VERSION 5.8 ;
BUSBITCHARS "[]" ;
DIVIDERCHAR "/" ;
UNITS
    DATABASE MICRONS 1000 ;
END UNITS

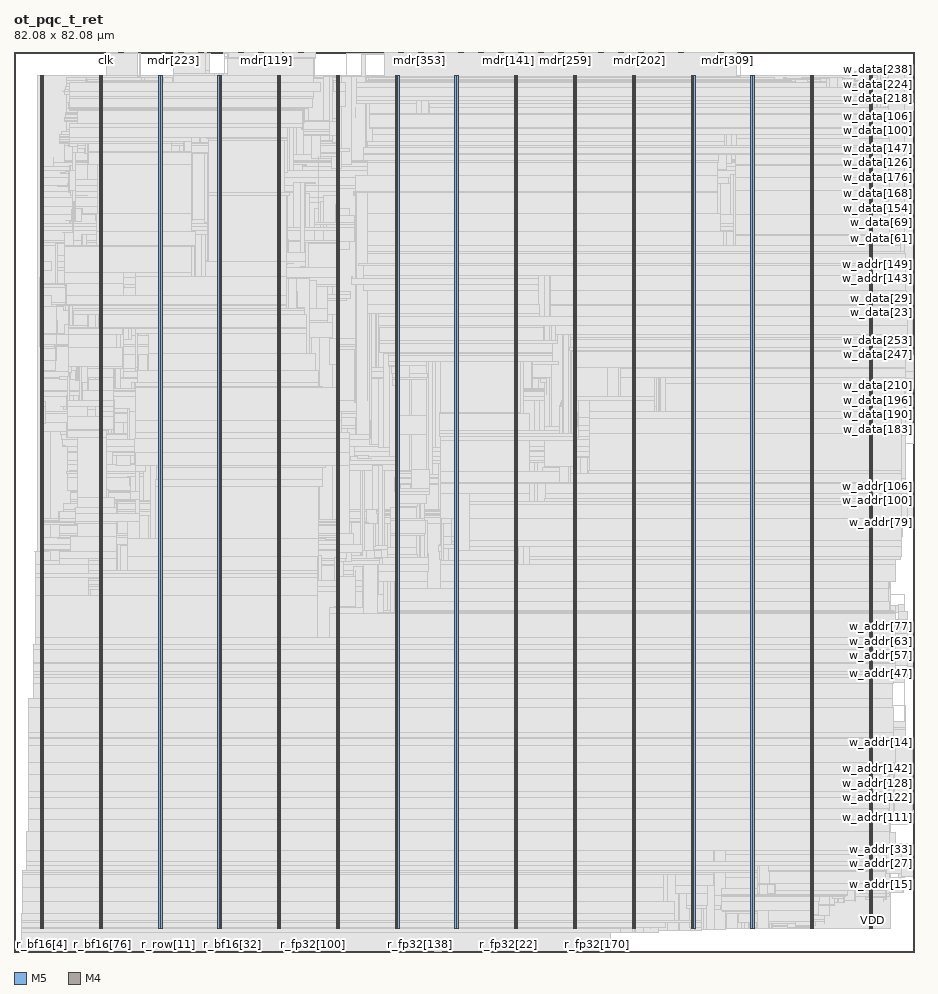
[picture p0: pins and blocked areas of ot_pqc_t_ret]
MACRO ot_pqc_t_ret
  FOREIGN ot_pqc_t_ret 0 0 ;
  CLASS BLOCK ;
  SIZE 82.08 BY 82.08 ;
  PIN clk
    DIRECTION INPUT ;
    USE SIGNAL ;
    PORT
      LAYER M5 ;
        RECT  8.4 81.996 8.424 82.08 ;
    END
  END clk
  PIN ga[0]
    DIRECTION OUTPUT ;
    USE SIGNAL ;
    PORT
      LAYER M4 ;
        RECT  81.996 16.08 82.08 16.104 ;
    END
  END ga[0]
  PIN ga[10]
    DIRECTION OUTPUT ;
    USE SIGNAL ;
    PORT
      LAYER M4 ;
        RECT  81.996 17.04 82.08 17.064 ;
    END
  END ga[10]
  PIN ga[11]
    DIRECTION OUTPUT ;
    USE SIGNAL ;
    PORT
      LAYER M4 ;
        RECT  81.996 17.136 82.08 17.16 ;
    END
  END ga[11]
  PIN ga[12]
    DIRECTION OUTPUT ;
    USE SIGNAL ;
    PORT
      LAYER M4 ;
        RECT  81.996 17.232 82.08 17.256 ;
    END
  END ga[12]
  PIN ga[13]
    DIRECTION OUTPUT ;
    USE SIGNAL ;
    PORT
      LAYER M4 ;
        RECT  81.996 17.328 82.08 17.352 ;
    END
  END ga[13]
  PIN ga[14]
    DIRECTION OUTPUT ;
    USE SIGNAL ;
    PORT
      LAYER M4 ;
        RECT  81.996 17.424 82.08 17.448 ;
    END
  END ga[14]
  PIN ga[15]
    DIRECTION OUTPUT ;
    USE SIGNAL ;
    PORT
      LAYER M4 ;
        RECT  81.996 17.52 82.08 17.544 ;
    END
  END ga[15]
  PIN ga[1]
    DIRECTION OUTPUT ;
    USE SIGNAL ;
    PORT
      LAYER M4 ;
        RECT  81.996 16.176 82.08 16.2 ;
    END
  END ga[1]
  PIN ga[2]
    DIRECTION OUTPUT ;
    USE SIGNAL ;
    PORT
      LAYER M4 ;
        RECT  81.996 16.272 82.08 16.296 ;
    END
  END ga[2]
  PIN ga[3]
    DIRECTION OUTPUT ;
    USE SIGNAL ;
    PORT
      LAYER M4 ;
        RECT  81.996 16.368 82.08 16.392 ;
    END
  END ga[3]
  PIN ga[4]
    DIRECTION OUTPUT ;
    USE SIGNAL ;
    PORT
      LAYER M4 ;
        RECT  81.996 16.464 82.08 16.488 ;
    END
  END ga[4]
  PIN ga[5]
    DIRECTION OUTPUT ;
    USE SIGNAL ;
    PORT
      LAYER M4 ;
        RECT  81.996 16.56 82.08 16.584 ;
    END
  END ga[5]
  PIN ga[6]
    DIRECTION OUTPUT ;
    USE SIGNAL ;
    PORT
      LAYER M4 ;
        RECT  81.996 16.656 82.08 16.68 ;
    END
  END ga[6]
  PIN ga[7]
    DIRECTION OUTPUT ;
    USE SIGNAL ;
    PORT
      LAYER M4 ;
        RECT  81.996 16.752 82.08 16.776 ;
    END
  END ga[7]
  PIN ga[8]
    DIRECTION OUTPUT ;
    USE SIGNAL ;
    PORT
      LAYER M4 ;
        RECT  81.996 16.848 82.08 16.872 ;
    END
  END ga[8]
  PIN ga[9]
    DIRECTION OUTPUT ;
    USE SIGNAL ;
    PORT
      LAYER M4 ;
        RECT  81.996 16.944 82.08 16.968 ;
    END
  END ga[9]
  PIN mdr[0]
    DIRECTION INPUT ;
    USE SIGNAL ;
    PORT
      LAYER M5 ;
        RECT  8.496 81.996 8.52 82.08 ;
    END
  END mdr[0]
  PIN mdr[100]
    DIRECTION INPUT ;
    USE SIGNAL ;
    PORT
      LAYER M5 ;
        RECT  21.168 81.996 21.192 82.08 ;
    END
  END mdr[100]
  PIN mdr[101]
    DIRECTION INPUT ;
    USE SIGNAL ;
    PORT
      LAYER M5 ;
        RECT  21.264 81.996 21.288 82.08 ;
    END
  END mdr[101]
  PIN mdr[102]
    DIRECTION INPUT ;
    USE SIGNAL ;
    PORT
      LAYER M5 ;
        RECT  21.36 81.996 21.384 82.08 ;
    END
  END mdr[102]
  PIN mdr[103]
    DIRECTION INPUT ;
    USE SIGNAL ;
    PORT
      LAYER M5 ;
        RECT  21.456 81.996 21.48 82.08 ;
    END
  END mdr[103]
  PIN mdr[104]
    DIRECTION INPUT ;
    USE SIGNAL ;
    PORT
      LAYER M5 ;
        RECT  21.552 81.996 21.576 82.08 ;
    END
  END mdr[104]
  PIN mdr[105]
    DIRECTION INPUT ;
    USE SIGNAL ;
    PORT
      LAYER M5 ;
        RECT  21.648 81.996 21.672 82.08 ;
    END
  END mdr[105]
  PIN mdr[106]
    DIRECTION INPUT ;
    USE SIGNAL ;
    PORT
      LAYER M5 ;
        RECT  21.744 81.996 21.768 82.08 ;
    END
  END mdr[106]
  PIN mdr[107]
    DIRECTION INPUT ;
    USE SIGNAL ;
    PORT
      LAYER M5 ;
        RECT  21.84 81.996 21.864 82.08 ;
    END
  END mdr[107]
  PIN mdr[108]
    DIRECTION INPUT ;
    USE SIGNAL ;
    PORT
      LAYER M5 ;
        RECT  21.936 81.996 21.96 82.08 ;
    END
  END mdr[108]
  PIN mdr[109]
    DIRECTION INPUT ;
    USE SIGNAL ;
    PORT
      LAYER M5 ;
        RECT  22.032 81.996 22.056 82.08 ;
    END
  END mdr[109]
  PIN mdr[10]
    DIRECTION INPUT ;
    USE SIGNAL ;
    PORT
      LAYER M5 ;
        RECT  9.456 81.996 9.48 82.08 ;
    END
  END mdr[10]
  PIN mdr[110]
    DIRECTION INPUT ;
    USE SIGNAL ;
    PORT
      LAYER M5 ;
        RECT  22.128 81.996 22.152 82.08 ;
    END
  END mdr[110]
  PIN mdr[111]
    DIRECTION INPUT ;
    USE SIGNAL ;
    PORT
      LAYER M5 ;
        RECT  22.224 81.996 22.248 82.08 ;
    END
  END mdr[111]
  PIN mdr[112]
    DIRECTION INPUT ;
    USE SIGNAL ;
    PORT
      LAYER M5 ;
        RECT  22.32 81.996 22.344 82.08 ;
    END
  END mdr[112]
  PIN mdr[113]
    DIRECTION INPUT ;
    USE SIGNAL ;
    PORT
      LAYER M5 ;
        RECT  22.416 81.996 22.44 82.08 ;
    END
  END mdr[113]
  PIN mdr[114]
    DIRECTION INPUT ;
    USE SIGNAL ;
    PORT
      LAYER M5 ;
        RECT  22.512 81.996 22.536 82.08 ;
    END
  END mdr[114]
  PIN mdr[115]
    DIRECTION INPUT ;
    USE SIGNAL ;
    PORT
      LAYER M5 ;
        RECT  22.608 81.996 22.632 82.08 ;
    END
  END mdr[115]
  PIN mdr[116]
    DIRECTION INPUT ;
    USE SIGNAL ;
    PORT
      LAYER M5 ;
        RECT  22.704 81.996 22.728 82.08 ;
    END
  END mdr[116]
  PIN mdr[117]
    DIRECTION INPUT ;
    USE SIGNAL ;
    PORT
      LAYER M5 ;
        RECT  22.8 81.996 22.824 82.08 ;
    END
  END mdr[117]
  PIN mdr[118]
    DIRECTION INPUT ;
    USE SIGNAL ;
    PORT
      LAYER M5 ;
        RECT  22.896 81.996 22.92 82.08 ;
    END
  END mdr[118]
  PIN mdr[119]
    DIRECTION INPUT ;
    USE SIGNAL ;
    PORT
      LAYER M5 ;
        RECT  22.992 81.996 23.016 82.08 ;
    END
  END mdr[119]
  PIN mdr[11]
    DIRECTION INPUT ;
    USE SIGNAL ;
    PORT
      LAYER M5 ;
        RECT  9.552 81.996 9.576 82.08 ;
    END
  END mdr[11]
  PIN mdr[120]
    DIRECTION INPUT ;
    USE SIGNAL ;
    PORT
      LAYER M5 ;
        RECT  23.088 81.996 23.112 82.08 ;
    END
  END mdr[120]
  PIN mdr[121]
    DIRECTION INPUT ;
    USE SIGNAL ;
    PORT
      LAYER M5 ;
        RECT  23.184 81.996 23.208 82.08 ;
    END
  END mdr[121]
  PIN mdr[122]
    DIRECTION INPUT ;
    USE SIGNAL ;
    PORT
      LAYER M5 ;
        RECT  23.28 81.996 23.304 82.08 ;
    END
  END mdr[122]
  PIN mdr[123]
    DIRECTION INPUT ;
    USE SIGNAL ;
    PORT
      LAYER M5 ;
        RECT  23.376 81.996 23.4 82.08 ;
    END
  END mdr[123]
  PIN mdr[124]
    DIRECTION INPUT ;
    USE SIGNAL ;
    PORT
      LAYER M5 ;
        RECT  23.472 81.996 23.496 82.08 ;
    END
  END mdr[124]
  PIN mdr[125]
    DIRECTION INPUT ;
    USE SIGNAL ;
    PORT
      LAYER M5 ;
        RECT  23.568 81.996 23.592 82.08 ;
    END
  END mdr[125]
  PIN mdr[126]
    DIRECTION INPUT ;
    USE SIGNAL ;
    PORT
      LAYER M5 ;
        RECT  23.664 81.996 23.688 82.08 ;
    END
  END mdr[126]
  PIN mdr[127]
    DIRECTION INPUT ;
    USE SIGNAL ;
    PORT
      LAYER M5 ;
        RECT  43.728 81.996 43.752 82.08 ;
    END
  END mdr[127]
  PIN mdr[128]
    DIRECTION INPUT ;
    USE SIGNAL ;
    PORT
      LAYER M5 ;
        RECT  43.824 81.996 43.848 82.08 ;
    END
  END mdr[128]
  PIN mdr[129]
    DIRECTION INPUT ;
    USE SIGNAL ;
    PORT
      LAYER M5 ;
        RECT  43.92 81.996 43.944 82.08 ;
    END
  END mdr[129]
  PIN mdr[12]
    DIRECTION INPUT ;
    USE SIGNAL ;
    PORT
      LAYER M5 ;
        RECT  9.648 81.996 9.672 82.08 ;
    END
  END mdr[12]
  PIN mdr[130]
    DIRECTION INPUT ;
    USE SIGNAL ;
    PORT
      LAYER M5 ;
        RECT  44.016 81.996 44.04 82.08 ;
    END
  END mdr[130]
  PIN mdr[131]
    DIRECTION INPUT ;
    USE SIGNAL ;
    PORT
      LAYER M5 ;
        RECT  44.112 81.996 44.136 82.08 ;
    END
  END mdr[131]
  PIN mdr[132]
    DIRECTION INPUT ;
    USE SIGNAL ;
    PORT
      LAYER M5 ;
        RECT  44.208 81.996 44.232 82.08 ;
    END
  END mdr[132]
  PIN mdr[133]
    DIRECTION INPUT ;
    USE SIGNAL ;
    PORT
      LAYER M5 ;
        RECT  44.304 81.996 44.328 82.08 ;
    END
  END mdr[133]
  PIN mdr[134]
    DIRECTION INPUT ;
    USE SIGNAL ;
    PORT
      LAYER M5 ;
        RECT  44.4 81.996 44.424 82.08 ;
    END
  END mdr[134]
  PIN mdr[135]
    DIRECTION INPUT ;
    USE SIGNAL ;
    PORT
      LAYER M5 ;
        RECT  44.496 81.996 44.52 82.08 ;
    END
  END mdr[135]
  PIN mdr[136]
    DIRECTION INPUT ;
    USE SIGNAL ;
    PORT
      LAYER M5 ;
        RECT  44.592 81.996 44.616 82.08 ;
    END
  END mdr[136]
  PIN mdr[137]
    DIRECTION INPUT ;
    USE SIGNAL ;
    PORT
      LAYER M5 ;
        RECT  44.688 81.996 44.712 82.08 ;
    END
  END mdr[137]
  PIN mdr[138]
    DIRECTION INPUT ;
    USE SIGNAL ;
    PORT
      LAYER M5 ;
        RECT  44.784 81.996 44.808 82.08 ;
    END
  END mdr[138]
  PIN mdr[139]
    DIRECTION INPUT ;
    USE SIGNAL ;
    PORT
      LAYER M5 ;
        RECT  44.88 81.996 44.904 82.08 ;
    END
  END mdr[139]
  PIN mdr[13]
    DIRECTION INPUT ;
    USE SIGNAL ;
    PORT
      LAYER M5 ;
        RECT  9.744 81.996 9.768 82.08 ;
    END
  END mdr[13]
  PIN mdr[140]
    DIRECTION INPUT ;
    USE SIGNAL ;
    PORT
      LAYER M5 ;
        RECT  44.976 81.996 45 82.08 ;
    END
  END mdr[140]
  PIN mdr[141]
    DIRECTION INPUT ;
    USE SIGNAL ;
    PORT
      LAYER M5 ;
        RECT  45.072 81.996 45.096 82.08 ;
    END
  END mdr[141]
  PIN mdr[142]
    DIRECTION INPUT ;
    USE SIGNAL ;
    PORT
      LAYER M5 ;
        RECT  45.168 81.996 45.192 82.08 ;
    END
  END mdr[142]
  PIN mdr[143]
    DIRECTION INPUT ;
    USE SIGNAL ;
    PORT
      LAYER M5 ;
        RECT  45.264 81.996 45.288 82.08 ;
    END
  END mdr[143]
  PIN mdr[144]
    DIRECTION INPUT ;
    USE SIGNAL ;
    PORT
      LAYER M5 ;
        RECT  45.36 81.996 45.384 82.08 ;
    END
  END mdr[144]
  PIN mdr[145]
    DIRECTION INPUT ;
    USE SIGNAL ;
    PORT
      LAYER M5 ;
        RECT  45.456 81.996 45.48 82.08 ;
    END
  END mdr[145]
  PIN mdr[146]
    DIRECTION INPUT ;
    USE SIGNAL ;
    PORT
      LAYER M5 ;
        RECT  45.552 81.996 45.576 82.08 ;
    END
  END mdr[146]
  PIN mdr[147]
    DIRECTION INPUT ;
    USE SIGNAL ;
    PORT
      LAYER M5 ;
        RECT  45.648 81.996 45.672 82.08 ;
    END
  END mdr[147]
  PIN mdr[148]
    DIRECTION INPUT ;
    USE SIGNAL ;
    PORT
      LAYER M5 ;
        RECT  45.744 81.996 45.768 82.08 ;
    END
  END mdr[148]
  PIN mdr[149]
    DIRECTION INPUT ;
    USE SIGNAL ;
    PORT
      LAYER M5 ;
        RECT  45.84 81.996 45.864 82.08 ;
    END
  END mdr[149]
  PIN mdr[14]
    DIRECTION INPUT ;
    USE SIGNAL ;
    PORT
      LAYER M5 ;
        RECT  9.84 81.996 9.864 82.08 ;
    END
  END mdr[14]
  PIN mdr[150]
    DIRECTION INPUT ;
    USE SIGNAL ;
    PORT
      LAYER M5 ;
        RECT  45.936 81.996 45.96 82.08 ;
    END
  END mdr[150]
  PIN mdr[151]
    DIRECTION INPUT ;
    USE SIGNAL ;
    PORT
      LAYER M5 ;
        RECT  46.032 81.996 46.056 82.08 ;
    END
  END mdr[151]
  PIN mdr[152]
    DIRECTION INPUT ;
    USE SIGNAL ;
    PORT
      LAYER M5 ;
        RECT  46.128 81.996 46.152 82.08 ;
    END
  END mdr[152]
  PIN mdr[153]
    DIRECTION INPUT ;
    USE SIGNAL ;
    PORT
      LAYER M5 ;
        RECT  46.224 81.996 46.248 82.08 ;
    END
  END mdr[153]
  PIN mdr[154]
    DIRECTION INPUT ;
    USE SIGNAL ;
    PORT
      LAYER M5 ;
        RECT  46.32 81.996 46.344 82.08 ;
    END
  END mdr[154]
  PIN mdr[155]
    DIRECTION INPUT ;
    USE SIGNAL ;
    PORT
      LAYER M5 ;
        RECT  46.416 81.996 46.44 82.08 ;
    END
  END mdr[155]
  PIN mdr[156]
    DIRECTION INPUT ;
    USE SIGNAL ;
    PORT
      LAYER M5 ;
        RECT  46.512 81.996 46.536 82.08 ;
    END
  END mdr[156]
  PIN mdr[157]
    DIRECTION INPUT ;
    USE SIGNAL ;
    PORT
      LAYER M5 ;
        RECT  46.608 81.996 46.632 82.08 ;
    END
  END mdr[157]
  PIN mdr[158]
    DIRECTION INPUT ;
    USE SIGNAL ;
    PORT
      LAYER M5 ;
        RECT  46.704 81.996 46.728 82.08 ;
    END
  END mdr[158]
  PIN mdr[159]
    DIRECTION INPUT ;
    USE SIGNAL ;
    PORT
      LAYER M5 ;
        RECT  46.8 81.996 46.824 82.08 ;
    END
  END mdr[159]
  PIN mdr[15]
    DIRECTION INPUT ;
    USE SIGNAL ;
    PORT
      LAYER M5 ;
        RECT  9.936 81.996 9.96 82.08 ;
    END
  END mdr[15]
  PIN mdr[160]
    DIRECTION INPUT ;
    USE SIGNAL ;
    PORT
      LAYER M5 ;
        RECT  46.896 81.996 46.92 82.08 ;
    END
  END mdr[160]
  PIN mdr[161]
    DIRECTION INPUT ;
    USE SIGNAL ;
    PORT
      LAYER M5 ;
        RECT  46.992 81.996 47.016 82.08 ;
    END
  END mdr[161]
  PIN mdr[162]
    DIRECTION INPUT ;
    USE SIGNAL ;
    PORT
      LAYER M5 ;
        RECT  47.088 81.996 47.112 82.08 ;
    END
  END mdr[162]
  PIN mdr[163]
    DIRECTION INPUT ;
    USE SIGNAL ;
    PORT
      LAYER M5 ;
        RECT  47.184 81.996 47.208 82.08 ;
    END
  END mdr[163]
  PIN mdr[164]
    DIRECTION INPUT ;
    USE SIGNAL ;
    PORT
      LAYER M5 ;
        RECT  47.28 81.996 47.304 82.08 ;
    END
  END mdr[164]
  PIN mdr[165]
    DIRECTION INPUT ;
    USE SIGNAL ;
    PORT
      LAYER M5 ;
        RECT  47.376 81.996 47.4 82.08 ;
    END
  END mdr[165]
  PIN mdr[166]
    DIRECTION INPUT ;
    USE SIGNAL ;
    PORT
      LAYER M5 ;
        RECT  47.472 81.996 47.496 82.08 ;
    END
  END mdr[166]
  PIN mdr[167]
    DIRECTION INPUT ;
    USE SIGNAL ;
    PORT
      LAYER M5 ;
        RECT  47.568 81.996 47.592 82.08 ;
    END
  END mdr[167]
  PIN mdr[168]
    DIRECTION INPUT ;
    USE SIGNAL ;
    PORT
      LAYER M5 ;
        RECT  47.664 81.996 47.688 82.08 ;
    END
  END mdr[168]
  PIN mdr[169]
    DIRECTION INPUT ;
    USE SIGNAL ;
    PORT
      LAYER M5 ;
        RECT  47.76 81.996 47.784 82.08 ;
    END
  END mdr[169]
  PIN mdr[16]
    DIRECTION INPUT ;
    USE SIGNAL ;
    PORT
      LAYER M5 ;
        RECT  10.032 81.996 10.056 82.08 ;
    END
  END mdr[16]
  PIN mdr[170]
    DIRECTION INPUT ;
    USE SIGNAL ;
    PORT
      LAYER M5 ;
        RECT  47.856 81.996 47.88 82.08 ;
    END
  END mdr[170]
  PIN mdr[171]
    DIRECTION INPUT ;
    USE SIGNAL ;
    PORT
      LAYER M5 ;
        RECT  47.952 81.996 47.976 82.08 ;
    END
  END mdr[171]
  PIN mdr[172]
    DIRECTION INPUT ;
    USE SIGNAL ;
    PORT
      LAYER M5 ;
        RECT  48.048 81.996 48.072 82.08 ;
    END
  END mdr[172]
  PIN mdr[173]
    DIRECTION INPUT ;
    USE SIGNAL ;
    PORT
      LAYER M5 ;
        RECT  48.144 81.996 48.168 82.08 ;
    END
  END mdr[173]
  PIN mdr[174]
    DIRECTION INPUT ;
    USE SIGNAL ;
    PORT
      LAYER M5 ;
        RECT  48.24 81.996 48.264 82.08 ;
    END
  END mdr[174]
  PIN mdr[175]
    DIRECTION INPUT ;
    USE SIGNAL ;
    PORT
      LAYER M5 ;
        RECT  48.336 81.996 48.36 82.08 ;
    END
  END mdr[175]
  PIN mdr[176]
    DIRECTION INPUT ;
    USE SIGNAL ;
    PORT
      LAYER M5 ;
        RECT  48.432 81.996 48.456 82.08 ;
    END
  END mdr[176]
  PIN mdr[177]
    DIRECTION INPUT ;
    USE SIGNAL ;
    PORT
      LAYER M5 ;
        RECT  48.528 81.996 48.552 82.08 ;
    END
  END mdr[177]
  PIN mdr[178]
    DIRECTION INPUT ;
    USE SIGNAL ;
    PORT
      LAYER M5 ;
        RECT  48.624 81.996 48.648 82.08 ;
    END
  END mdr[178]
  PIN mdr[179]
    DIRECTION INPUT ;
    USE SIGNAL ;
    PORT
      LAYER M5 ;
        RECT  48.72 81.996 48.744 82.08 ;
    END
  END mdr[179]
  PIN mdr[17]
    DIRECTION INPUT ;
    USE SIGNAL ;
    PORT
      LAYER M5 ;
        RECT  10.128 81.996 10.152 82.08 ;
    END
  END mdr[17]
  PIN mdr[180]
    DIRECTION INPUT ;
    USE SIGNAL ;
    PORT
      LAYER M5 ;
        RECT  48.816 81.996 48.84 82.08 ;
    END
  END mdr[180]
  PIN mdr[181]
    DIRECTION INPUT ;
    USE SIGNAL ;
    PORT
      LAYER M5 ;
        RECT  48.912 81.996 48.936 82.08 ;
    END
  END mdr[181]
  PIN mdr[182]
    DIRECTION INPUT ;
    USE SIGNAL ;
    PORT
      LAYER M5 ;
        RECT  49.008 81.996 49.032 82.08 ;
    END
  END mdr[182]
  PIN mdr[183]
    DIRECTION INPUT ;
    USE SIGNAL ;
    PORT
      LAYER M5 ;
        RECT  49.104 81.996 49.128 82.08 ;
    END
  END mdr[183]
  PIN mdr[184]
    DIRECTION INPUT ;
    USE SIGNAL ;
    PORT
      LAYER M5 ;
        RECT  49.2 81.996 49.224 82.08 ;
    END
  END mdr[184]
  PIN mdr[185]
    DIRECTION INPUT ;
    USE SIGNAL ;
    PORT
      LAYER M5 ;
        RECT  49.296 81.996 49.32 82.08 ;
    END
  END mdr[185]
  PIN mdr[186]
    DIRECTION INPUT ;
    USE SIGNAL ;
    PORT
      LAYER M5 ;
        RECT  49.392 81.996 49.416 82.08 ;
    END
  END mdr[186]
  PIN mdr[187]
    DIRECTION INPUT ;
    USE SIGNAL ;
    PORT
      LAYER M5 ;
        RECT  49.488 81.996 49.512 82.08 ;
    END
  END mdr[187]
  PIN mdr[188]
    DIRECTION INPUT ;
    USE SIGNAL ;
    PORT
      LAYER M5 ;
        RECT  49.584 81.996 49.608 82.08 ;
    END
  END mdr[188]
  PIN mdr[189]
    DIRECTION INPUT ;
    USE SIGNAL ;
    PORT
      LAYER M5 ;
        RECT  49.68 81.996 49.704 82.08 ;
    END
  END mdr[189]
  PIN mdr[18]
    DIRECTION INPUT ;
    USE SIGNAL ;
    PORT
      LAYER M5 ;
        RECT  10.224 81.996 10.248 82.08 ;
    END
  END mdr[18]
  PIN mdr[190]
    DIRECTION INPUT ;
    USE SIGNAL ;
    PORT
      LAYER M5 ;
        RECT  49.776 81.996 49.8 82.08 ;
    END
  END mdr[190]
  PIN mdr[191]
    DIRECTION INPUT ;
    USE SIGNAL ;
    PORT
      LAYER M5 ;
        RECT  56.016 81.996 56.04 82.08 ;
    END
  END mdr[191]
  PIN mdr[192]
    DIRECTION INPUT ;
    USE SIGNAL ;
    PORT
      LAYER M5 ;
        RECT  56.112 81.996 56.136 82.08 ;
    END
  END mdr[192]
  PIN mdr[193]
    DIRECTION INPUT ;
    USE SIGNAL ;
    PORT
      LAYER M5 ;
        RECT  56.208 81.996 56.232 82.08 ;
    END
  END mdr[193]
  PIN mdr[194]
    DIRECTION INPUT ;
    USE SIGNAL ;
    PORT
      LAYER M5 ;
        RECT  56.304 81.996 56.328 82.08 ;
    END
  END mdr[194]
  PIN mdr[195]
    DIRECTION INPUT ;
    USE SIGNAL ;
    PORT
      LAYER M5 ;
        RECT  56.4 81.996 56.424 82.08 ;
    END
  END mdr[195]
  PIN mdr[196]
    DIRECTION INPUT ;
    USE SIGNAL ;
    PORT
      LAYER M5 ;
        RECT  56.496 81.996 56.52 82.08 ;
    END
  END mdr[196]
  PIN mdr[197]
    DIRECTION INPUT ;
    USE SIGNAL ;
    PORT
      LAYER M5 ;
        RECT  56.592 81.996 56.616 82.08 ;
    END
  END mdr[197]
  PIN mdr[198]
    DIRECTION INPUT ;
    USE SIGNAL ;
    PORT
      LAYER M5 ;
        RECT  56.688 81.996 56.712 82.08 ;
    END
  END mdr[198]
  PIN mdr[199]
    DIRECTION INPUT ;
    USE SIGNAL ;
    PORT
      LAYER M5 ;
        RECT  56.784 81.996 56.808 82.08 ;
    END
  END mdr[199]
  PIN mdr[19]
    DIRECTION INPUT ;
    USE SIGNAL ;
    PORT
      LAYER M5 ;
        RECT  10.32 81.996 10.344 82.08 ;
    END
  END mdr[19]
  PIN mdr[1]
    DIRECTION INPUT ;
    USE SIGNAL ;
    PORT
      LAYER M5 ;
        RECT  8.592 81.996 8.616 82.08 ;
    END
  END mdr[1]
  PIN mdr[200]
    DIRECTION INPUT ;
    USE SIGNAL ;
    PORT
      LAYER M5 ;
        RECT  56.88 81.996 56.904 82.08 ;
    END
  END mdr[200]
  PIN mdr[201]
    DIRECTION INPUT ;
    USE SIGNAL ;
    PORT
      LAYER M5 ;
        RECT  56.976 81.996 57 82.08 ;
    END
  END mdr[201]
  PIN mdr[202]
    DIRECTION INPUT ;
    USE SIGNAL ;
    PORT
      LAYER M5 ;
        RECT  57.072 81.996 57.096 82.08 ;
    END
  END mdr[202]
  PIN mdr[203]
    DIRECTION INPUT ;
    USE SIGNAL ;
    PORT
      LAYER M5 ;
        RECT  57.168 81.996 57.192 82.08 ;
    END
  END mdr[203]
  PIN mdr[204]
    DIRECTION INPUT ;
    USE SIGNAL ;
    PORT
      LAYER M5 ;
        RECT  57.264 81.996 57.288 82.08 ;
    END
  END mdr[204]
  PIN mdr[205]
    DIRECTION INPUT ;
    USE SIGNAL ;
    PORT
      LAYER M5 ;
        RECT  57.36 81.996 57.384 82.08 ;
    END
  END mdr[205]
  PIN mdr[206]
    DIRECTION INPUT ;
    USE SIGNAL ;
    PORT
      LAYER M5 ;
        RECT  57.456 81.996 57.48 82.08 ;
    END
  END mdr[206]
  PIN mdr[207]
    DIRECTION INPUT ;
    USE SIGNAL ;
    PORT
      LAYER M5 ;
        RECT  57.552 81.996 57.576 82.08 ;
    END
  END mdr[207]
  PIN mdr[208]
    DIRECTION INPUT ;
    USE SIGNAL ;
    PORT
      LAYER M5 ;
        RECT  57.648 81.996 57.672 82.08 ;
    END
  END mdr[208]
  PIN mdr[209]
    DIRECTION INPUT ;
    USE SIGNAL ;
    PORT
      LAYER M5 ;
        RECT  57.744 81.996 57.768 82.08 ;
    END
  END mdr[209]
  PIN mdr[20]
    DIRECTION INPUT ;
    USE SIGNAL ;
    PORT
      LAYER M5 ;
        RECT  10.416 81.996 10.44 82.08 ;
    END
  END mdr[20]
  PIN mdr[210]
    DIRECTION INPUT ;
    USE SIGNAL ;
    PORT
      LAYER M5 ;
        RECT  57.84 81.996 57.864 82.08 ;
    END
  END mdr[210]
  PIN mdr[211]
    DIRECTION INPUT ;
    USE SIGNAL ;
    PORT
      LAYER M5 ;
        RECT  57.936 81.996 57.96 82.08 ;
    END
  END mdr[211]
  PIN mdr[212]
    DIRECTION INPUT ;
    USE SIGNAL ;
    PORT
      LAYER M5 ;
        RECT  58.032 81.996 58.056 82.08 ;
    END
  END mdr[212]
  PIN mdr[213]
    DIRECTION INPUT ;
    USE SIGNAL ;
    PORT
      LAYER M5 ;
        RECT  58.128 81.996 58.152 82.08 ;
    END
  END mdr[213]
  PIN mdr[214]
    DIRECTION INPUT ;
    USE SIGNAL ;
    PORT
      LAYER M5 ;
        RECT  58.224 81.996 58.248 82.08 ;
    END
  END mdr[214]
  PIN mdr[215]
    DIRECTION INPUT ;
    USE SIGNAL ;
    PORT
      LAYER M5 ;
        RECT  58.32 81.996 58.344 82.08 ;
    END
  END mdr[215]
  PIN mdr[216]
    DIRECTION INPUT ;
    USE SIGNAL ;
    PORT
      LAYER M5 ;
        RECT  58.416 81.996 58.44 82.08 ;
    END
  END mdr[216]
  PIN mdr[217]
    DIRECTION INPUT ;
    USE SIGNAL ;
    PORT
      LAYER M5 ;
        RECT  58.512 81.996 58.536 82.08 ;
    END
  END mdr[217]
  PIN mdr[218]
    DIRECTION INPUT ;
    USE SIGNAL ;
    PORT
      LAYER M5 ;
        RECT  58.608 81.996 58.632 82.08 ;
    END
  END mdr[218]
  PIN mdr[219]
    DIRECTION INPUT ;
    USE SIGNAL ;
    PORT
      LAYER M5 ;
        RECT  58.704 81.996 58.728 82.08 ;
    END
  END mdr[219]
  PIN mdr[21]
    DIRECTION INPUT ;
    USE SIGNAL ;
    PORT
      LAYER M5 ;
        RECT  10.512 81.996 10.536 82.08 ;
    END
  END mdr[21]
  PIN mdr[220]
    DIRECTION INPUT ;
    USE SIGNAL ;
    PORT
      LAYER M5 ;
        RECT  58.8 81.996 58.824 82.08 ;
    END
  END mdr[220]
  PIN mdr[221]
    DIRECTION INPUT ;
    USE SIGNAL ;
    PORT
      LAYER M5 ;
        RECT  58.896 81.996 58.92 82.08 ;
    END
  END mdr[221]
  PIN mdr[222]
    DIRECTION INPUT ;
    USE SIGNAL ;
    PORT
      LAYER M5 ;
        RECT  58.992 81.996 59.016 82.08 ;
    END
  END mdr[222]
  PIN mdr[223]
    DIRECTION INPUT ;
    USE SIGNAL ;
    PORT
      LAYER M5 ;
        RECT  14.544 81.996 14.568 82.08 ;
    END
  END mdr[223]
  PIN mdr[224]
    DIRECTION INPUT ;
    USE SIGNAL ;
    PORT
      LAYER M5 ;
        RECT  14.64 81.996 14.664 82.08 ;
    END
  END mdr[224]
  PIN mdr[225]
    DIRECTION INPUT ;
    USE SIGNAL ;
    PORT
      LAYER M5 ;
        RECT  14.736 81.996 14.76 82.08 ;
    END
  END mdr[225]
  PIN mdr[226]
    DIRECTION INPUT ;
    USE SIGNAL ;
    PORT
      LAYER M5 ;
        RECT  14.832 81.996 14.856 82.08 ;
    END
  END mdr[226]
  PIN mdr[227]
    DIRECTION INPUT ;
    USE SIGNAL ;
    PORT
      LAYER M5 ;
        RECT  14.928 81.996 14.952 82.08 ;
    END
  END mdr[227]
  PIN mdr[228]
    DIRECTION INPUT ;
    USE SIGNAL ;
    PORT
      LAYER M5 ;
        RECT  15.024 81.996 15.048 82.08 ;
    END
  END mdr[228]
  PIN mdr[229]
    DIRECTION INPUT ;
    USE SIGNAL ;
    PORT
      LAYER M5 ;
        RECT  15.12 81.996 15.144 82.08 ;
    END
  END mdr[229]
  PIN mdr[22]
    DIRECTION INPUT ;
    USE SIGNAL ;
    PORT
      LAYER M5 ;
        RECT  10.608 81.996 10.632 82.08 ;
    END
  END mdr[22]
  PIN mdr[230]
    DIRECTION INPUT ;
    USE SIGNAL ;
    PORT
      LAYER M5 ;
        RECT  15.216 81.996 15.24 82.08 ;
    END
  END mdr[230]
  PIN mdr[231]
    DIRECTION INPUT ;
    USE SIGNAL ;
    PORT
      LAYER M5 ;
        RECT  15.312 81.996 15.336 82.08 ;
    END
  END mdr[231]
  PIN mdr[232]
    DIRECTION INPUT ;
    USE SIGNAL ;
    PORT
      LAYER M5 ;
        RECT  15.408 81.996 15.432 82.08 ;
    END
  END mdr[232]
  PIN mdr[233]
    DIRECTION INPUT ;
    USE SIGNAL ;
    PORT
      LAYER M5 ;
        RECT  15.504 81.996 15.528 82.08 ;
    END
  END mdr[233]
  PIN mdr[234]
    DIRECTION INPUT ;
    USE SIGNAL ;
    PORT
      LAYER M5 ;
        RECT  15.6 81.996 15.624 82.08 ;
    END
  END mdr[234]
  PIN mdr[235]
    DIRECTION INPUT ;
    USE SIGNAL ;
    PORT
      LAYER M5 ;
        RECT  15.696 81.996 15.72 82.08 ;
    END
  END mdr[235]
  PIN mdr[236]
    DIRECTION INPUT ;
    USE SIGNAL ;
    PORT
      LAYER M5 ;
        RECT  15.792 81.996 15.816 82.08 ;
    END
  END mdr[236]
  PIN mdr[237]
    DIRECTION INPUT ;
    USE SIGNAL ;
    PORT
      LAYER M5 ;
        RECT  15.888 81.996 15.912 82.08 ;
    END
  END mdr[237]
  PIN mdr[238]
    DIRECTION INPUT ;
    USE SIGNAL ;
    PORT
      LAYER M5 ;
        RECT  15.984 81.996 16.008 82.08 ;
    END
  END mdr[238]
  PIN mdr[239]
    DIRECTION INPUT ;
    USE SIGNAL ;
    PORT
      LAYER M5 ;
        RECT  16.08 81.996 16.104 82.08 ;
    END
  END mdr[239]
  PIN mdr[23]
    DIRECTION INPUT ;
    USE SIGNAL ;
    PORT
      LAYER M5 ;
        RECT  10.704 81.996 10.728 82.08 ;
    END
  END mdr[23]
  PIN mdr[240]
    DIRECTION INPUT ;
    USE SIGNAL ;
    PORT
      LAYER M5 ;
        RECT  16.176 81.996 16.2 82.08 ;
    END
  END mdr[240]
  PIN mdr[241]
    DIRECTION INPUT ;
    USE SIGNAL ;
    PORT
      LAYER M5 ;
        RECT  16.272 81.996 16.296 82.08 ;
    END
  END mdr[241]
  PIN mdr[242]
    DIRECTION INPUT ;
    USE SIGNAL ;
    PORT
      LAYER M5 ;
        RECT  16.368 81.996 16.392 82.08 ;
    END
  END mdr[242]
  PIN mdr[243]
    DIRECTION INPUT ;
    USE SIGNAL ;
    PORT
      LAYER M5 ;
        RECT  16.464 81.996 16.488 82.08 ;
    END
  END mdr[243]
  PIN mdr[244]
    DIRECTION INPUT ;
    USE SIGNAL ;
    PORT
      LAYER M5 ;
        RECT  16.56 81.996 16.584 82.08 ;
    END
  END mdr[244]
  PIN mdr[245]
    DIRECTION INPUT ;
    USE SIGNAL ;
    PORT
      LAYER M5 ;
        RECT  16.656 81.996 16.68 82.08 ;
    END
  END mdr[245]
  PIN mdr[246]
    DIRECTION INPUT ;
    USE SIGNAL ;
    PORT
      LAYER M5 ;
        RECT  16.752 81.996 16.776 82.08 ;
    END
  END mdr[246]
  PIN mdr[247]
    DIRECTION INPUT ;
    USE SIGNAL ;
    PORT
      LAYER M5 ;
        RECT  16.848 81.996 16.872 82.08 ;
    END
  END mdr[247]
  PIN mdr[248]
    DIRECTION INPUT ;
    USE SIGNAL ;
    PORT
      LAYER M5 ;
        RECT  16.944 81.996 16.968 82.08 ;
    END
  END mdr[248]
  PIN mdr[249]
    DIRECTION INPUT ;
    USE SIGNAL ;
    PORT
      LAYER M5 ;
        RECT  17.04 81.996 17.064 82.08 ;
    END
  END mdr[249]
  PIN mdr[24]
    DIRECTION INPUT ;
    USE SIGNAL ;
    PORT
      LAYER M5 ;
        RECT  10.8 81.996 10.824 82.08 ;
    END
  END mdr[24]
  PIN mdr[250]
    DIRECTION INPUT ;
    USE SIGNAL ;
    PORT
      LAYER M5 ;
        RECT  17.136 81.996 17.16 82.08 ;
    END
  END mdr[250]
  PIN mdr[251]
    DIRECTION INPUT ;
    USE SIGNAL ;
    PORT
      LAYER M5 ;
        RECT  17.232 81.996 17.256 82.08 ;
    END
  END mdr[251]
  PIN mdr[252]
    DIRECTION INPUT ;
    USE SIGNAL ;
    PORT
      LAYER M5 ;
        RECT  17.328 81.996 17.352 82.08 ;
    END
  END mdr[252]
  PIN mdr[253]
    DIRECTION INPUT ;
    USE SIGNAL ;
    PORT
      LAYER M5 ;
        RECT  17.424 81.996 17.448 82.08 ;
    END
  END mdr[253]
  PIN mdr[254]
    DIRECTION INPUT ;
    USE SIGNAL ;
    PORT
      LAYER M5 ;
        RECT  17.52 81.996 17.544 82.08 ;
    END
  END mdr[254]
  PIN mdr[255]
    DIRECTION INPUT ;
    USE SIGNAL ;
    PORT
      LAYER M5 ;
        RECT  49.872 81.996 49.896 82.08 ;
    END
  END mdr[255]
  PIN mdr[256]
    DIRECTION INPUT ;
    USE SIGNAL ;
    PORT
      LAYER M5 ;
        RECT  49.968 81.996 49.992 82.08 ;
    END
  END mdr[256]
  PIN mdr[257]
    DIRECTION INPUT ;
    USE SIGNAL ;
    PORT
      LAYER M5 ;
        RECT  50.064 81.996 50.088 82.08 ;
    END
  END mdr[257]
  PIN mdr[258]
    DIRECTION INPUT ;
    USE SIGNAL ;
    PORT
      LAYER M5 ;
        RECT  50.16 81.996 50.184 82.08 ;
    END
  END mdr[258]
  PIN mdr[259]
    DIRECTION INPUT ;
    USE SIGNAL ;
    PORT
      LAYER M5 ;
        RECT  50.256 81.996 50.28 82.08 ;
    END
  END mdr[259]
  PIN mdr[25]
    DIRECTION INPUT ;
    USE SIGNAL ;
    PORT
      LAYER M5 ;
        RECT  10.896 81.996 10.92 82.08 ;
    END
  END mdr[25]
  PIN mdr[260]
    DIRECTION INPUT ;
    USE SIGNAL ;
    PORT
      LAYER M5 ;
        RECT  50.352 81.996 50.376 82.08 ;
    END
  END mdr[260]
  PIN mdr[261]
    DIRECTION INPUT ;
    USE SIGNAL ;
    PORT
      LAYER M5 ;
        RECT  50.448 81.996 50.472 82.08 ;
    END
  END mdr[261]
  PIN mdr[262]
    DIRECTION INPUT ;
    USE SIGNAL ;
    PORT
      LAYER M5 ;
        RECT  50.544 81.996 50.568 82.08 ;
    END
  END mdr[262]
  PIN mdr[263]
    DIRECTION INPUT ;
    USE SIGNAL ;
    PORT
      LAYER M5 ;
        RECT  50.64 81.996 50.664 82.08 ;
    END
  END mdr[263]
  PIN mdr[264]
    DIRECTION INPUT ;
    USE SIGNAL ;
    PORT
      LAYER M5 ;
        RECT  50.736 81.996 50.76 82.08 ;
    END
  END mdr[264]
  PIN mdr[265]
    DIRECTION INPUT ;
    USE SIGNAL ;
    PORT
      LAYER M5 ;
        RECT  50.832 81.996 50.856 82.08 ;
    END
  END mdr[265]
  PIN mdr[266]
    DIRECTION INPUT ;
    USE SIGNAL ;
    PORT
      LAYER M5 ;
        RECT  50.928 81.996 50.952 82.08 ;
    END
  END mdr[266]
  PIN mdr[267]
    DIRECTION INPUT ;
    USE SIGNAL ;
    PORT
      LAYER M5 ;
        RECT  51.024 81.996 51.048 82.08 ;
    END
  END mdr[267]
  PIN mdr[268]
    DIRECTION INPUT ;
    USE SIGNAL ;
    PORT
      LAYER M5 ;
        RECT  51.12 81.996 51.144 82.08 ;
    END
  END mdr[268]
  PIN mdr[269]
    DIRECTION INPUT ;
    USE SIGNAL ;
    PORT
      LAYER M5 ;
        RECT  51.216 81.996 51.24 82.08 ;
    END
  END mdr[269]
  PIN mdr[26]
    DIRECTION INPUT ;
    USE SIGNAL ;
    PORT
      LAYER M5 ;
        RECT  10.992 81.996 11.016 82.08 ;
    END
  END mdr[26]
  PIN mdr[270]
    DIRECTION INPUT ;
    USE SIGNAL ;
    PORT
      LAYER M5 ;
        RECT  51.312 81.996 51.336 82.08 ;
    END
  END mdr[270]
  PIN mdr[271]
    DIRECTION INPUT ;
    USE SIGNAL ;
    PORT
      LAYER M5 ;
        RECT  51.408 81.996 51.432 82.08 ;
    END
  END mdr[271]
  PIN mdr[272]
    DIRECTION INPUT ;
    USE SIGNAL ;
    PORT
      LAYER M5 ;
        RECT  51.504 81.996 51.528 82.08 ;
    END
  END mdr[272]
  PIN mdr[273]
    DIRECTION INPUT ;
    USE SIGNAL ;
    PORT
      LAYER M5 ;
        RECT  51.6 81.996 51.624 82.08 ;
    END
  END mdr[273]
  PIN mdr[274]
    DIRECTION INPUT ;
    USE SIGNAL ;
    PORT
      LAYER M5 ;
        RECT  51.696 81.996 51.72 82.08 ;
    END
  END mdr[274]
  PIN mdr[275]
    DIRECTION INPUT ;
    USE SIGNAL ;
    PORT
      LAYER M5 ;
        RECT  51.792 81.996 51.816 82.08 ;
    END
  END mdr[275]
  PIN mdr[276]
    DIRECTION INPUT ;
    USE SIGNAL ;
    PORT
      LAYER M5 ;
        RECT  51.888 81.996 51.912 82.08 ;
    END
  END mdr[276]
  PIN mdr[277]
    DIRECTION INPUT ;
    USE SIGNAL ;
    PORT
      LAYER M5 ;
        RECT  51.984 81.996 52.008 82.08 ;
    END
  END mdr[277]
  PIN mdr[278]
    DIRECTION INPUT ;
    USE SIGNAL ;
    PORT
      LAYER M5 ;
        RECT  52.08 81.996 52.104 82.08 ;
    END
  END mdr[278]
  PIN mdr[279]
    DIRECTION INPUT ;
    USE SIGNAL ;
    PORT
      LAYER M5 ;
        RECT  52.176 81.996 52.2 82.08 ;
    END
  END mdr[279]
  PIN mdr[27]
    DIRECTION INPUT ;
    USE SIGNAL ;
    PORT
      LAYER M5 ;
        RECT  11.088 81.996 11.112 82.08 ;
    END
  END mdr[27]
  PIN mdr[280]
    DIRECTION INPUT ;
    USE SIGNAL ;
    PORT
      LAYER M5 ;
        RECT  52.272 81.996 52.296 82.08 ;
    END
  END mdr[280]
  PIN mdr[281]
    DIRECTION INPUT ;
    USE SIGNAL ;
    PORT
      LAYER M5 ;
        RECT  52.368 81.996 52.392 82.08 ;
    END
  END mdr[281]
  PIN mdr[282]
    DIRECTION INPUT ;
    USE SIGNAL ;
    PORT
      LAYER M5 ;
        RECT  52.464 81.996 52.488 82.08 ;
    END
  END mdr[282]
  PIN mdr[283]
    DIRECTION INPUT ;
    USE SIGNAL ;
    PORT
      LAYER M5 ;
        RECT  52.56 81.996 52.584 82.08 ;
    END
  END mdr[283]
  PIN mdr[284]
    DIRECTION INPUT ;
    USE SIGNAL ;
    PORT
      LAYER M5 ;
        RECT  52.656 81.996 52.68 82.08 ;
    END
  END mdr[284]
  PIN mdr[285]
    DIRECTION INPUT ;
    USE SIGNAL ;
    PORT
      LAYER M5 ;
        RECT  52.752 81.996 52.776 82.08 ;
    END
  END mdr[285]
  PIN mdr[286]
    DIRECTION INPUT ;
    USE SIGNAL ;
    PORT
      LAYER M5 ;
        RECT  52.848 81.996 52.872 82.08 ;
    END
  END mdr[286]
  PIN mdr[287]
    DIRECTION INPUT ;
    USE SIGNAL ;
    PORT
      LAYER M5 ;
        RECT  62.928 81.996 62.952 82.08 ;
    END
  END mdr[287]
  PIN mdr[288]
    DIRECTION INPUT ;
    USE SIGNAL ;
    PORT
      LAYER M5 ;
        RECT  63.024 81.996 63.048 82.08 ;
    END
  END mdr[288]
  PIN mdr[289]
    DIRECTION INPUT ;
    USE SIGNAL ;
    PORT
      LAYER M5 ;
        RECT  63.12 81.996 63.144 82.08 ;
    END
  END mdr[289]
  PIN mdr[28]
    DIRECTION INPUT ;
    USE SIGNAL ;
    PORT
      LAYER M5 ;
        RECT  11.184 81.996 11.208 82.08 ;
    END
  END mdr[28]
  PIN mdr[290]
    DIRECTION INPUT ;
    USE SIGNAL ;
    PORT
      LAYER M5 ;
        RECT  63.216 81.996 63.24 82.08 ;
    END
  END mdr[290]
  PIN mdr[291]
    DIRECTION INPUT ;
    USE SIGNAL ;
    PORT
      LAYER M5 ;
        RECT  63.312 81.996 63.336 82.08 ;
    END
  END mdr[291]
  PIN mdr[292]
    DIRECTION INPUT ;
    USE SIGNAL ;
    PORT
      LAYER M5 ;
        RECT  63.408 81.996 63.432 82.08 ;
    END
  END mdr[292]
  PIN mdr[293]
    DIRECTION INPUT ;
    USE SIGNAL ;
    PORT
      LAYER M5 ;
        RECT  63.504 81.996 63.528 82.08 ;
    END
  END mdr[293]
  PIN mdr[294]
    DIRECTION INPUT ;
    USE SIGNAL ;
    PORT
      LAYER M5 ;
        RECT  63.6 81.996 63.624 82.08 ;
    END
  END mdr[294]
  PIN mdr[295]
    DIRECTION INPUT ;
    USE SIGNAL ;
    PORT
      LAYER M5 ;
        RECT  63.696 81.996 63.72 82.08 ;
    END
  END mdr[295]
  PIN mdr[296]
    DIRECTION INPUT ;
    USE SIGNAL ;
    PORT
      LAYER M5 ;
        RECT  63.792 81.996 63.816 82.08 ;
    END
  END mdr[296]
  PIN mdr[297]
    DIRECTION INPUT ;
    USE SIGNAL ;
    PORT
      LAYER M5 ;
        RECT  63.888 81.996 63.912 82.08 ;
    END
  END mdr[297]
  PIN mdr[298]
    DIRECTION INPUT ;
    USE SIGNAL ;
    PORT
      LAYER M5 ;
        RECT  63.984 81.996 64.008 82.08 ;
    END
  END mdr[298]
  PIN mdr[299]
    DIRECTION INPUT ;
    USE SIGNAL ;
    PORT
      LAYER M5 ;
        RECT  64.08 81.996 64.104 82.08 ;
    END
  END mdr[299]
  PIN mdr[29]
    DIRECTION INPUT ;
    USE SIGNAL ;
    PORT
      LAYER M5 ;
        RECT  11.28 81.996 11.304 82.08 ;
    END
  END mdr[29]
  PIN mdr[2]
    DIRECTION INPUT ;
    USE SIGNAL ;
    PORT
      LAYER M5 ;
        RECT  8.688 81.996 8.712 82.08 ;
    END
  END mdr[2]
  PIN mdr[300]
    DIRECTION INPUT ;
    USE SIGNAL ;
    PORT
      LAYER M5 ;
        RECT  64.176 81.996 64.2 82.08 ;
    END
  END mdr[300]
  PIN mdr[301]
    DIRECTION INPUT ;
    USE SIGNAL ;
    PORT
      LAYER M5 ;
        RECT  64.272 81.996 64.296 82.08 ;
    END
  END mdr[301]
  PIN mdr[302]
    DIRECTION INPUT ;
    USE SIGNAL ;
    PORT
      LAYER M5 ;
        RECT  64.368 81.996 64.392 82.08 ;
    END
  END mdr[302]
  PIN mdr[303]
    DIRECTION INPUT ;
    USE SIGNAL ;
    PORT
      LAYER M5 ;
        RECT  64.464 81.996 64.488 82.08 ;
    END
  END mdr[303]
  PIN mdr[304]
    DIRECTION INPUT ;
    USE SIGNAL ;
    PORT
      LAYER M5 ;
        RECT  64.56 81.996 64.584 82.08 ;
    END
  END mdr[304]
  PIN mdr[305]
    DIRECTION INPUT ;
    USE SIGNAL ;
    PORT
      LAYER M5 ;
        RECT  64.656 81.996 64.68 82.08 ;
    END
  END mdr[305]
  PIN mdr[306]
    DIRECTION INPUT ;
    USE SIGNAL ;
    PORT
      LAYER M5 ;
        RECT  64.752 81.996 64.776 82.08 ;
    END
  END mdr[306]
  PIN mdr[307]
    DIRECTION INPUT ;
    USE SIGNAL ;
    PORT
      LAYER M5 ;
        RECT  64.848 81.996 64.872 82.08 ;
    END
  END mdr[307]
  PIN mdr[308]
    DIRECTION INPUT ;
    USE SIGNAL ;
    PORT
      LAYER M5 ;
        RECT  64.944 81.996 64.968 82.08 ;
    END
  END mdr[308]
  PIN mdr[309]
    DIRECTION INPUT ;
    USE SIGNAL ;
    PORT
      LAYER M5 ;
        RECT  65.04 81.996 65.064 82.08 ;
    END
  END mdr[309]
  PIN mdr[30]
    DIRECTION INPUT ;
    USE SIGNAL ;
    PORT
      LAYER M5 ;
        RECT  11.376 81.996 11.4 82.08 ;
    END
  END mdr[30]
  PIN mdr[310]
    DIRECTION INPUT ;
    USE SIGNAL ;
    PORT
      LAYER M5 ;
        RECT  65.136 81.996 65.16 82.08 ;
    END
  END mdr[310]
  PIN mdr[311]
    DIRECTION INPUT ;
    USE SIGNAL ;
    PORT
      LAYER M5 ;
        RECT  65.232 81.996 65.256 82.08 ;
    END
  END mdr[311]
  PIN mdr[312]
    DIRECTION INPUT ;
    USE SIGNAL ;
    PORT
      LAYER M5 ;
        RECT  65.328 81.996 65.352 82.08 ;
    END
  END mdr[312]
  PIN mdr[313]
    DIRECTION INPUT ;
    USE SIGNAL ;
    PORT
      LAYER M5 ;
        RECT  65.424 81.996 65.448 82.08 ;
    END
  END mdr[313]
  PIN mdr[314]
    DIRECTION INPUT ;
    USE SIGNAL ;
    PORT
      LAYER M5 ;
        RECT  65.52 81.996 65.544 82.08 ;
    END
  END mdr[314]
  PIN mdr[315]
    DIRECTION INPUT ;
    USE SIGNAL ;
    PORT
      LAYER M5 ;
        RECT  65.616 81.996 65.64 82.08 ;
    END
  END mdr[315]
  PIN mdr[316]
    DIRECTION INPUT ;
    USE SIGNAL ;
    PORT
      LAYER M5 ;
        RECT  65.712 81.996 65.736 82.08 ;
    END
  END mdr[316]
  PIN mdr[317]
    DIRECTION INPUT ;
    USE SIGNAL ;
    PORT
      LAYER M5 ;
        RECT  65.808 81.996 65.832 82.08 ;
    END
  END mdr[317]
  PIN mdr[318]
    DIRECTION INPUT ;
    USE SIGNAL ;
    PORT
      LAYER M5 ;
        RECT  65.904 81.996 65.928 82.08 ;
    END
  END mdr[318]
  PIN mdr[319]
    DIRECTION INPUT ;
    USE SIGNAL ;
    PORT
      LAYER M5 ;
        RECT  24.528 81.996 24.552 82.08 ;
    END
  END mdr[319]
  PIN mdr[31]
    DIRECTION INPUT ;
    USE SIGNAL ;
    PORT
      LAYER M5 ;
        RECT  52.944 81.996 52.968 82.08 ;
    END
  END mdr[31]
  PIN mdr[320]
    DIRECTION INPUT ;
    USE SIGNAL ;
    PORT
      LAYER M5 ;
        RECT  24.624 81.996 24.648 82.08 ;
    END
  END mdr[320]
  PIN mdr[321]
    DIRECTION INPUT ;
    USE SIGNAL ;
    PORT
      LAYER M5 ;
        RECT  24.72 81.996 24.744 82.08 ;
    END
  END mdr[321]
  PIN mdr[322]
    DIRECTION INPUT ;
    USE SIGNAL ;
    PORT
      LAYER M5 ;
        RECT  24.816 81.996 24.84 82.08 ;
    END
  END mdr[322]
  PIN mdr[323]
    DIRECTION INPUT ;
    USE SIGNAL ;
    PORT
      LAYER M5 ;
        RECT  24.912 81.996 24.936 82.08 ;
    END
  END mdr[323]
  PIN mdr[324]
    DIRECTION INPUT ;
    USE SIGNAL ;
    PORT
      LAYER M5 ;
        RECT  25.008 81.996 25.032 82.08 ;
    END
  END mdr[324]
  PIN mdr[325]
    DIRECTION INPUT ;
    USE SIGNAL ;
    PORT
      LAYER M5 ;
        RECT  25.104 81.996 25.128 82.08 ;
    END
  END mdr[325]
  PIN mdr[326]
    DIRECTION INPUT ;
    USE SIGNAL ;
    PORT
      LAYER M5 ;
        RECT  25.2 81.996 25.224 82.08 ;
    END
  END mdr[326]
  PIN mdr[327]
    DIRECTION INPUT ;
    USE SIGNAL ;
    PORT
      LAYER M5 ;
        RECT  25.296 81.996 25.32 82.08 ;
    END
  END mdr[327]
  PIN mdr[328]
    DIRECTION INPUT ;
    USE SIGNAL ;
    PORT
      LAYER M5 ;
        RECT  25.392 81.996 25.416 82.08 ;
    END
  END mdr[328]
  PIN mdr[329]
    DIRECTION INPUT ;
    USE SIGNAL ;
    PORT
      LAYER M5 ;
        RECT  25.488 81.996 25.512 82.08 ;
    END
  END mdr[329]
  PIN mdr[32]
    DIRECTION INPUT ;
    USE SIGNAL ;
    PORT
      LAYER M5 ;
        RECT  53.04 81.996 53.064 82.08 ;
    END
  END mdr[32]
  PIN mdr[330]
    DIRECTION INPUT ;
    USE SIGNAL ;
    PORT
      LAYER M5 ;
        RECT  25.584 81.996 25.608 82.08 ;
    END
  END mdr[330]
  PIN mdr[331]
    DIRECTION INPUT ;
    USE SIGNAL ;
    PORT
      LAYER M5 ;
        RECT  25.68 81.996 25.704 82.08 ;
    END
  END mdr[331]
  PIN mdr[332]
    DIRECTION INPUT ;
    USE SIGNAL ;
    PORT
      LAYER M5 ;
        RECT  25.776 81.996 25.8 82.08 ;
    END
  END mdr[332]
  PIN mdr[333]
    DIRECTION INPUT ;
    USE SIGNAL ;
    PORT
      LAYER M5 ;
        RECT  25.872 81.996 25.896 82.08 ;
    END
  END mdr[333]
  PIN mdr[334]
    DIRECTION INPUT ;
    USE SIGNAL ;
    PORT
      LAYER M5 ;
        RECT  25.968 81.996 25.992 82.08 ;
    END
  END mdr[334]
  PIN mdr[335]
    DIRECTION INPUT ;
    USE SIGNAL ;
    PORT
      LAYER M5 ;
        RECT  26.064 81.996 26.088 82.08 ;
    END
  END mdr[335]
  PIN mdr[336]
    DIRECTION INPUT ;
    USE SIGNAL ;
    PORT
      LAYER M5 ;
        RECT  26.16 81.996 26.184 82.08 ;
    END
  END mdr[336]
  PIN mdr[337]
    DIRECTION INPUT ;
    USE SIGNAL ;
    PORT
      LAYER M5 ;
        RECT  26.256 81.996 26.28 82.08 ;
    END
  END mdr[337]
  PIN mdr[338]
    DIRECTION INPUT ;
    USE SIGNAL ;
    PORT
      LAYER M5 ;
        RECT  26.352 81.996 26.376 82.08 ;
    END
  END mdr[338]
  PIN mdr[339]
    DIRECTION INPUT ;
    USE SIGNAL ;
    PORT
      LAYER M5 ;
        RECT  26.448 81.996 26.472 82.08 ;
    END
  END mdr[339]
  PIN mdr[33]
    DIRECTION INPUT ;
    USE SIGNAL ;
    PORT
      LAYER M5 ;
        RECT  53.136 81.996 53.16 82.08 ;
    END
  END mdr[33]
  PIN mdr[340]
    DIRECTION INPUT ;
    USE SIGNAL ;
    PORT
      LAYER M5 ;
        RECT  26.544 81.996 26.568 82.08 ;
    END
  END mdr[340]
  PIN mdr[341]
    DIRECTION INPUT ;
    USE SIGNAL ;
    PORT
      LAYER M5 ;
        RECT  26.64 81.996 26.664 82.08 ;
    END
  END mdr[341]
  PIN mdr[342]
    DIRECTION INPUT ;
    USE SIGNAL ;
    PORT
      LAYER M5 ;
        RECT  26.736 81.996 26.76 82.08 ;
    END
  END mdr[342]
  PIN mdr[343]
    DIRECTION INPUT ;
    USE SIGNAL ;
    PORT
      LAYER M5 ;
        RECT  26.832 81.996 26.856 82.08 ;
    END
  END mdr[343]
  PIN mdr[344]
    DIRECTION INPUT ;
    USE SIGNAL ;
    PORT
      LAYER M5 ;
        RECT  26.928 81.996 26.952 82.08 ;
    END
  END mdr[344]
  PIN mdr[345]
    DIRECTION INPUT ;
    USE SIGNAL ;
    PORT
      LAYER M5 ;
        RECT  27.024 81.996 27.048 82.08 ;
    END
  END mdr[345]
  PIN mdr[346]
    DIRECTION INPUT ;
    USE SIGNAL ;
    PORT
      LAYER M5 ;
        RECT  27.12 81.996 27.144 82.08 ;
    END
  END mdr[346]
  PIN mdr[347]
    DIRECTION INPUT ;
    USE SIGNAL ;
    PORT
      LAYER M5 ;
        RECT  27.216 81.996 27.24 82.08 ;
    END
  END mdr[347]
  PIN mdr[348]
    DIRECTION INPUT ;
    USE SIGNAL ;
    PORT
      LAYER M5 ;
        RECT  27.312 81.996 27.336 82.08 ;
    END
  END mdr[348]
  PIN mdr[349]
    DIRECTION INPUT ;
    USE SIGNAL ;
    PORT
      LAYER M5 ;
        RECT  27.408 81.996 27.432 82.08 ;
    END
  END mdr[349]
  PIN mdr[34]
    DIRECTION INPUT ;
    USE SIGNAL ;
    PORT
      LAYER M5 ;
        RECT  53.232 81.996 53.256 82.08 ;
    END
  END mdr[34]
  PIN mdr[350]
    DIRECTION INPUT ;
    USE SIGNAL ;
    PORT
      LAYER M5 ;
        RECT  27.504 81.996 27.528 82.08 ;
    END
  END mdr[350]
  PIN mdr[351]
    DIRECTION INPUT ;
    USE SIGNAL ;
    PORT
      LAYER M5 ;
        RECT  36.816 81.996 36.84 82.08 ;
    END
  END mdr[351]
  PIN mdr[352]
    DIRECTION INPUT ;
    USE SIGNAL ;
    PORT
      LAYER M5 ;
        RECT  36.912 81.996 36.936 82.08 ;
    END
  END mdr[352]
  PIN mdr[353]
    DIRECTION INPUT ;
    USE SIGNAL ;
    PORT
      LAYER M5 ;
        RECT  37.008 81.996 37.032 82.08 ;
    END
  END mdr[353]
  PIN mdr[354]
    DIRECTION INPUT ;
    USE SIGNAL ;
    PORT
      LAYER M5 ;
        RECT  37.104 81.996 37.128 82.08 ;
    END
  END mdr[354]
  PIN mdr[355]
    DIRECTION INPUT ;
    USE SIGNAL ;
    PORT
      LAYER M5 ;
        RECT  37.2 81.996 37.224 82.08 ;
    END
  END mdr[355]
  PIN mdr[356]
    DIRECTION INPUT ;
    USE SIGNAL ;
    PORT
      LAYER M5 ;
        RECT  37.296 81.996 37.32 82.08 ;
    END
  END mdr[356]
  PIN mdr[357]
    DIRECTION INPUT ;
    USE SIGNAL ;
    PORT
      LAYER M5 ;
        RECT  37.392 81.996 37.416 82.08 ;
    END
  END mdr[357]
  PIN mdr[358]
    DIRECTION INPUT ;
    USE SIGNAL ;
    PORT
      LAYER M5 ;
        RECT  37.488 81.996 37.512 82.08 ;
    END
  END mdr[358]
  PIN mdr[359]
    DIRECTION INPUT ;
    USE SIGNAL ;
    PORT
      LAYER M5 ;
        RECT  37.584 81.996 37.608 82.08 ;
    END
  END mdr[359]
  PIN mdr[35]
    DIRECTION INPUT ;
    USE SIGNAL ;
    PORT
      LAYER M5 ;
        RECT  53.328 81.996 53.352 82.08 ;
    END
  END mdr[35]
  PIN mdr[360]
    DIRECTION INPUT ;
    USE SIGNAL ;
    PORT
      LAYER M5 ;
        RECT  37.68 81.996 37.704 82.08 ;
    END
  END mdr[360]
  PIN mdr[361]
    DIRECTION INPUT ;
    USE SIGNAL ;
    PORT
      LAYER M5 ;
        RECT  37.776 81.996 37.8 82.08 ;
    END
  END mdr[361]
  PIN mdr[362]
    DIRECTION INPUT ;
    USE SIGNAL ;
    PORT
      LAYER M5 ;
        RECT  37.872 81.996 37.896 82.08 ;
    END
  END mdr[362]
  PIN mdr[363]
    DIRECTION INPUT ;
    USE SIGNAL ;
    PORT
      LAYER M5 ;
        RECT  37.968 81.996 37.992 82.08 ;
    END
  END mdr[363]
  PIN mdr[364]
    DIRECTION INPUT ;
    USE SIGNAL ;
    PORT
      LAYER M5 ;
        RECT  38.064 81.996 38.088 82.08 ;
    END
  END mdr[364]
  PIN mdr[365]
    DIRECTION INPUT ;
    USE SIGNAL ;
    PORT
      LAYER M5 ;
        RECT  38.16 81.996 38.184 82.08 ;
    END
  END mdr[365]
  PIN mdr[366]
    DIRECTION INPUT ;
    USE SIGNAL ;
    PORT
      LAYER M5 ;
        RECT  38.256 81.996 38.28 82.08 ;
    END
  END mdr[366]
  PIN mdr[367]
    DIRECTION INPUT ;
    USE SIGNAL ;
    PORT
      LAYER M5 ;
        RECT  38.352 81.996 38.376 82.08 ;
    END
  END mdr[367]
  PIN mdr[368]
    DIRECTION INPUT ;
    USE SIGNAL ;
    PORT
      LAYER M5 ;
        RECT  38.448 81.996 38.472 82.08 ;
    END
  END mdr[368]
  PIN mdr[369]
    DIRECTION INPUT ;
    USE SIGNAL ;
    PORT
      LAYER M5 ;
        RECT  38.544 81.996 38.568 82.08 ;
    END
  END mdr[369]
  PIN mdr[36]
    DIRECTION INPUT ;
    USE SIGNAL ;
    PORT
      LAYER M5 ;
        RECT  53.424 81.996 53.448 82.08 ;
    END
  END mdr[36]
  PIN mdr[370]
    DIRECTION INPUT ;
    USE SIGNAL ;
    PORT
      LAYER M5 ;
        RECT  38.64 81.996 38.664 82.08 ;
    END
  END mdr[370]
  PIN mdr[371]
    DIRECTION INPUT ;
    USE SIGNAL ;
    PORT
      LAYER M5 ;
        RECT  38.736 81.996 38.76 82.08 ;
    END
  END mdr[371]
  PIN mdr[372]
    DIRECTION INPUT ;
    USE SIGNAL ;
    PORT
      LAYER M5 ;
        RECT  38.832 81.996 38.856 82.08 ;
    END
  END mdr[372]
  PIN mdr[373]
    DIRECTION INPUT ;
    USE SIGNAL ;
    PORT
      LAYER M5 ;
        RECT  38.928 81.996 38.952 82.08 ;
    END
  END mdr[373]
  PIN mdr[374]
    DIRECTION INPUT ;
    USE SIGNAL ;
    PORT
      LAYER M5 ;
        RECT  39.024 81.996 39.048 82.08 ;
    END
  END mdr[374]
  PIN mdr[375]
    DIRECTION INPUT ;
    USE SIGNAL ;
    PORT
      LAYER M5 ;
        RECT  39.12 81.996 39.144 82.08 ;
    END
  END mdr[375]
  PIN mdr[376]
    DIRECTION INPUT ;
    USE SIGNAL ;
    PORT
      LAYER M5 ;
        RECT  39.216 81.996 39.24 82.08 ;
    END
  END mdr[376]
  PIN mdr[377]
    DIRECTION INPUT ;
    USE SIGNAL ;
    PORT
      LAYER M5 ;
        RECT  39.312 81.996 39.336 82.08 ;
    END
  END mdr[377]
  PIN mdr[378]
    DIRECTION INPUT ;
    USE SIGNAL ;
    PORT
      LAYER M5 ;
        RECT  39.408 81.996 39.432 82.08 ;
    END
  END mdr[378]
  PIN mdr[379]
    DIRECTION INPUT ;
    USE SIGNAL ;
    PORT
      LAYER M5 ;
        RECT  39.504 81.996 39.528 82.08 ;
    END
  END mdr[379]
  PIN mdr[37]
    DIRECTION INPUT ;
    USE SIGNAL ;
    PORT
      LAYER M5 ;
        RECT  53.52 81.996 53.544 82.08 ;
    END
  END mdr[37]
  PIN mdr[380]
    DIRECTION INPUT ;
    USE SIGNAL ;
    PORT
      LAYER M5 ;
        RECT  39.6 81.996 39.624 82.08 ;
    END
  END mdr[380]
  PIN mdr[381]
    DIRECTION INPUT ;
    USE SIGNAL ;
    PORT
      LAYER M5 ;
        RECT  39.696 81.996 39.72 82.08 ;
    END
  END mdr[381]
  PIN mdr[382]
    DIRECTION INPUT ;
    USE SIGNAL ;
    PORT
      LAYER M5 ;
        RECT  39.792 81.996 39.816 82.08 ;
    END
  END mdr[382]
  PIN mdr[383]
    DIRECTION INPUT ;
    USE SIGNAL ;
    PORT
      LAYER M5 ;
        RECT  39.888 81.996 39.912 82.08 ;
    END
  END mdr[383]
  PIN mdr[384]
    DIRECTION INPUT ;
    USE SIGNAL ;
    PORT
      LAYER M5 ;
        RECT  39.984 81.996 40.008 82.08 ;
    END
  END mdr[384]
  PIN mdr[385]
    DIRECTION INPUT ;
    USE SIGNAL ;
    PORT
      LAYER M5 ;
        RECT  40.08 81.996 40.104 82.08 ;
    END
  END mdr[385]
  PIN mdr[386]
    DIRECTION INPUT ;
    USE SIGNAL ;
    PORT
      LAYER M5 ;
        RECT  40.176 81.996 40.2 82.08 ;
    END
  END mdr[386]
  PIN mdr[387]
    DIRECTION INPUT ;
    USE SIGNAL ;
    PORT
      LAYER M5 ;
        RECT  40.272 81.996 40.296 82.08 ;
    END
  END mdr[387]
  PIN mdr[388]
    DIRECTION INPUT ;
    USE SIGNAL ;
    PORT
      LAYER M5 ;
        RECT  40.368 81.996 40.392 82.08 ;
    END
  END mdr[388]
  PIN mdr[389]
    DIRECTION INPUT ;
    USE SIGNAL ;
    PORT
      LAYER M5 ;
        RECT  40.464 81.996 40.488 82.08 ;
    END
  END mdr[389]
  PIN mdr[38]
    DIRECTION INPUT ;
    USE SIGNAL ;
    PORT
      LAYER M5 ;
        RECT  53.616 81.996 53.64 82.08 ;
    END
  END mdr[38]
  PIN mdr[390]
    DIRECTION INPUT ;
    USE SIGNAL ;
    PORT
      LAYER M5 ;
        RECT  40.56 81.996 40.584 82.08 ;
    END
  END mdr[390]
  PIN mdr[391]
    DIRECTION INPUT ;
    USE SIGNAL ;
    PORT
      LAYER M5 ;
        RECT  40.656 81.996 40.68 82.08 ;
    END
  END mdr[391]
  PIN mdr[392]
    DIRECTION INPUT ;
    USE SIGNAL ;
    PORT
      LAYER M5 ;
        RECT  40.752 81.996 40.776 82.08 ;
    END
  END mdr[392]
  PIN mdr[393]
    DIRECTION INPUT ;
    USE SIGNAL ;
    PORT
      LAYER M5 ;
        RECT  40.848 81.996 40.872 82.08 ;
    END
  END mdr[393]
  PIN mdr[394]
    DIRECTION INPUT ;
    USE SIGNAL ;
    PORT
      LAYER M5 ;
        RECT  40.944 81.996 40.968 82.08 ;
    END
  END mdr[394]
  PIN mdr[395]
    DIRECTION INPUT ;
    USE SIGNAL ;
    PORT
      LAYER M5 ;
        RECT  41.04 81.996 41.064 82.08 ;
    END
  END mdr[395]
  PIN mdr[396]
    DIRECTION INPUT ;
    USE SIGNAL ;
    PORT
      LAYER M5 ;
        RECT  41.136 81.996 41.16 82.08 ;
    END
  END mdr[396]
  PIN mdr[397]
    DIRECTION INPUT ;
    USE SIGNAL ;
    PORT
      LAYER M5 ;
        RECT  41.232 81.996 41.256 82.08 ;
    END
  END mdr[397]
  PIN mdr[398]
    DIRECTION INPUT ;
    USE SIGNAL ;
    PORT
      LAYER M5 ;
        RECT  41.328 81.996 41.352 82.08 ;
    END
  END mdr[398]
  PIN mdr[399]
    DIRECTION INPUT ;
    USE SIGNAL ;
    PORT
      LAYER M5 ;
        RECT  41.424 81.996 41.448 82.08 ;
    END
  END mdr[399]
  PIN mdr[39]
    DIRECTION INPUT ;
    USE SIGNAL ;
    PORT
      LAYER M5 ;
        RECT  53.712 81.996 53.736 82.08 ;
    END
  END mdr[39]
  PIN mdr[3]
    DIRECTION INPUT ;
    USE SIGNAL ;
    PORT
      LAYER M5 ;
        RECT  8.784 81.996 8.808 82.08 ;
    END
  END mdr[3]
  PIN mdr[400]
    DIRECTION INPUT ;
    USE SIGNAL ;
    PORT
      LAYER M5 ;
        RECT  41.52 81.996 41.544 82.08 ;
    END
  END mdr[400]
  PIN mdr[401]
    DIRECTION INPUT ;
    USE SIGNAL ;
    PORT
      LAYER M5 ;
        RECT  41.616 81.996 41.64 82.08 ;
    END
  END mdr[401]
  PIN mdr[402]
    DIRECTION INPUT ;
    USE SIGNAL ;
    PORT
      LAYER M5 ;
        RECT  41.712 81.996 41.736 82.08 ;
    END
  END mdr[402]
  PIN mdr[403]
    DIRECTION INPUT ;
    USE SIGNAL ;
    PORT
      LAYER M5 ;
        RECT  41.808 81.996 41.832 82.08 ;
    END
  END mdr[403]
  PIN mdr[404]
    DIRECTION INPUT ;
    USE SIGNAL ;
    PORT
      LAYER M5 ;
        RECT  41.904 81.996 41.928 82.08 ;
    END
  END mdr[404]
  PIN mdr[405]
    DIRECTION INPUT ;
    USE SIGNAL ;
    PORT
      LAYER M5 ;
        RECT  42 81.996 42.024 82.08 ;
    END
  END mdr[405]
  PIN mdr[406]
    DIRECTION INPUT ;
    USE SIGNAL ;
    PORT
      LAYER M5 ;
        RECT  42.096 81.996 42.12 82.08 ;
    END
  END mdr[406]
  PIN mdr[407]
    DIRECTION INPUT ;
    USE SIGNAL ;
    PORT
      LAYER M5 ;
        RECT  42.192 81.996 42.216 82.08 ;
    END
  END mdr[407]
  PIN mdr[408]
    DIRECTION INPUT ;
    USE SIGNAL ;
    PORT
      LAYER M5 ;
        RECT  42.288 81.996 42.312 82.08 ;
    END
  END mdr[408]
  PIN mdr[409]
    DIRECTION INPUT ;
    USE SIGNAL ;
    PORT
      LAYER M5 ;
        RECT  42.384 81.996 42.408 82.08 ;
    END
  END mdr[409]
  PIN mdr[40]
    DIRECTION INPUT ;
    USE SIGNAL ;
    PORT
      LAYER M5 ;
        RECT  53.808 81.996 53.832 82.08 ;
    END
  END mdr[40]
  PIN mdr[410]
    DIRECTION INPUT ;
    USE SIGNAL ;
    PORT
      LAYER M5 ;
        RECT  42.48 81.996 42.504 82.08 ;
    END
  END mdr[410]
  PIN mdr[411]
    DIRECTION INPUT ;
    USE SIGNAL ;
    PORT
      LAYER M5 ;
        RECT  42.576 81.996 42.6 82.08 ;
    END
  END mdr[411]
  PIN mdr[412]
    DIRECTION INPUT ;
    USE SIGNAL ;
    PORT
      LAYER M5 ;
        RECT  42.672 81.996 42.696 82.08 ;
    END
  END mdr[412]
  PIN mdr[413]
    DIRECTION INPUT ;
    USE SIGNAL ;
    PORT
      LAYER M5 ;
        RECT  42.768 81.996 42.792 82.08 ;
    END
  END mdr[413]
  PIN mdr[414]
    DIRECTION INPUT ;
    USE SIGNAL ;
    PORT
      LAYER M5 ;
        RECT  42.864 81.996 42.888 82.08 ;
    END
  END mdr[414]
  PIN mdr[415]
    DIRECTION INPUT ;
    USE SIGNAL ;
    PORT
      LAYER M5 ;
        RECT  33.744 81.996 33.768 82.08 ;
    END
  END mdr[415]
  PIN mdr[416]
    DIRECTION INPUT ;
    USE SIGNAL ;
    PORT
      LAYER M5 ;
        RECT  33.84 81.996 33.864 82.08 ;
    END
  END mdr[416]
  PIN mdr[417]
    DIRECTION INPUT ;
    USE SIGNAL ;
    PORT
      LAYER M5 ;
        RECT  33.936 81.996 33.96 82.08 ;
    END
  END mdr[417]
  PIN mdr[418]
    DIRECTION INPUT ;
    USE SIGNAL ;
    PORT
      LAYER M5 ;
        RECT  34.032 81.996 34.056 82.08 ;
    END
  END mdr[418]
  PIN mdr[419]
    DIRECTION INPUT ;
    USE SIGNAL ;
    PORT
      LAYER M5 ;
        RECT  34.128 81.996 34.152 82.08 ;
    END
  END mdr[419]
  PIN mdr[41]
    DIRECTION INPUT ;
    USE SIGNAL ;
    PORT
      LAYER M5 ;
        RECT  53.904 81.996 53.928 82.08 ;
    END
  END mdr[41]
  PIN mdr[420]
    DIRECTION INPUT ;
    USE SIGNAL ;
    PORT
      LAYER M5 ;
        RECT  34.224 81.996 34.248 82.08 ;
    END
  END mdr[420]
  PIN mdr[421]
    DIRECTION INPUT ;
    USE SIGNAL ;
    PORT
      LAYER M5 ;
        RECT  34.32 81.996 34.344 82.08 ;
    END
  END mdr[421]
  PIN mdr[422]
    DIRECTION INPUT ;
    USE SIGNAL ;
    PORT
      LAYER M5 ;
        RECT  34.416 81.996 34.44 82.08 ;
    END
  END mdr[422]
  PIN mdr[423]
    DIRECTION INPUT ;
    USE SIGNAL ;
    PORT
      LAYER M5 ;
        RECT  34.512 81.996 34.536 82.08 ;
    END
  END mdr[423]
  PIN mdr[424]
    DIRECTION INPUT ;
    USE SIGNAL ;
    PORT
      LAYER M5 ;
        RECT  34.608 81.996 34.632 82.08 ;
    END
  END mdr[424]
  PIN mdr[425]
    DIRECTION INPUT ;
    USE SIGNAL ;
    PORT
      LAYER M5 ;
        RECT  34.704 81.996 34.728 82.08 ;
    END
  END mdr[425]
  PIN mdr[426]
    DIRECTION INPUT ;
    USE SIGNAL ;
    PORT
      LAYER M5 ;
        RECT  34.8 81.996 34.824 82.08 ;
    END
  END mdr[426]
  PIN mdr[427]
    DIRECTION INPUT ;
    USE SIGNAL ;
    PORT
      LAYER M5 ;
        RECT  34.896 81.996 34.92 82.08 ;
    END
  END mdr[427]
  PIN mdr[428]
    DIRECTION INPUT ;
    USE SIGNAL ;
    PORT
      LAYER M5 ;
        RECT  34.992 81.996 35.016 82.08 ;
    END
  END mdr[428]
  PIN mdr[429]
    DIRECTION INPUT ;
    USE SIGNAL ;
    PORT
      LAYER M5 ;
        RECT  35.088 81.996 35.112 82.08 ;
    END
  END mdr[429]
  PIN mdr[42]
    DIRECTION INPUT ;
    USE SIGNAL ;
    PORT
      LAYER M5 ;
        RECT  54 81.996 54.024 82.08 ;
    END
  END mdr[42]
  PIN mdr[430]
    DIRECTION INPUT ;
    USE SIGNAL ;
    PORT
      LAYER M5 ;
        RECT  35.184 81.996 35.208 82.08 ;
    END
  END mdr[430]
  PIN mdr[431]
    DIRECTION INPUT ;
    USE SIGNAL ;
    PORT
      LAYER M5 ;
        RECT  35.28 81.996 35.304 82.08 ;
    END
  END mdr[431]
  PIN mdr[432]
    DIRECTION INPUT ;
    USE SIGNAL ;
    PORT
      LAYER M5 ;
        RECT  35.376 81.996 35.4 82.08 ;
    END
  END mdr[432]
  PIN mdr[433]
    DIRECTION INPUT ;
    USE SIGNAL ;
    PORT
      LAYER M5 ;
        RECT  35.472 81.996 35.496 82.08 ;
    END
  END mdr[433]
  PIN mdr[434]
    DIRECTION INPUT ;
    USE SIGNAL ;
    PORT
      LAYER M5 ;
        RECT  35.568 81.996 35.592 82.08 ;
    END
  END mdr[434]
  PIN mdr[435]
    DIRECTION INPUT ;
    USE SIGNAL ;
    PORT
      LAYER M5 ;
        RECT  35.664 81.996 35.688 82.08 ;
    END
  END mdr[435]
  PIN mdr[436]
    DIRECTION INPUT ;
    USE SIGNAL ;
    PORT
      LAYER M5 ;
        RECT  35.76 81.996 35.784 82.08 ;
    END
  END mdr[436]
  PIN mdr[437]
    DIRECTION INPUT ;
    USE SIGNAL ;
    PORT
      LAYER M5 ;
        RECT  35.856 81.996 35.88 82.08 ;
    END
  END mdr[437]
  PIN mdr[438]
    DIRECTION INPUT ;
    USE SIGNAL ;
    PORT
      LAYER M5 ;
        RECT  35.952 81.996 35.976 82.08 ;
    END
  END mdr[438]
  PIN mdr[439]
    DIRECTION INPUT ;
    USE SIGNAL ;
    PORT
      LAYER M5 ;
        RECT  36.048 81.996 36.072 82.08 ;
    END
  END mdr[439]
  PIN mdr[43]
    DIRECTION INPUT ;
    USE SIGNAL ;
    PORT
      LAYER M5 ;
        RECT  54.096 81.996 54.12 82.08 ;
    END
  END mdr[43]
  PIN mdr[440]
    DIRECTION INPUT ;
    USE SIGNAL ;
    PORT
      LAYER M5 ;
        RECT  36.144 81.996 36.168 82.08 ;
    END
  END mdr[440]
  PIN mdr[441]
    DIRECTION INPUT ;
    USE SIGNAL ;
    PORT
      LAYER M5 ;
        RECT  36.24 81.996 36.264 82.08 ;
    END
  END mdr[441]
  PIN mdr[442]
    DIRECTION INPUT ;
    USE SIGNAL ;
    PORT
      LAYER M5 ;
        RECT  36.336 81.996 36.36 82.08 ;
    END
  END mdr[442]
  PIN mdr[443]
    DIRECTION INPUT ;
    USE SIGNAL ;
    PORT
      LAYER M5 ;
        RECT  36.432 81.996 36.456 82.08 ;
    END
  END mdr[443]
  PIN mdr[444]
    DIRECTION INPUT ;
    USE SIGNAL ;
    PORT
      LAYER M5 ;
        RECT  36.528 81.996 36.552 82.08 ;
    END
  END mdr[444]
  PIN mdr[445]
    DIRECTION INPUT ;
    USE SIGNAL ;
    PORT
      LAYER M5 ;
        RECT  36.624 81.996 36.648 82.08 ;
    END
  END mdr[445]
  PIN mdr[446]
    DIRECTION INPUT ;
    USE SIGNAL ;
    PORT
      LAYER M5 ;
        RECT  36.72 81.996 36.744 82.08 ;
    END
  END mdr[446]
  PIN mdr[447]
    DIRECTION INPUT ;
    USE SIGNAL ;
    PORT
      LAYER M5 ;
        RECT  19.536 81.996 19.56 82.08 ;
    END
  END mdr[447]
  PIN mdr[448]
    DIRECTION INPUT ;
    USE SIGNAL ;
    PORT
      LAYER M5 ;
        RECT  19.632 81.996 19.656 82.08 ;
    END
  END mdr[448]
  PIN mdr[449]
    DIRECTION INPUT ;
    USE SIGNAL ;
    PORT
      LAYER M5 ;
        RECT  19.728 81.996 19.752 82.08 ;
    END
  END mdr[449]
  PIN mdr[44]
    DIRECTION INPUT ;
    USE SIGNAL ;
    PORT
      LAYER M5 ;
        RECT  54.192 81.996 54.216 82.08 ;
    END
  END mdr[44]
  PIN mdr[450]
    DIRECTION INPUT ;
    USE SIGNAL ;
    PORT
      LAYER M5 ;
        RECT  19.824 81.996 19.848 82.08 ;
    END
  END mdr[450]
  PIN mdr[451]
    DIRECTION INPUT ;
    USE SIGNAL ;
    PORT
      LAYER M5 ;
        RECT  19.92 81.996 19.944 82.08 ;
    END
  END mdr[451]
  PIN mdr[452]
    DIRECTION INPUT ;
    USE SIGNAL ;
    PORT
      LAYER M5 ;
        RECT  20.016 81.996 20.04 82.08 ;
    END
  END mdr[452]
  PIN mdr[453]
    DIRECTION INPUT ;
    USE SIGNAL ;
    PORT
      LAYER M5 ;
        RECT  20.112 81.996 20.136 82.08 ;
    END
  END mdr[453]
  PIN mdr[454]
    DIRECTION INPUT ;
    USE SIGNAL ;
    PORT
      LAYER M5 ;
        RECT  20.208 81.996 20.232 82.08 ;
    END
  END mdr[454]
  PIN mdr[455]
    DIRECTION INPUT ;
    USE SIGNAL ;
    PORT
      LAYER M5 ;
        RECT  20.304 81.996 20.328 82.08 ;
    END
  END mdr[455]
  PIN mdr[456]
    DIRECTION INPUT ;
    USE SIGNAL ;
    PORT
      LAYER M5 ;
        RECT  20.4 81.996 20.424 82.08 ;
    END
  END mdr[456]
  PIN mdr[457]
    DIRECTION INPUT ;
    USE SIGNAL ;
    PORT
      LAYER M5 ;
        RECT  20.496 81.996 20.52 82.08 ;
    END
  END mdr[457]
  PIN mdr[45]
    DIRECTION INPUT ;
    USE SIGNAL ;
    PORT
      LAYER M5 ;
        RECT  54.288 81.996 54.312 82.08 ;
    END
  END mdr[45]
  PIN mdr[46]
    DIRECTION INPUT ;
    USE SIGNAL ;
    PORT
      LAYER M5 ;
        RECT  54.384 81.996 54.408 82.08 ;
    END
  END mdr[46]
  PIN mdr[47]
    DIRECTION INPUT ;
    USE SIGNAL ;
    PORT
      LAYER M5 ;
        RECT  54.48 81.996 54.504 82.08 ;
    END
  END mdr[47]
  PIN mdr[48]
    DIRECTION INPUT ;
    USE SIGNAL ;
    PORT
      LAYER M5 ;
        RECT  54.576 81.996 54.6 82.08 ;
    END
  END mdr[48]
  PIN mdr[49]
    DIRECTION INPUT ;
    USE SIGNAL ;
    PORT
      LAYER M5 ;
        RECT  54.672 81.996 54.696 82.08 ;
    END
  END mdr[49]
  PIN mdr[4]
    DIRECTION INPUT ;
    USE SIGNAL ;
    PORT
      LAYER M5 ;
        RECT  8.88 81.996 8.904 82.08 ;
    END
  END mdr[4]
  PIN mdr[50]
    DIRECTION INPUT ;
    USE SIGNAL ;
    PORT
      LAYER M5 ;
        RECT  54.768 81.996 54.792 82.08 ;
    END
  END mdr[50]
  PIN mdr[51]
    DIRECTION INPUT ;
    USE SIGNAL ;
    PORT
      LAYER M5 ;
        RECT  54.864 81.996 54.888 82.08 ;
    END
  END mdr[51]
  PIN mdr[52]
    DIRECTION INPUT ;
    USE SIGNAL ;
    PORT
      LAYER M5 ;
        RECT  54.96 81.996 54.984 82.08 ;
    END
  END mdr[52]
  PIN mdr[53]
    DIRECTION INPUT ;
    USE SIGNAL ;
    PORT
      LAYER M5 ;
        RECT  55.056 81.996 55.08 82.08 ;
    END
  END mdr[53]
  PIN mdr[54]
    DIRECTION INPUT ;
    USE SIGNAL ;
    PORT
      LAYER M5 ;
        RECT  55.152 81.996 55.176 82.08 ;
    END
  END mdr[54]
  PIN mdr[55]
    DIRECTION INPUT ;
    USE SIGNAL ;
    PORT
      LAYER M5 ;
        RECT  55.248 81.996 55.272 82.08 ;
    END
  END mdr[55]
  PIN mdr[56]
    DIRECTION INPUT ;
    USE SIGNAL ;
    PORT
      LAYER M5 ;
        RECT  55.344 81.996 55.368 82.08 ;
    END
  END mdr[56]
  PIN mdr[57]
    DIRECTION INPUT ;
    USE SIGNAL ;
    PORT
      LAYER M5 ;
        RECT  55.44 81.996 55.464 82.08 ;
    END
  END mdr[57]
  PIN mdr[58]
    DIRECTION INPUT ;
    USE SIGNAL ;
    PORT
      LAYER M5 ;
        RECT  55.536 81.996 55.56 82.08 ;
    END
  END mdr[58]
  PIN mdr[59]
    DIRECTION INPUT ;
    USE SIGNAL ;
    PORT
      LAYER M5 ;
        RECT  55.632 81.996 55.656 82.08 ;
    END
  END mdr[59]
  PIN mdr[5]
    DIRECTION INPUT ;
    USE SIGNAL ;
    PORT
      LAYER M5 ;
        RECT  8.976 81.996 9 82.08 ;
    END
  END mdr[5]
  PIN mdr[60]
    DIRECTION INPUT ;
    USE SIGNAL ;
    PORT
      LAYER M5 ;
        RECT  55.728 81.996 55.752 82.08 ;
    END
  END mdr[60]
  PIN mdr[61]
    DIRECTION INPUT ;
    USE SIGNAL ;
    PORT
      LAYER M5 ;
        RECT  55.824 81.996 55.848 82.08 ;
    END
  END mdr[61]
  PIN mdr[62]
    DIRECTION INPUT ;
    USE SIGNAL ;
    PORT
      LAYER M5 ;
        RECT  55.92 81.996 55.944 82.08 ;
    END
  END mdr[62]
  PIN mdr[63]
    DIRECTION INPUT ;
    USE SIGNAL ;
    PORT
      LAYER M5 ;
        RECT  59.088 81.996 59.112 82.08 ;
    END
  END mdr[63]
  PIN mdr[64]
    DIRECTION INPUT ;
    USE SIGNAL ;
    PORT
      LAYER M5 ;
        RECT  59.184 81.996 59.208 82.08 ;
    END
  END mdr[64]
  PIN mdr[65]
    DIRECTION INPUT ;
    USE SIGNAL ;
    PORT
      LAYER M5 ;
        RECT  59.28 81.996 59.304 82.08 ;
    END
  END mdr[65]
  PIN mdr[66]
    DIRECTION INPUT ;
    USE SIGNAL ;
    PORT
      LAYER M5 ;
        RECT  59.376 81.996 59.4 82.08 ;
    END
  END mdr[66]
  PIN mdr[67]
    DIRECTION INPUT ;
    USE SIGNAL ;
    PORT
      LAYER M5 ;
        RECT  59.472 81.996 59.496 82.08 ;
    END
  END mdr[67]
  PIN mdr[68]
    DIRECTION INPUT ;
    USE SIGNAL ;
    PORT
      LAYER M5 ;
        RECT  59.568 81.996 59.592 82.08 ;
    END
  END mdr[68]
  PIN mdr[69]
    DIRECTION INPUT ;
    USE SIGNAL ;
    PORT
      LAYER M5 ;
        RECT  59.664 81.996 59.688 82.08 ;
    END
  END mdr[69]
  PIN mdr[6]
    DIRECTION INPUT ;
    USE SIGNAL ;
    PORT
      LAYER M5 ;
        RECT  9.072 81.996 9.096 82.08 ;
    END
  END mdr[6]
  PIN mdr[70]
    DIRECTION INPUT ;
    USE SIGNAL ;
    PORT
      LAYER M5 ;
        RECT  59.76 81.996 59.784 82.08 ;
    END
  END mdr[70]
  PIN mdr[71]
    DIRECTION INPUT ;
    USE SIGNAL ;
    PORT
      LAYER M5 ;
        RECT  59.856 81.996 59.88 82.08 ;
    END
  END mdr[71]
  PIN mdr[72]
    DIRECTION INPUT ;
    USE SIGNAL ;
    PORT
      LAYER M5 ;
        RECT  59.952 81.996 59.976 82.08 ;
    END
  END mdr[72]
  PIN mdr[73]
    DIRECTION INPUT ;
    USE SIGNAL ;
    PORT
      LAYER M5 ;
        RECT  60.048 81.996 60.072 82.08 ;
    END
  END mdr[73]
  PIN mdr[74]
    DIRECTION INPUT ;
    USE SIGNAL ;
    PORT
      LAYER M5 ;
        RECT  60.144 81.996 60.168 82.08 ;
    END
  END mdr[74]
  PIN mdr[75]
    DIRECTION INPUT ;
    USE SIGNAL ;
    PORT
      LAYER M5 ;
        RECT  60.24 81.996 60.264 82.08 ;
    END
  END mdr[75]
  PIN mdr[76]
    DIRECTION INPUT ;
    USE SIGNAL ;
    PORT
      LAYER M5 ;
        RECT  60.336 81.996 60.36 82.08 ;
    END
  END mdr[76]
  PIN mdr[77]
    DIRECTION INPUT ;
    USE SIGNAL ;
    PORT
      LAYER M5 ;
        RECT  60.432 81.996 60.456 82.08 ;
    END
  END mdr[77]
  PIN mdr[78]
    DIRECTION INPUT ;
    USE SIGNAL ;
    PORT
      LAYER M5 ;
        RECT  60.528 81.996 60.552 82.08 ;
    END
  END mdr[78]
  PIN mdr[79]
    DIRECTION INPUT ;
    USE SIGNAL ;
    PORT
      LAYER M5 ;
        RECT  60.624 81.996 60.648 82.08 ;
    END
  END mdr[79]
  PIN mdr[7]
    DIRECTION INPUT ;
    USE SIGNAL ;
    PORT
      LAYER M5 ;
        RECT  9.168 81.996 9.192 82.08 ;
    END
  END mdr[7]
  PIN mdr[80]
    DIRECTION INPUT ;
    USE SIGNAL ;
    PORT
      LAYER M5 ;
        RECT  60.72 81.996 60.744 82.08 ;
    END
  END mdr[80]
  PIN mdr[81]
    DIRECTION INPUT ;
    USE SIGNAL ;
    PORT
      LAYER M5 ;
        RECT  60.816 81.996 60.84 82.08 ;
    END
  END mdr[81]
  PIN mdr[82]
    DIRECTION INPUT ;
    USE SIGNAL ;
    PORT
      LAYER M5 ;
        RECT  60.912 81.996 60.936 82.08 ;
    END
  END mdr[82]
  PIN mdr[83]
    DIRECTION INPUT ;
    USE SIGNAL ;
    PORT
      LAYER M5 ;
        RECT  61.008 81.996 61.032 82.08 ;
    END
  END mdr[83]
  PIN mdr[84]
    DIRECTION INPUT ;
    USE SIGNAL ;
    PORT
      LAYER M5 ;
        RECT  61.104 81.996 61.128 82.08 ;
    END
  END mdr[84]
  PIN mdr[85]
    DIRECTION INPUT ;
    USE SIGNAL ;
    PORT
      LAYER M5 ;
        RECT  61.2 81.996 61.224 82.08 ;
    END
  END mdr[85]
  PIN mdr[86]
    DIRECTION INPUT ;
    USE SIGNAL ;
    PORT
      LAYER M5 ;
        RECT  61.296 81.996 61.32 82.08 ;
    END
  END mdr[86]
  PIN mdr[87]
    DIRECTION INPUT ;
    USE SIGNAL ;
    PORT
      LAYER M5 ;
        RECT  61.392 81.996 61.416 82.08 ;
    END
  END mdr[87]
  PIN mdr[88]
    DIRECTION INPUT ;
    USE SIGNAL ;
    PORT
      LAYER M5 ;
        RECT  61.488 81.996 61.512 82.08 ;
    END
  END mdr[88]
  PIN mdr[89]
    DIRECTION INPUT ;
    USE SIGNAL ;
    PORT
      LAYER M5 ;
        RECT  61.584 81.996 61.608 82.08 ;
    END
  END mdr[89]
  PIN mdr[8]
    DIRECTION INPUT ;
    USE SIGNAL ;
    PORT
      LAYER M5 ;
        RECT  9.264 81.996 9.288 82.08 ;
    END
  END mdr[8]
  PIN mdr[90]
    DIRECTION INPUT ;
    USE SIGNAL ;
    PORT
      LAYER M5 ;
        RECT  61.68 81.996 61.704 82.08 ;
    END
  END mdr[90]
  PIN mdr[91]
    DIRECTION INPUT ;
    USE SIGNAL ;
    PORT
      LAYER M5 ;
        RECT  61.776 81.996 61.8 82.08 ;
    END
  END mdr[91]
  PIN mdr[92]
    DIRECTION INPUT ;
    USE SIGNAL ;
    PORT
      LAYER M5 ;
        RECT  61.872 81.996 61.896 82.08 ;
    END
  END mdr[92]
  PIN mdr[93]
    DIRECTION INPUT ;
    USE SIGNAL ;
    PORT
      LAYER M5 ;
        RECT  61.968 81.996 61.992 82.08 ;
    END
  END mdr[93]
  PIN mdr[94]
    DIRECTION INPUT ;
    USE SIGNAL ;
    PORT
      LAYER M5 ;
        RECT  62.064 81.996 62.088 82.08 ;
    END
  END mdr[94]
  PIN mdr[95]
    DIRECTION INPUT ;
    USE SIGNAL ;
    PORT
      LAYER M5 ;
        RECT  20.688 81.996 20.712 82.08 ;
    END
  END mdr[95]
  PIN mdr[96]
    DIRECTION INPUT ;
    USE SIGNAL ;
    PORT
      LAYER M5 ;
        RECT  20.784 81.996 20.808 82.08 ;
    END
  END mdr[96]
  PIN mdr[97]
    DIRECTION INPUT ;
    USE SIGNAL ;
    PORT
      LAYER M5 ;
        RECT  20.88 81.996 20.904 82.08 ;
    END
  END mdr[97]
  PIN mdr[98]
    DIRECTION INPUT ;
    USE SIGNAL ;
    PORT
      LAYER M5 ;
        RECT  20.976 81.996 21 82.08 ;
    END
  END mdr[98]
  PIN mdr[99]
    DIRECTION INPUT ;
    USE SIGNAL ;
    PORT
      LAYER M5 ;
        RECT  21.072 81.996 21.096 82.08 ;
    END
  END mdr[99]
  PIN mdr[9]
    DIRECTION INPUT ;
    USE SIGNAL ;
    PORT
      LAYER M5 ;
        RECT  9.36 81.996 9.384 82.08 ;
    END
  END mdr[9]
  PIN q2f
    DIRECTION OUTPUT ;
    USE SIGNAL ;
    PORT
      LAYER M4 ;
        RECT  81.996 17.616 82.08 17.64 ;
    END
  END q2f
  PIN r_bf16[0]
    DIRECTION INPUT ;
    USE SIGNAL ;
    PORT
      LAYER M5 ;
        RECT  0.72 0 0.744 0.084 ;
    END
  END r_bf16[0]
  PIN r_bf16[100]
    DIRECTION INPUT ;
    USE SIGNAL ;
    PORT
      LAYER M5 ;
        RECT  29.52 0 29.544 0.084 ;
    END
  END r_bf16[100]
  PIN r_bf16[101]
    DIRECTION INPUT ;
    USE SIGNAL ;
    PORT
      LAYER M5 ;
        RECT  29.616 0 29.64 0.084 ;
    END
  END r_bf16[101]
  PIN r_bf16[102]
    DIRECTION INPUT ;
    USE SIGNAL ;
    PORT
      LAYER M5 ;
        RECT  29.712 0 29.736 0.084 ;
    END
  END r_bf16[102]
  PIN r_bf16[103]
    DIRECTION INPUT ;
    USE SIGNAL ;
    PORT
      LAYER M5 ;
        RECT  29.808 0 29.832 0.084 ;
    END
  END r_bf16[103]
  PIN r_bf16[104]
    DIRECTION INPUT ;
    USE SIGNAL ;
    PORT
      LAYER M5 ;
        RECT  29.904 0 29.928 0.084 ;
    END
  END r_bf16[104]
  PIN r_bf16[105]
    DIRECTION INPUT ;
    USE SIGNAL ;
    PORT
      LAYER M5 ;
        RECT  30 0 30.024 0.084 ;
    END
  END r_bf16[105]
  PIN r_bf16[106]
    DIRECTION INPUT ;
    USE SIGNAL ;
    PORT
      LAYER M5 ;
        RECT  30.096 0 30.12 0.084 ;
    END
  END r_bf16[106]
  PIN r_bf16[107]
    DIRECTION INPUT ;
    USE SIGNAL ;
    PORT
      LAYER M5 ;
        RECT  30.192 0 30.216 0.084 ;
    END
  END r_bf16[107]
  PIN r_bf16[108]
    DIRECTION INPUT ;
    USE SIGNAL ;
    PORT
      LAYER M5 ;
        RECT  30.288 0 30.312 0.084 ;
    END
  END r_bf16[108]
  PIN r_bf16[109]
    DIRECTION INPUT ;
    USE SIGNAL ;
    PORT
      LAYER M5 ;
        RECT  30.384 0 30.408 0.084 ;
    END
  END r_bf16[109]
  PIN r_bf16[10]
    DIRECTION INPUT ;
    USE SIGNAL ;
    PORT
      LAYER M5 ;
        RECT  1.68 0 1.704 0.084 ;
    END
  END r_bf16[10]
  PIN r_bf16[110]
    DIRECTION INPUT ;
    USE SIGNAL ;
    PORT
      LAYER M5 ;
        RECT  30.48 0 30.504 0.084 ;
    END
  END r_bf16[110]
  PIN r_bf16[111]
    DIRECTION INPUT ;
    USE SIGNAL ;
    PORT
      LAYER M5 ;
        RECT  30.576 0 30.6 0.084 ;
    END
  END r_bf16[111]
  PIN r_bf16[112]
    DIRECTION INPUT ;
    USE SIGNAL ;
    PORT
      LAYER M5 ;
        RECT  30.672 0 30.696 0.084 ;
    END
  END r_bf16[112]
  PIN r_bf16[113]
    DIRECTION INPUT ;
    USE SIGNAL ;
    PORT
      LAYER M5 ;
        RECT  30.768 0 30.792 0.084 ;
    END
  END r_bf16[113]
  PIN r_bf16[114]
    DIRECTION INPUT ;
    USE SIGNAL ;
    PORT
      LAYER M5 ;
        RECT  30.864 0 30.888 0.084 ;
    END
  END r_bf16[114]
  PIN r_bf16[115]
    DIRECTION INPUT ;
    USE SIGNAL ;
    PORT
      LAYER M5 ;
        RECT  30.96 0 30.984 0.084 ;
    END
  END r_bf16[115]
  PIN r_bf16[116]
    DIRECTION INPUT ;
    USE SIGNAL ;
    PORT
      LAYER M5 ;
        RECT  31.056 0 31.08 0.084 ;
    END
  END r_bf16[116]
  PIN r_bf16[117]
    DIRECTION INPUT ;
    USE SIGNAL ;
    PORT
      LAYER M5 ;
        RECT  31.152 0 31.176 0.084 ;
    END
  END r_bf16[117]
  PIN r_bf16[118]
    DIRECTION INPUT ;
    USE SIGNAL ;
    PORT
      LAYER M5 ;
        RECT  31.248 0 31.272 0.084 ;
    END
  END r_bf16[118]
  PIN r_bf16[119]
    DIRECTION INPUT ;
    USE SIGNAL ;
    PORT
      LAYER M5 ;
        RECT  31.344 0 31.368 0.084 ;
    END
  END r_bf16[119]
  PIN r_bf16[11]
    DIRECTION INPUT ;
    USE SIGNAL ;
    PORT
      LAYER M5 ;
        RECT  1.776 0 1.8 0.084 ;
    END
  END r_bf16[11]
  PIN r_bf16[120]
    DIRECTION INPUT ;
    USE SIGNAL ;
    PORT
      LAYER M5 ;
        RECT  31.44 0 31.464 0.084 ;
    END
  END r_bf16[120]
  PIN r_bf16[121]
    DIRECTION INPUT ;
    USE SIGNAL ;
    PORT
      LAYER M5 ;
        RECT  31.536 0 31.56 0.084 ;
    END
  END r_bf16[121]
  PIN r_bf16[122]
    DIRECTION INPUT ;
    USE SIGNAL ;
    PORT
      LAYER M5 ;
        RECT  31.632 0 31.656 0.084 ;
    END
  END r_bf16[122]
  PIN r_bf16[123]
    DIRECTION INPUT ;
    USE SIGNAL ;
    PORT
      LAYER M5 ;
        RECT  31.728 0 31.752 0.084 ;
    END
  END r_bf16[123]
  PIN r_bf16[124]
    DIRECTION INPUT ;
    USE SIGNAL ;
    PORT
      LAYER M5 ;
        RECT  31.824 0 31.848 0.084 ;
    END
  END r_bf16[124]
  PIN r_bf16[125]
    DIRECTION INPUT ;
    USE SIGNAL ;
    PORT
      LAYER M5 ;
        RECT  31.92 0 31.944 0.084 ;
    END
  END r_bf16[125]
  PIN r_bf16[126]
    DIRECTION INPUT ;
    USE SIGNAL ;
    PORT
      LAYER M5 ;
        RECT  32.016 0 32.04 0.084 ;
    END
  END r_bf16[126]
  PIN r_bf16[127]
    DIRECTION INPUT ;
    USE SIGNAL ;
    PORT
      LAYER M5 ;
        RECT  32.112 0 32.136 0.084 ;
    END
  END r_bf16[127]
  PIN r_bf16[12]
    DIRECTION INPUT ;
    USE SIGNAL ;
    PORT
      LAYER M5 ;
        RECT  1.872 0 1.896 0.084 ;
    END
  END r_bf16[12]
  PIN r_bf16[13]
    DIRECTION INPUT ;
    USE SIGNAL ;
    PORT
      LAYER M5 ;
        RECT  1.968 0 1.992 0.084 ;
    END
  END r_bf16[13]
  PIN r_bf16[14]
    DIRECTION INPUT ;
    USE SIGNAL ;
    PORT
      LAYER M5 ;
        RECT  2.064 0 2.088 0.084 ;
    END
  END r_bf16[14]
  PIN r_bf16[15]
    DIRECTION INPUT ;
    USE SIGNAL ;
    PORT
      LAYER M5 ;
        RECT  2.16 0 2.184 0.084 ;
    END
  END r_bf16[15]
  PIN r_bf16[16]
    DIRECTION INPUT ;
    USE SIGNAL ;
    PORT
      LAYER M5 ;
        RECT  2.256 0 2.28 0.084 ;
    END
  END r_bf16[16]
  PIN r_bf16[17]
    DIRECTION INPUT ;
    USE SIGNAL ;
    PORT
      LAYER M5 ;
        RECT  2.352 0 2.376 0.084 ;
    END
  END r_bf16[17]
  PIN r_bf16[18]
    DIRECTION INPUT ;
    USE SIGNAL ;
    PORT
      LAYER M5 ;
        RECT  2.448 0 2.472 0.084 ;
    END
  END r_bf16[18]
  PIN r_bf16[19]
    DIRECTION INPUT ;
    USE SIGNAL ;
    PORT
      LAYER M5 ;
        RECT  2.544 0 2.568 0.084 ;
    END
  END r_bf16[19]
  PIN r_bf16[1]
    DIRECTION INPUT ;
    USE SIGNAL ;
    PORT
      LAYER M5 ;
        RECT  0.816 0 0.84 0.084 ;
    END
  END r_bf16[1]
  PIN r_bf16[20]
    DIRECTION INPUT ;
    USE SIGNAL ;
    PORT
      LAYER M5 ;
        RECT  2.64 0 2.664 0.084 ;
    END
  END r_bf16[20]
  PIN r_bf16[21]
    DIRECTION INPUT ;
    USE SIGNAL ;
    PORT
      LAYER M5 ;
        RECT  2.736 0 2.76 0.084 ;
    END
  END r_bf16[21]
  PIN r_bf16[22]
    DIRECTION INPUT ;
    USE SIGNAL ;
    PORT
      LAYER M5 ;
        RECT  2.832 0 2.856 0.084 ;
    END
  END r_bf16[22]
  PIN r_bf16[23]
    DIRECTION INPUT ;
    USE SIGNAL ;
    PORT
      LAYER M5 ;
        RECT  2.928 0 2.952 0.084 ;
    END
  END r_bf16[23]
  PIN r_bf16[24]
    DIRECTION INPUT ;
    USE SIGNAL ;
    PORT
      LAYER M5 ;
        RECT  3.024 0 3.048 0.084 ;
    END
  END r_bf16[24]
  PIN r_bf16[25]
    DIRECTION INPUT ;
    USE SIGNAL ;
    PORT
      LAYER M5 ;
        RECT  3.12 0 3.144 0.084 ;
    END
  END r_bf16[25]
  PIN r_bf16[26]
    DIRECTION INPUT ;
    USE SIGNAL ;
    PORT
      LAYER M5 ;
        RECT  3.216 0 3.24 0.084 ;
    END
  END r_bf16[26]
  PIN r_bf16[27]
    DIRECTION INPUT ;
    USE SIGNAL ;
    PORT
      LAYER M5 ;
        RECT  3.312 0 3.336 0.084 ;
    END
  END r_bf16[27]
  PIN r_bf16[28]
    DIRECTION INPUT ;
    USE SIGNAL ;
    PORT
      LAYER M5 ;
        RECT  3.408 0 3.432 0.084 ;
    END
  END r_bf16[28]
  PIN r_bf16[29]
    DIRECTION INPUT ;
    USE SIGNAL ;
    PORT
      LAYER M5 ;
        RECT  3.504 0 3.528 0.084 ;
    END
  END r_bf16[29]
  PIN r_bf16[2]
    DIRECTION INPUT ;
    USE SIGNAL ;
    PORT
      LAYER M5 ;
        RECT  0.912 0 0.936 0.084 ;
    END
  END r_bf16[2]
  PIN r_bf16[30]
    DIRECTION INPUT ;
    USE SIGNAL ;
    PORT
      LAYER M5 ;
        RECT  3.6 0 3.624 0.084 ;
    END
  END r_bf16[30]
  PIN r_bf16[31]
    DIRECTION INPUT ;
    USE SIGNAL ;
    PORT
      LAYER M5 ;
        RECT  3.696 0 3.72 0.084 ;
    END
  END r_bf16[31]
  PIN r_bf16[32]
    DIRECTION INPUT ;
    USE SIGNAL ;
    PORT
      LAYER M5 ;
        RECT  19.92 0 19.944 0.084 ;
    END
  END r_bf16[32]
  PIN r_bf16[33]
    DIRECTION INPUT ;
    USE SIGNAL ;
    PORT
      LAYER M5 ;
        RECT  20.016 0 20.04 0.084 ;
    END
  END r_bf16[33]
  PIN r_bf16[34]
    DIRECTION INPUT ;
    USE SIGNAL ;
    PORT
      LAYER M5 ;
        RECT  20.112 0 20.136 0.084 ;
    END
  END r_bf16[34]
  PIN r_bf16[35]
    DIRECTION INPUT ;
    USE SIGNAL ;
    PORT
      LAYER M5 ;
        RECT  20.208 0 20.232 0.084 ;
    END
  END r_bf16[35]
  PIN r_bf16[36]
    DIRECTION INPUT ;
    USE SIGNAL ;
    PORT
      LAYER M5 ;
        RECT  20.304 0 20.328 0.084 ;
    END
  END r_bf16[36]
  PIN r_bf16[37]
    DIRECTION INPUT ;
    USE SIGNAL ;
    PORT
      LAYER M5 ;
        RECT  20.4 0 20.424 0.084 ;
    END
  END r_bf16[37]
  PIN r_bf16[38]
    DIRECTION INPUT ;
    USE SIGNAL ;
    PORT
      LAYER M5 ;
        RECT  20.496 0 20.52 0.084 ;
    END
  END r_bf16[38]
  PIN r_bf16[39]
    DIRECTION INPUT ;
    USE SIGNAL ;
    PORT
      LAYER M5 ;
        RECT  20.592 0 20.616 0.084 ;
    END
  END r_bf16[39]
  PIN r_bf16[3]
    DIRECTION INPUT ;
    USE SIGNAL ;
    PORT
      LAYER M5 ;
        RECT  1.008 0 1.032 0.084 ;
    END
  END r_bf16[3]
  PIN r_bf16[40]
    DIRECTION INPUT ;
    USE SIGNAL ;
    PORT
      LAYER M5 ;
        RECT  20.688 0 20.712 0.084 ;
    END
  END r_bf16[40]
  PIN r_bf16[41]
    DIRECTION INPUT ;
    USE SIGNAL ;
    PORT
      LAYER M5 ;
        RECT  20.784 0 20.808 0.084 ;
    END
  END r_bf16[41]
  PIN r_bf16[42]
    DIRECTION INPUT ;
    USE SIGNAL ;
    PORT
      LAYER M5 ;
        RECT  20.88 0 20.904 0.084 ;
    END
  END r_bf16[42]
  PIN r_bf16[43]
    DIRECTION INPUT ;
    USE SIGNAL ;
    PORT
      LAYER M5 ;
        RECT  20.976 0 21 0.084 ;
    END
  END r_bf16[43]
  PIN r_bf16[44]
    DIRECTION INPUT ;
    USE SIGNAL ;
    PORT
      LAYER M5 ;
        RECT  21.072 0 21.096 0.084 ;
    END
  END r_bf16[44]
  PIN r_bf16[45]
    DIRECTION INPUT ;
    USE SIGNAL ;
    PORT
      LAYER M5 ;
        RECT  21.168 0 21.192 0.084 ;
    END
  END r_bf16[45]
  PIN r_bf16[46]
    DIRECTION INPUT ;
    USE SIGNAL ;
    PORT
      LAYER M5 ;
        RECT  21.264 0 21.288 0.084 ;
    END
  END r_bf16[46]
  PIN r_bf16[47]
    DIRECTION INPUT ;
    USE SIGNAL ;
    PORT
      LAYER M5 ;
        RECT  21.36 0 21.384 0.084 ;
    END
  END r_bf16[47]
  PIN r_bf16[48]
    DIRECTION INPUT ;
    USE SIGNAL ;
    PORT
      LAYER M5 ;
        RECT  21.456 0 21.48 0.084 ;
    END
  END r_bf16[48]
  PIN r_bf16[49]
    DIRECTION INPUT ;
    USE SIGNAL ;
    PORT
      LAYER M5 ;
        RECT  21.552 0 21.576 0.084 ;
    END
  END r_bf16[49]
  PIN r_bf16[4]
    DIRECTION INPUT ;
    USE SIGNAL ;
    PORT
      LAYER M5 ;
        RECT  1.104 0 1.128 0.084 ;
    END
  END r_bf16[4]
  PIN r_bf16[50]
    DIRECTION INPUT ;
    USE SIGNAL ;
    PORT
      LAYER M5 ;
        RECT  21.648 0 21.672 0.084 ;
    END
  END r_bf16[50]
  PIN r_bf16[51]
    DIRECTION INPUT ;
    USE SIGNAL ;
    PORT
      LAYER M5 ;
        RECT  21.744 0 21.768 0.084 ;
    END
  END r_bf16[51]
  PIN r_bf16[52]
    DIRECTION INPUT ;
    USE SIGNAL ;
    PORT
      LAYER M5 ;
        RECT  21.84 0 21.864 0.084 ;
    END
  END r_bf16[52]
  PIN r_bf16[53]
    DIRECTION INPUT ;
    USE SIGNAL ;
    PORT
      LAYER M5 ;
        RECT  21.936 0 21.96 0.084 ;
    END
  END r_bf16[53]
  PIN r_bf16[54]
    DIRECTION INPUT ;
    USE SIGNAL ;
    PORT
      LAYER M5 ;
        RECT  22.032 0 22.056 0.084 ;
    END
  END r_bf16[54]
  PIN r_bf16[55]
    DIRECTION INPUT ;
    USE SIGNAL ;
    PORT
      LAYER M5 ;
        RECT  22.128 0 22.152 0.084 ;
    END
  END r_bf16[55]
  PIN r_bf16[56]
    DIRECTION INPUT ;
    USE SIGNAL ;
    PORT
      LAYER M5 ;
        RECT  22.224 0 22.248 0.084 ;
    END
  END r_bf16[56]
  PIN r_bf16[57]
    DIRECTION INPUT ;
    USE SIGNAL ;
    PORT
      LAYER M5 ;
        RECT  22.32 0 22.344 0.084 ;
    END
  END r_bf16[57]
  PIN r_bf16[58]
    DIRECTION INPUT ;
    USE SIGNAL ;
    PORT
      LAYER M5 ;
        RECT  22.416 0 22.44 0.084 ;
    END
  END r_bf16[58]
  PIN r_bf16[59]
    DIRECTION INPUT ;
    USE SIGNAL ;
    PORT
      LAYER M5 ;
        RECT  22.512 0 22.536 0.084 ;
    END
  END r_bf16[59]
  PIN r_bf16[5]
    DIRECTION INPUT ;
    USE SIGNAL ;
    PORT
      LAYER M5 ;
        RECT  1.2 0 1.224 0.084 ;
    END
  END r_bf16[5]
  PIN r_bf16[60]
    DIRECTION INPUT ;
    USE SIGNAL ;
    PORT
      LAYER M5 ;
        RECT  22.608 0 22.632 0.084 ;
    END
  END r_bf16[60]
  PIN r_bf16[61]
    DIRECTION INPUT ;
    USE SIGNAL ;
    PORT
      LAYER M5 ;
        RECT  22.704 0 22.728 0.084 ;
    END
  END r_bf16[61]
  PIN r_bf16[62]
    DIRECTION INPUT ;
    USE SIGNAL ;
    PORT
      LAYER M5 ;
        RECT  22.8 0 22.824 0.084 ;
    END
  END r_bf16[62]
  PIN r_bf16[63]
    DIRECTION INPUT ;
    USE SIGNAL ;
    PORT
      LAYER M5 ;
        RECT  22.896 0 22.92 0.084 ;
    END
  END r_bf16[63]
  PIN r_bf16[64]
    DIRECTION INPUT ;
    USE SIGNAL ;
    PORT
      LAYER M5 ;
        RECT  6.864 0 6.888 0.084 ;
    END
  END r_bf16[64]
  PIN r_bf16[65]
    DIRECTION INPUT ;
    USE SIGNAL ;
    PORT
      LAYER M5 ;
        RECT  6.96 0 6.984 0.084 ;
    END
  END r_bf16[65]
  PIN r_bf16[66]
    DIRECTION INPUT ;
    USE SIGNAL ;
    PORT
      LAYER M5 ;
        RECT  7.056 0 7.08 0.084 ;
    END
  END r_bf16[66]
  PIN r_bf16[67]
    DIRECTION INPUT ;
    USE SIGNAL ;
    PORT
      LAYER M5 ;
        RECT  7.152 0 7.176 0.084 ;
    END
  END r_bf16[67]
  PIN r_bf16[68]
    DIRECTION INPUT ;
    USE SIGNAL ;
    PORT
      LAYER M5 ;
        RECT  7.248 0 7.272 0.084 ;
    END
  END r_bf16[68]
  PIN r_bf16[69]
    DIRECTION INPUT ;
    USE SIGNAL ;
    PORT
      LAYER M5 ;
        RECT  7.344 0 7.368 0.084 ;
    END
  END r_bf16[69]
  PIN r_bf16[6]
    DIRECTION INPUT ;
    USE SIGNAL ;
    PORT
      LAYER M5 ;
        RECT  1.296 0 1.32 0.084 ;
    END
  END r_bf16[6]
  PIN r_bf16[70]
    DIRECTION INPUT ;
    USE SIGNAL ;
    PORT
      LAYER M5 ;
        RECT  7.44 0 7.464 0.084 ;
    END
  END r_bf16[70]
  PIN r_bf16[71]
    DIRECTION INPUT ;
    USE SIGNAL ;
    PORT
      LAYER M5 ;
        RECT  7.536 0 7.56 0.084 ;
    END
  END r_bf16[71]
  PIN r_bf16[72]
    DIRECTION INPUT ;
    USE SIGNAL ;
    PORT
      LAYER M5 ;
        RECT  7.632 0 7.656 0.084 ;
    END
  END r_bf16[72]
  PIN r_bf16[73]
    DIRECTION INPUT ;
    USE SIGNAL ;
    PORT
      LAYER M5 ;
        RECT  7.728 0 7.752 0.084 ;
    END
  END r_bf16[73]
  PIN r_bf16[74]
    DIRECTION INPUT ;
    USE SIGNAL ;
    PORT
      LAYER M5 ;
        RECT  7.824 0 7.848 0.084 ;
    END
  END r_bf16[74]
  PIN r_bf16[75]
    DIRECTION INPUT ;
    USE SIGNAL ;
    PORT
      LAYER M5 ;
        RECT  7.92 0 7.944 0.084 ;
    END
  END r_bf16[75]
  PIN r_bf16[76]
    DIRECTION INPUT ;
    USE SIGNAL ;
    PORT
      LAYER M5 ;
        RECT  8.016 0 8.04 0.084 ;
    END
  END r_bf16[76]
  PIN r_bf16[77]
    DIRECTION INPUT ;
    USE SIGNAL ;
    PORT
      LAYER M5 ;
        RECT  8.112 0 8.136 0.084 ;
    END
  END r_bf16[77]
  PIN r_bf16[78]
    DIRECTION INPUT ;
    USE SIGNAL ;
    PORT
      LAYER M5 ;
        RECT  8.208 0 8.232 0.084 ;
    END
  END r_bf16[78]
  PIN r_bf16[79]
    DIRECTION INPUT ;
    USE SIGNAL ;
    PORT
      LAYER M5 ;
        RECT  8.304 0 8.328 0.084 ;
    END
  END r_bf16[79]
  PIN r_bf16[7]
    DIRECTION INPUT ;
    USE SIGNAL ;
    PORT
      LAYER M5 ;
        RECT  1.392 0 1.416 0.084 ;
    END
  END r_bf16[7]
  PIN r_bf16[80]
    DIRECTION INPUT ;
    USE SIGNAL ;
    PORT
      LAYER M5 ;
        RECT  8.4 0 8.424 0.084 ;
    END
  END r_bf16[80]
  PIN r_bf16[81]
    DIRECTION INPUT ;
    USE SIGNAL ;
    PORT
      LAYER M5 ;
        RECT  8.496 0 8.52 0.084 ;
    END
  END r_bf16[81]
  PIN r_bf16[82]
    DIRECTION INPUT ;
    USE SIGNAL ;
    PORT
      LAYER M5 ;
        RECT  8.592 0 8.616 0.084 ;
    END
  END r_bf16[82]
  PIN r_bf16[83]
    DIRECTION INPUT ;
    USE SIGNAL ;
    PORT
      LAYER M5 ;
        RECT  8.688 0 8.712 0.084 ;
    END
  END r_bf16[83]
  PIN r_bf16[84]
    DIRECTION INPUT ;
    USE SIGNAL ;
    PORT
      LAYER M5 ;
        RECT  8.784 0 8.808 0.084 ;
    END
  END r_bf16[84]
  PIN r_bf16[85]
    DIRECTION INPUT ;
    USE SIGNAL ;
    PORT
      LAYER M5 ;
        RECT  8.88 0 8.904 0.084 ;
    END
  END r_bf16[85]
  PIN r_bf16[86]
    DIRECTION INPUT ;
    USE SIGNAL ;
    PORT
      LAYER M5 ;
        RECT  8.976 0 9 0.084 ;
    END
  END r_bf16[86]
  PIN r_bf16[87]
    DIRECTION INPUT ;
    USE SIGNAL ;
    PORT
      LAYER M5 ;
        RECT  9.072 0 9.096 0.084 ;
    END
  END r_bf16[87]
  PIN r_bf16[88]
    DIRECTION INPUT ;
    USE SIGNAL ;
    PORT
      LAYER M5 ;
        RECT  9.168 0 9.192 0.084 ;
    END
  END r_bf16[88]
  PIN r_bf16[89]
    DIRECTION INPUT ;
    USE SIGNAL ;
    PORT
      LAYER M5 ;
        RECT  9.264 0 9.288 0.084 ;
    END
  END r_bf16[89]
  PIN r_bf16[8]
    DIRECTION INPUT ;
    USE SIGNAL ;
    PORT
      LAYER M5 ;
        RECT  1.488 0 1.512 0.084 ;
    END
  END r_bf16[8]
  PIN r_bf16[90]
    DIRECTION INPUT ;
    USE SIGNAL ;
    PORT
      LAYER M5 ;
        RECT  9.36 0 9.384 0.084 ;
    END
  END r_bf16[90]
  PIN r_bf16[91]
    DIRECTION INPUT ;
    USE SIGNAL ;
    PORT
      LAYER M5 ;
        RECT  9.456 0 9.48 0.084 ;
    END
  END r_bf16[91]
  PIN r_bf16[92]
    DIRECTION INPUT ;
    USE SIGNAL ;
    PORT
      LAYER M5 ;
        RECT  9.552 0 9.576 0.084 ;
    END
  END r_bf16[92]
  PIN r_bf16[93]
    DIRECTION INPUT ;
    USE SIGNAL ;
    PORT
      LAYER M5 ;
        RECT  9.648 0 9.672 0.084 ;
    END
  END r_bf16[93]
  PIN r_bf16[94]
    DIRECTION INPUT ;
    USE SIGNAL ;
    PORT
      LAYER M5 ;
        RECT  9.744 0 9.768 0.084 ;
    END
  END r_bf16[94]
  PIN r_bf16[95]
    DIRECTION INPUT ;
    USE SIGNAL ;
    PORT
      LAYER M5 ;
        RECT  9.84 0 9.864 0.084 ;
    END
  END r_bf16[95]
  PIN r_bf16[96]
    DIRECTION INPUT ;
    USE SIGNAL ;
    PORT
      LAYER M5 ;
        RECT  29.136 0 29.16 0.084 ;
    END
  END r_bf16[96]
  PIN r_bf16[97]
    DIRECTION INPUT ;
    USE SIGNAL ;
    PORT
      LAYER M5 ;
        RECT  29.232 0 29.256 0.084 ;
    END
  END r_bf16[97]
  PIN r_bf16[98]
    DIRECTION INPUT ;
    USE SIGNAL ;
    PORT
      LAYER M5 ;
        RECT  29.328 0 29.352 0.084 ;
    END
  END r_bf16[98]
  PIN r_bf16[99]
    DIRECTION INPUT ;
    USE SIGNAL ;
    PORT
      LAYER M5 ;
        RECT  29.424 0 29.448 0.084 ;
    END
  END r_bf16[99]
  PIN r_bf16[9]
    DIRECTION INPUT ;
    USE SIGNAL ;
    PORT
      LAYER M5 ;
        RECT  1.584 0 1.608 0.084 ;
    END
  END r_bf16[9]
  PIN r_e[0]
    DIRECTION INPUT ;
    USE SIGNAL ;
    PORT
      LAYER M5 ;
        RECT  42.192 0 42.216 0.084 ;
    END
  END r_e[0]
  PIN r_e[1]
    DIRECTION INPUT ;
    USE SIGNAL ;
    PORT
      LAYER M5 ;
        RECT  42.288 0 42.312 0.084 ;
    END
  END r_e[1]
  PIN r_e[2]
    DIRECTION INPUT ;
    USE SIGNAL ;
    PORT
      LAYER M5 ;
        RECT  42.384 0 42.408 0.084 ;
    END
  END r_e[2]
  PIN r_e[3]
    DIRECTION INPUT ;
    USE SIGNAL ;
    PORT
      LAYER M5 ;
        RECT  42.48 0 42.504 0.084 ;
    END
  END r_e[3]
  PIN r_e[4]
    DIRECTION INPUT ;
    USE SIGNAL ;
    PORT
      LAYER M5 ;
        RECT  42.576 0 42.6 0.084 ;
    END
  END r_e[4]
  PIN r_e[5]
    DIRECTION INPUT ;
    USE SIGNAL ;
    PORT
      LAYER M5 ;
        RECT  42.672 0 42.696 0.084 ;
    END
  END r_e[5]
  PIN r_e[6]
    DIRECTION INPUT ;
    USE SIGNAL ;
    PORT
      LAYER M5 ;
        RECT  42.768 0 42.792 0.084 ;
    END
  END r_e[6]
  PIN r_e[7]
    DIRECTION INPUT ;
    USE SIGNAL ;
    PORT
      LAYER M5 ;
        RECT  42.864 0 42.888 0.084 ;
    END
  END r_e[7]
  PIN r_fp32[0]
    DIRECTION INPUT ;
    USE SIGNAL ;
    PORT
      LAYER M5 ;
        RECT  42.96 0 42.984 0.084 ;
    END
  END r_fp32[0]
  PIN r_fp32[100]
    DIRECTION INPUT ;
    USE SIGNAL ;
    PORT
      LAYER M5 ;
        RECT  27.216 0 27.24 0.084 ;
    END
  END r_fp32[100]
  PIN r_fp32[101]
    DIRECTION INPUT ;
    USE SIGNAL ;
    PORT
      LAYER M5 ;
        RECT  27.312 0 27.336 0.084 ;
    END
  END r_fp32[101]
  PIN r_fp32[102]
    DIRECTION INPUT ;
    USE SIGNAL ;
    PORT
      LAYER M5 ;
        RECT  27.408 0 27.432 0.084 ;
    END
  END r_fp32[102]
  PIN r_fp32[103]
    DIRECTION INPUT ;
    USE SIGNAL ;
    PORT
      LAYER M5 ;
        RECT  27.504 0 27.528 0.084 ;
    END
  END r_fp32[103]
  PIN r_fp32[104]
    DIRECTION INPUT ;
    USE SIGNAL ;
    PORT
      LAYER M5 ;
        RECT  27.6 0 27.624 0.084 ;
    END
  END r_fp32[104]
  PIN r_fp32[105]
    DIRECTION INPUT ;
    USE SIGNAL ;
    PORT
      LAYER M5 ;
        RECT  27.696 0 27.72 0.084 ;
    END
  END r_fp32[105]
  PIN r_fp32[106]
    DIRECTION INPUT ;
    USE SIGNAL ;
    PORT
      LAYER M5 ;
        RECT  27.792 0 27.816 0.084 ;
    END
  END r_fp32[106]
  PIN r_fp32[107]
    DIRECTION INPUT ;
    USE SIGNAL ;
    PORT
      LAYER M5 ;
        RECT  27.888 0 27.912 0.084 ;
    END
  END r_fp32[107]
  PIN r_fp32[108]
    DIRECTION INPUT ;
    USE SIGNAL ;
    PORT
      LAYER M5 ;
        RECT  27.984 0 28.008 0.084 ;
    END
  END r_fp32[108]
  PIN r_fp32[109]
    DIRECTION INPUT ;
    USE SIGNAL ;
    PORT
      LAYER M5 ;
        RECT  28.08 0 28.104 0.084 ;
    END
  END r_fp32[109]
  PIN r_fp32[10]
    DIRECTION INPUT ;
    USE SIGNAL ;
    PORT
      LAYER M5 ;
        RECT  43.92 0 43.944 0.084 ;
    END
  END r_fp32[10]
  PIN r_fp32[110]
    DIRECTION INPUT ;
    USE SIGNAL ;
    PORT
      LAYER M5 ;
        RECT  28.176 0 28.2 0.084 ;
    END
  END r_fp32[110]
  PIN r_fp32[111]
    DIRECTION INPUT ;
    USE SIGNAL ;
    PORT
      LAYER M5 ;
        RECT  28.272 0 28.296 0.084 ;
    END
  END r_fp32[111]
  PIN r_fp32[112]
    DIRECTION INPUT ;
    USE SIGNAL ;
    PORT
      LAYER M5 ;
        RECT  28.368 0 28.392 0.084 ;
    END
  END r_fp32[112]
  PIN r_fp32[113]
    DIRECTION INPUT ;
    USE SIGNAL ;
    PORT
      LAYER M5 ;
        RECT  28.464 0 28.488 0.084 ;
    END
  END r_fp32[113]
  PIN r_fp32[114]
    DIRECTION INPUT ;
    USE SIGNAL ;
    PORT
      LAYER M5 ;
        RECT  28.56 0 28.584 0.084 ;
    END
  END r_fp32[114]
  PIN r_fp32[115]
    DIRECTION INPUT ;
    USE SIGNAL ;
    PORT
      LAYER M5 ;
        RECT  28.656 0 28.68 0.084 ;
    END
  END r_fp32[115]
  PIN r_fp32[116]
    DIRECTION INPUT ;
    USE SIGNAL ;
    PORT
      LAYER M5 ;
        RECT  28.752 0 28.776 0.084 ;
    END
  END r_fp32[116]
  PIN r_fp32[117]
    DIRECTION INPUT ;
    USE SIGNAL ;
    PORT
      LAYER M5 ;
        RECT  28.848 0 28.872 0.084 ;
    END
  END r_fp32[117]
  PIN r_fp32[118]
    DIRECTION INPUT ;
    USE SIGNAL ;
    PORT
      LAYER M5 ;
        RECT  28.944 0 28.968 0.084 ;
    END
  END r_fp32[118]
  PIN r_fp32[119]
    DIRECTION INPUT ;
    USE SIGNAL ;
    PORT
      LAYER M5 ;
        RECT  29.04 0 29.064 0.084 ;
    END
  END r_fp32[119]
  PIN r_fp32[11]
    DIRECTION INPUT ;
    USE SIGNAL ;
    PORT
      LAYER M5 ;
        RECT  44.016 0 44.04 0.084 ;
    END
  END r_fp32[11]
  PIN r_fp32[120]
    DIRECTION INPUT ;
    USE SIGNAL ;
    PORT
      LAYER M5 ;
        RECT  35.28 0 35.304 0.084 ;
    END
  END r_fp32[120]
  PIN r_fp32[121]
    DIRECTION INPUT ;
    USE SIGNAL ;
    PORT
      LAYER M5 ;
        RECT  35.376 0 35.4 0.084 ;
    END
  END r_fp32[121]
  PIN r_fp32[122]
    DIRECTION INPUT ;
    USE SIGNAL ;
    PORT
      LAYER M5 ;
        RECT  35.472 0 35.496 0.084 ;
    END
  END r_fp32[122]
  PIN r_fp32[123]
    DIRECTION INPUT ;
    USE SIGNAL ;
    PORT
      LAYER M5 ;
        RECT  35.568 0 35.592 0.084 ;
    END
  END r_fp32[123]
  PIN r_fp32[124]
    DIRECTION INPUT ;
    USE SIGNAL ;
    PORT
      LAYER M5 ;
        RECT  35.664 0 35.688 0.084 ;
    END
  END r_fp32[124]
  PIN r_fp32[125]
    DIRECTION INPUT ;
    USE SIGNAL ;
    PORT
      LAYER M5 ;
        RECT  35.76 0 35.784 0.084 ;
    END
  END r_fp32[125]
  PIN r_fp32[126]
    DIRECTION INPUT ;
    USE SIGNAL ;
    PORT
      LAYER M5 ;
        RECT  35.856 0 35.88 0.084 ;
    END
  END r_fp32[126]
  PIN r_fp32[127]
    DIRECTION INPUT ;
    USE SIGNAL ;
    PORT
      LAYER M5 ;
        RECT  35.952 0 35.976 0.084 ;
    END
  END r_fp32[127]
  PIN r_fp32[128]
    DIRECTION INPUT ;
    USE SIGNAL ;
    PORT
      LAYER M5 ;
        RECT  36.048 0 36.072 0.084 ;
    END
  END r_fp32[128]
  PIN r_fp32[129]
    DIRECTION INPUT ;
    USE SIGNAL ;
    PORT
      LAYER M5 ;
        RECT  36.144 0 36.168 0.084 ;
    END
  END r_fp32[129]
  PIN r_fp32[12]
    DIRECTION INPUT ;
    USE SIGNAL ;
    PORT
      LAYER M5 ;
        RECT  44.112 0 44.136 0.084 ;
    END
  END r_fp32[12]
  PIN r_fp32[130]
    DIRECTION INPUT ;
    USE SIGNAL ;
    PORT
      LAYER M5 ;
        RECT  36.24 0 36.264 0.084 ;
    END
  END r_fp32[130]
  PIN r_fp32[131]
    DIRECTION INPUT ;
    USE SIGNAL ;
    PORT
      LAYER M5 ;
        RECT  36.336 0 36.36 0.084 ;
    END
  END r_fp32[131]
  PIN r_fp32[132]
    DIRECTION INPUT ;
    USE SIGNAL ;
    PORT
      LAYER M5 ;
        RECT  36.432 0 36.456 0.084 ;
    END
  END r_fp32[132]
  PIN r_fp32[133]
    DIRECTION INPUT ;
    USE SIGNAL ;
    PORT
      LAYER M5 ;
        RECT  36.528 0 36.552 0.084 ;
    END
  END r_fp32[133]
  PIN r_fp32[134]
    DIRECTION INPUT ;
    USE SIGNAL ;
    PORT
      LAYER M5 ;
        RECT  36.624 0 36.648 0.084 ;
    END
  END r_fp32[134]
  PIN r_fp32[135]
    DIRECTION INPUT ;
    USE SIGNAL ;
    PORT
      LAYER M5 ;
        RECT  36.72 0 36.744 0.084 ;
    END
  END r_fp32[135]
  PIN r_fp32[136]
    DIRECTION INPUT ;
    USE SIGNAL ;
    PORT
      LAYER M5 ;
        RECT  36.816 0 36.84 0.084 ;
    END
  END r_fp32[136]
  PIN r_fp32[137]
    DIRECTION INPUT ;
    USE SIGNAL ;
    PORT
      LAYER M5 ;
        RECT  36.912 0 36.936 0.084 ;
    END
  END r_fp32[137]
  PIN r_fp32[138]
    DIRECTION INPUT ;
    USE SIGNAL ;
    PORT
      LAYER M5 ;
        RECT  37.008 0 37.032 0.084 ;
    END
  END r_fp32[138]
  PIN r_fp32[139]
    DIRECTION INPUT ;
    USE SIGNAL ;
    PORT
      LAYER M5 ;
        RECT  37.104 0 37.128 0.084 ;
    END
  END r_fp32[139]
  PIN r_fp32[13]
    DIRECTION INPUT ;
    USE SIGNAL ;
    PORT
      LAYER M5 ;
        RECT  44.208 0 44.232 0.084 ;
    END
  END r_fp32[13]
  PIN r_fp32[140]
    DIRECTION INPUT ;
    USE SIGNAL ;
    PORT
      LAYER M5 ;
        RECT  37.2 0 37.224 0.084 ;
    END
  END r_fp32[140]
  PIN r_fp32[141]
    DIRECTION INPUT ;
    USE SIGNAL ;
    PORT
      LAYER M5 ;
        RECT  37.296 0 37.32 0.084 ;
    END
  END r_fp32[141]
  PIN r_fp32[142]
    DIRECTION INPUT ;
    USE SIGNAL ;
    PORT
      LAYER M5 ;
        RECT  37.392 0 37.416 0.084 ;
    END
  END r_fp32[142]
  PIN r_fp32[143]
    DIRECTION INPUT ;
    USE SIGNAL ;
    PORT
      LAYER M5 ;
        RECT  37.488 0 37.512 0.084 ;
    END
  END r_fp32[143]
  PIN r_fp32[144]
    DIRECTION INPUT ;
    USE SIGNAL ;
    PORT
      LAYER M5 ;
        RECT  37.584 0 37.608 0.084 ;
    END
  END r_fp32[144]
  PIN r_fp32[145]
    DIRECTION INPUT ;
    USE SIGNAL ;
    PORT
      LAYER M5 ;
        RECT  37.68 0 37.704 0.084 ;
    END
  END r_fp32[145]
  PIN r_fp32[146]
    DIRECTION INPUT ;
    USE SIGNAL ;
    PORT
      LAYER M5 ;
        RECT  37.776 0 37.8 0.084 ;
    END
  END r_fp32[146]
  PIN r_fp32[147]
    DIRECTION INPUT ;
    USE SIGNAL ;
    PORT
      LAYER M5 ;
        RECT  37.872 0 37.896 0.084 ;
    END
  END r_fp32[147]
  PIN r_fp32[148]
    DIRECTION INPUT ;
    USE SIGNAL ;
    PORT
      LAYER M5 ;
        RECT  37.968 0 37.992 0.084 ;
    END
  END r_fp32[148]
  PIN r_fp32[149]
    DIRECTION INPUT ;
    USE SIGNAL ;
    PORT
      LAYER M5 ;
        RECT  38.064 0 38.088 0.084 ;
    END
  END r_fp32[149]
  PIN r_fp32[14]
    DIRECTION INPUT ;
    USE SIGNAL ;
    PORT
      LAYER M5 ;
        RECT  44.304 0 44.328 0.084 ;
    END
  END r_fp32[14]
  PIN r_fp32[150]
    DIRECTION INPUT ;
    USE SIGNAL ;
    PORT
      LAYER M5 ;
        RECT  38.16 0 38.184 0.084 ;
    END
  END r_fp32[150]
  PIN r_fp32[151]
    DIRECTION INPUT ;
    USE SIGNAL ;
    PORT
      LAYER M5 ;
        RECT  38.256 0 38.28 0.084 ;
    END
  END r_fp32[151]
  PIN r_fp32[152]
    DIRECTION INPUT ;
    USE SIGNAL ;
    PORT
      LAYER M5 ;
        RECT  51.408 0 51.432 0.084 ;
    END
  END r_fp32[152]
  PIN r_fp32[153]
    DIRECTION INPUT ;
    USE SIGNAL ;
    PORT
      LAYER M5 ;
        RECT  51.504 0 51.528 0.084 ;
    END
  END r_fp32[153]
  PIN r_fp32[154]
    DIRECTION INPUT ;
    USE SIGNAL ;
    PORT
      LAYER M5 ;
        RECT  51.6 0 51.624 0.084 ;
    END
  END r_fp32[154]
  PIN r_fp32[155]
    DIRECTION INPUT ;
    USE SIGNAL ;
    PORT
      LAYER M5 ;
        RECT  51.696 0 51.72 0.084 ;
    END
  END r_fp32[155]
  PIN r_fp32[156]
    DIRECTION INPUT ;
    USE SIGNAL ;
    PORT
      LAYER M5 ;
        RECT  51.792 0 51.816 0.084 ;
    END
  END r_fp32[156]
  PIN r_fp32[157]
    DIRECTION INPUT ;
    USE SIGNAL ;
    PORT
      LAYER M5 ;
        RECT  51.888 0 51.912 0.084 ;
    END
  END r_fp32[157]
  PIN r_fp32[158]
    DIRECTION INPUT ;
    USE SIGNAL ;
    PORT
      LAYER M5 ;
        RECT  51.984 0 52.008 0.084 ;
    END
  END r_fp32[158]
  PIN r_fp32[159]
    DIRECTION INPUT ;
    USE SIGNAL ;
    PORT
      LAYER M5 ;
        RECT  52.08 0 52.104 0.084 ;
    END
  END r_fp32[159]
  PIN r_fp32[15]
    DIRECTION INPUT ;
    USE SIGNAL ;
    PORT
      LAYER M5 ;
        RECT  44.4 0 44.424 0.084 ;
    END
  END r_fp32[15]
  PIN r_fp32[160]
    DIRECTION INPUT ;
    USE SIGNAL ;
    PORT
      LAYER M5 ;
        RECT  52.176 0 52.2 0.084 ;
    END
  END r_fp32[160]
  PIN r_fp32[161]
    DIRECTION INPUT ;
    USE SIGNAL ;
    PORT
      LAYER M5 ;
        RECT  52.272 0 52.296 0.084 ;
    END
  END r_fp32[161]
  PIN r_fp32[162]
    DIRECTION INPUT ;
    USE SIGNAL ;
    PORT
      LAYER M5 ;
        RECT  52.368 0 52.392 0.084 ;
    END
  END r_fp32[162]
  PIN r_fp32[163]
    DIRECTION INPUT ;
    USE SIGNAL ;
    PORT
      LAYER M5 ;
        RECT  52.464 0 52.488 0.084 ;
    END
  END r_fp32[163]
  PIN r_fp32[164]
    DIRECTION INPUT ;
    USE SIGNAL ;
    PORT
      LAYER M5 ;
        RECT  52.56 0 52.584 0.084 ;
    END
  END r_fp32[164]
  PIN r_fp32[165]
    DIRECTION INPUT ;
    USE SIGNAL ;
    PORT
      LAYER M5 ;
        RECT  52.656 0 52.68 0.084 ;
    END
  END r_fp32[165]
  PIN r_fp32[166]
    DIRECTION INPUT ;
    USE SIGNAL ;
    PORT
      LAYER M5 ;
        RECT  52.752 0 52.776 0.084 ;
    END
  END r_fp32[166]
  PIN r_fp32[167]
    DIRECTION INPUT ;
    USE SIGNAL ;
    PORT
      LAYER M5 ;
        RECT  52.848 0 52.872 0.084 ;
    END
  END r_fp32[167]
  PIN r_fp32[168]
    DIRECTION INPUT ;
    USE SIGNAL ;
    PORT
      LAYER M5 ;
        RECT  52.944 0 52.968 0.084 ;
    END
  END r_fp32[168]
  PIN r_fp32[169]
    DIRECTION INPUT ;
    USE SIGNAL ;
    PORT
      LAYER M5 ;
        RECT  53.04 0 53.064 0.084 ;
    END
  END r_fp32[169]
  PIN r_fp32[16]
    DIRECTION INPUT ;
    USE SIGNAL ;
    PORT
      LAYER M5 ;
        RECT  44.496 0 44.52 0.084 ;
    END
  END r_fp32[16]
  PIN r_fp32[170]
    DIRECTION INPUT ;
    USE SIGNAL ;
    PORT
      LAYER M5 ;
        RECT  53.136 0 53.16 0.084 ;
    END
  END r_fp32[170]
  PIN r_fp32[171]
    DIRECTION INPUT ;
    USE SIGNAL ;
    PORT
      LAYER M5 ;
        RECT  53.232 0 53.256 0.084 ;
    END
  END r_fp32[171]
  PIN r_fp32[172]
    DIRECTION INPUT ;
    USE SIGNAL ;
    PORT
      LAYER M5 ;
        RECT  53.328 0 53.352 0.084 ;
    END
  END r_fp32[172]
  PIN r_fp32[173]
    DIRECTION INPUT ;
    USE SIGNAL ;
    PORT
      LAYER M5 ;
        RECT  53.424 0 53.448 0.084 ;
    END
  END r_fp32[173]
  PIN r_fp32[174]
    DIRECTION INPUT ;
    USE SIGNAL ;
    PORT
      LAYER M5 ;
        RECT  53.52 0 53.544 0.084 ;
    END
  END r_fp32[174]
  PIN r_fp32[175]
    DIRECTION INPUT ;
    USE SIGNAL ;
    PORT
      LAYER M5 ;
        RECT  53.616 0 53.64 0.084 ;
    END
  END r_fp32[175]
  PIN r_fp32[176]
    DIRECTION INPUT ;
    USE SIGNAL ;
    PORT
      LAYER M5 ;
        RECT  53.712 0 53.736 0.084 ;
    END
  END r_fp32[176]
  PIN r_fp32[177]
    DIRECTION INPUT ;
    USE SIGNAL ;
    PORT
      LAYER M5 ;
        RECT  53.808 0 53.832 0.084 ;
    END
  END r_fp32[177]
  PIN r_fp32[178]
    DIRECTION INPUT ;
    USE SIGNAL ;
    PORT
      LAYER M5 ;
        RECT  53.904 0 53.928 0.084 ;
    END
  END r_fp32[178]
  PIN r_fp32[179]
    DIRECTION INPUT ;
    USE SIGNAL ;
    PORT
      LAYER M5 ;
        RECT  54 0 54.024 0.084 ;
    END
  END r_fp32[179]
  PIN r_fp32[17]
    DIRECTION INPUT ;
    USE SIGNAL ;
    PORT
      LAYER M5 ;
        RECT  44.592 0 44.616 0.084 ;
    END
  END r_fp32[17]
  PIN r_fp32[180]
    DIRECTION INPUT ;
    USE SIGNAL ;
    PORT
      LAYER M5 ;
        RECT  54.096 0 54.12 0.084 ;
    END
  END r_fp32[180]
  PIN r_fp32[181]
    DIRECTION INPUT ;
    USE SIGNAL ;
    PORT
      LAYER M5 ;
        RECT  54.192 0 54.216 0.084 ;
    END
  END r_fp32[181]
  PIN r_fp32[182]
    DIRECTION INPUT ;
    USE SIGNAL ;
    PORT
      LAYER M5 ;
        RECT  54.288 0 54.312 0.084 ;
    END
  END r_fp32[182]
  PIN r_fp32[183]
    DIRECTION INPUT ;
    USE SIGNAL ;
    PORT
      LAYER M5 ;
        RECT  54.384 0 54.408 0.084 ;
    END
  END r_fp32[183]
  PIN r_fp32[184]
    DIRECTION INPUT ;
    USE SIGNAL ;
    PORT
      LAYER M5 ;
        RECT  48.336 0 48.36 0.084 ;
    END
  END r_fp32[184]
  PIN r_fp32[185]
    DIRECTION INPUT ;
    USE SIGNAL ;
    PORT
      LAYER M5 ;
        RECT  48.432 0 48.456 0.084 ;
    END
  END r_fp32[185]
  PIN r_fp32[186]
    DIRECTION INPUT ;
    USE SIGNAL ;
    PORT
      LAYER M5 ;
        RECT  48.528 0 48.552 0.084 ;
    END
  END r_fp32[186]
  PIN r_fp32[187]
    DIRECTION INPUT ;
    USE SIGNAL ;
    PORT
      LAYER M5 ;
        RECT  48.624 0 48.648 0.084 ;
    END
  END r_fp32[187]
  PIN r_fp32[188]
    DIRECTION INPUT ;
    USE SIGNAL ;
    PORT
      LAYER M5 ;
        RECT  48.72 0 48.744 0.084 ;
    END
  END r_fp32[188]
  PIN r_fp32[189]
    DIRECTION INPUT ;
    USE SIGNAL ;
    PORT
      LAYER M5 ;
        RECT  48.816 0 48.84 0.084 ;
    END
  END r_fp32[189]
  PIN r_fp32[18]
    DIRECTION INPUT ;
    USE SIGNAL ;
    PORT
      LAYER M5 ;
        RECT  44.688 0 44.712 0.084 ;
    END
  END r_fp32[18]
  PIN r_fp32[190]
    DIRECTION INPUT ;
    USE SIGNAL ;
    PORT
      LAYER M5 ;
        RECT  48.912 0 48.936 0.084 ;
    END
  END r_fp32[190]
  PIN r_fp32[191]
    DIRECTION INPUT ;
    USE SIGNAL ;
    PORT
      LAYER M5 ;
        RECT  49.008 0 49.032 0.084 ;
    END
  END r_fp32[191]
  PIN r_fp32[192]
    DIRECTION INPUT ;
    USE SIGNAL ;
    PORT
      LAYER M5 ;
        RECT  49.104 0 49.128 0.084 ;
    END
  END r_fp32[192]
  PIN r_fp32[193]
    DIRECTION INPUT ;
    USE SIGNAL ;
    PORT
      LAYER M5 ;
        RECT  49.2 0 49.224 0.084 ;
    END
  END r_fp32[193]
  PIN r_fp32[194]
    DIRECTION INPUT ;
    USE SIGNAL ;
    PORT
      LAYER M5 ;
        RECT  49.296 0 49.32 0.084 ;
    END
  END r_fp32[194]
  PIN r_fp32[195]
    DIRECTION INPUT ;
    USE SIGNAL ;
    PORT
      LAYER M5 ;
        RECT  49.392 0 49.416 0.084 ;
    END
  END r_fp32[195]
  PIN r_fp32[196]
    DIRECTION INPUT ;
    USE SIGNAL ;
    PORT
      LAYER M5 ;
        RECT  49.488 0 49.512 0.084 ;
    END
  END r_fp32[196]
  PIN r_fp32[197]
    DIRECTION INPUT ;
    USE SIGNAL ;
    PORT
      LAYER M5 ;
        RECT  49.584 0 49.608 0.084 ;
    END
  END r_fp32[197]
  PIN r_fp32[198]
    DIRECTION INPUT ;
    USE SIGNAL ;
    PORT
      LAYER M5 ;
        RECT  49.68 0 49.704 0.084 ;
    END
  END r_fp32[198]
  PIN r_fp32[199]
    DIRECTION INPUT ;
    USE SIGNAL ;
    PORT
      LAYER M5 ;
        RECT  49.776 0 49.8 0.084 ;
    END
  END r_fp32[199]
  PIN r_fp32[19]
    DIRECTION INPUT ;
    USE SIGNAL ;
    PORT
      LAYER M5 ;
        RECT  44.784 0 44.808 0.084 ;
    END
  END r_fp32[19]
  PIN r_fp32[1]
    DIRECTION INPUT ;
    USE SIGNAL ;
    PORT
      LAYER M5 ;
        RECT  43.056 0 43.08 0.084 ;
    END
  END r_fp32[1]
  PIN r_fp32[200]
    DIRECTION INPUT ;
    USE SIGNAL ;
    PORT
      LAYER M5 ;
        RECT  49.872 0 49.896 0.084 ;
    END
  END r_fp32[200]
  PIN r_fp32[201]
    DIRECTION INPUT ;
    USE SIGNAL ;
    PORT
      LAYER M5 ;
        RECT  49.968 0 49.992 0.084 ;
    END
  END r_fp32[201]
  PIN r_fp32[202]
    DIRECTION INPUT ;
    USE SIGNAL ;
    PORT
      LAYER M5 ;
        RECT  50.064 0 50.088 0.084 ;
    END
  END r_fp32[202]
  PIN r_fp32[203]
    DIRECTION INPUT ;
    USE SIGNAL ;
    PORT
      LAYER M5 ;
        RECT  50.16 0 50.184 0.084 ;
    END
  END r_fp32[203]
  PIN r_fp32[204]
    DIRECTION INPUT ;
    USE SIGNAL ;
    PORT
      LAYER M5 ;
        RECT  50.256 0 50.28 0.084 ;
    END
  END r_fp32[204]
  PIN r_fp32[205]
    DIRECTION INPUT ;
    USE SIGNAL ;
    PORT
      LAYER M5 ;
        RECT  50.352 0 50.376 0.084 ;
    END
  END r_fp32[205]
  PIN r_fp32[206]
    DIRECTION INPUT ;
    USE SIGNAL ;
    PORT
      LAYER M5 ;
        RECT  50.448 0 50.472 0.084 ;
    END
  END r_fp32[206]
  PIN r_fp32[207]
    DIRECTION INPUT ;
    USE SIGNAL ;
    PORT
      LAYER M5 ;
        RECT  50.544 0 50.568 0.084 ;
    END
  END r_fp32[207]
  PIN r_fp32[208]
    DIRECTION INPUT ;
    USE SIGNAL ;
    PORT
      LAYER M5 ;
        RECT  50.64 0 50.664 0.084 ;
    END
  END r_fp32[208]
  PIN r_fp32[209]
    DIRECTION INPUT ;
    USE SIGNAL ;
    PORT
      LAYER M5 ;
        RECT  50.736 0 50.76 0.084 ;
    END
  END r_fp32[209]
  PIN r_fp32[20]
    DIRECTION INPUT ;
    USE SIGNAL ;
    PORT
      LAYER M5 ;
        RECT  44.88 0 44.904 0.084 ;
    END
  END r_fp32[20]
  PIN r_fp32[210]
    DIRECTION INPUT ;
    USE SIGNAL ;
    PORT
      LAYER M5 ;
        RECT  50.832 0 50.856 0.084 ;
    END
  END r_fp32[210]
  PIN r_fp32[211]
    DIRECTION INPUT ;
    USE SIGNAL ;
    PORT
      LAYER M5 ;
        RECT  50.928 0 50.952 0.084 ;
    END
  END r_fp32[211]
  PIN r_fp32[212]
    DIRECTION INPUT ;
    USE SIGNAL ;
    PORT
      LAYER M5 ;
        RECT  51.024 0 51.048 0.084 ;
    END
  END r_fp32[212]
  PIN r_fp32[213]
    DIRECTION INPUT ;
    USE SIGNAL ;
    PORT
      LAYER M5 ;
        RECT  51.12 0 51.144 0.084 ;
    END
  END r_fp32[213]
  PIN r_fp32[214]
    DIRECTION INPUT ;
    USE SIGNAL ;
    PORT
      LAYER M5 ;
        RECT  51.216 0 51.24 0.084 ;
    END
  END r_fp32[214]
  PIN r_fp32[215]
    DIRECTION INPUT ;
    USE SIGNAL ;
    PORT
      LAYER M5 ;
        RECT  51.312 0 51.336 0.084 ;
    END
  END r_fp32[215]
  PIN r_fp32[216]
    DIRECTION INPUT ;
    USE SIGNAL ;
    PORT
      LAYER M5 ;
        RECT  32.208 0 32.232 0.084 ;
    END
  END r_fp32[216]
  PIN r_fp32[217]
    DIRECTION INPUT ;
    USE SIGNAL ;
    PORT
      LAYER M5 ;
        RECT  32.304 0 32.328 0.084 ;
    END
  END r_fp32[217]
  PIN r_fp32[218]
    DIRECTION INPUT ;
    USE SIGNAL ;
    PORT
      LAYER M5 ;
        RECT  32.4 0 32.424 0.084 ;
    END
  END r_fp32[218]
  PIN r_fp32[219]
    DIRECTION INPUT ;
    USE SIGNAL ;
    PORT
      LAYER M5 ;
        RECT  32.496 0 32.52 0.084 ;
    END
  END r_fp32[219]
  PIN r_fp32[21]
    DIRECTION INPUT ;
    USE SIGNAL ;
    PORT
      LAYER M5 ;
        RECT  44.976 0 45 0.084 ;
    END
  END r_fp32[21]
  PIN r_fp32[220]
    DIRECTION INPUT ;
    USE SIGNAL ;
    PORT
      LAYER M5 ;
        RECT  32.592 0 32.616 0.084 ;
    END
  END r_fp32[220]
  PIN r_fp32[221]
    DIRECTION INPUT ;
    USE SIGNAL ;
    PORT
      LAYER M5 ;
        RECT  32.688 0 32.712 0.084 ;
    END
  END r_fp32[221]
  PIN r_fp32[222]
    DIRECTION INPUT ;
    USE SIGNAL ;
    PORT
      LAYER M5 ;
        RECT  32.784 0 32.808 0.084 ;
    END
  END r_fp32[222]
  PIN r_fp32[223]
    DIRECTION INPUT ;
    USE SIGNAL ;
    PORT
      LAYER M5 ;
        RECT  32.88 0 32.904 0.084 ;
    END
  END r_fp32[223]
  PIN r_fp32[224]
    DIRECTION INPUT ;
    USE SIGNAL ;
    PORT
      LAYER M5 ;
        RECT  32.976 0 33 0.084 ;
    END
  END r_fp32[224]
  PIN r_fp32[225]
    DIRECTION INPUT ;
    USE SIGNAL ;
    PORT
      LAYER M5 ;
        RECT  33.072 0 33.096 0.084 ;
    END
  END r_fp32[225]
  PIN r_fp32[226]
    DIRECTION INPUT ;
    USE SIGNAL ;
    PORT
      LAYER M5 ;
        RECT  33.168 0 33.192 0.084 ;
    END
  END r_fp32[226]
  PIN r_fp32[227]
    DIRECTION INPUT ;
    USE SIGNAL ;
    PORT
      LAYER M5 ;
        RECT  33.264 0 33.288 0.084 ;
    END
  END r_fp32[227]
  PIN r_fp32[228]
    DIRECTION INPUT ;
    USE SIGNAL ;
    PORT
      LAYER M5 ;
        RECT  33.36 0 33.384 0.084 ;
    END
  END r_fp32[228]
  PIN r_fp32[229]
    DIRECTION INPUT ;
    USE SIGNAL ;
    PORT
      LAYER M5 ;
        RECT  33.456 0 33.48 0.084 ;
    END
  END r_fp32[229]
  PIN r_fp32[22]
    DIRECTION INPUT ;
    USE SIGNAL ;
    PORT
      LAYER M5 ;
        RECT  45.072 0 45.096 0.084 ;
    END
  END r_fp32[22]
  PIN r_fp32[230]
    DIRECTION INPUT ;
    USE SIGNAL ;
    PORT
      LAYER M5 ;
        RECT  33.552 0 33.576 0.084 ;
    END
  END r_fp32[230]
  PIN r_fp32[231]
    DIRECTION INPUT ;
    USE SIGNAL ;
    PORT
      LAYER M5 ;
        RECT  33.648 0 33.672 0.084 ;
    END
  END r_fp32[231]
  PIN r_fp32[232]
    DIRECTION INPUT ;
    USE SIGNAL ;
    PORT
      LAYER M5 ;
        RECT  33.744 0 33.768 0.084 ;
    END
  END r_fp32[232]
  PIN r_fp32[233]
    DIRECTION INPUT ;
    USE SIGNAL ;
    PORT
      LAYER M5 ;
        RECT  33.84 0 33.864 0.084 ;
    END
  END r_fp32[233]
  PIN r_fp32[234]
    DIRECTION INPUT ;
    USE SIGNAL ;
    PORT
      LAYER M5 ;
        RECT  33.936 0 33.96 0.084 ;
    END
  END r_fp32[234]
  PIN r_fp32[235]
    DIRECTION INPUT ;
    USE SIGNAL ;
    PORT
      LAYER M5 ;
        RECT  34.032 0 34.056 0.084 ;
    END
  END r_fp32[235]
  PIN r_fp32[236]
    DIRECTION INPUT ;
    USE SIGNAL ;
    PORT
      LAYER M5 ;
        RECT  34.128 0 34.152 0.084 ;
    END
  END r_fp32[236]
  PIN r_fp32[237]
    DIRECTION INPUT ;
    USE SIGNAL ;
    PORT
      LAYER M5 ;
        RECT  34.224 0 34.248 0.084 ;
    END
  END r_fp32[237]
  PIN r_fp32[238]
    DIRECTION INPUT ;
    USE SIGNAL ;
    PORT
      LAYER M5 ;
        RECT  34.32 0 34.344 0.084 ;
    END
  END r_fp32[238]
  PIN r_fp32[239]
    DIRECTION INPUT ;
    USE SIGNAL ;
    PORT
      LAYER M5 ;
        RECT  34.416 0 34.44 0.084 ;
    END
  END r_fp32[239]
  PIN r_fp32[23]
    DIRECTION INPUT ;
    USE SIGNAL ;
    PORT
      LAYER M5 ;
        RECT  45.168 0 45.192 0.084 ;
    END
  END r_fp32[23]
  PIN r_fp32[240]
    DIRECTION INPUT ;
    USE SIGNAL ;
    PORT
      LAYER M5 ;
        RECT  34.512 0 34.536 0.084 ;
    END
  END r_fp32[240]
  PIN r_fp32[241]
    DIRECTION INPUT ;
    USE SIGNAL ;
    PORT
      LAYER M5 ;
        RECT  34.608 0 34.632 0.084 ;
    END
  END r_fp32[241]
  PIN r_fp32[242]
    DIRECTION INPUT ;
    USE SIGNAL ;
    PORT
      LAYER M5 ;
        RECT  34.704 0 34.728 0.084 ;
    END
  END r_fp32[242]
  PIN r_fp32[243]
    DIRECTION INPUT ;
    USE SIGNAL ;
    PORT
      LAYER M5 ;
        RECT  34.8 0 34.824 0.084 ;
    END
  END r_fp32[243]
  PIN r_fp32[244]
    DIRECTION INPUT ;
    USE SIGNAL ;
    PORT
      LAYER M5 ;
        RECT  34.896 0 34.92 0.084 ;
    END
  END r_fp32[244]
  PIN r_fp32[245]
    DIRECTION INPUT ;
    USE SIGNAL ;
    PORT
      LAYER M5 ;
        RECT  34.992 0 35.016 0.084 ;
    END
  END r_fp32[245]
  PIN r_fp32[246]
    DIRECTION INPUT ;
    USE SIGNAL ;
    PORT
      LAYER M5 ;
        RECT  35.088 0 35.112 0.084 ;
    END
  END r_fp32[246]
  PIN r_fp32[247]
    DIRECTION INPUT ;
    USE SIGNAL ;
    PORT
      LAYER M5 ;
        RECT  35.184 0 35.208 0.084 ;
    END
  END r_fp32[247]
  PIN r_fp32[248]
    DIRECTION INPUT ;
    USE SIGNAL ;
    PORT
      LAYER M5 ;
        RECT  39.12 0 39.144 0.084 ;
    END
  END r_fp32[248]
  PIN r_fp32[249]
    DIRECTION INPUT ;
    USE SIGNAL ;
    PORT
      LAYER M5 ;
        RECT  39.216 0 39.24 0.084 ;
    END
  END r_fp32[249]
  PIN r_fp32[24]
    DIRECTION INPUT ;
    USE SIGNAL ;
    PORT
      LAYER M5 ;
        RECT  45.264 0 45.288 0.084 ;
    END
  END r_fp32[24]
  PIN r_fp32[250]
    DIRECTION INPUT ;
    USE SIGNAL ;
    PORT
      LAYER M5 ;
        RECT  39.312 0 39.336 0.084 ;
    END
  END r_fp32[250]
  PIN r_fp32[251]
    DIRECTION INPUT ;
    USE SIGNAL ;
    PORT
      LAYER M5 ;
        RECT  39.408 0 39.432 0.084 ;
    END
  END r_fp32[251]
  PIN r_fp32[252]
    DIRECTION INPUT ;
    USE SIGNAL ;
    PORT
      LAYER M5 ;
        RECT  39.504 0 39.528 0.084 ;
    END
  END r_fp32[252]
  PIN r_fp32[253]
    DIRECTION INPUT ;
    USE SIGNAL ;
    PORT
      LAYER M5 ;
        RECT  39.6 0 39.624 0.084 ;
    END
  END r_fp32[253]
  PIN r_fp32[254]
    DIRECTION INPUT ;
    USE SIGNAL ;
    PORT
      LAYER M5 ;
        RECT  39.696 0 39.72 0.084 ;
    END
  END r_fp32[254]
  PIN r_fp32[255]
    DIRECTION INPUT ;
    USE SIGNAL ;
    PORT
      LAYER M5 ;
        RECT  39.792 0 39.816 0.084 ;
    END
  END r_fp32[255]
  PIN r_fp32[25]
    DIRECTION INPUT ;
    USE SIGNAL ;
    PORT
      LAYER M5 ;
        RECT  45.36 0 45.384 0.084 ;
    END
  END r_fp32[25]
  PIN r_fp32[26]
    DIRECTION INPUT ;
    USE SIGNAL ;
    PORT
      LAYER M5 ;
        RECT  45.456 0 45.48 0.084 ;
    END
  END r_fp32[26]
  PIN r_fp32[27]
    DIRECTION INPUT ;
    USE SIGNAL ;
    PORT
      LAYER M5 ;
        RECT  45.552 0 45.576 0.084 ;
    END
  END r_fp32[27]
  PIN r_fp32[28]
    DIRECTION INPUT ;
    USE SIGNAL ;
    PORT
      LAYER M5 ;
        RECT  45.648 0 45.672 0.084 ;
    END
  END r_fp32[28]
  PIN r_fp32[29]
    DIRECTION INPUT ;
    USE SIGNAL ;
    PORT
      LAYER M5 ;
        RECT  45.744 0 45.768 0.084 ;
    END
  END r_fp32[29]
  PIN r_fp32[2]
    DIRECTION INPUT ;
    USE SIGNAL ;
    PORT
      LAYER M5 ;
        RECT  43.152 0 43.176 0.084 ;
    END
  END r_fp32[2]
  PIN r_fp32[30]
    DIRECTION INPUT ;
    USE SIGNAL ;
    PORT
      LAYER M5 ;
        RECT  45.84 0 45.864 0.084 ;
    END
  END r_fp32[30]
  PIN r_fp32[31]
    DIRECTION INPUT ;
    USE SIGNAL ;
    PORT
      LAYER M5 ;
        RECT  45.936 0 45.96 0.084 ;
    END
  END r_fp32[31]
  PIN r_fp32[32]
    DIRECTION INPUT ;
    USE SIGNAL ;
    PORT
      LAYER M5 ;
        RECT  46.032 0 46.056 0.084 ;
    END
  END r_fp32[32]
  PIN r_fp32[33]
    DIRECTION INPUT ;
    USE SIGNAL ;
    PORT
      LAYER M5 ;
        RECT  46.128 0 46.152 0.084 ;
    END
  END r_fp32[33]
  PIN r_fp32[34]
    DIRECTION INPUT ;
    USE SIGNAL ;
    PORT
      LAYER M5 ;
        RECT  46.224 0 46.248 0.084 ;
    END
  END r_fp32[34]
  PIN r_fp32[35]
    DIRECTION INPUT ;
    USE SIGNAL ;
    PORT
      LAYER M5 ;
        RECT  46.32 0 46.344 0.084 ;
    END
  END r_fp32[35]
  PIN r_fp32[36]
    DIRECTION INPUT ;
    USE SIGNAL ;
    PORT
      LAYER M5 ;
        RECT  46.416 0 46.44 0.084 ;
    END
  END r_fp32[36]
  PIN r_fp32[37]
    DIRECTION INPUT ;
    USE SIGNAL ;
    PORT
      LAYER M5 ;
        RECT  46.512 0 46.536 0.084 ;
    END
  END r_fp32[37]
  PIN r_fp32[38]
    DIRECTION INPUT ;
    USE SIGNAL ;
    PORT
      LAYER M5 ;
        RECT  46.608 0 46.632 0.084 ;
    END
  END r_fp32[38]
  PIN r_fp32[39]
    DIRECTION INPUT ;
    USE SIGNAL ;
    PORT
      LAYER M5 ;
        RECT  46.704 0 46.728 0.084 ;
    END
  END r_fp32[39]
  PIN r_fp32[3]
    DIRECTION INPUT ;
    USE SIGNAL ;
    PORT
      LAYER M5 ;
        RECT  43.248 0 43.272 0.084 ;
    END
  END r_fp32[3]
  PIN r_fp32[40]
    DIRECTION INPUT ;
    USE SIGNAL ;
    PORT
      LAYER M5 ;
        RECT  46.8 0 46.824 0.084 ;
    END
  END r_fp32[40]
  PIN r_fp32[41]
    DIRECTION INPUT ;
    USE SIGNAL ;
    PORT
      LAYER M5 ;
        RECT  46.896 0 46.92 0.084 ;
    END
  END r_fp32[41]
  PIN r_fp32[42]
    DIRECTION INPUT ;
    USE SIGNAL ;
    PORT
      LAYER M5 ;
        RECT  46.992 0 47.016 0.084 ;
    END
  END r_fp32[42]
  PIN r_fp32[43]
    DIRECTION INPUT ;
    USE SIGNAL ;
    PORT
      LAYER M5 ;
        RECT  47.088 0 47.112 0.084 ;
    END
  END r_fp32[43]
  PIN r_fp32[44]
    DIRECTION INPUT ;
    USE SIGNAL ;
    PORT
      LAYER M5 ;
        RECT  47.184 0 47.208 0.084 ;
    END
  END r_fp32[44]
  PIN r_fp32[45]
    DIRECTION INPUT ;
    USE SIGNAL ;
    PORT
      LAYER M5 ;
        RECT  47.28 0 47.304 0.084 ;
    END
  END r_fp32[45]
  PIN r_fp32[46]
    DIRECTION INPUT ;
    USE SIGNAL ;
    PORT
      LAYER M5 ;
        RECT  47.376 0 47.4 0.084 ;
    END
  END r_fp32[46]
  PIN r_fp32[47]
    DIRECTION INPUT ;
    USE SIGNAL ;
    PORT
      LAYER M5 ;
        RECT  47.472 0 47.496 0.084 ;
    END
  END r_fp32[47]
  PIN r_fp32[48]
    DIRECTION INPUT ;
    USE SIGNAL ;
    PORT
      LAYER M5 ;
        RECT  47.568 0 47.592 0.084 ;
    END
  END r_fp32[48]
  PIN r_fp32[49]
    DIRECTION INPUT ;
    USE SIGNAL ;
    PORT
      LAYER M5 ;
        RECT  47.664 0 47.688 0.084 ;
    END
  END r_fp32[49]
  PIN r_fp32[4]
    DIRECTION INPUT ;
    USE SIGNAL ;
    PORT
      LAYER M5 ;
        RECT  43.344 0 43.368 0.084 ;
    END
  END r_fp32[4]
  PIN r_fp32[50]
    DIRECTION INPUT ;
    USE SIGNAL ;
    PORT
      LAYER M5 ;
        RECT  47.76 0 47.784 0.084 ;
    END
  END r_fp32[50]
  PIN r_fp32[51]
    DIRECTION INPUT ;
    USE SIGNAL ;
    PORT
      LAYER M5 ;
        RECT  47.856 0 47.88 0.084 ;
    END
  END r_fp32[51]
  PIN r_fp32[52]
    DIRECTION INPUT ;
    USE SIGNAL ;
    PORT
      LAYER M5 ;
        RECT  47.952 0 47.976 0.084 ;
    END
  END r_fp32[52]
  PIN r_fp32[53]
    DIRECTION INPUT ;
    USE SIGNAL ;
    PORT
      LAYER M5 ;
        RECT  48.048 0 48.072 0.084 ;
    END
  END r_fp32[53]
  PIN r_fp32[54]
    DIRECTION INPUT ;
    USE SIGNAL ;
    PORT
      LAYER M5 ;
        RECT  48.144 0 48.168 0.084 ;
    END
  END r_fp32[54]
  PIN r_fp32[55]
    DIRECTION INPUT ;
    USE SIGNAL ;
    PORT
      LAYER M5 ;
        RECT  48.24 0 48.264 0.084 ;
    END
  END r_fp32[55]
  PIN r_fp32[56]
    DIRECTION INPUT ;
    USE SIGNAL ;
    PORT
      LAYER M5 ;
        RECT  3.792 0 3.816 0.084 ;
    END
  END r_fp32[56]
  PIN r_fp32[57]
    DIRECTION INPUT ;
    USE SIGNAL ;
    PORT
      LAYER M5 ;
        RECT  3.888 0 3.912 0.084 ;
    END
  END r_fp32[57]
  PIN r_fp32[58]
    DIRECTION INPUT ;
    USE SIGNAL ;
    PORT
      LAYER M5 ;
        RECT  3.984 0 4.008 0.084 ;
    END
  END r_fp32[58]
  PIN r_fp32[59]
    DIRECTION INPUT ;
    USE SIGNAL ;
    PORT
      LAYER M5 ;
        RECT  4.08 0 4.104 0.084 ;
    END
  END r_fp32[59]
  PIN r_fp32[5]
    DIRECTION INPUT ;
    USE SIGNAL ;
    PORT
      LAYER M5 ;
        RECT  43.44 0 43.464 0.084 ;
    END
  END r_fp32[5]
  PIN r_fp32[60]
    DIRECTION INPUT ;
    USE SIGNAL ;
    PORT
      LAYER M5 ;
        RECT  4.176 0 4.2 0.084 ;
    END
  END r_fp32[60]
  PIN r_fp32[61]
    DIRECTION INPUT ;
    USE SIGNAL ;
    PORT
      LAYER M5 ;
        RECT  4.272 0 4.296 0.084 ;
    END
  END r_fp32[61]
  PIN r_fp32[62]
    DIRECTION INPUT ;
    USE SIGNAL ;
    PORT
      LAYER M5 ;
        RECT  4.368 0 4.392 0.084 ;
    END
  END r_fp32[62]
  PIN r_fp32[63]
    DIRECTION INPUT ;
    USE SIGNAL ;
    PORT
      LAYER M5 ;
        RECT  4.464 0 4.488 0.084 ;
    END
  END r_fp32[63]
  PIN r_fp32[64]
    DIRECTION INPUT ;
    USE SIGNAL ;
    PORT
      LAYER M5 ;
        RECT  4.56 0 4.584 0.084 ;
    END
  END r_fp32[64]
  PIN r_fp32[65]
    DIRECTION INPUT ;
    USE SIGNAL ;
    PORT
      LAYER M5 ;
        RECT  4.656 0 4.68 0.084 ;
    END
  END r_fp32[65]
  PIN r_fp32[66]
    DIRECTION INPUT ;
    USE SIGNAL ;
    PORT
      LAYER M5 ;
        RECT  4.752 0 4.776 0.084 ;
    END
  END r_fp32[66]
  PIN r_fp32[67]
    DIRECTION INPUT ;
    USE SIGNAL ;
    PORT
      LAYER M5 ;
        RECT  4.848 0 4.872 0.084 ;
    END
  END r_fp32[67]
  PIN r_fp32[68]
    DIRECTION INPUT ;
    USE SIGNAL ;
    PORT
      LAYER M5 ;
        RECT  4.944 0 4.968 0.084 ;
    END
  END r_fp32[68]
  PIN r_fp32[69]
    DIRECTION INPUT ;
    USE SIGNAL ;
    PORT
      LAYER M5 ;
        RECT  5.04 0 5.064 0.084 ;
    END
  END r_fp32[69]
  PIN r_fp32[6]
    DIRECTION INPUT ;
    USE SIGNAL ;
    PORT
      LAYER M5 ;
        RECT  43.536 0 43.56 0.084 ;
    END
  END r_fp32[6]
  PIN r_fp32[70]
    DIRECTION INPUT ;
    USE SIGNAL ;
    PORT
      LAYER M5 ;
        RECT  5.136 0 5.16 0.084 ;
    END
  END r_fp32[70]
  PIN r_fp32[71]
    DIRECTION INPUT ;
    USE SIGNAL ;
    PORT
      LAYER M5 ;
        RECT  5.232 0 5.256 0.084 ;
    END
  END r_fp32[71]
  PIN r_fp32[72]
    DIRECTION INPUT ;
    USE SIGNAL ;
    PORT
      LAYER M5 ;
        RECT  5.328 0 5.352 0.084 ;
    END
  END r_fp32[72]
  PIN r_fp32[73]
    DIRECTION INPUT ;
    USE SIGNAL ;
    PORT
      LAYER M5 ;
        RECT  5.424 0 5.448 0.084 ;
    END
  END r_fp32[73]
  PIN r_fp32[74]
    DIRECTION INPUT ;
    USE SIGNAL ;
    PORT
      LAYER M5 ;
        RECT  5.52 0 5.544 0.084 ;
    END
  END r_fp32[74]
  PIN r_fp32[75]
    DIRECTION INPUT ;
    USE SIGNAL ;
    PORT
      LAYER M5 ;
        RECT  5.616 0 5.64 0.084 ;
    END
  END r_fp32[75]
  PIN r_fp32[76]
    DIRECTION INPUT ;
    USE SIGNAL ;
    PORT
      LAYER M5 ;
        RECT  5.712 0 5.736 0.084 ;
    END
  END r_fp32[76]
  PIN r_fp32[77]
    DIRECTION INPUT ;
    USE SIGNAL ;
    PORT
      LAYER M5 ;
        RECT  5.808 0 5.832 0.084 ;
    END
  END r_fp32[77]
  PIN r_fp32[78]
    DIRECTION INPUT ;
    USE SIGNAL ;
    PORT
      LAYER M5 ;
        RECT  5.904 0 5.928 0.084 ;
    END
  END r_fp32[78]
  PIN r_fp32[79]
    DIRECTION INPUT ;
    USE SIGNAL ;
    PORT
      LAYER M5 ;
        RECT  6 0 6.024 0.084 ;
    END
  END r_fp32[79]
  PIN r_fp32[7]
    DIRECTION INPUT ;
    USE SIGNAL ;
    PORT
      LAYER M5 ;
        RECT  43.632 0 43.656 0.084 ;
    END
  END r_fp32[7]
  PIN r_fp32[80]
    DIRECTION INPUT ;
    USE SIGNAL ;
    PORT
      LAYER M5 ;
        RECT  6.096 0 6.12 0.084 ;
    END
  END r_fp32[80]
  PIN r_fp32[81]
    DIRECTION INPUT ;
    USE SIGNAL ;
    PORT
      LAYER M5 ;
        RECT  6.192 0 6.216 0.084 ;
    END
  END r_fp32[81]
  PIN r_fp32[82]
    DIRECTION INPUT ;
    USE SIGNAL ;
    PORT
      LAYER M5 ;
        RECT  6.288 0 6.312 0.084 ;
    END
  END r_fp32[82]
  PIN r_fp32[83]
    DIRECTION INPUT ;
    USE SIGNAL ;
    PORT
      LAYER M5 ;
        RECT  6.384 0 6.408 0.084 ;
    END
  END r_fp32[83]
  PIN r_fp32[84]
    DIRECTION INPUT ;
    USE SIGNAL ;
    PORT
      LAYER M5 ;
        RECT  6.48 0 6.504 0.084 ;
    END
  END r_fp32[84]
  PIN r_fp32[85]
    DIRECTION INPUT ;
    USE SIGNAL ;
    PORT
      LAYER M5 ;
        RECT  6.576 0 6.6 0.084 ;
    END
  END r_fp32[85]
  PIN r_fp32[86]
    DIRECTION INPUT ;
    USE SIGNAL ;
    PORT
      LAYER M5 ;
        RECT  6.672 0 6.696 0.084 ;
    END
  END r_fp32[86]
  PIN r_fp32[87]
    DIRECTION INPUT ;
    USE SIGNAL ;
    PORT
      LAYER M5 ;
        RECT  6.768 0 6.792 0.084 ;
    END
  END r_fp32[87]
  PIN r_fp32[88]
    DIRECTION INPUT ;
    USE SIGNAL ;
    PORT
      LAYER M5 ;
        RECT  26.064 0 26.088 0.084 ;
    END
  END r_fp32[88]
  PIN r_fp32[89]
    DIRECTION INPUT ;
    USE SIGNAL ;
    PORT
      LAYER M5 ;
        RECT  26.16 0 26.184 0.084 ;
    END
  END r_fp32[89]
  PIN r_fp32[8]
    DIRECTION INPUT ;
    USE SIGNAL ;
    PORT
      LAYER M5 ;
        RECT  43.728 0 43.752 0.084 ;
    END
  END r_fp32[8]
  PIN r_fp32[90]
    DIRECTION INPUT ;
    USE SIGNAL ;
    PORT
      LAYER M5 ;
        RECT  26.256 0 26.28 0.084 ;
    END
  END r_fp32[90]
  PIN r_fp32[91]
    DIRECTION INPUT ;
    USE SIGNAL ;
    PORT
      LAYER M5 ;
        RECT  26.352 0 26.376 0.084 ;
    END
  END r_fp32[91]
  PIN r_fp32[92]
    DIRECTION INPUT ;
    USE SIGNAL ;
    PORT
      LAYER M5 ;
        RECT  26.448 0 26.472 0.084 ;
    END
  END r_fp32[92]
  PIN r_fp32[93]
    DIRECTION INPUT ;
    USE SIGNAL ;
    PORT
      LAYER M5 ;
        RECT  26.544 0 26.568 0.084 ;
    END
  END r_fp32[93]
  PIN r_fp32[94]
    DIRECTION INPUT ;
    USE SIGNAL ;
    PORT
      LAYER M5 ;
        RECT  26.64 0 26.664 0.084 ;
    END
  END r_fp32[94]
  PIN r_fp32[95]
    DIRECTION INPUT ;
    USE SIGNAL ;
    PORT
      LAYER M5 ;
        RECT  26.736 0 26.76 0.084 ;
    END
  END r_fp32[95]
  PIN r_fp32[96]
    DIRECTION INPUT ;
    USE SIGNAL ;
    PORT
      LAYER M5 ;
        RECT  26.832 0 26.856 0.084 ;
    END
  END r_fp32[96]
  PIN r_fp32[97]
    DIRECTION INPUT ;
    USE SIGNAL ;
    PORT
      LAYER M5 ;
        RECT  26.928 0 26.952 0.084 ;
    END
  END r_fp32[97]
  PIN r_fp32[98]
    DIRECTION INPUT ;
    USE SIGNAL ;
    PORT
      LAYER M5 ;
        RECT  27.024 0 27.048 0.084 ;
    END
  END r_fp32[98]
  PIN r_fp32[99]
    DIRECTION INPUT ;
    USE SIGNAL ;
    PORT
      LAYER M5 ;
        RECT  27.12 0 27.144 0.084 ;
    END
  END r_fp32[99]
  PIN r_fp32[9]
    DIRECTION INPUT ;
    USE SIGNAL ;
    PORT
      LAYER M5 ;
        RECT  43.824 0 43.848 0.084 ;
    END
  END r_fp32[9]
  PIN r_pos[0]
    DIRECTION INPUT ;
    USE SIGNAL ;
    PORT
      LAYER M5 ;
        RECT  39.888 0 39.912 0.084 ;
    END
  END r_pos[0]
  PIN r_pos[10]
    DIRECTION INPUT ;
    USE SIGNAL ;
    PORT
      LAYER M5 ;
        RECT  40.848 0 40.872 0.084 ;
    END
  END r_pos[10]
  PIN r_pos[11]
    DIRECTION INPUT ;
    USE SIGNAL ;
    PORT
      LAYER M5 ;
        RECT  40.944 0 40.968 0.084 ;
    END
  END r_pos[11]
  PIN r_pos[12]
    DIRECTION INPUT ;
    USE SIGNAL ;
    PORT
      LAYER M5 ;
        RECT  41.04 0 41.064 0.084 ;
    END
  END r_pos[12]
  PIN r_pos[13]
    DIRECTION INPUT ;
    USE SIGNAL ;
    PORT
      LAYER M5 ;
        RECT  41.136 0 41.16 0.084 ;
    END
  END r_pos[13]
  PIN r_pos[14]
    DIRECTION INPUT ;
    USE SIGNAL ;
    PORT
      LAYER M5 ;
        RECT  41.232 0 41.256 0.084 ;
    END
  END r_pos[14]
  PIN r_pos[15]
    DIRECTION INPUT ;
    USE SIGNAL ;
    PORT
      LAYER M5 ;
        RECT  41.328 0 41.352 0.084 ;
    END
  END r_pos[15]
  PIN r_pos[16]
    DIRECTION INPUT ;
    USE SIGNAL ;
    PORT
      LAYER M5 ;
        RECT  41.424 0 41.448 0.084 ;
    END
  END r_pos[16]
  PIN r_pos[17]
    DIRECTION INPUT ;
    USE SIGNAL ;
    PORT
      LAYER M5 ;
        RECT  41.52 0 41.544 0.084 ;
    END
  END r_pos[17]
  PIN r_pos[18]
    DIRECTION INPUT ;
    USE SIGNAL ;
    PORT
      LAYER M5 ;
        RECT  41.616 0 41.64 0.084 ;
    END
  END r_pos[18]
  PIN r_pos[19]
    DIRECTION INPUT ;
    USE SIGNAL ;
    PORT
      LAYER M5 ;
        RECT  41.712 0 41.736 0.084 ;
    END
  END r_pos[19]
  PIN r_pos[1]
    DIRECTION INPUT ;
    USE SIGNAL ;
    PORT
      LAYER M5 ;
        RECT  39.984 0 40.008 0.084 ;
    END
  END r_pos[1]
  PIN r_pos[20]
    DIRECTION INPUT ;
    USE SIGNAL ;
    PORT
      LAYER M5 ;
        RECT  41.808 0 41.832 0.084 ;
    END
  END r_pos[20]
  PIN r_pos[21]
    DIRECTION INPUT ;
    USE SIGNAL ;
    PORT
      LAYER M5 ;
        RECT  41.904 0 41.928 0.084 ;
    END
  END r_pos[21]
  PIN r_pos[22]
    DIRECTION INPUT ;
    USE SIGNAL ;
    PORT
      LAYER M5 ;
        RECT  42 0 42.024 0.084 ;
    END
  END r_pos[22]
  PIN r_pos[23]
    DIRECTION INPUT ;
    USE SIGNAL ;
    PORT
      LAYER M5 ;
        RECT  42.096 0 42.12 0.084 ;
    END
  END r_pos[23]
  PIN r_pos[2]
    DIRECTION INPUT ;
    USE SIGNAL ;
    PORT
      LAYER M5 ;
        RECT  40.08 0 40.104 0.084 ;
    END
  END r_pos[2]
  PIN r_pos[3]
    DIRECTION INPUT ;
    USE SIGNAL ;
    PORT
      LAYER M5 ;
        RECT  40.176 0 40.2 0.084 ;
    END
  END r_pos[3]
  PIN r_pos[4]
    DIRECTION INPUT ;
    USE SIGNAL ;
    PORT
      LAYER M5 ;
        RECT  40.272 0 40.296 0.084 ;
    END
  END r_pos[4]
  PIN r_pos[5]
    DIRECTION INPUT ;
    USE SIGNAL ;
    PORT
      LAYER M5 ;
        RECT  40.368 0 40.392 0.084 ;
    END
  END r_pos[5]
  PIN r_pos[6]
    DIRECTION INPUT ;
    USE SIGNAL ;
    PORT
      LAYER M5 ;
        RECT  40.464 0 40.488 0.084 ;
    END
  END r_pos[6]
  PIN r_pos[7]
    DIRECTION INPUT ;
    USE SIGNAL ;
    PORT
      LAYER M5 ;
        RECT  40.56 0 40.584 0.084 ;
    END
  END r_pos[7]
  PIN r_pos[8]
    DIRECTION INPUT ;
    USE SIGNAL ;
    PORT
      LAYER M5 ;
        RECT  40.656 0 40.68 0.084 ;
    END
  END r_pos[8]
  PIN r_pos[9]
    DIRECTION INPUT ;
    USE SIGNAL ;
    PORT
      LAYER M5 ;
        RECT  40.752 0 40.776 0.084 ;
    END
  END r_pos[9]
  PIN r_row[0]
    DIRECTION INPUT ;
    USE SIGNAL ;
    PORT
      LAYER M5 ;
        RECT  13.008 0 13.032 0.084 ;
    END
  END r_row[0]
  PIN r_row[100]
    DIRECTION INPUT ;
    USE SIGNAL ;
    PORT
      LAYER M5 ;
        RECT  16.464 0 16.488 0.084 ;
    END
  END r_row[100]
  PIN r_row[101]
    DIRECTION INPUT ;
    USE SIGNAL ;
    PORT
      LAYER M5 ;
        RECT  16.56 0 16.584 0.084 ;
    END
  END r_row[101]
  PIN r_row[102]
    DIRECTION INPUT ;
    USE SIGNAL ;
    PORT
      LAYER M5 ;
        RECT  16.656 0 16.68 0.084 ;
    END
  END r_row[102]
  PIN r_row[103]
    DIRECTION INPUT ;
    USE SIGNAL ;
    PORT
      LAYER M5 ;
        RECT  16.752 0 16.776 0.084 ;
    END
  END r_row[103]
  PIN r_row[104]
    DIRECTION INPUT ;
    USE SIGNAL ;
    PORT
      LAYER M5 ;
        RECT  16.848 0 16.872 0.084 ;
    END
  END r_row[104]
  PIN r_row[105]
    DIRECTION INPUT ;
    USE SIGNAL ;
    PORT
      LAYER M5 ;
        RECT  16.944 0 16.968 0.084 ;
    END
  END r_row[105]
  PIN r_row[106]
    DIRECTION INPUT ;
    USE SIGNAL ;
    PORT
      LAYER M5 ;
        RECT  17.04 0 17.064 0.084 ;
    END
  END r_row[106]
  PIN r_row[107]
    DIRECTION INPUT ;
    USE SIGNAL ;
    PORT
      LAYER M5 ;
        RECT  17.136 0 17.16 0.084 ;
    END
  END r_row[107]
  PIN r_row[108]
    DIRECTION INPUT ;
    USE SIGNAL ;
    PORT
      LAYER M5 ;
        RECT  17.232 0 17.256 0.084 ;
    END
  END r_row[108]
  PIN r_row[109]
    DIRECTION INPUT ;
    USE SIGNAL ;
    PORT
      LAYER M5 ;
        RECT  17.328 0 17.352 0.084 ;
    END
  END r_row[109]
  PIN r_row[10]
    DIRECTION INPUT ;
    USE SIGNAL ;
    PORT
      LAYER M5 ;
        RECT  13.968 0 13.992 0.084 ;
    END
  END r_row[10]
  PIN r_row[110]
    DIRECTION INPUT ;
    USE SIGNAL ;
    PORT
      LAYER M5 ;
        RECT  17.424 0 17.448 0.084 ;
    END
  END r_row[110]
  PIN r_row[111]
    DIRECTION INPUT ;
    USE SIGNAL ;
    PORT
      LAYER M5 ;
        RECT  17.52 0 17.544 0.084 ;
    END
  END r_row[111]
  PIN r_row[112]
    DIRECTION INPUT ;
    USE SIGNAL ;
    PORT
      LAYER M5 ;
        RECT  17.616 0 17.64 0.084 ;
    END
  END r_row[112]
  PIN r_row[113]
    DIRECTION INPUT ;
    USE SIGNAL ;
    PORT
      LAYER M5 ;
        RECT  17.712 0 17.736 0.084 ;
    END
  END r_row[113]
  PIN r_row[114]
    DIRECTION INPUT ;
    USE SIGNAL ;
    PORT
      LAYER M5 ;
        RECT  17.808 0 17.832 0.084 ;
    END
  END r_row[114]
  PIN r_row[115]
    DIRECTION INPUT ;
    USE SIGNAL ;
    PORT
      LAYER M5 ;
        RECT  17.904 0 17.928 0.084 ;
    END
  END r_row[115]
  PIN r_row[116]
    DIRECTION INPUT ;
    USE SIGNAL ;
    PORT
      LAYER M5 ;
        RECT  18 0 18.024 0.084 ;
    END
  END r_row[116]
  PIN r_row[117]
    DIRECTION INPUT ;
    USE SIGNAL ;
    PORT
      LAYER M5 ;
        RECT  18.096 0 18.12 0.084 ;
    END
  END r_row[117]
  PIN r_row[118]
    DIRECTION INPUT ;
    USE SIGNAL ;
    PORT
      LAYER M5 ;
        RECT  18.192 0 18.216 0.084 ;
    END
  END r_row[118]
  PIN r_row[119]
    DIRECTION INPUT ;
    USE SIGNAL ;
    PORT
      LAYER M5 ;
        RECT  18.288 0 18.312 0.084 ;
    END
  END r_row[119]
  PIN r_row[11]
    DIRECTION INPUT ;
    USE SIGNAL ;
    PORT
      LAYER M5 ;
        RECT  14.064 0 14.088 0.084 ;
    END
  END r_row[11]
  PIN r_row[120]
    DIRECTION INPUT ;
    USE SIGNAL ;
    PORT
      LAYER M5 ;
        RECT  18.384 0 18.408 0.084 ;
    END
  END r_row[120]
  PIN r_row[121]
    DIRECTION INPUT ;
    USE SIGNAL ;
    PORT
      LAYER M5 ;
        RECT  18.48 0 18.504 0.084 ;
    END
  END r_row[121]
  PIN r_row[122]
    DIRECTION INPUT ;
    USE SIGNAL ;
    PORT
      LAYER M5 ;
        RECT  18.576 0 18.6 0.084 ;
    END
  END r_row[122]
  PIN r_row[123]
    DIRECTION INPUT ;
    USE SIGNAL ;
    PORT
      LAYER M5 ;
        RECT  18.672 0 18.696 0.084 ;
    END
  END r_row[123]
  PIN r_row[124]
    DIRECTION INPUT ;
    USE SIGNAL ;
    PORT
      LAYER M5 ;
        RECT  18.768 0 18.792 0.084 ;
    END
  END r_row[124]
  PIN r_row[125]
    DIRECTION INPUT ;
    USE SIGNAL ;
    PORT
      LAYER M5 ;
        RECT  18.864 0 18.888 0.084 ;
    END
  END r_row[125]
  PIN r_row[126]
    DIRECTION INPUT ;
    USE SIGNAL ;
    PORT
      LAYER M5 ;
        RECT  18.96 0 18.984 0.084 ;
    END
  END r_row[126]
  PIN r_row[127]
    DIRECTION INPUT ;
    USE SIGNAL ;
    PORT
      LAYER M5 ;
        RECT  19.056 0 19.08 0.084 ;
    END
  END r_row[127]
  PIN r_row[12]
    DIRECTION INPUT ;
    USE SIGNAL ;
    PORT
      LAYER M5 ;
        RECT  14.16 0 14.184 0.084 ;
    END
  END r_row[12]
  PIN r_row[13]
    DIRECTION INPUT ;
    USE SIGNAL ;
    PORT
      LAYER M5 ;
        RECT  14.256 0 14.28 0.084 ;
    END
  END r_row[13]
  PIN r_row[14]
    DIRECTION INPUT ;
    USE SIGNAL ;
    PORT
      LAYER M5 ;
        RECT  14.352 0 14.376 0.084 ;
    END
  END r_row[14]
  PIN r_row[15]
    DIRECTION INPUT ;
    USE SIGNAL ;
    PORT
      LAYER M5 ;
        RECT  14.448 0 14.472 0.084 ;
    END
  END r_row[15]
  PIN r_row[16]
    DIRECTION INPUT ;
    USE SIGNAL ;
    PORT
      LAYER M5 ;
        RECT  14.544 0 14.568 0.084 ;
    END
  END r_row[16]
  PIN r_row[17]
    DIRECTION INPUT ;
    USE SIGNAL ;
    PORT
      LAYER M5 ;
        RECT  14.64 0 14.664 0.084 ;
    END
  END r_row[17]
  PIN r_row[18]
    DIRECTION INPUT ;
    USE SIGNAL ;
    PORT
      LAYER M5 ;
        RECT  14.736 0 14.76 0.084 ;
    END
  END r_row[18]
  PIN r_row[19]
    DIRECTION INPUT ;
    USE SIGNAL ;
    PORT
      LAYER M5 ;
        RECT  14.832 0 14.856 0.084 ;
    END
  END r_row[19]
  PIN r_row[1]
    DIRECTION INPUT ;
    USE SIGNAL ;
    PORT
      LAYER M5 ;
        RECT  13.104 0 13.128 0.084 ;
    END
  END r_row[1]
  PIN r_row[20]
    DIRECTION INPUT ;
    USE SIGNAL ;
    PORT
      LAYER M5 ;
        RECT  14.928 0 14.952 0.084 ;
    END
  END r_row[20]
  PIN r_row[21]
    DIRECTION INPUT ;
    USE SIGNAL ;
    PORT
      LAYER M5 ;
        RECT  15.024 0 15.048 0.084 ;
    END
  END r_row[21]
  PIN r_row[22]
    DIRECTION INPUT ;
    USE SIGNAL ;
    PORT
      LAYER M5 ;
        RECT  15.12 0 15.144 0.084 ;
    END
  END r_row[22]
  PIN r_row[23]
    DIRECTION INPUT ;
    USE SIGNAL ;
    PORT
      LAYER M5 ;
        RECT  15.216 0 15.24 0.084 ;
    END
  END r_row[23]
  PIN r_row[24]
    DIRECTION INPUT ;
    USE SIGNAL ;
    PORT
      LAYER M5 ;
        RECT  15.312 0 15.336 0.084 ;
    END
  END r_row[24]
  PIN r_row[25]
    DIRECTION INPUT ;
    USE SIGNAL ;
    PORT
      LAYER M5 ;
        RECT  15.408 0 15.432 0.084 ;
    END
  END r_row[25]
  PIN r_row[26]
    DIRECTION INPUT ;
    USE SIGNAL ;
    PORT
      LAYER M5 ;
        RECT  15.504 0 15.528 0.084 ;
    END
  END r_row[26]
  PIN r_row[27]
    DIRECTION INPUT ;
    USE SIGNAL ;
    PORT
      LAYER M5 ;
        RECT  15.6 0 15.624 0.084 ;
    END
  END r_row[27]
  PIN r_row[28]
    DIRECTION INPUT ;
    USE SIGNAL ;
    PORT
      LAYER M5 ;
        RECT  15.696 0 15.72 0.084 ;
    END
  END r_row[28]
  PIN r_row[29]
    DIRECTION INPUT ;
    USE SIGNAL ;
    PORT
      LAYER M5 ;
        RECT  15.792 0 15.816 0.084 ;
    END
  END r_row[29]
  PIN r_row[2]
    DIRECTION INPUT ;
    USE SIGNAL ;
    PORT
      LAYER M5 ;
        RECT  13.2 0 13.224 0.084 ;
    END
  END r_row[2]
  PIN r_row[30]
    DIRECTION INPUT ;
    USE SIGNAL ;
    PORT
      LAYER M5 ;
        RECT  15.888 0 15.912 0.084 ;
    END
  END r_row[30]
  PIN r_row[31]
    DIRECTION INPUT ;
    USE SIGNAL ;
    PORT
      LAYER M5 ;
        RECT  15.984 0 16.008 0.084 ;
    END
  END r_row[31]
  PIN r_row[32]
    DIRECTION INPUT ;
    USE SIGNAL ;
    PORT
      LAYER M5 ;
        RECT  22.992 0 23.016 0.084 ;
    END
  END r_row[32]
  PIN r_row[33]
    DIRECTION INPUT ;
    USE SIGNAL ;
    PORT
      LAYER M5 ;
        RECT  23.088 0 23.112 0.084 ;
    END
  END r_row[33]
  PIN r_row[34]
    DIRECTION INPUT ;
    USE SIGNAL ;
    PORT
      LAYER M5 ;
        RECT  23.184 0 23.208 0.084 ;
    END
  END r_row[34]
  PIN r_row[35]
    DIRECTION INPUT ;
    USE SIGNAL ;
    PORT
      LAYER M5 ;
        RECT  23.28 0 23.304 0.084 ;
    END
  END r_row[35]
  PIN r_row[36]
    DIRECTION INPUT ;
    USE SIGNAL ;
    PORT
      LAYER M5 ;
        RECT  23.376 0 23.4 0.084 ;
    END
  END r_row[36]
  PIN r_row[37]
    DIRECTION INPUT ;
    USE SIGNAL ;
    PORT
      LAYER M5 ;
        RECT  23.472 0 23.496 0.084 ;
    END
  END r_row[37]
  PIN r_row[38]
    DIRECTION INPUT ;
    USE SIGNAL ;
    PORT
      LAYER M5 ;
        RECT  23.568 0 23.592 0.084 ;
    END
  END r_row[38]
  PIN r_row[39]
    DIRECTION INPUT ;
    USE SIGNAL ;
    PORT
      LAYER M5 ;
        RECT  23.664 0 23.688 0.084 ;
    END
  END r_row[39]
  PIN r_row[3]
    DIRECTION INPUT ;
    USE SIGNAL ;
    PORT
      LAYER M5 ;
        RECT  13.296 0 13.32 0.084 ;
    END
  END r_row[3]
  PIN r_row[40]
    DIRECTION INPUT ;
    USE SIGNAL ;
    PORT
      LAYER M5 ;
        RECT  23.76 0 23.784 0.084 ;
    END
  END r_row[40]
  PIN r_row[41]
    DIRECTION INPUT ;
    USE SIGNAL ;
    PORT
      LAYER M5 ;
        RECT  23.856 0 23.88 0.084 ;
    END
  END r_row[41]
  PIN r_row[42]
    DIRECTION INPUT ;
    USE SIGNAL ;
    PORT
      LAYER M5 ;
        RECT  23.952 0 23.976 0.084 ;
    END
  END r_row[42]
  PIN r_row[43]
    DIRECTION INPUT ;
    USE SIGNAL ;
    PORT
      LAYER M5 ;
        RECT  24.048 0 24.072 0.084 ;
    END
  END r_row[43]
  PIN r_row[44]
    DIRECTION INPUT ;
    USE SIGNAL ;
    PORT
      LAYER M5 ;
        RECT  24.144 0 24.168 0.084 ;
    END
  END r_row[44]
  PIN r_row[45]
    DIRECTION INPUT ;
    USE SIGNAL ;
    PORT
      LAYER M5 ;
        RECT  24.24 0 24.264 0.084 ;
    END
  END r_row[45]
  PIN r_row[46]
    DIRECTION INPUT ;
    USE SIGNAL ;
    PORT
      LAYER M5 ;
        RECT  24.336 0 24.36 0.084 ;
    END
  END r_row[46]
  PIN r_row[47]
    DIRECTION INPUT ;
    USE SIGNAL ;
    PORT
      LAYER M5 ;
        RECT  24.432 0 24.456 0.084 ;
    END
  END r_row[47]
  PIN r_row[48]
    DIRECTION INPUT ;
    USE SIGNAL ;
    PORT
      LAYER M5 ;
        RECT  24.528 0 24.552 0.084 ;
    END
  END r_row[48]
  PIN r_row[49]
    DIRECTION INPUT ;
    USE SIGNAL ;
    PORT
      LAYER M5 ;
        RECT  24.624 0 24.648 0.084 ;
    END
  END r_row[49]
  PIN r_row[4]
    DIRECTION INPUT ;
    USE SIGNAL ;
    PORT
      LAYER M5 ;
        RECT  13.392 0 13.416 0.084 ;
    END
  END r_row[4]
  PIN r_row[50]
    DIRECTION INPUT ;
    USE SIGNAL ;
    PORT
      LAYER M5 ;
        RECT  24.72 0 24.744 0.084 ;
    END
  END r_row[50]
  PIN r_row[51]
    DIRECTION INPUT ;
    USE SIGNAL ;
    PORT
      LAYER M5 ;
        RECT  24.816 0 24.84 0.084 ;
    END
  END r_row[51]
  PIN r_row[52]
    DIRECTION INPUT ;
    USE SIGNAL ;
    PORT
      LAYER M5 ;
        RECT  24.912 0 24.936 0.084 ;
    END
  END r_row[52]
  PIN r_row[53]
    DIRECTION INPUT ;
    USE SIGNAL ;
    PORT
      LAYER M5 ;
        RECT  25.008 0 25.032 0.084 ;
    END
  END r_row[53]
  PIN r_row[54]
    DIRECTION INPUT ;
    USE SIGNAL ;
    PORT
      LAYER M5 ;
        RECT  25.104 0 25.128 0.084 ;
    END
  END r_row[54]
  PIN r_row[55]
    DIRECTION INPUT ;
    USE SIGNAL ;
    PORT
      LAYER M5 ;
        RECT  25.2 0 25.224 0.084 ;
    END
  END r_row[55]
  PIN r_row[56]
    DIRECTION INPUT ;
    USE SIGNAL ;
    PORT
      LAYER M5 ;
        RECT  25.296 0 25.32 0.084 ;
    END
  END r_row[56]
  PIN r_row[57]
    DIRECTION INPUT ;
    USE SIGNAL ;
    PORT
      LAYER M5 ;
        RECT  25.392 0 25.416 0.084 ;
    END
  END r_row[57]
  PIN r_row[58]
    DIRECTION INPUT ;
    USE SIGNAL ;
    PORT
      LAYER M5 ;
        RECT  25.488 0 25.512 0.084 ;
    END
  END r_row[58]
  PIN r_row[59]
    DIRECTION INPUT ;
    USE SIGNAL ;
    PORT
      LAYER M5 ;
        RECT  25.584 0 25.608 0.084 ;
    END
  END r_row[59]
  PIN r_row[5]
    DIRECTION INPUT ;
    USE SIGNAL ;
    PORT
      LAYER M5 ;
        RECT  13.488 0 13.512 0.084 ;
    END
  END r_row[5]
  PIN r_row[60]
    DIRECTION INPUT ;
    USE SIGNAL ;
    PORT
      LAYER M5 ;
        RECT  25.68 0 25.704 0.084 ;
    END
  END r_row[60]
  PIN r_row[61]
    DIRECTION INPUT ;
    USE SIGNAL ;
    PORT
      LAYER M5 ;
        RECT  25.776 0 25.8 0.084 ;
    END
  END r_row[61]
  PIN r_row[62]
    DIRECTION INPUT ;
    USE SIGNAL ;
    PORT
      LAYER M5 ;
        RECT  25.872 0 25.896 0.084 ;
    END
  END r_row[62]
  PIN r_row[63]
    DIRECTION INPUT ;
    USE SIGNAL ;
    PORT
      LAYER M5 ;
        RECT  25.968 0 25.992 0.084 ;
    END
  END r_row[63]
  PIN r_row[64]
    DIRECTION INPUT ;
    USE SIGNAL ;
    PORT
      LAYER M5 ;
        RECT  9.936 0 9.96 0.084 ;
    END
  END r_row[64]
  PIN r_row[65]
    DIRECTION INPUT ;
    USE SIGNAL ;
    PORT
      LAYER M5 ;
        RECT  10.032 0 10.056 0.084 ;
    END
  END r_row[65]
  PIN r_row[66]
    DIRECTION INPUT ;
    USE SIGNAL ;
    PORT
      LAYER M5 ;
        RECT  10.128 0 10.152 0.084 ;
    END
  END r_row[66]
  PIN r_row[67]
    DIRECTION INPUT ;
    USE SIGNAL ;
    PORT
      LAYER M5 ;
        RECT  10.224 0 10.248 0.084 ;
    END
  END r_row[67]
  PIN r_row[68]
    DIRECTION INPUT ;
    USE SIGNAL ;
    PORT
      LAYER M5 ;
        RECT  10.32 0 10.344 0.084 ;
    END
  END r_row[68]
  PIN r_row[69]
    DIRECTION INPUT ;
    USE SIGNAL ;
    PORT
      LAYER M5 ;
        RECT  10.416 0 10.44 0.084 ;
    END
  END r_row[69]
  PIN r_row[6]
    DIRECTION INPUT ;
    USE SIGNAL ;
    PORT
      LAYER M5 ;
        RECT  13.584 0 13.608 0.084 ;
    END
  END r_row[6]
  PIN r_row[70]
    DIRECTION INPUT ;
    USE SIGNAL ;
    PORT
      LAYER M5 ;
        RECT  10.512 0 10.536 0.084 ;
    END
  END r_row[70]
  PIN r_row[71]
    DIRECTION INPUT ;
    USE SIGNAL ;
    PORT
      LAYER M5 ;
        RECT  10.608 0 10.632 0.084 ;
    END
  END r_row[71]
  PIN r_row[72]
    DIRECTION INPUT ;
    USE SIGNAL ;
    PORT
      LAYER M5 ;
        RECT  10.704 0 10.728 0.084 ;
    END
  END r_row[72]
  PIN r_row[73]
    DIRECTION INPUT ;
    USE SIGNAL ;
    PORT
      LAYER M5 ;
        RECT  10.8 0 10.824 0.084 ;
    END
  END r_row[73]
  PIN r_row[74]
    DIRECTION INPUT ;
    USE SIGNAL ;
    PORT
      LAYER M5 ;
        RECT  10.896 0 10.92 0.084 ;
    END
  END r_row[74]
  PIN r_row[75]
    DIRECTION INPUT ;
    USE SIGNAL ;
    PORT
      LAYER M5 ;
        RECT  10.992 0 11.016 0.084 ;
    END
  END r_row[75]
  PIN r_row[76]
    DIRECTION INPUT ;
    USE SIGNAL ;
    PORT
      LAYER M5 ;
        RECT  11.088 0 11.112 0.084 ;
    END
  END r_row[76]
  PIN r_row[77]
    DIRECTION INPUT ;
    USE SIGNAL ;
    PORT
      LAYER M5 ;
        RECT  11.184 0 11.208 0.084 ;
    END
  END r_row[77]
  PIN r_row[78]
    DIRECTION INPUT ;
    USE SIGNAL ;
    PORT
      LAYER M5 ;
        RECT  11.28 0 11.304 0.084 ;
    END
  END r_row[78]
  PIN r_row[79]
    DIRECTION INPUT ;
    USE SIGNAL ;
    PORT
      LAYER M5 ;
        RECT  11.376 0 11.4 0.084 ;
    END
  END r_row[79]
  PIN r_row[7]
    DIRECTION INPUT ;
    USE SIGNAL ;
    PORT
      LAYER M5 ;
        RECT  13.68 0 13.704 0.084 ;
    END
  END r_row[7]
  PIN r_row[80]
    DIRECTION INPUT ;
    USE SIGNAL ;
    PORT
      LAYER M5 ;
        RECT  11.472 0 11.496 0.084 ;
    END
  END r_row[80]
  PIN r_row[81]
    DIRECTION INPUT ;
    USE SIGNAL ;
    PORT
      LAYER M5 ;
        RECT  11.568 0 11.592 0.084 ;
    END
  END r_row[81]
  PIN r_row[82]
    DIRECTION INPUT ;
    USE SIGNAL ;
    PORT
      LAYER M5 ;
        RECT  11.664 0 11.688 0.084 ;
    END
  END r_row[82]
  PIN r_row[83]
    DIRECTION INPUT ;
    USE SIGNAL ;
    PORT
      LAYER M5 ;
        RECT  11.76 0 11.784 0.084 ;
    END
  END r_row[83]
  PIN r_row[84]
    DIRECTION INPUT ;
    USE SIGNAL ;
    PORT
      LAYER M5 ;
        RECT  11.856 0 11.88 0.084 ;
    END
  END r_row[84]
  PIN r_row[85]
    DIRECTION INPUT ;
    USE SIGNAL ;
    PORT
      LAYER M5 ;
        RECT  11.952 0 11.976 0.084 ;
    END
  END r_row[85]
  PIN r_row[86]
    DIRECTION INPUT ;
    USE SIGNAL ;
    PORT
      LAYER M5 ;
        RECT  12.048 0 12.072 0.084 ;
    END
  END r_row[86]
  PIN r_row[87]
    DIRECTION INPUT ;
    USE SIGNAL ;
    PORT
      LAYER M5 ;
        RECT  12.144 0 12.168 0.084 ;
    END
  END r_row[87]
  PIN r_row[88]
    DIRECTION INPUT ;
    USE SIGNAL ;
    PORT
      LAYER M5 ;
        RECT  12.24 0 12.264 0.084 ;
    END
  END r_row[88]
  PIN r_row[89]
    DIRECTION INPUT ;
    USE SIGNAL ;
    PORT
      LAYER M5 ;
        RECT  12.336 0 12.36 0.084 ;
    END
  END r_row[89]
  PIN r_row[8]
    DIRECTION INPUT ;
    USE SIGNAL ;
    PORT
      LAYER M5 ;
        RECT  13.776 0 13.8 0.084 ;
    END
  END r_row[8]
  PIN r_row[90]
    DIRECTION INPUT ;
    USE SIGNAL ;
    PORT
      LAYER M5 ;
        RECT  12.432 0 12.456 0.084 ;
    END
  END r_row[90]
  PIN r_row[91]
    DIRECTION INPUT ;
    USE SIGNAL ;
    PORT
      LAYER M5 ;
        RECT  12.528 0 12.552 0.084 ;
    END
  END r_row[91]
  PIN r_row[92]
    DIRECTION INPUT ;
    USE SIGNAL ;
    PORT
      LAYER M5 ;
        RECT  12.624 0 12.648 0.084 ;
    END
  END r_row[92]
  PIN r_row[93]
    DIRECTION INPUT ;
    USE SIGNAL ;
    PORT
      LAYER M5 ;
        RECT  12.72 0 12.744 0.084 ;
    END
  END r_row[93]
  PIN r_row[94]
    DIRECTION INPUT ;
    USE SIGNAL ;
    PORT
      LAYER M5 ;
        RECT  12.816 0 12.84 0.084 ;
    END
  END r_row[94]
  PIN r_row[95]
    DIRECTION INPUT ;
    USE SIGNAL ;
    PORT
      LAYER M5 ;
        RECT  12.912 0 12.936 0.084 ;
    END
  END r_row[95]
  PIN r_row[96]
    DIRECTION INPUT ;
    USE SIGNAL ;
    PORT
      LAYER M5 ;
        RECT  16.08 0 16.104 0.084 ;
    END
  END r_row[96]
  PIN r_row[97]
    DIRECTION INPUT ;
    USE SIGNAL ;
    PORT
      LAYER M5 ;
        RECT  16.176 0 16.2 0.084 ;
    END
  END r_row[97]
  PIN r_row[98]
    DIRECTION INPUT ;
    USE SIGNAL ;
    PORT
      LAYER M5 ;
        RECT  16.272 0 16.296 0.084 ;
    END
  END r_row[98]
  PIN r_row[99]
    DIRECTION INPUT ;
    USE SIGNAL ;
    PORT
      LAYER M5 ;
        RECT  16.368 0 16.392 0.084 ;
    END
  END r_row[99]
  PIN r_row[9]
    DIRECTION INPUT ;
    USE SIGNAL ;
    PORT
      LAYER M5 ;
        RECT  13.872 0 13.896 0.084 ;
    END
  END r_row[9]
  PIN r_v[0]
    DIRECTION INPUT ;
    USE SIGNAL ;
    PORT
      LAYER M5 ;
        RECT  19.152 0 19.176 0.084 ;
    END
  END r_v[0]
  PIN r_v[1]
    DIRECTION INPUT ;
    USE SIGNAL ;
    PORT
      LAYER M5 ;
        RECT  19.248 0 19.272 0.084 ;
    END
  END r_v[1]
  PIN r_v[2]
    DIRECTION INPUT ;
    USE SIGNAL ;
    PORT
      LAYER M5 ;
        RECT  19.344 0 19.368 0.084 ;
    END
  END r_v[2]
  PIN r_v[3]
    DIRECTION INPUT ;
    USE SIGNAL ;
    PORT
      LAYER M5 ;
        RECT  19.44 0 19.464 0.084 ;
    END
  END r_v[3]
  PIN r_v[4]
    DIRECTION INPUT ;
    USE SIGNAL ;
    PORT
      LAYER M5 ;
        RECT  19.536 0 19.56 0.084 ;
    END
  END r_v[4]
  PIN r_v[5]
    DIRECTION INPUT ;
    USE SIGNAL ;
    PORT
      LAYER M5 ;
        RECT  19.632 0 19.656 0.084 ;
    END
  END r_v[5]
  PIN r_v[6]
    DIRECTION INPUT ;
    USE SIGNAL ;
    PORT
      LAYER M5 ;
        RECT  19.728 0 19.752 0.084 ;
    END
  END r_v[6]
  PIN r_v[7]
    DIRECTION INPUT ;
    USE SIGNAL ;
    PORT
      LAYER M5 ;
        RECT  19.824 0 19.848 0.084 ;
    END
  END r_v[7]
  PIN rst_n
    DIRECTION INPUT ;
    USE SIGNAL ;
    PORT
      LAYER M5 ;
        RECT  20.592 81.996 20.616 82.08 ;
    END
  END rst_n
  PIN w_addr[0]
    DIRECTION OUTPUT ;
    USE SIGNAL ;
    PORT
      LAYER M4 ;
        RECT  81.996 17.712 82.08 17.736 ;
    END
  END w_addr[0]
  PIN w_addr[100]
    DIRECTION OUTPUT ;
    USE SIGNAL ;
    PORT
      LAYER M4 ;
        RECT  81.996 41.136 82.08 41.16 ;
    END
  END w_addr[100]
  PIN w_addr[101]
    DIRECTION OUTPUT ;
    USE SIGNAL ;
    PORT
      LAYER M4 ;
        RECT  81.996 41.232 82.08 41.256 ;
    END
  END w_addr[101]
  PIN w_addr[102]
    DIRECTION OUTPUT ;
    USE SIGNAL ;
    PORT
      LAYER M4 ;
        RECT  81.996 41.328 82.08 41.352 ;
    END
  END w_addr[102]
  PIN w_addr[103]
    DIRECTION OUTPUT ;
    USE SIGNAL ;
    PORT
      LAYER M4 ;
        RECT  81.996 41.424 82.08 41.448 ;
    END
  END w_addr[103]
  PIN w_addr[104]
    DIRECTION OUTPUT ;
    USE SIGNAL ;
    PORT
      LAYER M4 ;
        RECT  81.996 41.52 82.08 41.544 ;
    END
  END w_addr[104]
  PIN w_addr[105]
    DIRECTION OUTPUT ;
    USE SIGNAL ;
    PORT
      LAYER M4 ;
        RECT  81.996 41.616 82.08 41.64 ;
    END
  END w_addr[105]
  PIN w_addr[106]
    DIRECTION OUTPUT ;
    USE SIGNAL ;
    PORT
      LAYER M4 ;
        RECT  81.996 41.712 82.08 41.736 ;
    END
  END w_addr[106]
  PIN w_addr[107]
    DIRECTION OUTPUT ;
    USE SIGNAL ;
    PORT
      LAYER M4 ;
        RECT  81.996 41.808 82.08 41.832 ;
    END
  END w_addr[107]
  PIN w_addr[108]
    DIRECTION OUTPUT ;
    USE SIGNAL ;
    PORT
      LAYER M4 ;
        RECT  81.996 41.904 82.08 41.928 ;
    END
  END w_addr[108]
  PIN w_addr[109]
    DIRECTION OUTPUT ;
    USE SIGNAL ;
    PORT
      LAYER M4 ;
        RECT  81.996 42 82.08 42.024 ;
    END
  END w_addr[109]
  PIN w_addr[10]
    DIRECTION OUTPUT ;
    USE SIGNAL ;
    PORT
      LAYER M4 ;
        RECT  81.996 18.672 82.08 18.696 ;
    END
  END w_addr[10]
  PIN w_addr[110]
    DIRECTION OUTPUT ;
    USE SIGNAL ;
    PORT
      LAYER M4 ;
        RECT  81.996 42.096 82.08 42.12 ;
    END
  END w_addr[110]
  PIN w_addr[111]
    DIRECTION OUTPUT ;
    USE SIGNAL ;
    PORT
      LAYER M4 ;
        RECT  81.996 13.008 82.08 13.032 ;
    END
  END w_addr[111]
  PIN w_addr[112]
    DIRECTION OUTPUT ;
    USE SIGNAL ;
    PORT
      LAYER M4 ;
        RECT  81.996 13.104 82.08 13.128 ;
    END
  END w_addr[112]
  PIN w_addr[113]
    DIRECTION OUTPUT ;
    USE SIGNAL ;
    PORT
      LAYER M4 ;
        RECT  81.996 13.2 82.08 13.224 ;
    END
  END w_addr[113]
  PIN w_addr[114]
    DIRECTION OUTPUT ;
    USE SIGNAL ;
    PORT
      LAYER M4 ;
        RECT  81.996 13.296 82.08 13.32 ;
    END
  END w_addr[114]
  PIN w_addr[115]
    DIRECTION OUTPUT ;
    USE SIGNAL ;
    PORT
      LAYER M4 ;
        RECT  81.996 13.392 82.08 13.416 ;
    END
  END w_addr[115]
  PIN w_addr[116]
    DIRECTION OUTPUT ;
    USE SIGNAL ;
    PORT
      LAYER M4 ;
        RECT  81.996 13.488 82.08 13.512 ;
    END
  END w_addr[116]
  PIN w_addr[117]
    DIRECTION OUTPUT ;
    USE SIGNAL ;
    PORT
      LAYER M4 ;
        RECT  81.996 13.584 82.08 13.608 ;
    END
  END w_addr[117]
  PIN w_addr[118]
    DIRECTION OUTPUT ;
    USE SIGNAL ;
    PORT
      LAYER M4 ;
        RECT  81.996 13.68 82.08 13.704 ;
    END
  END w_addr[118]
  PIN w_addr[119]
    DIRECTION OUTPUT ;
    USE SIGNAL ;
    PORT
      LAYER M4 ;
        RECT  81.996 13.776 82.08 13.8 ;
    END
  END w_addr[119]
  PIN w_addr[11]
    DIRECTION OUTPUT ;
    USE SIGNAL ;
    PORT
      LAYER M4 ;
        RECT  81.996 18.768 82.08 18.792 ;
    END
  END w_addr[11]
  PIN w_addr[120]
    DIRECTION OUTPUT ;
    USE SIGNAL ;
    PORT
      LAYER M4 ;
        RECT  81.996 13.872 82.08 13.896 ;
    END
  END w_addr[120]
  PIN w_addr[121]
    DIRECTION OUTPUT ;
    USE SIGNAL ;
    PORT
      LAYER M4 ;
        RECT  81.996 13.968 82.08 13.992 ;
    END
  END w_addr[121]
  PIN w_addr[122]
    DIRECTION OUTPUT ;
    USE SIGNAL ;
    PORT
      LAYER M4 ;
        RECT  81.996 14.064 82.08 14.088 ;
    END
  END w_addr[122]
  PIN w_addr[123]
    DIRECTION OUTPUT ;
    USE SIGNAL ;
    PORT
      LAYER M4 ;
        RECT  81.996 14.16 82.08 14.184 ;
    END
  END w_addr[123]
  PIN w_addr[124]
    DIRECTION OUTPUT ;
    USE SIGNAL ;
    PORT
      LAYER M4 ;
        RECT  81.996 14.256 82.08 14.28 ;
    END
  END w_addr[124]
  PIN w_addr[125]
    DIRECTION OUTPUT ;
    USE SIGNAL ;
    PORT
      LAYER M4 ;
        RECT  81.996 14.352 82.08 14.376 ;
    END
  END w_addr[125]
  PIN w_addr[126]
    DIRECTION OUTPUT ;
    USE SIGNAL ;
    PORT
      LAYER M4 ;
        RECT  81.996 14.448 82.08 14.472 ;
    END
  END w_addr[126]
  PIN w_addr[127]
    DIRECTION OUTPUT ;
    USE SIGNAL ;
    PORT
      LAYER M4 ;
        RECT  81.996 14.544 82.08 14.568 ;
    END
  END w_addr[127]
  PIN w_addr[128]
    DIRECTION OUTPUT ;
    USE SIGNAL ;
    PORT
      LAYER M4 ;
        RECT  81.996 14.64 82.08 14.664 ;
    END
  END w_addr[128]
  PIN w_addr[129]
    DIRECTION OUTPUT ;
    USE SIGNAL ;
    PORT
      LAYER M4 ;
        RECT  81.996 14.736 82.08 14.76 ;
    END
  END w_addr[129]
  PIN w_addr[12]
    DIRECTION OUTPUT ;
    USE SIGNAL ;
    PORT
      LAYER M4 ;
        RECT  81.996 18.864 82.08 18.888 ;
    END
  END w_addr[12]
  PIN w_addr[130]
    DIRECTION OUTPUT ;
    USE SIGNAL ;
    PORT
      LAYER M4 ;
        RECT  81.996 14.832 82.08 14.856 ;
    END
  END w_addr[130]
  PIN w_addr[131]
    DIRECTION OUTPUT ;
    USE SIGNAL ;
    PORT
      LAYER M4 ;
        RECT  81.996 14.928 82.08 14.952 ;
    END
  END w_addr[131]
  PIN w_addr[132]
    DIRECTION OUTPUT ;
    USE SIGNAL ;
    PORT
      LAYER M4 ;
        RECT  81.996 15.024 82.08 15.048 ;
    END
  END w_addr[132]
  PIN w_addr[133]
    DIRECTION OUTPUT ;
    USE SIGNAL ;
    PORT
      LAYER M4 ;
        RECT  81.996 15.12 82.08 15.144 ;
    END
  END w_addr[133]
  PIN w_addr[134]
    DIRECTION OUTPUT ;
    USE SIGNAL ;
    PORT
      LAYER M4 ;
        RECT  81.996 15.216 82.08 15.24 ;
    END
  END w_addr[134]
  PIN w_addr[135]
    DIRECTION OUTPUT ;
    USE SIGNAL ;
    PORT
      LAYER M4 ;
        RECT  81.996 15.312 82.08 15.336 ;
    END
  END w_addr[135]
  PIN w_addr[136]
    DIRECTION OUTPUT ;
    USE SIGNAL ;
    PORT
      LAYER M4 ;
        RECT  81.996 15.408 82.08 15.432 ;
    END
  END w_addr[136]
  PIN w_addr[137]
    DIRECTION OUTPUT ;
    USE SIGNAL ;
    PORT
      LAYER M4 ;
        RECT  81.996 15.504 82.08 15.528 ;
    END
  END w_addr[137]
  PIN w_addr[138]
    DIRECTION OUTPUT ;
    USE SIGNAL ;
    PORT
      LAYER M4 ;
        RECT  81.996 15.6 82.08 15.624 ;
    END
  END w_addr[138]
  PIN w_addr[139]
    DIRECTION OUTPUT ;
    USE SIGNAL ;
    PORT
      LAYER M4 ;
        RECT  81.996 15.696 82.08 15.72 ;
    END
  END w_addr[139]
  PIN w_addr[13]
    DIRECTION OUTPUT ;
    USE SIGNAL ;
    PORT
      LAYER M4 ;
        RECT  81.996 18.96 82.08 18.984 ;
    END
  END w_addr[13]
  PIN w_addr[140]
    DIRECTION OUTPUT ;
    USE SIGNAL ;
    PORT
      LAYER M4 ;
        RECT  81.996 15.792 82.08 15.816 ;
    END
  END w_addr[140]
  PIN w_addr[141]
    DIRECTION OUTPUT ;
    USE SIGNAL ;
    PORT
      LAYER M4 ;
        RECT  81.996 15.888 82.08 15.912 ;
    END
  END w_addr[141]
  PIN w_addr[142]
    DIRECTION OUTPUT ;
    USE SIGNAL ;
    PORT
      LAYER M4 ;
        RECT  81.996 15.984 82.08 16.008 ;
    END
  END w_addr[142]
  PIN w_addr[143]
    DIRECTION OUTPUT ;
    USE SIGNAL ;
    PORT
      LAYER M4 ;
        RECT  81.996 61.392 82.08 61.416 ;
    END
  END w_addr[143]
  PIN w_addr[144]
    DIRECTION OUTPUT ;
    USE SIGNAL ;
    PORT
      LAYER M4 ;
        RECT  81.996 61.488 82.08 61.512 ;
    END
  END w_addr[144]
  PIN w_addr[145]
    DIRECTION OUTPUT ;
    USE SIGNAL ;
    PORT
      LAYER M4 ;
        RECT  81.996 61.584 82.08 61.608 ;
    END
  END w_addr[145]
  PIN w_addr[146]
    DIRECTION OUTPUT ;
    USE SIGNAL ;
    PORT
      LAYER M4 ;
        RECT  81.996 61.68 82.08 61.704 ;
    END
  END w_addr[146]
  PIN w_addr[147]
    DIRECTION OUTPUT ;
    USE SIGNAL ;
    PORT
      LAYER M4 ;
        RECT  81.996 61.776 82.08 61.8 ;
    END
  END w_addr[147]
  PIN w_addr[148]
    DIRECTION OUTPUT ;
    USE SIGNAL ;
    PORT
      LAYER M4 ;
        RECT  81.996 61.872 82.08 61.896 ;
    END
  END w_addr[148]
  PIN w_addr[149]
    DIRECTION OUTPUT ;
    USE SIGNAL ;
    PORT
      LAYER M4 ;
        RECT  81.996 61.968 82.08 61.992 ;
    END
  END w_addr[149]
  PIN w_addr[14]
    DIRECTION OUTPUT ;
    USE SIGNAL ;
    PORT
      LAYER M4 ;
        RECT  81.996 19.056 82.08 19.08 ;
    END
  END w_addr[14]
  PIN w_addr[150]
    DIRECTION OUTPUT ;
    USE SIGNAL ;
    PORT
      LAYER M4 ;
        RECT  81.996 62.064 82.08 62.088 ;
    END
  END w_addr[150]
  PIN w_addr[151]
    DIRECTION OUTPUT ;
    USE SIGNAL ;
    PORT
      LAYER M4 ;
        RECT  81.996 62.16 82.08 62.184 ;
    END
  END w_addr[151]
  PIN w_addr[15]
    DIRECTION OUTPUT ;
    USE SIGNAL ;
    PORT
      LAYER M4 ;
        RECT  81.996 6.864 82.08 6.888 ;
    END
  END w_addr[15]
  PIN w_addr[16]
    DIRECTION OUTPUT ;
    USE SIGNAL ;
    PORT
      LAYER M4 ;
        RECT  81.996 6.96 82.08 6.984 ;
    END
  END w_addr[16]
  PIN w_addr[17]
    DIRECTION OUTPUT ;
    USE SIGNAL ;
    PORT
      LAYER M4 ;
        RECT  81.996 7.056 82.08 7.08 ;
    END
  END w_addr[17]
  PIN w_addr[18]
    DIRECTION OUTPUT ;
    USE SIGNAL ;
    PORT
      LAYER M4 ;
        RECT  81.996 7.152 82.08 7.176 ;
    END
  END w_addr[18]
  PIN w_addr[19]
    DIRECTION OUTPUT ;
    USE SIGNAL ;
    PORT
      LAYER M4 ;
        RECT  81.996 7.248 82.08 7.272 ;
    END
  END w_addr[19]
  PIN w_addr[1]
    DIRECTION OUTPUT ;
    USE SIGNAL ;
    PORT
      LAYER M4 ;
        RECT  81.996 17.808 82.08 17.832 ;
    END
  END w_addr[1]
  PIN w_addr[20]
    DIRECTION OUTPUT ;
    USE SIGNAL ;
    PORT
      LAYER M4 ;
        RECT  81.996 7.344 82.08 7.368 ;
    END
  END w_addr[20]
  PIN w_addr[21]
    DIRECTION OUTPUT ;
    USE SIGNAL ;
    PORT
      LAYER M4 ;
        RECT  81.996 7.44 82.08 7.464 ;
    END
  END w_addr[21]
  PIN w_addr[22]
    DIRECTION OUTPUT ;
    USE SIGNAL ;
    PORT
      LAYER M4 ;
        RECT  81.996 7.536 82.08 7.56 ;
    END
  END w_addr[22]
  PIN w_addr[23]
    DIRECTION OUTPUT ;
    USE SIGNAL ;
    PORT
      LAYER M4 ;
        RECT  81.996 7.632 82.08 7.656 ;
    END
  END w_addr[23]
  PIN w_addr[24]
    DIRECTION OUTPUT ;
    USE SIGNAL ;
    PORT
      LAYER M4 ;
        RECT  81.996 7.728 82.08 7.752 ;
    END
  END w_addr[24]
  PIN w_addr[25]
    DIRECTION OUTPUT ;
    USE SIGNAL ;
    PORT
      LAYER M4 ;
        RECT  81.996 7.824 82.08 7.848 ;
    END
  END w_addr[25]
  PIN w_addr[26]
    DIRECTION OUTPUT ;
    USE SIGNAL ;
    PORT
      LAYER M4 ;
        RECT  81.996 7.92 82.08 7.944 ;
    END
  END w_addr[26]
  PIN w_addr[27]
    DIRECTION OUTPUT ;
    USE SIGNAL ;
    PORT
      LAYER M4 ;
        RECT  81.996 8.016 82.08 8.04 ;
    END
  END w_addr[27]
  PIN w_addr[28]
    DIRECTION OUTPUT ;
    USE SIGNAL ;
    PORT
      LAYER M4 ;
        RECT  81.996 8.112 82.08 8.136 ;
    END
  END w_addr[28]
  PIN w_addr[29]
    DIRECTION OUTPUT ;
    USE SIGNAL ;
    PORT
      LAYER M4 ;
        RECT  81.996 8.208 82.08 8.232 ;
    END
  END w_addr[29]
  PIN w_addr[2]
    DIRECTION OUTPUT ;
    USE SIGNAL ;
    PORT
      LAYER M4 ;
        RECT  81.996 17.904 82.08 17.928 ;
    END
  END w_addr[2]
  PIN w_addr[30]
    DIRECTION OUTPUT ;
    USE SIGNAL ;
    PORT
      LAYER M4 ;
        RECT  81.996 8.304 82.08 8.328 ;
    END
  END w_addr[30]
  PIN w_addr[31]
    DIRECTION OUTPUT ;
    USE SIGNAL ;
    PORT
      LAYER M4 ;
        RECT  81.996 8.4 82.08 8.424 ;
    END
  END w_addr[31]
  PIN w_addr[32]
    DIRECTION OUTPUT ;
    USE SIGNAL ;
    PORT
      LAYER M4 ;
        RECT  81.996 8.496 82.08 8.52 ;
    END
  END w_addr[32]
  PIN w_addr[33]
    DIRECTION OUTPUT ;
    USE SIGNAL ;
    PORT
      LAYER M4 ;
        RECT  81.996 8.592 82.08 8.616 ;
    END
  END w_addr[33]
  PIN w_addr[34]
    DIRECTION OUTPUT ;
    USE SIGNAL ;
    PORT
      LAYER M4 ;
        RECT  81.996 8.688 82.08 8.712 ;
    END
  END w_addr[34]
  PIN w_addr[35]
    DIRECTION OUTPUT ;
    USE SIGNAL ;
    PORT
      LAYER M4 ;
        RECT  81.996 8.784 82.08 8.808 ;
    END
  END w_addr[35]
  PIN w_addr[36]
    DIRECTION OUTPUT ;
    USE SIGNAL ;
    PORT
      LAYER M4 ;
        RECT  81.996 8.88 82.08 8.904 ;
    END
  END w_addr[36]
  PIN w_addr[37]
    DIRECTION OUTPUT ;
    USE SIGNAL ;
    PORT
      LAYER M4 ;
        RECT  81.996 8.976 82.08 9 ;
    END
  END w_addr[37]
  PIN w_addr[38]
    DIRECTION OUTPUT ;
    USE SIGNAL ;
    PORT
      LAYER M4 ;
        RECT  81.996 9.072 82.08 9.096 ;
    END
  END w_addr[38]
  PIN w_addr[39]
    DIRECTION OUTPUT ;
    USE SIGNAL ;
    PORT
      LAYER M4 ;
        RECT  81.996 9.168 82.08 9.192 ;
    END
  END w_addr[39]
  PIN w_addr[3]
    DIRECTION OUTPUT ;
    USE SIGNAL ;
    PORT
      LAYER M4 ;
        RECT  81.996 18 82.08 18.024 ;
    END
  END w_addr[3]
  PIN w_addr[40]
    DIRECTION OUTPUT ;
    USE SIGNAL ;
    PORT
      LAYER M4 ;
        RECT  81.996 9.264 82.08 9.288 ;
    END
  END w_addr[40]
  PIN w_addr[41]
    DIRECTION OUTPUT ;
    USE SIGNAL ;
    PORT
      LAYER M4 ;
        RECT  81.996 9.36 82.08 9.384 ;
    END
  END w_addr[41]
  PIN w_addr[42]
    DIRECTION OUTPUT ;
    USE SIGNAL ;
    PORT
      LAYER M4 ;
        RECT  81.996 9.456 82.08 9.48 ;
    END
  END w_addr[42]
  PIN w_addr[43]
    DIRECTION OUTPUT ;
    USE SIGNAL ;
    PORT
      LAYER M4 ;
        RECT  81.996 9.552 82.08 9.576 ;
    END
  END w_addr[43]
  PIN w_addr[44]
    DIRECTION OUTPUT ;
    USE SIGNAL ;
    PORT
      LAYER M4 ;
        RECT  81.996 9.648 82.08 9.672 ;
    END
  END w_addr[44]
  PIN w_addr[45]
    DIRECTION OUTPUT ;
    USE SIGNAL ;
    PORT
      LAYER M4 ;
        RECT  81.996 9.744 82.08 9.768 ;
    END
  END w_addr[45]
  PIN w_addr[46]
    DIRECTION OUTPUT ;
    USE SIGNAL ;
    PORT
      LAYER M4 ;
        RECT  81.996 9.84 82.08 9.864 ;
    END
  END w_addr[46]
  PIN w_addr[47]
    DIRECTION OUTPUT ;
    USE SIGNAL ;
    PORT
      LAYER M4 ;
        RECT  81.996 26.064 82.08 26.088 ;
    END
  END w_addr[47]
  PIN w_addr[48]
    DIRECTION OUTPUT ;
    USE SIGNAL ;
    PORT
      LAYER M4 ;
        RECT  81.996 26.16 82.08 26.184 ;
    END
  END w_addr[48]
  PIN w_addr[49]
    DIRECTION OUTPUT ;
    USE SIGNAL ;
    PORT
      LAYER M4 ;
        RECT  81.996 26.256 82.08 26.28 ;
    END
  END w_addr[49]
  PIN w_addr[4]
    DIRECTION OUTPUT ;
    USE SIGNAL ;
    PORT
      LAYER M4 ;
        RECT  81.996 18.096 82.08 18.12 ;
    END
  END w_addr[4]
  PIN w_addr[50]
    DIRECTION OUTPUT ;
    USE SIGNAL ;
    PORT
      LAYER M4 ;
        RECT  81.996 26.352 82.08 26.376 ;
    END
  END w_addr[50]
  PIN w_addr[51]
    DIRECTION OUTPUT ;
    USE SIGNAL ;
    PORT
      LAYER M4 ;
        RECT  81.996 26.448 82.08 26.472 ;
    END
  END w_addr[51]
  PIN w_addr[52]
    DIRECTION OUTPUT ;
    USE SIGNAL ;
    PORT
      LAYER M4 ;
        RECT  81.996 26.544 82.08 26.568 ;
    END
  END w_addr[52]
  PIN w_addr[53]
    DIRECTION OUTPUT ;
    USE SIGNAL ;
    PORT
      LAYER M4 ;
        RECT  81.996 26.64 82.08 26.664 ;
    END
  END w_addr[53]
  PIN w_addr[54]
    DIRECTION OUTPUT ;
    USE SIGNAL ;
    PORT
      LAYER M4 ;
        RECT  81.996 26.736 82.08 26.76 ;
    END
  END w_addr[54]
  PIN w_addr[55]
    DIRECTION OUTPUT ;
    USE SIGNAL ;
    PORT
      LAYER M4 ;
        RECT  81.996 26.832 82.08 26.856 ;
    END
  END w_addr[55]
  PIN w_addr[56]
    DIRECTION OUTPUT ;
    USE SIGNAL ;
    PORT
      LAYER M4 ;
        RECT  81.996 26.928 82.08 26.952 ;
    END
  END w_addr[56]
  PIN w_addr[57]
    DIRECTION OUTPUT ;
    USE SIGNAL ;
    PORT
      LAYER M4 ;
        RECT  81.996 27.024 82.08 27.048 ;
    END
  END w_addr[57]
  PIN w_addr[58]
    DIRECTION OUTPUT ;
    USE SIGNAL ;
    PORT
      LAYER M4 ;
        RECT  81.996 27.12 82.08 27.144 ;
    END
  END w_addr[58]
  PIN w_addr[59]
    DIRECTION OUTPUT ;
    USE SIGNAL ;
    PORT
      LAYER M4 ;
        RECT  81.996 27.216 82.08 27.24 ;
    END
  END w_addr[59]
  PIN w_addr[5]
    DIRECTION OUTPUT ;
    USE SIGNAL ;
    PORT
      LAYER M4 ;
        RECT  81.996 18.192 82.08 18.216 ;
    END
  END w_addr[5]
  PIN w_addr[60]
    DIRECTION OUTPUT ;
    USE SIGNAL ;
    PORT
      LAYER M4 ;
        RECT  81.996 27.312 82.08 27.336 ;
    END
  END w_addr[60]
  PIN w_addr[61]
    DIRECTION OUTPUT ;
    USE SIGNAL ;
    PORT
      LAYER M4 ;
        RECT  81.996 27.408 82.08 27.432 ;
    END
  END w_addr[61]
  PIN w_addr[62]
    DIRECTION OUTPUT ;
    USE SIGNAL ;
    PORT
      LAYER M4 ;
        RECT  81.996 27.504 82.08 27.528 ;
    END
  END w_addr[62]
  PIN w_addr[63]
    DIRECTION OUTPUT ;
    USE SIGNAL ;
    PORT
      LAYER M4 ;
        RECT  81.996 27.6 82.08 27.624 ;
    END
  END w_addr[63]
  PIN w_addr[64]
    DIRECTION OUTPUT ;
    USE SIGNAL ;
    PORT
      LAYER M4 ;
        RECT  81.996 27.696 82.08 27.72 ;
    END
  END w_addr[64]
  PIN w_addr[65]
    DIRECTION OUTPUT ;
    USE SIGNAL ;
    PORT
      LAYER M4 ;
        RECT  81.996 27.792 82.08 27.816 ;
    END
  END w_addr[65]
  PIN w_addr[66]
    DIRECTION OUTPUT ;
    USE SIGNAL ;
    PORT
      LAYER M4 ;
        RECT  81.996 27.888 82.08 27.912 ;
    END
  END w_addr[66]
  PIN w_addr[67]
    DIRECTION OUTPUT ;
    USE SIGNAL ;
    PORT
      LAYER M4 ;
        RECT  81.996 27.984 82.08 28.008 ;
    END
  END w_addr[67]
  PIN w_addr[68]
    DIRECTION OUTPUT ;
    USE SIGNAL ;
    PORT
      LAYER M4 ;
        RECT  81.996 28.08 82.08 28.104 ;
    END
  END w_addr[68]
  PIN w_addr[69]
    DIRECTION OUTPUT ;
    USE SIGNAL ;
    PORT
      LAYER M4 ;
        RECT  81.996 28.176 82.08 28.2 ;
    END
  END w_addr[69]
  PIN w_addr[6]
    DIRECTION OUTPUT ;
    USE SIGNAL ;
    PORT
      LAYER M4 ;
        RECT  81.996 18.288 82.08 18.312 ;
    END
  END w_addr[6]
  PIN w_addr[70]
    DIRECTION OUTPUT ;
    USE SIGNAL ;
    PORT
      LAYER M4 ;
        RECT  81.996 28.272 82.08 28.296 ;
    END
  END w_addr[70]
  PIN w_addr[71]
    DIRECTION OUTPUT ;
    USE SIGNAL ;
    PORT
      LAYER M4 ;
        RECT  81.996 28.368 82.08 28.392 ;
    END
  END w_addr[71]
  PIN w_addr[72]
    DIRECTION OUTPUT ;
    USE SIGNAL ;
    PORT
      LAYER M4 ;
        RECT  81.996 28.464 82.08 28.488 ;
    END
  END w_addr[72]
  PIN w_addr[73]
    DIRECTION OUTPUT ;
    USE SIGNAL ;
    PORT
      LAYER M4 ;
        RECT  81.996 28.56 82.08 28.584 ;
    END
  END w_addr[73]
  PIN w_addr[74]
    DIRECTION OUTPUT ;
    USE SIGNAL ;
    PORT
      LAYER M4 ;
        RECT  81.996 28.656 82.08 28.68 ;
    END
  END w_addr[74]
  PIN w_addr[75]
    DIRECTION OUTPUT ;
    USE SIGNAL ;
    PORT
      LAYER M4 ;
        RECT  81.996 28.752 82.08 28.776 ;
    END
  END w_addr[75]
  PIN w_addr[76]
    DIRECTION OUTPUT ;
    USE SIGNAL ;
    PORT
      LAYER M4 ;
        RECT  81.996 28.848 82.08 28.872 ;
    END
  END w_addr[76]
  PIN w_addr[77]
    DIRECTION OUTPUT ;
    USE SIGNAL ;
    PORT
      LAYER M4 ;
        RECT  81.996 28.944 82.08 28.968 ;
    END
  END w_addr[77]
  PIN w_addr[78]
    DIRECTION OUTPUT ;
    USE SIGNAL ;
    PORT
      LAYER M4 ;
        RECT  81.996 29.04 82.08 29.064 ;
    END
  END w_addr[78]
  PIN w_addr[79]
    DIRECTION OUTPUT ;
    USE SIGNAL ;
    PORT
      LAYER M4 ;
        RECT  81.996 39.12 82.08 39.144 ;
    END
  END w_addr[79]
  PIN w_addr[7]
    DIRECTION OUTPUT ;
    USE SIGNAL ;
    PORT
      LAYER M4 ;
        RECT  81.996 18.384 82.08 18.408 ;
    END
  END w_addr[7]
  PIN w_addr[80]
    DIRECTION OUTPUT ;
    USE SIGNAL ;
    PORT
      LAYER M4 ;
        RECT  81.996 39.216 82.08 39.24 ;
    END
  END w_addr[80]
  PIN w_addr[81]
    DIRECTION OUTPUT ;
    USE SIGNAL ;
    PORT
      LAYER M4 ;
        RECT  81.996 39.312 82.08 39.336 ;
    END
  END w_addr[81]
  PIN w_addr[82]
    DIRECTION OUTPUT ;
    USE SIGNAL ;
    PORT
      LAYER M4 ;
        RECT  81.996 39.408 82.08 39.432 ;
    END
  END w_addr[82]
  PIN w_addr[83]
    DIRECTION OUTPUT ;
    USE SIGNAL ;
    PORT
      LAYER M4 ;
        RECT  81.996 39.504 82.08 39.528 ;
    END
  END w_addr[83]
  PIN w_addr[84]
    DIRECTION OUTPUT ;
    USE SIGNAL ;
    PORT
      LAYER M4 ;
        RECT  81.996 39.6 82.08 39.624 ;
    END
  END w_addr[84]
  PIN w_addr[85]
    DIRECTION OUTPUT ;
    USE SIGNAL ;
    PORT
      LAYER M4 ;
        RECT  81.996 39.696 82.08 39.72 ;
    END
  END w_addr[85]
  PIN w_addr[86]
    DIRECTION OUTPUT ;
    USE SIGNAL ;
    PORT
      LAYER M4 ;
        RECT  81.996 39.792 82.08 39.816 ;
    END
  END w_addr[86]
  PIN w_addr[87]
    DIRECTION OUTPUT ;
    USE SIGNAL ;
    PORT
      LAYER M4 ;
        RECT  81.996 39.888 82.08 39.912 ;
    END
  END w_addr[87]
  PIN w_addr[88]
    DIRECTION OUTPUT ;
    USE SIGNAL ;
    PORT
      LAYER M4 ;
        RECT  81.996 39.984 82.08 40.008 ;
    END
  END w_addr[88]
  PIN w_addr[89]
    DIRECTION OUTPUT ;
    USE SIGNAL ;
    PORT
      LAYER M4 ;
        RECT  81.996 40.08 82.08 40.104 ;
    END
  END w_addr[89]
  PIN w_addr[8]
    DIRECTION OUTPUT ;
    USE SIGNAL ;
    PORT
      LAYER M4 ;
        RECT  81.996 18.48 82.08 18.504 ;
    END
  END w_addr[8]
  PIN w_addr[90]
    DIRECTION OUTPUT ;
    USE SIGNAL ;
    PORT
      LAYER M4 ;
        RECT  81.996 40.176 82.08 40.2 ;
    END
  END w_addr[90]
  PIN w_addr[91]
    DIRECTION OUTPUT ;
    USE SIGNAL ;
    PORT
      LAYER M4 ;
        RECT  81.996 40.272 82.08 40.296 ;
    END
  END w_addr[91]
  PIN w_addr[92]
    DIRECTION OUTPUT ;
    USE SIGNAL ;
    PORT
      LAYER M4 ;
        RECT  81.996 40.368 82.08 40.392 ;
    END
  END w_addr[92]
  PIN w_addr[93]
    DIRECTION OUTPUT ;
    USE SIGNAL ;
    PORT
      LAYER M4 ;
        RECT  81.996 40.464 82.08 40.488 ;
    END
  END w_addr[93]
  PIN w_addr[94]
    DIRECTION OUTPUT ;
    USE SIGNAL ;
    PORT
      LAYER M4 ;
        RECT  81.996 40.56 82.08 40.584 ;
    END
  END w_addr[94]
  PIN w_addr[95]
    DIRECTION OUTPUT ;
    USE SIGNAL ;
    PORT
      LAYER M4 ;
        RECT  81.996 40.656 82.08 40.68 ;
    END
  END w_addr[95]
  PIN w_addr[96]
    DIRECTION OUTPUT ;
    USE SIGNAL ;
    PORT
      LAYER M4 ;
        RECT  81.996 40.752 82.08 40.776 ;
    END
  END w_addr[96]
  PIN w_addr[97]
    DIRECTION OUTPUT ;
    USE SIGNAL ;
    PORT
      LAYER M4 ;
        RECT  81.996 40.848 82.08 40.872 ;
    END
  END w_addr[97]
  PIN w_addr[98]
    DIRECTION OUTPUT ;
    USE SIGNAL ;
    PORT
      LAYER M4 ;
        RECT  81.996 40.944 82.08 40.968 ;
    END
  END w_addr[98]
  PIN w_addr[99]
    DIRECTION OUTPUT ;
    USE SIGNAL ;
    PORT
      LAYER M4 ;
        RECT  81.996 41.04 82.08 41.064 ;
    END
  END w_addr[99]
  PIN w_addr[9]
    DIRECTION OUTPUT ;
    USE SIGNAL ;
    PORT
      LAYER M4 ;
        RECT  81.996 18.576 82.08 18.6 ;
    END
  END w_addr[9]
  PIN w_data[0]
    DIRECTION OUTPUT ;
    USE SIGNAL ;
    PORT
      LAYER M4 ;
        RECT  81.996 62.256 82.08 62.28 ;
    END
  END w_data[0]
  PIN w_data[100]
    DIRECTION OUTPUT ;
    USE SIGNAL ;
    PORT
      LAYER M4 ;
        RECT  81.996 74.928 82.08 74.952 ;
    END
  END w_data[100]
  PIN w_data[101]
    DIRECTION OUTPUT ;
    USE SIGNAL ;
    PORT
      LAYER M4 ;
        RECT  81.996 75.024 82.08 75.048 ;
    END
  END w_data[101]
  PIN w_data[102]
    DIRECTION OUTPUT ;
    USE SIGNAL ;
    PORT
      LAYER M4 ;
        RECT  81.996 75.12 82.08 75.144 ;
    END
  END w_data[102]
  PIN w_data[103]
    DIRECTION OUTPUT ;
    USE SIGNAL ;
    PORT
      LAYER M4 ;
        RECT  81.996 75.216 82.08 75.24 ;
    END
  END w_data[103]
  PIN w_data[104]
    DIRECTION OUTPUT ;
    USE SIGNAL ;
    PORT
      LAYER M4 ;
        RECT  81.996 75.312 82.08 75.336 ;
    END
  END w_data[104]
  PIN w_data[105]
    DIRECTION OUTPUT ;
    USE SIGNAL ;
    PORT
      LAYER M4 ;
        RECT  81.996 75.408 82.08 75.432 ;
    END
  END w_data[105]
  PIN w_data[106]
    DIRECTION OUTPUT ;
    USE SIGNAL ;
    PORT
      LAYER M4 ;
        RECT  81.996 75.504 82.08 75.528 ;
    END
  END w_data[106]
  PIN w_data[107]
    DIRECTION OUTPUT ;
    USE SIGNAL ;
    PORT
      LAYER M4 ;
        RECT  81.996 75.6 82.08 75.624 ;
    END
  END w_data[107]
  PIN w_data[108]
    DIRECTION OUTPUT ;
    USE SIGNAL ;
    PORT
      LAYER M4 ;
        RECT  81.996 75.696 82.08 75.72 ;
    END
  END w_data[108]
  PIN w_data[109]
    DIRECTION OUTPUT ;
    USE SIGNAL ;
    PORT
      LAYER M4 ;
        RECT  81.996 75.792 82.08 75.816 ;
    END
  END w_data[109]
  PIN w_data[10]
    DIRECTION OUTPUT ;
    USE SIGNAL ;
    PORT
      LAYER M4 ;
        RECT  81.996 63.216 82.08 63.24 ;
    END
  END w_data[10]
  PIN w_data[110]
    DIRECTION OUTPUT ;
    USE SIGNAL ;
    PORT
      LAYER M4 ;
        RECT  81.996 75.888 82.08 75.912 ;
    END
  END w_data[110]
  PIN w_data[111]
    DIRECTION OUTPUT ;
    USE SIGNAL ;
    PORT
      LAYER M4 ;
        RECT  81.996 75.984 82.08 76.008 ;
    END
  END w_data[111]
  PIN w_data[112]
    DIRECTION OUTPUT ;
    USE SIGNAL ;
    PORT
      LAYER M4 ;
        RECT  81.996 76.08 82.08 76.104 ;
    END
  END w_data[112]
  PIN w_data[113]
    DIRECTION OUTPUT ;
    USE SIGNAL ;
    PORT
      LAYER M4 ;
        RECT  81.996 76.176 82.08 76.2 ;
    END
  END w_data[113]
  PIN w_data[114]
    DIRECTION OUTPUT ;
    USE SIGNAL ;
    PORT
      LAYER M4 ;
        RECT  81.996 76.272 82.08 76.296 ;
    END
  END w_data[114]
  PIN w_data[115]
    DIRECTION OUTPUT ;
    USE SIGNAL ;
    PORT
      LAYER M4 ;
        RECT  81.996 76.368 82.08 76.392 ;
    END
  END w_data[115]
  PIN w_data[116]
    DIRECTION OUTPUT ;
    USE SIGNAL ;
    PORT
      LAYER M4 ;
        RECT  81.996 76.464 82.08 76.488 ;
    END
  END w_data[116]
  PIN w_data[117]
    DIRECTION OUTPUT ;
    USE SIGNAL ;
    PORT
      LAYER M4 ;
        RECT  81.996 76.56 82.08 76.584 ;
    END
  END w_data[117]
  PIN w_data[118]
    DIRECTION OUTPUT ;
    USE SIGNAL ;
    PORT
      LAYER M4 ;
        RECT  81.996 76.656 82.08 76.68 ;
    END
  END w_data[118]
  PIN w_data[119]
    DIRECTION OUTPUT ;
    USE SIGNAL ;
    PORT
      LAYER M4 ;
        RECT  81.996 70.608 82.08 70.632 ;
    END
  END w_data[119]
  PIN w_data[11]
    DIRECTION OUTPUT ;
    USE SIGNAL ;
    PORT
      LAYER M4 ;
        RECT  81.996 63.312 82.08 63.336 ;
    END
  END w_data[11]
  PIN w_data[120]
    DIRECTION OUTPUT ;
    USE SIGNAL ;
    PORT
      LAYER M4 ;
        RECT  81.996 70.704 82.08 70.728 ;
    END
  END w_data[120]
  PIN w_data[121]
    DIRECTION OUTPUT ;
    USE SIGNAL ;
    PORT
      LAYER M4 ;
        RECT  81.996 70.8 82.08 70.824 ;
    END
  END w_data[121]
  PIN w_data[122]
    DIRECTION OUTPUT ;
    USE SIGNAL ;
    PORT
      LAYER M4 ;
        RECT  81.996 70.896 82.08 70.92 ;
    END
  END w_data[122]
  PIN w_data[123]
    DIRECTION OUTPUT ;
    USE SIGNAL ;
    PORT
      LAYER M4 ;
        RECT  81.996 70.992 82.08 71.016 ;
    END
  END w_data[123]
  PIN w_data[124]
    DIRECTION OUTPUT ;
    USE SIGNAL ;
    PORT
      LAYER M4 ;
        RECT  81.996 71.088 82.08 71.112 ;
    END
  END w_data[124]
  PIN w_data[125]
    DIRECTION OUTPUT ;
    USE SIGNAL ;
    PORT
      LAYER M4 ;
        RECT  81.996 71.184 82.08 71.208 ;
    END
  END w_data[125]
  PIN w_data[126]
    DIRECTION OUTPUT ;
    USE SIGNAL ;
    PORT
      LAYER M4 ;
        RECT  81.996 71.28 82.08 71.304 ;
    END
  END w_data[126]
  PIN w_data[127]
    DIRECTION OUTPUT ;
    USE SIGNAL ;
    PORT
      LAYER M4 ;
        RECT  81.996 71.376 82.08 71.4 ;
    END
  END w_data[127]
  PIN w_data[128]
    DIRECTION OUTPUT ;
    USE SIGNAL ;
    PORT
      LAYER M4 ;
        RECT  81.996 71.472 82.08 71.496 ;
    END
  END w_data[128]
  PIN w_data[129]
    DIRECTION OUTPUT ;
    USE SIGNAL ;
    PORT
      LAYER M4 ;
        RECT  81.996 71.568 82.08 71.592 ;
    END
  END w_data[129]
  PIN w_data[12]
    DIRECTION OUTPUT ;
    USE SIGNAL ;
    PORT
      LAYER M4 ;
        RECT  81.996 63.408 82.08 63.432 ;
    END
  END w_data[12]
  PIN w_data[130]
    DIRECTION OUTPUT ;
    USE SIGNAL ;
    PORT
      LAYER M4 ;
        RECT  81.996 71.664 82.08 71.688 ;
    END
  END w_data[130]
  PIN w_data[131]
    DIRECTION OUTPUT ;
    USE SIGNAL ;
    PORT
      LAYER M4 ;
        RECT  81.996 71.76 82.08 71.784 ;
    END
  END w_data[131]
  PIN w_data[132]
    DIRECTION OUTPUT ;
    USE SIGNAL ;
    PORT
      LAYER M4 ;
        RECT  81.996 71.856 82.08 71.88 ;
    END
  END w_data[132]
  PIN w_data[133]
    DIRECTION OUTPUT ;
    USE SIGNAL ;
    PORT
      LAYER M4 ;
        RECT  81.996 71.952 82.08 71.976 ;
    END
  END w_data[133]
  PIN w_data[134]
    DIRECTION OUTPUT ;
    USE SIGNAL ;
    PORT
      LAYER M4 ;
        RECT  81.996 72.048 82.08 72.072 ;
    END
  END w_data[134]
  PIN w_data[135]
    DIRECTION OUTPUT ;
    USE SIGNAL ;
    PORT
      LAYER M4 ;
        RECT  81.996 72.144 82.08 72.168 ;
    END
  END w_data[135]
  PIN w_data[136]
    DIRECTION OUTPUT ;
    USE SIGNAL ;
    PORT
      LAYER M4 ;
        RECT  81.996 72.24 82.08 72.264 ;
    END
  END w_data[136]
  PIN w_data[137]
    DIRECTION OUTPUT ;
    USE SIGNAL ;
    PORT
      LAYER M4 ;
        RECT  81.996 72.336 82.08 72.36 ;
    END
  END w_data[137]
  PIN w_data[138]
    DIRECTION OUTPUT ;
    USE SIGNAL ;
    PORT
      LAYER M4 ;
        RECT  81.996 72.432 82.08 72.456 ;
    END
  END w_data[138]
  PIN w_data[139]
    DIRECTION OUTPUT ;
    USE SIGNAL ;
    PORT
      LAYER M4 ;
        RECT  81.996 72.528 82.08 72.552 ;
    END
  END w_data[139]
  PIN w_data[13]
    DIRECTION OUTPUT ;
    USE SIGNAL ;
    PORT
      LAYER M4 ;
        RECT  81.996 63.504 82.08 63.528 ;
    END
  END w_data[13]
  PIN w_data[140]
    DIRECTION OUTPUT ;
    USE SIGNAL ;
    PORT
      LAYER M4 ;
        RECT  81.996 72.624 82.08 72.648 ;
    END
  END w_data[140]
  PIN w_data[141]
    DIRECTION OUTPUT ;
    USE SIGNAL ;
    PORT
      LAYER M4 ;
        RECT  81.996 72.72 82.08 72.744 ;
    END
  END w_data[141]
  PIN w_data[142]
    DIRECTION OUTPUT ;
    USE SIGNAL ;
    PORT
      LAYER M4 ;
        RECT  81.996 72.816 82.08 72.84 ;
    END
  END w_data[142]
  PIN w_data[143]
    DIRECTION OUTPUT ;
    USE SIGNAL ;
    PORT
      LAYER M4 ;
        RECT  81.996 72.912 82.08 72.936 ;
    END
  END w_data[143]
  PIN w_data[144]
    DIRECTION OUTPUT ;
    USE SIGNAL ;
    PORT
      LAYER M4 ;
        RECT  81.996 73.008 82.08 73.032 ;
    END
  END w_data[144]
  PIN w_data[145]
    DIRECTION OUTPUT ;
    USE SIGNAL ;
    PORT
      LAYER M4 ;
        RECT  81.996 73.104 82.08 73.128 ;
    END
  END w_data[145]
  PIN w_data[146]
    DIRECTION OUTPUT ;
    USE SIGNAL ;
    PORT
      LAYER M4 ;
        RECT  81.996 73.2 82.08 73.224 ;
    END
  END w_data[146]
  PIN w_data[147]
    DIRECTION OUTPUT ;
    USE SIGNAL ;
    PORT
      LAYER M4 ;
        RECT  81.996 73.296 82.08 73.32 ;
    END
  END w_data[147]
  PIN w_data[148]
    DIRECTION OUTPUT ;
    USE SIGNAL ;
    PORT
      LAYER M4 ;
        RECT  81.996 73.392 82.08 73.416 ;
    END
  END w_data[148]
  PIN w_data[149]
    DIRECTION OUTPUT ;
    USE SIGNAL ;
    PORT
      LAYER M4 ;
        RECT  81.996 73.488 82.08 73.512 ;
    END
  END w_data[149]
  PIN w_data[14]
    DIRECTION OUTPUT ;
    USE SIGNAL ;
    PORT
      LAYER M4 ;
        RECT  81.996 63.6 82.08 63.624 ;
    END
  END w_data[14]
  PIN w_data[150]
    DIRECTION OUTPUT ;
    USE SIGNAL ;
    PORT
      LAYER M4 ;
        RECT  81.996 73.584 82.08 73.608 ;
    END
  END w_data[150]
  PIN w_data[151]
    DIRECTION OUTPUT ;
    USE SIGNAL ;
    PORT
      LAYER M4 ;
        RECT  81.996 67.536 82.08 67.56 ;
    END
  END w_data[151]
  PIN w_data[152]
    DIRECTION OUTPUT ;
    USE SIGNAL ;
    PORT
      LAYER M4 ;
        RECT  81.996 67.632 82.08 67.656 ;
    END
  END w_data[152]
  PIN w_data[153]
    DIRECTION OUTPUT ;
    USE SIGNAL ;
    PORT
      LAYER M4 ;
        RECT  81.996 67.728 82.08 67.752 ;
    END
  END w_data[153]
  PIN w_data[154]
    DIRECTION OUTPUT ;
    USE SIGNAL ;
    PORT
      LAYER M4 ;
        RECT  81.996 67.824 82.08 67.848 ;
    END
  END w_data[154]
  PIN w_data[155]
    DIRECTION OUTPUT ;
    USE SIGNAL ;
    PORT
      LAYER M4 ;
        RECT  81.996 67.92 82.08 67.944 ;
    END
  END w_data[155]
  PIN w_data[156]
    DIRECTION OUTPUT ;
    USE SIGNAL ;
    PORT
      LAYER M4 ;
        RECT  81.996 68.016 82.08 68.04 ;
    END
  END w_data[156]
  PIN w_data[157]
    DIRECTION OUTPUT ;
    USE SIGNAL ;
    PORT
      LAYER M4 ;
        RECT  81.996 68.112 82.08 68.136 ;
    END
  END w_data[157]
  PIN w_data[158]
    DIRECTION OUTPUT ;
    USE SIGNAL ;
    PORT
      LAYER M4 ;
        RECT  81.996 68.208 82.08 68.232 ;
    END
  END w_data[158]
  PIN w_data[159]
    DIRECTION OUTPUT ;
    USE SIGNAL ;
    PORT
      LAYER M4 ;
        RECT  81.996 68.304 82.08 68.328 ;
    END
  END w_data[159]
  PIN w_data[15]
    DIRECTION OUTPUT ;
    USE SIGNAL ;
    PORT
      LAYER M4 ;
        RECT  81.996 63.696 82.08 63.72 ;
    END
  END w_data[15]
  PIN w_data[160]
    DIRECTION OUTPUT ;
    USE SIGNAL ;
    PORT
      LAYER M4 ;
        RECT  81.996 68.4 82.08 68.424 ;
    END
  END w_data[160]
  PIN w_data[161]
    DIRECTION OUTPUT ;
    USE SIGNAL ;
    PORT
      LAYER M4 ;
        RECT  81.996 68.496 82.08 68.52 ;
    END
  END w_data[161]
  PIN w_data[162]
    DIRECTION OUTPUT ;
    USE SIGNAL ;
    PORT
      LAYER M4 ;
        RECT  81.996 68.592 82.08 68.616 ;
    END
  END w_data[162]
  PIN w_data[163]
    DIRECTION OUTPUT ;
    USE SIGNAL ;
    PORT
      LAYER M4 ;
        RECT  81.996 68.688 82.08 68.712 ;
    END
  END w_data[163]
  PIN w_data[164]
    DIRECTION OUTPUT ;
    USE SIGNAL ;
    PORT
      LAYER M4 ;
        RECT  81.996 68.784 82.08 68.808 ;
    END
  END w_data[164]
  PIN w_data[165]
    DIRECTION OUTPUT ;
    USE SIGNAL ;
    PORT
      LAYER M4 ;
        RECT  81.996 68.88 82.08 68.904 ;
    END
  END w_data[165]
  PIN w_data[166]
    DIRECTION OUTPUT ;
    USE SIGNAL ;
    PORT
      LAYER M4 ;
        RECT  81.996 68.976 82.08 69 ;
    END
  END w_data[166]
  PIN w_data[167]
    DIRECTION OUTPUT ;
    USE SIGNAL ;
    PORT
      LAYER M4 ;
        RECT  81.996 69.072 82.08 69.096 ;
    END
  END w_data[167]
  PIN w_data[168]
    DIRECTION OUTPUT ;
    USE SIGNAL ;
    PORT
      LAYER M4 ;
        RECT  81.996 69.168 82.08 69.192 ;
    END
  END w_data[168]
  PIN w_data[169]
    DIRECTION OUTPUT ;
    USE SIGNAL ;
    PORT
      LAYER M4 ;
        RECT  81.996 69.264 82.08 69.288 ;
    END
  END w_data[169]
  PIN w_data[16]
    DIRECTION OUTPUT ;
    USE SIGNAL ;
    PORT
      LAYER M4 ;
        RECT  81.996 63.792 82.08 63.816 ;
    END
  END w_data[16]
  PIN w_data[170]
    DIRECTION OUTPUT ;
    USE SIGNAL ;
    PORT
      LAYER M4 ;
        RECT  81.996 69.36 82.08 69.384 ;
    END
  END w_data[170]
  PIN w_data[171]
    DIRECTION OUTPUT ;
    USE SIGNAL ;
    PORT
      LAYER M4 ;
        RECT  81.996 69.456 82.08 69.48 ;
    END
  END w_data[171]
  PIN w_data[172]
    DIRECTION OUTPUT ;
    USE SIGNAL ;
    PORT
      LAYER M4 ;
        RECT  81.996 69.552 82.08 69.576 ;
    END
  END w_data[172]
  PIN w_data[173]
    DIRECTION OUTPUT ;
    USE SIGNAL ;
    PORT
      LAYER M4 ;
        RECT  81.996 69.648 82.08 69.672 ;
    END
  END w_data[173]
  PIN w_data[174]
    DIRECTION OUTPUT ;
    USE SIGNAL ;
    PORT
      LAYER M4 ;
        RECT  81.996 69.744 82.08 69.768 ;
    END
  END w_data[174]
  PIN w_data[175]
    DIRECTION OUTPUT ;
    USE SIGNAL ;
    PORT
      LAYER M4 ;
        RECT  81.996 69.84 82.08 69.864 ;
    END
  END w_data[175]
  PIN w_data[176]
    DIRECTION OUTPUT ;
    USE SIGNAL ;
    PORT
      LAYER M4 ;
        RECT  81.996 69.936 82.08 69.96 ;
    END
  END w_data[176]
  PIN w_data[177]
    DIRECTION OUTPUT ;
    USE SIGNAL ;
    PORT
      LAYER M4 ;
        RECT  81.996 70.032 82.08 70.056 ;
    END
  END w_data[177]
  PIN w_data[178]
    DIRECTION OUTPUT ;
    USE SIGNAL ;
    PORT
      LAYER M4 ;
        RECT  81.996 70.128 82.08 70.152 ;
    END
  END w_data[178]
  PIN w_data[179]
    DIRECTION OUTPUT ;
    USE SIGNAL ;
    PORT
      LAYER M4 ;
        RECT  81.996 70.224 82.08 70.248 ;
    END
  END w_data[179]
  PIN w_data[17]
    DIRECTION OUTPUT ;
    USE SIGNAL ;
    PORT
      LAYER M4 ;
        RECT  81.996 63.888 82.08 63.912 ;
    END
  END w_data[17]
  PIN w_data[180]
    DIRECTION OUTPUT ;
    USE SIGNAL ;
    PORT
      LAYER M4 ;
        RECT  81.996 70.32 82.08 70.344 ;
    END
  END w_data[180]
  PIN w_data[181]
    DIRECTION OUTPUT ;
    USE SIGNAL ;
    PORT
      LAYER M4 ;
        RECT  81.996 70.416 82.08 70.44 ;
    END
  END w_data[181]
  PIN w_data[182]
    DIRECTION OUTPUT ;
    USE SIGNAL ;
    PORT
      LAYER M4 ;
        RECT  81.996 70.512 82.08 70.536 ;
    END
  END w_data[182]
  PIN w_data[183]
    DIRECTION OUTPUT ;
    USE SIGNAL ;
    PORT
      LAYER M4 ;
        RECT  81.996 48.336 82.08 48.36 ;
    END
  END w_data[183]
  PIN w_data[184]
    DIRECTION OUTPUT ;
    USE SIGNAL ;
    PORT
      LAYER M4 ;
        RECT  81.996 48.432 82.08 48.456 ;
    END
  END w_data[184]
  PIN w_data[185]
    DIRECTION OUTPUT ;
    USE SIGNAL ;
    PORT
      LAYER M4 ;
        RECT  81.996 48.528 82.08 48.552 ;
    END
  END w_data[185]
  PIN w_data[186]
    DIRECTION OUTPUT ;
    USE SIGNAL ;
    PORT
      LAYER M4 ;
        RECT  81.996 48.624 82.08 48.648 ;
    END
  END w_data[186]
  PIN w_data[187]
    DIRECTION OUTPUT ;
    USE SIGNAL ;
    PORT
      LAYER M4 ;
        RECT  81.996 48.72 82.08 48.744 ;
    END
  END w_data[187]
  PIN w_data[188]
    DIRECTION OUTPUT ;
    USE SIGNAL ;
    PORT
      LAYER M4 ;
        RECT  81.996 48.816 82.08 48.84 ;
    END
  END w_data[188]
  PIN w_data[189]
    DIRECTION OUTPUT ;
    USE SIGNAL ;
    PORT
      LAYER M4 ;
        RECT  81.996 48.912 82.08 48.936 ;
    END
  END w_data[189]
  PIN w_data[18]
    DIRECTION OUTPUT ;
    USE SIGNAL ;
    PORT
      LAYER M4 ;
        RECT  81.996 63.984 82.08 64.008 ;
    END
  END w_data[18]
  PIN w_data[190]
    DIRECTION OUTPUT ;
    USE SIGNAL ;
    PORT
      LAYER M4 ;
        RECT  81.996 49.008 82.08 49.032 ;
    END
  END w_data[190]
  PIN w_data[191]
    DIRECTION OUTPUT ;
    USE SIGNAL ;
    PORT
      LAYER M4 ;
        RECT  81.996 49.104 82.08 49.128 ;
    END
  END w_data[191]
  PIN w_data[192]
    DIRECTION OUTPUT ;
    USE SIGNAL ;
    PORT
      LAYER M4 ;
        RECT  81.996 49.2 82.08 49.224 ;
    END
  END w_data[192]
  PIN w_data[193]
    DIRECTION OUTPUT ;
    USE SIGNAL ;
    PORT
      LAYER M4 ;
        RECT  81.996 49.296 82.08 49.32 ;
    END
  END w_data[193]
  PIN w_data[194]
    DIRECTION OUTPUT ;
    USE SIGNAL ;
    PORT
      LAYER M4 ;
        RECT  81.996 49.392 82.08 49.416 ;
    END
  END w_data[194]
  PIN w_data[195]
    DIRECTION OUTPUT ;
    USE SIGNAL ;
    PORT
      LAYER M4 ;
        RECT  81.996 49.488 82.08 49.512 ;
    END
  END w_data[195]
  PIN w_data[196]
    DIRECTION OUTPUT ;
    USE SIGNAL ;
    PORT
      LAYER M4 ;
        RECT  81.996 49.584 82.08 49.608 ;
    END
  END w_data[196]
  PIN w_data[197]
    DIRECTION OUTPUT ;
    USE SIGNAL ;
    PORT
      LAYER M4 ;
        RECT  81.996 49.68 82.08 49.704 ;
    END
  END w_data[197]
  PIN w_data[198]
    DIRECTION OUTPUT ;
    USE SIGNAL ;
    PORT
      LAYER M4 ;
        RECT  81.996 49.776 82.08 49.8 ;
    END
  END w_data[198]
  PIN w_data[199]
    DIRECTION OUTPUT ;
    USE SIGNAL ;
    PORT
      LAYER M4 ;
        RECT  81.996 49.872 82.08 49.896 ;
    END
  END w_data[199]
  PIN w_data[19]
    DIRECTION OUTPUT ;
    USE SIGNAL ;
    PORT
      LAYER M4 ;
        RECT  81.996 64.08 82.08 64.104 ;
    END
  END w_data[19]
  PIN w_data[1]
    DIRECTION OUTPUT ;
    USE SIGNAL ;
    PORT
      LAYER M4 ;
        RECT  81.996 62.352 82.08 62.376 ;
    END
  END w_data[1]
  PIN w_data[200]
    DIRECTION OUTPUT ;
    USE SIGNAL ;
    PORT
      LAYER M4 ;
        RECT  81.996 49.968 82.08 49.992 ;
    END
  END w_data[200]
  PIN w_data[201]
    DIRECTION OUTPUT ;
    USE SIGNAL ;
    PORT
      LAYER M4 ;
        RECT  81.996 50.064 82.08 50.088 ;
    END
  END w_data[201]
  PIN w_data[202]
    DIRECTION OUTPUT ;
    USE SIGNAL ;
    PORT
      LAYER M4 ;
        RECT  81.996 50.16 82.08 50.184 ;
    END
  END w_data[202]
  PIN w_data[203]
    DIRECTION OUTPUT ;
    USE SIGNAL ;
    PORT
      LAYER M4 ;
        RECT  81.996 50.256 82.08 50.28 ;
    END
  END w_data[203]
  PIN w_data[204]
    DIRECTION OUTPUT ;
    USE SIGNAL ;
    PORT
      LAYER M4 ;
        RECT  81.996 50.352 82.08 50.376 ;
    END
  END w_data[204]
  PIN w_data[205]
    DIRECTION OUTPUT ;
    USE SIGNAL ;
    PORT
      LAYER M4 ;
        RECT  81.996 50.448 82.08 50.472 ;
    END
  END w_data[205]
  PIN w_data[206]
    DIRECTION OUTPUT ;
    USE SIGNAL ;
    PORT
      LAYER M4 ;
        RECT  81.996 50.544 82.08 50.568 ;
    END
  END w_data[206]
  PIN w_data[207]
    DIRECTION OUTPUT ;
    USE SIGNAL ;
    PORT
      LAYER M4 ;
        RECT  81.996 50.64 82.08 50.664 ;
    END
  END w_data[207]
  PIN w_data[208]
    DIRECTION OUTPUT ;
    USE SIGNAL ;
    PORT
      LAYER M4 ;
        RECT  81.996 50.736 82.08 50.76 ;
    END
  END w_data[208]
  PIN w_data[209]
    DIRECTION OUTPUT ;
    USE SIGNAL ;
    PORT
      LAYER M4 ;
        RECT  81.996 50.832 82.08 50.856 ;
    END
  END w_data[209]
  PIN w_data[20]
    DIRECTION OUTPUT ;
    USE SIGNAL ;
    PORT
      LAYER M4 ;
        RECT  81.996 64.176 82.08 64.2 ;
    END
  END w_data[20]
  PIN w_data[210]
    DIRECTION OUTPUT ;
    USE SIGNAL ;
    PORT
      LAYER M4 ;
        RECT  81.996 50.928 82.08 50.952 ;
    END
  END w_data[210]
  PIN w_data[211]
    DIRECTION OUTPUT ;
    USE SIGNAL ;
    PORT
      LAYER M4 ;
        RECT  81.996 51.024 82.08 51.048 ;
    END
  END w_data[211]
  PIN w_data[212]
    DIRECTION OUTPUT ;
    USE SIGNAL ;
    PORT
      LAYER M4 ;
        RECT  81.996 51.12 82.08 51.144 ;
    END
  END w_data[212]
  PIN w_data[213]
    DIRECTION OUTPUT ;
    USE SIGNAL ;
    PORT
      LAYER M4 ;
        RECT  81.996 51.216 82.08 51.24 ;
    END
  END w_data[213]
  PIN w_data[214]
    DIRECTION OUTPUT ;
    USE SIGNAL ;
    PORT
      LAYER M4 ;
        RECT  81.996 51.312 82.08 51.336 ;
    END
  END w_data[214]
  PIN w_data[215]
    DIRECTION OUTPUT ;
    USE SIGNAL ;
    PORT
      LAYER M4 ;
        RECT  81.996 77.52 82.08 77.544 ;
    END
  END w_data[215]
  PIN w_data[216]
    DIRECTION OUTPUT ;
    USE SIGNAL ;
    PORT
      LAYER M4 ;
        RECT  81.996 77.616 82.08 77.64 ;
    END
  END w_data[216]
  PIN w_data[217]
    DIRECTION OUTPUT ;
    USE SIGNAL ;
    PORT
      LAYER M4 ;
        RECT  81.996 77.712 82.08 77.736 ;
    END
  END w_data[217]
  PIN w_data[218]
    DIRECTION OUTPUT ;
    USE SIGNAL ;
    PORT
      LAYER M4 ;
        RECT  81.996 77.808 82.08 77.832 ;
    END
  END w_data[218]
  PIN w_data[219]
    DIRECTION OUTPUT ;
    USE SIGNAL ;
    PORT
      LAYER M4 ;
        RECT  81.996 77.904 82.08 77.928 ;
    END
  END w_data[219]
  PIN w_data[21]
    DIRECTION OUTPUT ;
    USE SIGNAL ;
    PORT
      LAYER M4 ;
        RECT  81.996 64.272 82.08 64.296 ;
    END
  END w_data[21]
  PIN w_data[220]
    DIRECTION OUTPUT ;
    USE SIGNAL ;
    PORT
      LAYER M4 ;
        RECT  81.996 78 82.08 78.024 ;
    END
  END w_data[220]
  PIN w_data[221]
    DIRECTION OUTPUT ;
    USE SIGNAL ;
    PORT
      LAYER M4 ;
        RECT  81.996 78.096 82.08 78.12 ;
    END
  END w_data[221]
  PIN w_data[222]
    DIRECTION OUTPUT ;
    USE SIGNAL ;
    PORT
      LAYER M4 ;
        RECT  81.996 78.192 82.08 78.216 ;
    END
  END w_data[222]
  PIN w_data[223]
    DIRECTION OUTPUT ;
    USE SIGNAL ;
    PORT
      LAYER M4 ;
        RECT  81.996 78.288 82.08 78.312 ;
    END
  END w_data[223]
  PIN w_data[224]
    DIRECTION OUTPUT ;
    USE SIGNAL ;
    PORT
      LAYER M4 ;
        RECT  81.996 78.384 82.08 78.408 ;
    END
  END w_data[224]
  PIN w_data[225]
    DIRECTION OUTPUT ;
    USE SIGNAL ;
    PORT
      LAYER M4 ;
        RECT  81.996 78.48 82.08 78.504 ;
    END
  END w_data[225]
  PIN w_data[226]
    DIRECTION OUTPUT ;
    USE SIGNAL ;
    PORT
      LAYER M4 ;
        RECT  81.996 78.576 82.08 78.6 ;
    END
  END w_data[226]
  PIN w_data[227]
    DIRECTION OUTPUT ;
    USE SIGNAL ;
    PORT
      LAYER M4 ;
        RECT  81.996 78.672 82.08 78.696 ;
    END
  END w_data[227]
  PIN w_data[228]
    DIRECTION OUTPUT ;
    USE SIGNAL ;
    PORT
      LAYER M4 ;
        RECT  81.996 78.768 82.08 78.792 ;
    END
  END w_data[228]
  PIN w_data[229]
    DIRECTION OUTPUT ;
    USE SIGNAL ;
    PORT
      LAYER M4 ;
        RECT  81.996 78.864 82.08 78.888 ;
    END
  END w_data[229]
  PIN w_data[22]
    DIRECTION OUTPUT ;
    USE SIGNAL ;
    PORT
      LAYER M4 ;
        RECT  81.996 64.368 82.08 64.392 ;
    END
  END w_data[22]
  PIN w_data[230]
    DIRECTION OUTPUT ;
    USE SIGNAL ;
    PORT
      LAYER M4 ;
        RECT  81.996 78.96 82.08 78.984 ;
    END
  END w_data[230]
  PIN w_data[231]
    DIRECTION OUTPUT ;
    USE SIGNAL ;
    PORT
      LAYER M4 ;
        RECT  81.996 79.056 82.08 79.08 ;
    END
  END w_data[231]
  PIN w_data[232]
    DIRECTION OUTPUT ;
    USE SIGNAL ;
    PORT
      LAYER M4 ;
        RECT  81.996 79.152 82.08 79.176 ;
    END
  END w_data[232]
  PIN w_data[233]
    DIRECTION OUTPUT ;
    USE SIGNAL ;
    PORT
      LAYER M4 ;
        RECT  81.996 79.248 82.08 79.272 ;
    END
  END w_data[233]
  PIN w_data[234]
    DIRECTION OUTPUT ;
    USE SIGNAL ;
    PORT
      LAYER M4 ;
        RECT  81.996 79.344 82.08 79.368 ;
    END
  END w_data[234]
  PIN w_data[235]
    DIRECTION OUTPUT ;
    USE SIGNAL ;
    PORT
      LAYER M4 ;
        RECT  81.996 79.44 82.08 79.464 ;
    END
  END w_data[235]
  PIN w_data[236]
    DIRECTION OUTPUT ;
    USE SIGNAL ;
    PORT
      LAYER M4 ;
        RECT  81.996 79.536 82.08 79.56 ;
    END
  END w_data[236]
  PIN w_data[237]
    DIRECTION OUTPUT ;
    USE SIGNAL ;
    PORT
      LAYER M4 ;
        RECT  81.996 79.632 82.08 79.656 ;
    END
  END w_data[237]
  PIN w_data[238]
    DIRECTION OUTPUT ;
    USE SIGNAL ;
    PORT
      LAYER M4 ;
        RECT  81.996 79.728 82.08 79.752 ;
    END
  END w_data[238]
  PIN w_data[239]
    DIRECTION OUTPUT ;
    USE SIGNAL ;
    PORT
      LAYER M4 ;
        RECT  81.996 79.824 82.08 79.848 ;
    END
  END w_data[239]
  PIN w_data[23]
    DIRECTION OUTPUT ;
    USE SIGNAL ;
    PORT
      LAYER M4 ;
        RECT  81.996 58.32 82.08 58.344 ;
    END
  END w_data[23]
  PIN w_data[240]
    DIRECTION OUTPUT ;
    USE SIGNAL ;
    PORT
      LAYER M4 ;
        RECT  81.996 79.92 82.08 79.944 ;
    END
  END w_data[240]
  PIN w_data[241]
    DIRECTION OUTPUT ;
    USE SIGNAL ;
    PORT
      LAYER M4 ;
        RECT  81.996 80.016 82.08 80.04 ;
    END
  END w_data[241]
  PIN w_data[242]
    DIRECTION OUTPUT ;
    USE SIGNAL ;
    PORT
      LAYER M4 ;
        RECT  81.996 80.112 82.08 80.136 ;
    END
  END w_data[242]
  PIN w_data[243]
    DIRECTION OUTPUT ;
    USE SIGNAL ;
    PORT
      LAYER M4 ;
        RECT  81.996 80.208 82.08 80.232 ;
    END
  END w_data[243]
  PIN w_data[244]
    DIRECTION OUTPUT ;
    USE SIGNAL ;
    PORT
      LAYER M4 ;
        RECT  81.996 80.304 82.08 80.328 ;
    END
  END w_data[244]
  PIN w_data[245]
    DIRECTION OUTPUT ;
    USE SIGNAL ;
    PORT
      LAYER M4 ;
        RECT  81.996 80.4 82.08 80.424 ;
    END
  END w_data[245]
  PIN w_data[246]
    DIRECTION OUTPUT ;
    USE SIGNAL ;
    PORT
      LAYER M4 ;
        RECT  81.996 80.496 82.08 80.52 ;
    END
  END w_data[246]
  PIN w_data[247]
    DIRECTION OUTPUT ;
    USE SIGNAL ;
    PORT
      LAYER M4 ;
        RECT  81.996 54.48 82.08 54.504 ;
    END
  END w_data[247]
  PIN w_data[248]
    DIRECTION OUTPUT ;
    USE SIGNAL ;
    PORT
      LAYER M4 ;
        RECT  81.996 54.576 82.08 54.6 ;
    END
  END w_data[248]
  PIN w_data[249]
    DIRECTION OUTPUT ;
    USE SIGNAL ;
    PORT
      LAYER M4 ;
        RECT  81.996 54.672 82.08 54.696 ;
    END
  END w_data[249]
  PIN w_data[24]
    DIRECTION OUTPUT ;
    USE SIGNAL ;
    PORT
      LAYER M4 ;
        RECT  81.996 58.416 82.08 58.44 ;
    END
  END w_data[24]
  PIN w_data[250]
    DIRECTION OUTPUT ;
    USE SIGNAL ;
    PORT
      LAYER M4 ;
        RECT  81.996 54.768 82.08 54.792 ;
    END
  END w_data[250]
  PIN w_data[251]
    DIRECTION OUTPUT ;
    USE SIGNAL ;
    PORT
      LAYER M4 ;
        RECT  81.996 54.864 82.08 54.888 ;
    END
  END w_data[251]
  PIN w_data[252]
    DIRECTION OUTPUT ;
    USE SIGNAL ;
    PORT
      LAYER M4 ;
        RECT  81.996 54.96 82.08 54.984 ;
    END
  END w_data[252]
  PIN w_data[253]
    DIRECTION OUTPUT ;
    USE SIGNAL ;
    PORT
      LAYER M4 ;
        RECT  81.996 55.056 82.08 55.08 ;
    END
  END w_data[253]
  PIN w_data[254]
    DIRECTION OUTPUT ;
    USE SIGNAL ;
    PORT
      LAYER M4 ;
        RECT  81.996 55.152 82.08 55.176 ;
    END
  END w_data[254]
  PIN w_data[255]
    DIRECTION OUTPUT ;
    USE SIGNAL ;
    PORT
      LAYER M4 ;
        RECT  81.996 55.248 82.08 55.272 ;
    END
  END w_data[255]
  PIN w_data[25]
    DIRECTION OUTPUT ;
    USE SIGNAL ;
    PORT
      LAYER M4 ;
        RECT  81.996 58.512 82.08 58.536 ;
    END
  END w_data[25]
  PIN w_data[26]
    DIRECTION OUTPUT ;
    USE SIGNAL ;
    PORT
      LAYER M4 ;
        RECT  81.996 58.608 82.08 58.632 ;
    END
  END w_data[26]
  PIN w_data[27]
    DIRECTION OUTPUT ;
    USE SIGNAL ;
    PORT
      LAYER M4 ;
        RECT  81.996 58.704 82.08 58.728 ;
    END
  END w_data[27]
  PIN w_data[28]
    DIRECTION OUTPUT ;
    USE SIGNAL ;
    PORT
      LAYER M4 ;
        RECT  81.996 58.8 82.08 58.824 ;
    END
  END w_data[28]
  PIN w_data[29]
    DIRECTION OUTPUT ;
    USE SIGNAL ;
    PORT
      LAYER M4 ;
        RECT  81.996 58.896 82.08 58.92 ;
    END
  END w_data[29]
  PIN w_data[2]
    DIRECTION OUTPUT ;
    USE SIGNAL ;
    PORT
      LAYER M4 ;
        RECT  81.996 62.448 82.08 62.472 ;
    END
  END w_data[2]
  PIN w_data[30]
    DIRECTION OUTPUT ;
    USE SIGNAL ;
    PORT
      LAYER M4 ;
        RECT  81.996 58.992 82.08 59.016 ;
    END
  END w_data[30]
  PIN w_data[31]
    DIRECTION OUTPUT ;
    USE SIGNAL ;
    PORT
      LAYER M4 ;
        RECT  81.996 59.088 82.08 59.112 ;
    END
  END w_data[31]
  PIN w_data[32]
    DIRECTION OUTPUT ;
    USE SIGNAL ;
    PORT
      LAYER M4 ;
        RECT  81.996 59.184 82.08 59.208 ;
    END
  END w_data[32]
  PIN w_data[33]
    DIRECTION OUTPUT ;
    USE SIGNAL ;
    PORT
      LAYER M4 ;
        RECT  81.996 59.28 82.08 59.304 ;
    END
  END w_data[33]
  PIN w_data[34]
    DIRECTION OUTPUT ;
    USE SIGNAL ;
    PORT
      LAYER M4 ;
        RECT  81.996 59.376 82.08 59.4 ;
    END
  END w_data[34]
  PIN w_data[35]
    DIRECTION OUTPUT ;
    USE SIGNAL ;
    PORT
      LAYER M4 ;
        RECT  81.996 59.472 82.08 59.496 ;
    END
  END w_data[35]
  PIN w_data[36]
    DIRECTION OUTPUT ;
    USE SIGNAL ;
    PORT
      LAYER M4 ;
        RECT  81.996 59.568 82.08 59.592 ;
    END
  END w_data[36]
  PIN w_data[37]
    DIRECTION OUTPUT ;
    USE SIGNAL ;
    PORT
      LAYER M4 ;
        RECT  81.996 59.664 82.08 59.688 ;
    END
  END w_data[37]
  PIN w_data[38]
    DIRECTION OUTPUT ;
    USE SIGNAL ;
    PORT
      LAYER M4 ;
        RECT  81.996 59.76 82.08 59.784 ;
    END
  END w_data[38]
  PIN w_data[39]
    DIRECTION OUTPUT ;
    USE SIGNAL ;
    PORT
      LAYER M4 ;
        RECT  81.996 59.856 82.08 59.88 ;
    END
  END w_data[39]
  PIN w_data[3]
    DIRECTION OUTPUT ;
    USE SIGNAL ;
    PORT
      LAYER M4 ;
        RECT  81.996 62.544 82.08 62.568 ;
    END
  END w_data[3]
  PIN w_data[40]
    DIRECTION OUTPUT ;
    USE SIGNAL ;
    PORT
      LAYER M4 ;
        RECT  81.996 59.952 82.08 59.976 ;
    END
  END w_data[40]
  PIN w_data[41]
    DIRECTION OUTPUT ;
    USE SIGNAL ;
    PORT
      LAYER M4 ;
        RECT  81.996 60.048 82.08 60.072 ;
    END
  END w_data[41]
  PIN w_data[42]
    DIRECTION OUTPUT ;
    USE SIGNAL ;
    PORT
      LAYER M4 ;
        RECT  81.996 60.144 82.08 60.168 ;
    END
  END w_data[42]
  PIN w_data[43]
    DIRECTION OUTPUT ;
    USE SIGNAL ;
    PORT
      LAYER M4 ;
        RECT  81.996 60.24 82.08 60.264 ;
    END
  END w_data[43]
  PIN w_data[44]
    DIRECTION OUTPUT ;
    USE SIGNAL ;
    PORT
      LAYER M4 ;
        RECT  81.996 60.336 82.08 60.36 ;
    END
  END w_data[44]
  PIN w_data[45]
    DIRECTION OUTPUT ;
    USE SIGNAL ;
    PORT
      LAYER M4 ;
        RECT  81.996 60.432 82.08 60.456 ;
    END
  END w_data[45]
  PIN w_data[46]
    DIRECTION OUTPUT ;
    USE SIGNAL ;
    PORT
      LAYER M4 ;
        RECT  81.996 60.528 82.08 60.552 ;
    END
  END w_data[46]
  PIN w_data[47]
    DIRECTION OUTPUT ;
    USE SIGNAL ;
    PORT
      LAYER M4 ;
        RECT  81.996 60.624 82.08 60.648 ;
    END
  END w_data[47]
  PIN w_data[48]
    DIRECTION OUTPUT ;
    USE SIGNAL ;
    PORT
      LAYER M4 ;
        RECT  81.996 60.72 82.08 60.744 ;
    END
  END w_data[48]
  PIN w_data[49]
    DIRECTION OUTPUT ;
    USE SIGNAL ;
    PORT
      LAYER M4 ;
        RECT  81.996 60.816 82.08 60.84 ;
    END
  END w_data[49]
  PIN w_data[4]
    DIRECTION OUTPUT ;
    USE SIGNAL ;
    PORT
      LAYER M4 ;
        RECT  81.996 62.64 82.08 62.664 ;
    END
  END w_data[4]
  PIN w_data[50]
    DIRECTION OUTPUT ;
    USE SIGNAL ;
    PORT
      LAYER M4 ;
        RECT  81.996 60.912 82.08 60.936 ;
    END
  END w_data[50]
  PIN w_data[51]
    DIRECTION OUTPUT ;
    USE SIGNAL ;
    PORT
      LAYER M4 ;
        RECT  81.996 61.008 82.08 61.032 ;
    END
  END w_data[51]
  PIN w_data[52]
    DIRECTION OUTPUT ;
    USE SIGNAL ;
    PORT
      LAYER M4 ;
        RECT  81.996 61.104 82.08 61.128 ;
    END
  END w_data[52]
  PIN w_data[53]
    DIRECTION OUTPUT ;
    USE SIGNAL ;
    PORT
      LAYER M4 ;
        RECT  81.996 61.2 82.08 61.224 ;
    END
  END w_data[53]
  PIN w_data[54]
    DIRECTION OUTPUT ;
    USE SIGNAL ;
    PORT
      LAYER M4 ;
        RECT  81.996 61.296 82.08 61.32 ;
    END
  END w_data[54]
  PIN w_data[55]
    DIRECTION OUTPUT ;
    USE SIGNAL ;
    PORT
      LAYER M4 ;
        RECT  81.996 64.464 82.08 64.488 ;
    END
  END w_data[55]
  PIN w_data[56]
    DIRECTION OUTPUT ;
    USE SIGNAL ;
    PORT
      LAYER M4 ;
        RECT  81.996 64.56 82.08 64.584 ;
    END
  END w_data[56]
  PIN w_data[57]
    DIRECTION OUTPUT ;
    USE SIGNAL ;
    PORT
      LAYER M4 ;
        RECT  81.996 64.656 82.08 64.68 ;
    END
  END w_data[57]
  PIN w_data[58]
    DIRECTION OUTPUT ;
    USE SIGNAL ;
    PORT
      LAYER M4 ;
        RECT  81.996 64.752 82.08 64.776 ;
    END
  END w_data[58]
  PIN w_data[59]
    DIRECTION OUTPUT ;
    USE SIGNAL ;
    PORT
      LAYER M4 ;
        RECT  81.996 64.848 82.08 64.872 ;
    END
  END w_data[59]
  PIN w_data[5]
    DIRECTION OUTPUT ;
    USE SIGNAL ;
    PORT
      LAYER M4 ;
        RECT  81.996 62.736 82.08 62.76 ;
    END
  END w_data[5]
  PIN w_data[60]
    DIRECTION OUTPUT ;
    USE SIGNAL ;
    PORT
      LAYER M4 ;
        RECT  81.996 64.944 82.08 64.968 ;
    END
  END w_data[60]
  PIN w_data[61]
    DIRECTION OUTPUT ;
    USE SIGNAL ;
    PORT
      LAYER M4 ;
        RECT  81.996 65.04 82.08 65.064 ;
    END
  END w_data[61]
  PIN w_data[62]
    DIRECTION OUTPUT ;
    USE SIGNAL ;
    PORT
      LAYER M4 ;
        RECT  81.996 65.136 82.08 65.16 ;
    END
  END w_data[62]
  PIN w_data[63]
    DIRECTION OUTPUT ;
    USE SIGNAL ;
    PORT
      LAYER M4 ;
        RECT  81.996 65.232 82.08 65.256 ;
    END
  END w_data[63]
  PIN w_data[64]
    DIRECTION OUTPUT ;
    USE SIGNAL ;
    PORT
      LAYER M4 ;
        RECT  81.996 65.328 82.08 65.352 ;
    END
  END w_data[64]
  PIN w_data[65]
    DIRECTION OUTPUT ;
    USE SIGNAL ;
    PORT
      LAYER M4 ;
        RECT  81.996 65.424 82.08 65.448 ;
    END
  END w_data[65]
  PIN w_data[66]
    DIRECTION OUTPUT ;
    USE SIGNAL ;
    PORT
      LAYER M4 ;
        RECT  81.996 65.52 82.08 65.544 ;
    END
  END w_data[66]
  PIN w_data[67]
    DIRECTION OUTPUT ;
    USE SIGNAL ;
    PORT
      LAYER M4 ;
        RECT  81.996 65.616 82.08 65.64 ;
    END
  END w_data[67]
  PIN w_data[68]
    DIRECTION OUTPUT ;
    USE SIGNAL ;
    PORT
      LAYER M4 ;
        RECT  81.996 65.712 82.08 65.736 ;
    END
  END w_data[68]
  PIN w_data[69]
    DIRECTION OUTPUT ;
    USE SIGNAL ;
    PORT
      LAYER M4 ;
        RECT  81.996 65.808 82.08 65.832 ;
    END
  END w_data[69]
  PIN w_data[6]
    DIRECTION OUTPUT ;
    USE SIGNAL ;
    PORT
      LAYER M4 ;
        RECT  81.996 62.832 82.08 62.856 ;
    END
  END w_data[6]
  PIN w_data[70]
    DIRECTION OUTPUT ;
    USE SIGNAL ;
    PORT
      LAYER M4 ;
        RECT  81.996 65.904 82.08 65.928 ;
    END
  END w_data[70]
  PIN w_data[71]
    DIRECTION OUTPUT ;
    USE SIGNAL ;
    PORT
      LAYER M4 ;
        RECT  81.996 66 82.08 66.024 ;
    END
  END w_data[71]
  PIN w_data[72]
    DIRECTION OUTPUT ;
    USE SIGNAL ;
    PORT
      LAYER M4 ;
        RECT  81.996 66.096 82.08 66.12 ;
    END
  END w_data[72]
  PIN w_data[73]
    DIRECTION OUTPUT ;
    USE SIGNAL ;
    PORT
      LAYER M4 ;
        RECT  81.996 66.192 82.08 66.216 ;
    END
  END w_data[73]
  PIN w_data[74]
    DIRECTION OUTPUT ;
    USE SIGNAL ;
    PORT
      LAYER M4 ;
        RECT  81.996 66.288 82.08 66.312 ;
    END
  END w_data[74]
  PIN w_data[75]
    DIRECTION OUTPUT ;
    USE SIGNAL ;
    PORT
      LAYER M4 ;
        RECT  81.996 66.384 82.08 66.408 ;
    END
  END w_data[75]
  PIN w_data[76]
    DIRECTION OUTPUT ;
    USE SIGNAL ;
    PORT
      LAYER M4 ;
        RECT  81.996 66.48 82.08 66.504 ;
    END
  END w_data[76]
  PIN w_data[77]
    DIRECTION OUTPUT ;
    USE SIGNAL ;
    PORT
      LAYER M4 ;
        RECT  81.996 66.576 82.08 66.6 ;
    END
  END w_data[77]
  PIN w_data[78]
    DIRECTION OUTPUT ;
    USE SIGNAL ;
    PORT
      LAYER M4 ;
        RECT  81.996 66.672 82.08 66.696 ;
    END
  END w_data[78]
  PIN w_data[79]
    DIRECTION OUTPUT ;
    USE SIGNAL ;
    PORT
      LAYER M4 ;
        RECT  81.996 66.768 82.08 66.792 ;
    END
  END w_data[79]
  PIN w_data[7]
    DIRECTION OUTPUT ;
    USE SIGNAL ;
    PORT
      LAYER M4 ;
        RECT  81.996 62.928 82.08 62.952 ;
    END
  END w_data[7]
  PIN w_data[80]
    DIRECTION OUTPUT ;
    USE SIGNAL ;
    PORT
      LAYER M4 ;
        RECT  81.996 66.864 82.08 66.888 ;
    END
  END w_data[80]
  PIN w_data[81]
    DIRECTION OUTPUT ;
    USE SIGNAL ;
    PORT
      LAYER M4 ;
        RECT  81.996 66.96 82.08 66.984 ;
    END
  END w_data[81]
  PIN w_data[82]
    DIRECTION OUTPUT ;
    USE SIGNAL ;
    PORT
      LAYER M4 ;
        RECT  81.996 67.056 82.08 67.08 ;
    END
  END w_data[82]
  PIN w_data[83]
    DIRECTION OUTPUT ;
    USE SIGNAL ;
    PORT
      LAYER M4 ;
        RECT  81.996 67.152 82.08 67.176 ;
    END
  END w_data[83]
  PIN w_data[84]
    DIRECTION OUTPUT ;
    USE SIGNAL ;
    PORT
      LAYER M4 ;
        RECT  81.996 67.248 82.08 67.272 ;
    END
  END w_data[84]
  PIN w_data[85]
    DIRECTION OUTPUT ;
    USE SIGNAL ;
    PORT
      LAYER M4 ;
        RECT  81.996 67.344 82.08 67.368 ;
    END
  END w_data[85]
  PIN w_data[86]
    DIRECTION OUTPUT ;
    USE SIGNAL ;
    PORT
      LAYER M4 ;
        RECT  81.996 67.44 82.08 67.464 ;
    END
  END w_data[86]
  PIN w_data[87]
    DIRECTION OUTPUT ;
    USE SIGNAL ;
    PORT
      LAYER M4 ;
        RECT  81.996 73.68 82.08 73.704 ;
    END
  END w_data[87]
  PIN w_data[88]
    DIRECTION OUTPUT ;
    USE SIGNAL ;
    PORT
      LAYER M4 ;
        RECT  81.996 73.776 82.08 73.8 ;
    END
  END w_data[88]
  PIN w_data[89]
    DIRECTION OUTPUT ;
    USE SIGNAL ;
    PORT
      LAYER M4 ;
        RECT  81.996 73.872 82.08 73.896 ;
    END
  END w_data[89]
  PIN w_data[8]
    DIRECTION OUTPUT ;
    USE SIGNAL ;
    PORT
      LAYER M4 ;
        RECT  81.996 63.024 82.08 63.048 ;
    END
  END w_data[8]
  PIN w_data[90]
    DIRECTION OUTPUT ;
    USE SIGNAL ;
    PORT
      LAYER M4 ;
        RECT  81.996 73.968 82.08 73.992 ;
    END
  END w_data[90]
  PIN w_data[91]
    DIRECTION OUTPUT ;
    USE SIGNAL ;
    PORT
      LAYER M4 ;
        RECT  81.996 74.064 82.08 74.088 ;
    END
  END w_data[91]
  PIN w_data[92]
    DIRECTION OUTPUT ;
    USE SIGNAL ;
    PORT
      LAYER M4 ;
        RECT  81.996 74.16 82.08 74.184 ;
    END
  END w_data[92]
  PIN w_data[93]
    DIRECTION OUTPUT ;
    USE SIGNAL ;
    PORT
      LAYER M4 ;
        RECT  81.996 74.256 82.08 74.28 ;
    END
  END w_data[93]
  PIN w_data[94]
    DIRECTION OUTPUT ;
    USE SIGNAL ;
    PORT
      LAYER M4 ;
        RECT  81.996 74.352 82.08 74.376 ;
    END
  END w_data[94]
  PIN w_data[95]
    DIRECTION OUTPUT ;
    USE SIGNAL ;
    PORT
      LAYER M4 ;
        RECT  81.996 74.448 82.08 74.472 ;
    END
  END w_data[95]
  PIN w_data[96]
    DIRECTION OUTPUT ;
    USE SIGNAL ;
    PORT
      LAYER M4 ;
        RECT  81.996 74.544 82.08 74.568 ;
    END
  END w_data[96]
  PIN w_data[97]
    DIRECTION OUTPUT ;
    USE SIGNAL ;
    PORT
      LAYER M4 ;
        RECT  81.996 74.64 82.08 74.664 ;
    END
  END w_data[97]
  PIN w_data[98]
    DIRECTION OUTPUT ;
    USE SIGNAL ;
    PORT
      LAYER M4 ;
        RECT  81.996 74.736 82.08 74.76 ;
    END
  END w_data[98]
  PIN w_data[99]
    DIRECTION OUTPUT ;
    USE SIGNAL ;
    PORT
      LAYER M4 ;
        RECT  81.996 74.832 82.08 74.856 ;
    END
  END w_data[99]
  PIN w_data[9]
    DIRECTION OUTPUT ;
    USE SIGNAL ;
    PORT
      LAYER M4 ;
        RECT  81.996 63.12 82.08 63.144 ;
    END
  END w_data[9]
  PIN w_we[0]
    DIRECTION OUTPUT ;
    USE SIGNAL ;
    PORT
      LAYER M4 ;
        RECT  81.996 55.344 82.08 55.368 ;
    END
  END w_we[0]
  PIN w_we[1]
    DIRECTION OUTPUT ;
    USE SIGNAL ;
    PORT
      LAYER M4 ;
        RECT  81.996 55.44 82.08 55.464 ;
    END
  END w_we[1]
  PIN w_we[2]
    DIRECTION OUTPUT ;
    USE SIGNAL ;
    PORT
      LAYER M4 ;
        RECT  81.996 55.536 82.08 55.56 ;
    END
  END w_we[2]
  PIN w_we[3]
    DIRECTION OUTPUT ;
    USE SIGNAL ;
    PORT
      LAYER M4 ;
        RECT  81.996 55.632 82.08 55.656 ;
    END
  END w_we[3]
  PIN w_we[4]
    DIRECTION OUTPUT ;
    USE SIGNAL ;
    PORT
      LAYER M4 ;
        RECT  81.996 55.728 82.08 55.752 ;
    END
  END w_we[4]
  PIN w_we[5]
    DIRECTION OUTPUT ;
    USE SIGNAL ;
    PORT
      LAYER M4 ;
        RECT  81.996 55.824 82.08 55.848 ;
    END
  END w_we[5]
  PIN w_we[6]
    DIRECTION OUTPUT ;
    USE SIGNAL ;
    PORT
      LAYER M4 ;
        RECT  81.996 55.92 82.08 55.944 ;
    END
  END w_we[6]
  PIN w_we[7]
    DIRECTION OUTPUT ;
    USE SIGNAL ;
    PORT
      LAYER M4 ;
        RECT  81.996 56.016 82.08 56.04 ;
    END
  END w_we[7]
  PIN VSS
    DIRECTION INOUT ;
    USE GROUND ;
    PORT
      LAYER M5 ;
        RECT  78 2.137 78.12 79.943 ;
        RECT  72.6 2.137 72.72 79.943 ;
        RECT  67.2 2.137 67.32 79.943 ;
        RECT  61.8 2.137 61.92 79.943 ;
        RECT  56.4 2.137 56.52 79.943 ;
        RECT  51 2.137 51.12 79.943 ;
        RECT  45.6 2.137 45.72 79.943 ;
        RECT  40.2 2.137 40.32 79.943 ;
        RECT  34.8 2.137 34.92 79.943 ;
        RECT  29.4 2.137 29.52 79.943 ;
        RECT  24 2.137 24.12 79.943 ;
        RECT  18.6 2.137 18.72 79.943 ;
        RECT  13.2 2.137 13.32 79.943 ;
        RECT  7.8 2.137 7.92 79.943 ;
        RECT  2.4 2.137 2.52 79.943 ;
    END
  END VSS
  PIN VDD
    DIRECTION INOUT ;
    USE POWER ;
    PORT
      LAYER M5 ;
        RECT  78.192 2.151 78.312 79.929 ;
        RECT  72.792 2.151 72.912 79.929 ;
        RECT  67.392 2.151 67.512 79.929 ;
        RECT  61.992 2.151 62.112 79.929 ;
        RECT  56.592 2.151 56.712 79.929 ;
        RECT  51.192 2.151 51.312 79.929 ;
        RECT  45.792 2.151 45.912 79.929 ;
        RECT  40.392 2.151 40.512 79.929 ;
        RECT  34.992 2.151 35.112 79.929 ;
        RECT  29.592 2.151 29.712 79.929 ;
        RECT  24.192 2.151 24.312 79.929 ;
        RECT  18.792 2.151 18.912 79.929 ;
        RECT  13.392 2.151 13.512 79.929 ;
        RECT  7.992 2.151 8.112 79.929 ;
        RECT  2.592 2.151 2.712 79.929 ;
    END
  END VDD
  OBS
    LAYER RVTN ;
     RECT  2.16 2.16 79.92 2.295 ;
     RECT  2.16 2.565 79.92 2.835 ;
     RECT  2.16 3.105 79.92 3.375 ;
     RECT  2.16 3.645 79.92 3.915 ;
     RECT  2.16 4.185 79.92 4.455 ;
     RECT  2.16 4.725 79.92 4.995 ;
     RECT  2.16 5.265 79.92 5.535 ;
     RECT  2.16 5.805 79.92 6.075 ;
     RECT  2.16 6.345 79.92 6.615 ;
     RECT  2.16 6.885 79.92 7.155 ;
     RECT  2.16 7.425 79.92 7.695 ;
     RECT  2.16 7.965 79.92 8.235 ;
     RECT  2.16 8.505 79.92 8.775 ;
     RECT  2.16 9.045 79.92 9.315 ;
     RECT  2.16 9.585 79.92 9.855 ;
     RECT  2.16 10.125 79.92 10.395 ;
     RECT  2.16 10.665 79.92 10.935 ;
     RECT  2.16 11.205 79.92 11.475 ;
     RECT  2.16 11.745 79.92 12.015 ;
     RECT  2.16 12.285 79.92 12.555 ;
     RECT  2.16 12.825 79.92 13.095 ;
     RECT  2.16 13.365 79.92 13.635 ;
     RECT  2.16 13.905 79.92 14.175 ;
     RECT  2.16 14.445 79.92 14.715 ;
     RECT  2.16 14.985 79.92 15.255 ;
     RECT  2.16 15.525 79.92 15.795 ;
     RECT  2.16 16.065 79.92 16.335 ;
     RECT  2.16 16.605 79.92 16.875 ;
     RECT  2.16 17.145 79.92 17.415 ;
     RECT  2.16 17.685 79.92 17.955 ;
     RECT  2.16 18.225 79.92 18.495 ;
     RECT  2.16 18.765 79.92 19.035 ;
     RECT  2.16 19.305 79.92 19.575 ;
     RECT  2.16 19.845 79.92 20.115 ;
     RECT  2.16 20.385 79.92 20.655 ;
     RECT  2.16 20.925 79.92 21.195 ;
     RECT  2.16 21.465 79.92 21.735 ;
     RECT  2.16 22.005 79.92 22.275 ;
     RECT  2.16 22.545 79.92 22.815 ;
     RECT  2.16 23.085 79.92 23.355 ;
     RECT  2.16 23.625 79.92 23.895 ;
     RECT  2.16 24.165 79.92 24.435 ;
     RECT  2.16 24.705 79.92 24.975 ;
     RECT  2.16 25.245 79.92 25.515 ;
     RECT  2.16 25.785 79.92 26.055 ;
     RECT  2.16 26.325 79.92 26.595 ;
     RECT  2.16 26.865 79.92 27.135 ;
     RECT  2.16 27.405 79.92 27.675 ;
     RECT  2.16 27.945 79.92 28.215 ;
     RECT  2.16 28.485 79.92 28.755 ;
     RECT  2.16 29.025 79.92 29.295 ;
     RECT  2.16 29.565 79.92 29.835 ;
     RECT  2.16 30.105 79.92 30.375 ;
     RECT  2.16 30.645 79.92 30.915 ;
     RECT  2.16 31.185 79.92 31.455 ;
     RECT  2.16 31.725 79.92 31.995 ;
     RECT  2.16 32.265 79.92 32.535 ;
     RECT  2.16 32.805 79.92 33.075 ;
     RECT  2.16 33.345 79.92 33.615 ;
     RECT  2.16 33.885 79.92 34.155 ;
     RECT  2.16 34.425 79.92 34.695 ;
     RECT  2.16 34.965 79.92 35.235 ;
     RECT  2.16 35.505 79.92 35.775 ;
     RECT  2.16 36.045 79.92 36.315 ;
     RECT  2.16 36.585 79.92 36.855 ;
     RECT  2.16 37.125 79.92 37.395 ;
     RECT  2.16 37.665 79.92 37.935 ;
     RECT  2.16 38.205 79.92 38.475 ;
     RECT  2.16 38.745 79.92 39.015 ;
     RECT  2.16 39.285 79.92 39.555 ;
     RECT  2.16 39.825 79.92 40.095 ;
     RECT  2.16 40.365 79.92 40.635 ;
     RECT  2.16 40.905 79.92 41.175 ;
     RECT  2.16 41.445 79.92 41.715 ;
     RECT  2.16 41.985 79.92 42.255 ;
     RECT  2.16 42.525 79.92 42.795 ;
     RECT  2.16 43.065 79.92 43.335 ;
     RECT  2.16 43.605 79.92 43.875 ;
     RECT  2.16 44.145 79.92 44.415 ;
     RECT  2.16 44.685 79.92 44.955 ;
     RECT  2.16 45.225 79.92 45.495 ;
     RECT  2.16 45.765 79.92 46.035 ;
     RECT  2.16 46.305 79.92 46.575 ;
     RECT  2.16 46.845 79.92 47.115 ;
     RECT  2.16 47.385 79.92 47.655 ;
     RECT  2.16 47.925 79.92 48.195 ;
     RECT  2.16 48.465 79.92 48.735 ;
     RECT  2.16 49.005 79.92 49.275 ;
     RECT  2.16 49.545 79.92 49.815 ;
     RECT  2.16 50.085 79.92 50.355 ;
     RECT  2.16 50.625 79.92 50.895 ;
     RECT  2.16 51.165 79.92 51.435 ;
     RECT  2.16 51.705 79.92 51.975 ;
     RECT  2.16 52.245 79.92 52.515 ;
     RECT  2.16 52.785 79.92 53.055 ;
     RECT  2.16 53.325 79.92 53.595 ;
     RECT  2.16 53.865 79.92 54.135 ;
     RECT  2.16 54.405 79.92 54.675 ;
     RECT  2.16 54.945 79.92 55.215 ;
     RECT  2.16 55.485 79.92 55.755 ;
     RECT  2.16 56.025 79.92 56.295 ;
     RECT  2.16 56.565 79.92 56.835 ;
     RECT  2.16 57.105 79.92 57.375 ;
     RECT  2.16 57.645 79.92 57.915 ;
     RECT  2.16 58.185 79.92 58.455 ;
     RECT  2.16 58.725 79.92 58.995 ;
     RECT  2.16 59.265 79.92 59.535 ;
     RECT  2.16 59.805 79.92 60.075 ;
     RECT  2.16 60.345 79.92 60.615 ;
     RECT  2.16 60.885 79.92 61.155 ;
     RECT  2.16 61.425 79.92 61.695 ;
     RECT  2.16 61.965 79.92 62.235 ;
     RECT  2.16 62.505 79.92 62.775 ;
     RECT  2.16 63.045 79.92 63.315 ;
     RECT  2.16 63.585 79.92 63.855 ;
     RECT  2.16 64.125 79.92 64.395 ;
     RECT  2.16 64.665 79.92 64.935 ;
     RECT  2.16 65.205 79.92 65.475 ;
     RECT  2.16 65.745 79.92 66.015 ;
     RECT  2.16 66.285 79.92 66.555 ;
     RECT  2.16 66.825 79.92 67.095 ;
     RECT  2.16 67.365 79.92 67.635 ;
     RECT  2.16 67.905 79.92 68.175 ;
     RECT  2.16 68.445 79.92 68.715 ;
     RECT  2.16 68.985 79.92 69.255 ;
     RECT  2.16 69.525 79.92 69.795 ;
     RECT  2.16 70.065 79.92 70.335 ;
     RECT  2.16 70.605 79.92 70.875 ;
     RECT  2.16 71.145 79.92 71.415 ;
     RECT  2.16 71.685 79.92 71.955 ;
     RECT  2.16 72.225 79.92 72.495 ;
     RECT  2.16 72.765 79.92 73.035 ;
     RECT  2.16 73.305 79.92 73.575 ;
     RECT  2.16 73.845 79.92 74.115 ;
     RECT  2.16 74.385 79.92 74.655 ;
     RECT  2.16 74.925 79.92 75.195 ;
     RECT  2.16 75.465 79.92 75.735 ;
     RECT  2.16 76.005 79.92 76.275 ;
     RECT  2.16 76.545 79.92 76.815 ;
     RECT  2.16 77.085 79.92 77.355 ;
     RECT  2.16 77.625 79.92 77.895 ;
     RECT  2.16 78.165 79.92 78.435 ;
     RECT  2.16 78.705 79.92 78.975 ;
     RECT  2.16 79.245 79.92 79.515 ;
     RECT  2.16 79.785 79.92 79.92 ;
    LAYER RVTP ;
     RECT  2.16 2.295 79.92 2.565 ;
     RECT  2.16 2.835 79.92 3.105 ;
     RECT  2.16 3.375 79.92 3.645 ;
     RECT  2.16 3.915 79.92 4.185 ;
     RECT  2.16 4.455 79.92 4.725 ;
     RECT  2.16 4.995 79.92 5.265 ;
     RECT  2.16 5.535 79.92 5.805 ;
     RECT  2.16 6.075 79.92 6.345 ;
     RECT  2.16 6.615 79.92 6.885 ;
     RECT  2.16 7.155 79.92 7.425 ;
     RECT  2.16 7.695 79.92 7.965 ;
     RECT  2.16 8.235 79.92 8.505 ;
     RECT  2.16 8.775 79.92 9.045 ;
     RECT  2.16 9.315 79.92 9.585 ;
     RECT  2.16 9.855 79.92 10.125 ;
     RECT  2.16 10.395 79.92 10.665 ;
     RECT  2.16 10.935 79.92 11.205 ;
     RECT  2.16 11.475 79.92 11.745 ;
     RECT  2.16 12.015 79.92 12.285 ;
     RECT  2.16 12.555 79.92 12.825 ;
     RECT  2.16 13.095 79.92 13.365 ;
     RECT  2.16 13.635 79.92 13.905 ;
     RECT  2.16 14.175 79.92 14.445 ;
     RECT  2.16 14.715 79.92 14.985 ;
     RECT  2.16 15.255 79.92 15.525 ;
     RECT  2.16 15.795 79.92 16.065 ;
     RECT  2.16 16.335 79.92 16.605 ;
     RECT  2.16 16.875 79.92 17.145 ;
     RECT  2.16 17.415 79.92 17.685 ;
     RECT  2.16 17.955 79.92 18.225 ;
     RECT  2.16 18.495 79.92 18.765 ;
     RECT  2.16 19.035 79.92 19.305 ;
     RECT  2.16 19.575 79.92 19.845 ;
     RECT  2.16 20.115 79.92 20.385 ;
     RECT  2.16 20.655 79.92 20.925 ;
     RECT  2.16 21.195 79.92 21.465 ;
     RECT  2.16 21.735 79.92 22.005 ;
     RECT  2.16 22.275 79.92 22.545 ;
     RECT  2.16 22.815 79.92 23.085 ;
     RECT  2.16 23.355 79.92 23.625 ;
     RECT  2.16 23.895 79.92 24.165 ;
     RECT  2.16 24.435 79.92 24.705 ;
     RECT  2.16 24.975 79.92 25.245 ;
     RECT  2.16 25.515 79.92 25.785 ;
     RECT  2.16 26.055 79.92 26.325 ;
     RECT  2.16 26.595 79.92 26.865 ;
     RECT  2.16 27.135 79.92 27.405 ;
     RECT  2.16 27.675 79.92 27.945 ;
     RECT  2.16 28.215 79.92 28.485 ;
     RECT  2.16 28.755 79.92 29.025 ;
     RECT  2.16 29.295 79.92 29.565 ;
     RECT  2.16 29.835 79.92 30.105 ;
     RECT  2.16 30.375 79.92 30.645 ;
     RECT  2.16 30.915 79.92 31.185 ;
     RECT  2.16 31.455 79.92 31.725 ;
     RECT  2.16 31.995 79.92 32.265 ;
     RECT  2.16 32.535 79.92 32.805 ;
     RECT  2.16 33.075 79.92 33.345 ;
     RECT  2.16 33.615 79.92 33.885 ;
     RECT  2.16 34.155 79.92 34.425 ;
     RECT  2.16 34.695 79.92 34.965 ;
     RECT  2.16 35.235 79.92 35.505 ;
     RECT  2.16 35.775 79.92 36.045 ;
     RECT  2.16 36.315 79.92 36.585 ;
     RECT  2.16 36.855 79.92 37.125 ;
     RECT  2.16 37.395 79.92 37.665 ;
     RECT  2.16 37.935 79.92 38.205 ;
     RECT  2.16 38.475 79.92 38.745 ;
     RECT  2.16 39.015 79.92 39.285 ;
     RECT  2.16 39.555 79.92 39.825 ;
     RECT  2.16 40.095 79.92 40.365 ;
     RECT  2.16 40.635 79.92 40.905 ;
     RECT  2.16 41.175 79.92 41.445 ;
     RECT  2.16 41.715 79.92 41.985 ;
     RECT  2.16 42.255 79.92 42.525 ;
     RECT  2.16 42.795 79.92 43.065 ;
     RECT  2.16 43.335 79.92 43.605 ;
     RECT  2.16 43.875 79.92 44.145 ;
     RECT  2.16 44.415 79.92 44.685 ;
     RECT  2.16 44.955 79.92 45.225 ;
     RECT  2.16 45.495 79.92 45.765 ;
     RECT  2.16 46.035 79.92 46.305 ;
     RECT  2.16 46.575 79.92 46.845 ;
     RECT  2.16 47.115 79.92 47.385 ;
     RECT  2.16 47.655 79.92 47.925 ;
     RECT  2.16 48.195 79.92 48.465 ;
     RECT  2.16 48.735 79.92 49.005 ;
     RECT  2.16 49.275 79.92 49.545 ;
     RECT  2.16 49.815 79.92 50.085 ;
     RECT  2.16 50.355 79.92 50.625 ;
     RECT  2.16 50.895 79.92 51.165 ;
     RECT  2.16 51.435 79.92 51.705 ;
     RECT  2.16 51.975 79.92 52.245 ;
     RECT  2.16 52.515 79.92 52.785 ;
     RECT  2.16 53.055 79.92 53.325 ;
     RECT  2.16 53.595 79.92 53.865 ;
     RECT  2.16 54.135 79.92 54.405 ;
     RECT  2.16 54.675 79.92 54.945 ;
     RECT  2.16 55.215 79.92 55.485 ;
     RECT  2.16 55.755 79.92 56.025 ;
     RECT  2.16 56.295 79.92 56.565 ;
     RECT  2.16 56.835 79.92 57.105 ;
     RECT  2.16 57.375 79.92 57.645 ;
     RECT  2.16 57.915 79.92 58.185 ;
     RECT  2.16 58.455 79.92 58.725 ;
     RECT  2.16 58.995 79.92 59.265 ;
     RECT  2.16 59.535 79.92 59.805 ;
     RECT  2.16 60.075 79.92 60.345 ;
     RECT  2.16 60.615 79.92 60.885 ;
     RECT  2.16 61.155 79.92 61.425 ;
     RECT  2.16 61.695 79.92 61.965 ;
     RECT  2.16 62.235 79.92 62.505 ;
     RECT  2.16 62.775 79.92 63.045 ;
     RECT  2.16 63.315 79.92 63.585 ;
     RECT  2.16 63.855 79.92 64.125 ;
     RECT  2.16 64.395 79.92 64.665 ;
     RECT  2.16 64.935 79.92 65.205 ;
     RECT  2.16 65.475 79.92 65.745 ;
     RECT  2.16 66.015 79.92 66.285 ;
     RECT  2.16 66.555 79.92 66.825 ;
     RECT  2.16 67.095 79.92 67.365 ;
     RECT  2.16 67.635 79.92 67.905 ;
     RECT  2.16 68.175 79.92 68.445 ;
     RECT  2.16 68.715 79.92 68.985 ;
     RECT  2.16 69.255 79.92 69.525 ;
     RECT  2.16 69.795 79.92 70.065 ;
     RECT  2.16 70.335 79.92 70.605 ;
     RECT  2.16 70.875 79.92 71.145 ;
     RECT  2.16 71.415 79.92 71.685 ;
     RECT  2.16 71.955 79.92 72.225 ;
     RECT  2.16 72.495 79.92 72.765 ;
     RECT  2.16 73.035 79.92 73.305 ;
     RECT  2.16 73.575 79.92 73.845 ;
     RECT  2.16 74.115 79.92 74.385 ;
     RECT  2.16 74.655 79.92 74.925 ;
     RECT  2.16 75.195 79.92 75.465 ;
     RECT  2.16 75.735 79.92 76.005 ;
     RECT  2.16 76.275 79.92 76.545 ;
     RECT  2.16 76.815 79.92 77.085 ;
     RECT  2.16 77.355 79.92 77.625 ;
     RECT  2.16 77.895 79.92 78.165 ;
     RECT  2.16 78.435 79.92 78.705 ;
     RECT  2.16 78.975 79.92 79.245 ;
     RECT  2.16 79.515 79.92 79.785 ;
    LAYER M1 ;
     RECT  2.16 2.151 79.92 79.929 ;
    LAYER M2 ;
     RECT  2.155 2.232 2.16 2.25 ;
     RECT  2.047 7.362 2.16 7.38 ;
     RECT  2.16 2.151 18.571 79.929 ;
     RECT  18.571 2.151 21.091 79.974 ;
     RECT  21.091 2.151 24.727 80.046 ;
     RECT  24.727 2.034 25.727 80.046 ;
     RECT  25.727 2.106 25.799 80.046 ;
     RECT  25.799 2.106 26.159 79.929 ;
     RECT  26.159 2.151 41.071 79.929 ;
     RECT  41.071 2.106 41.963 79.929 ;
     RECT  41.963 2.151 46.327 79.929 ;
     RECT  46.327 2.106 46.823 79.929 ;
     RECT  46.823 2.151 58.531 79.929 ;
     RECT  58.531 2.106 59.711 79.929 ;
     RECT  59.711 2.151 79.92 79.929 ;
     RECT  79.92 20.286 80.087 21.114 ;
     RECT  79.92 37.476 80.087 38.502 ;
     RECT  79.92 52.416 80.087 53.352 ;
     RECT  80.087 20.286 80.123 20.988 ;
     RECT  79.92 7.632 80.339 10.854 ;
     RECT  80.339 10.836 80.375 10.854 ;
     RECT  79.92 30.276 80.375 31.644 ;
     RECT  79.92 41.616 80.375 43.164 ;
     RECT  79.92 57.312 80.375 58.482 ;
     RECT  79.92 50.13 80.411 51.534 ;
     RECT  80.375 57.456 80.411 58.482 ;
     RECT  80.123 20.97 80.663 20.988 ;
     RECT  80.375 30.996 80.663 31.644 ;
     RECT  79.92 36.486 80.663 36.504 ;
     RECT  80.087 37.908 80.699 38.502 ;
     RECT  79.92 13.644 80.735 17.874 ;
     RECT  79.92 59.616 80.735 64.962 ;
     RECT  80.087 52.416 80.807 52.884 ;
     RECT  80.735 16.344 80.879 17.874 ;
     RECT  80.339 7.632 80.951 9.774 ;
     RECT  80.735 13.644 80.951 15.48 ;
     RECT  80.879 16.344 80.951 17.604 ;
     RECT  79.92 26.496 80.951 27.198 ;
     RECT  79.92 28.386 80.951 28.404 ;
     RECT  79.92 40.806 80.951 40.824 ;
     RECT  80.375 41.616 80.951 42.984 ;
     RECT  80.411 51.516 80.951 51.534 ;
     RECT  80.735 62.406 80.951 64.962 ;
     RECT  79.92 66.096 80.951 79.776 ;
     RECT  79.92 12.528 80.987 12.546 ;
     RECT  80.951 14.526 80.987 15.48 ;
     RECT  80.951 27.18 80.987 27.198 ;
     RECT  80.699 37.908 80.987 38.196 ;
     RECT  80.951 41.616 80.987 42.75 ;
     RECT  79.92 48.636 80.987 49.374 ;
     RECT  80.411 50.13 80.987 50.652 ;
     RECT  80.411 57.456 80.987 58.14 ;
     RECT  80.951 66.096 80.987 73.332 ;
     RECT  80.951 78.408 80.987 79.776 ;
     RECT  79.92 5.436 81.059 6.84 ;
     RECT  80.987 38.178 81.059 38.196 ;
     RECT  81.059 5.436 81.095 5.634 ;
     RECT  81.095 5.436 81.131 5.454 ;
     RECT  81.059 6.696 81.167 6.84 ;
     RECT  79.92 54.648 81.175 54.774 ;
     RECT  79.92 56.034 81.175 56.052 ;
     RECT  81.167 6.822 81.203 6.84 ;
     RECT  79.92 24.606 81.239 25.074 ;
     RECT  79.92 32.616 81.239 32.634 ;
     RECT  79.92 46.044 81.239 47.754 ;
     RECT  80.735 59.616 81.239 61.452 ;
     RECT  80.951 74.466 81.239 74.484 ;
     RECT  80.987 58.122 81.247 58.14 ;
     RECT  79.92 44.856 81.275 44.874 ;
     RECT  79.92 22.446 81.311 22.464 ;
     RECT  80.987 42.732 81.311 42.75 ;
     RECT  81.175 54.648 81.311 56.052 ;
     RECT  81.239 46.386 81.347 47.106 ;
     RECT  81.239 59.616 81.383 61.344 ;
     RECT  79.92 39.636 81.455 39.816 ;
     RECT  80.987 66.096 81.455 69.984 ;
     RECT  80.951 75.438 81.455 77.454 ;
     RECT  80.951 13.644 81.491 13.662 ;
     RECT  80.951 16.344 81.491 16.434 ;
     RECT  81.239 25.056 81.491 25.074 ;
     RECT  80.663 30.996 81.491 31.014 ;
     RECT  81.455 39.798 81.491 39.816 ;
     RECT  80.987 41.616 81.491 41.634 ;
     RECT  80.987 48.708 81.491 49.374 ;
     RECT  80.987 50.13 81.491 50.148 ;
     RECT  80.807 52.866 81.491 52.884 ;
     RECT  81.247 58.122 81.491 58.752 ;
     RECT  80.951 62.406 81.491 62.694 ;
     RECT  80.951 63.666 81.491 64.962 ;
     RECT  81.455 66.096 81.491 66.582 ;
     RECT  81.455 67.608 81.491 69.984 ;
     RECT  80.987 70.884 81.491 71.712 ;
     RECT  81.455 75.438 81.491 77.184 ;
     RECT  80.987 78.786 81.491 79.776 ;
     RECT  79.92 11.646 81.527 11.664 ;
     RECT  80.987 15.228 81.527 15.48 ;
     RECT  81.311 54.648 81.527 55.359 ;
     RECT  81.491 58.734 81.527 58.752 ;
     RECT  81.383 60.084 81.527 61.344 ;
     RECT  81.491 62.406 81.527 62.604 ;
     RECT  81.491 64.134 81.527 64.224 ;
     RECT  81.491 68.112 81.527 68.274 ;
     RECT  80.987 72.54 81.527 73.332 ;
     RECT  81.491 78.786 81.527 79.659 ;
     RECT  81.491 66.564 81.563 66.582 ;
     RECT  81.527 64.206 81.599 64.224 ;
     RECT  81.527 73.314 81.787 73.332 ;
     RECT  81.491 75.438 81.895 75.456 ;
     RECT  81.787 73.314 81.923 73.449 ;
     RECT  81.527 15.462 81.959 15.48 ;
     RECT  79.92 18.666 81.959 18.954 ;
     RECT  81.491 49.131 81.959 49.374 ;
     RECT  81.527 54.72 81.959 55.359 ;
     RECT  81.527 60.588 81.959 60.606 ;
     RECT  81.527 68.112 81.959 68.13 ;
     RECT  81.959 49.176 81.967 49.374 ;
     RECT  80.951 9.756 81.995 9.774 ;
     RECT  81.491 16.344 81.995 16.362 ;
     RECT  81.959 18.936 81.995 18.954 ;
     RECT  81.967 49.176 81.995 49.419 ;
     RECT  81.959 54.756 81.995 55.359 ;
     RECT  81.527 62.406 81.995 62.424 ;
     RECT  81.491 69.336 81.995 69.858 ;
     RECT  81.491 70.884 81.995 71.406 ;
     RECT  81.895 72.306 81.995 72.324 ;
     RECT  81.923 73.314 81.995 73.332 ;
     RECT  81.895 74.826 81.995 75.456 ;
     RECT  81.491 76.446 81.995 76.464 ;
     RECT  81.527 78.786 81.995 78.804 ;
     RECT  81.347 46.386 82.067 46.404 ;
     RECT  81.995 49.401 82.067 49.419 ;
     RECT  81.283 51.291 82.067 51.309 ;
     RECT  81.995 55.341 82.067 55.359 ;
    LAYER M3 ;
     RECT  2.88 0.091 3.654 0.139 ;
     RECT  19.116 0.091 19.134 0.139 ;
     RECT  39.456 0.091 39.474 0.139 ;
     RECT  41.76 0.091 42.282 0.139 ;
     RECT  44.244 0.091 44.262 0.139 ;
     RECT  19.116 0.139 19.278 0.187 ;
     RECT  25.704 0.091 25.722 0.187 ;
     RECT  37.62 0.091 37.638 0.187 ;
     RECT  41.76 0.139 42.714 0.187 ;
     RECT  50.832 0.091 50.85 0.187 ;
     RECT  48.456 0.091 49.734 0.221 ;
     RECT  2.88 0.139 3.834 0.235 ;
     RECT  4.572 0.091 4.59 0.235 ;
     RECT  41.4 0.187 42.858 0.235 ;
     RECT  50.832 0.187 50.922 0.235 ;
     RECT  53.532 0.091 53.55 0.235 ;
     RECT  2.88 0.235 4.59 0.269 ;
     RECT  19.116 0.187 19.35 0.269 ;
     RECT  3.06 0.269 4.59 0.317 ;
     RECT  19.26 0.269 19.35 0.317 ;
     RECT  30.492 0.091 32.022 0.317 ;
     RECT  34.776 0.091 35.19 0.317 ;
     RECT  3.816 0.317 4.59 0.365 ;
     RECT  19.332 0.317 19.35 0.365 ;
     RECT  50.724 0.235 50.922 0.365 ;
     RECT  51.732 0.283 51.75 0.379 ;
     RECT  51.552 0.379 51.75 0.413 ;
     RECT  15.408 0.091 15.426 0.427 ;
     RECT  3.888 0.365 4.59 0.461 ;
     RECT  52.74 0.235 53.55 0.475 ;
     RECT  28.584 0.091 28.602 0.523 ;
     RECT  10.296 0.091 10.314 0.571 ;
     RECT  15.408 0.427 15.75 0.605 ;
     RECT  25.704 0.187 25.758 1.147 ;
     RECT  4.572 0.461 4.59 1.723 ;
     RECT  9.216 0.091 9.234 1.723 ;
     RECT  10.296 0.571 10.854 1.723 ;
     RECT  11.592 0.091 12.006 1.723 ;
     RECT  13.752 0.091 13.77 1.723 ;
     RECT  15.408 0.605 15.426 1.723 ;
     RECT  22.896 0.091 23.814 1.723 ;
     RECT  24.696 0.091 24.714 1.723 ;
     RECT  28.584 0.523 28.638 1.723 ;
     RECT  30.492 0.317 30.51 1.723 ;
     RECT  31.356 0.317 32.022 1.723 ;
     RECT  33.12 0.091 33.138 1.723 ;
     RECT  33.876 0.091 33.894 1.723 ;
     RECT  34.776 0.317 34.794 1.723 ;
     RECT  36.216 0.091 36.702 1.723 ;
     RECT  37.62 0.187 37.71 1.723 ;
     RECT  38.952 0.139 39.474 1.723 ;
     RECT  41.256 0.235 42.858 1.723 ;
     RECT  45.072 0.187 45.09 1.723 ;
     RECT  48.456 0.221 49.626 1.723 ;
     RECT  51.552 0.413 51.642 1.723 ;
     RECT  52.74 0.475 53.946 1.723 ;
     RECT  45.072 1.723 45.522 1.771 ;
     RECT  46.296 0.091 46.314 1.771 ;
     RECT  21.996 1.723 24.714 1.819 ;
     RECT  27.504 1.723 29.358 1.867 ;
     RECT  30.492 1.723 33.138 1.867 ;
     RECT  45.072 1.771 46.314 1.867 ;
     RECT  56.34 1.867 56.358 1.915 ;
     RECT  13.752 1.723 15.426 1.963 ;
     RECT  16.92 1.723 16.938 1.963 ;
     RECT  17.712 0.091 17.73 1.963 ;
     RECT  47.772 1.723 49.626 1.963 ;
     RECT  50.724 0.365 50.742 1.963 ;
     RECT  2.772 1.723 2.79 2.011 ;
     RECT  6.372 1.723 7.65 2.011 ;
     RECT  18.936 1.963 18.954 2.011 ;
     RECT  58.788 1.771 58.806 2.011 ;
     RECT  21.96 1.819 24.714 2.029 ;
     RECT  2.772 2.011 2.826 2.059 ;
     RECT  16.92 1.963 17.73 2.059 ;
     RECT  21.96 2.029 24.75 2.059 ;
     RECT  25.632 1.147 25.758 2.059 ;
     RECT  36.144 1.723 37.71 2.059 ;
     RECT  51.552 1.723 54.378 2.059 ;
     RECT  55.332 1.963 55.35 2.059 ;
     RECT  57.636 2.011 58.806 2.059 ;
     RECT  21.888 2.059 24.75 2.101 ;
     RECT  25.632 2.059 26.298 2.101 ;
     RECT  45.072 1.867 46.782 2.101 ;
     RECT  57.636 2.059 59.058 2.101 ;
     RECT  4.572 1.723 5.49 2.107 ;
     RECT  6.372 2.011 7.974 2.107 ;
     RECT  18.756 2.011 18.954 2.107 ;
     RECT  19.8 1.723 19.818 2.107 ;
     RECT  51.552 2.059 55.35 2.107 ;
     RECT  56.34 1.915 56.862 2.107 ;
     RECT  2.592 2.059 3.15 2.143 ;
     RECT  18.756 2.107 19.818 2.143 ;
     RECT  47.772 1.963 50.742 2.143 ;
     RECT  51.552 2.107 56.862 2.143 ;
     RECT  66.924 2.107 66.942 2.143 ;
     RECT  2.415 2.143 3.15 2.155 ;
     RECT  21.888 2.101 26.298 2.155 ;
     RECT  36.144 2.059 38.034 2.155 ;
     RECT  38.952 1.723 42.858 2.155 ;
     RECT  66.924 2.143 67.305 2.155 ;
     RECT  2.415 2.155 3.618 2.191 ;
     RECT  4.572 2.107 7.974 2.191 ;
     RECT  8.784 1.723 12.006 2.191 ;
     RECT  16.272 2.059 17.73 2.191 ;
     RECT  18.615 2.143 19.818 2.191 ;
     RECT  45.072 2.101 46.818 2.191 ;
     RECT  47.772 2.143 56.862 2.191 ;
     RECT  57.636 2.101 59.706 2.191 ;
     RECT  61.815 2.143 61.905 2.191 ;
     RECT  62.712 1.963 62.73 2.191 ;
     RECT  64.836 2.011 64.854 2.191 ;
     RECT  66.924 2.155 68.274 2.191 ;
     RECT  69.048 2.155 69.066 2.191 ;
     RECT  64.836 2.191 64.962 2.203 ;
     RECT  2.415 2.191 12.186 2.227 ;
     RECT  71.64 2.191 71.658 2.227 ;
     RECT  16.272 2.191 19.818 2.251 ;
     RECT  20.952 1.723 20.97 2.251 ;
     RECT  36.144 2.155 42.858 2.251 ;
     RECT  43.884 0.139 44.262 2.251 ;
     RECT  70.668 2.227 70.686 2.251 ;
     RECT  71.532 2.227 71.658 2.251 ;
     RECT  66.456 2.191 69.066 2.255 ;
     RECT  16.164 2.251 19.818 2.263 ;
     RECT  62.64 2.191 63.342 2.263 ;
     RECT  64.836 2.203 65.394 2.263 ;
     RECT  70.668 2.251 71.658 2.263 ;
     RECT  72.615 2.143 72.705 2.263 ;
     RECT  2.16 2.227 12.186 2.299 ;
     RECT  13.068 1.963 15.426 2.299 ;
     RECT  16.164 2.263 19.854 2.299 ;
     RECT  20.7 2.251 20.97 2.299 ;
     RECT  21.708 2.155 26.298 2.299 ;
     RECT  27.504 1.867 33.138 2.299 ;
     RECT  33.876 1.723 35.262 2.299 ;
     RECT  36.144 2.251 44.262 2.299 ;
     RECT  45.072 2.191 59.706 2.299 ;
     RECT  61.56 2.191 61.905 2.299 ;
     RECT  60.444 2.227 60.462 2.335 ;
     RECT  62.64 2.263 63.522 2.335 ;
     RECT  70.668 2.263 72.705 2.335 ;
     RECT  60.444 2.335 60.642 2.371 ;
     RECT  61.524 2.299 61.905 2.371 ;
     RECT  62.64 2.335 63.558 2.371 ;
     RECT  64.692 2.263 65.394 2.371 ;
     RECT  66.456 2.255 68.418 2.371 ;
     RECT  69.156 2.263 69.174 2.371 ;
     RECT  70.344 2.335 72.705 2.371 ;
     RECT  2.16 2.299 59.706 2.381 ;
     RECT  60.444 2.371 61.905 2.413 ;
     RECT  62.64 2.371 65.394 2.413 ;
     RECT  69.156 2.371 72.774 2.413 ;
     RECT  78.015 2.143 78.105 2.413 ;
     RECT  60.444 2.413 65.394 2.461 ;
     RECT  66.24 2.371 68.418 2.461 ;
     RECT  69.156 2.413 72.897 2.461 ;
     RECT  2.268 2.381 59.706 2.491 ;
     RECT  60.444 2.461 68.418 2.491 ;
     RECT  69.156 2.461 73.098 2.767 ;
     RECT  73.872 2.641 73.89 2.767 ;
     RECT  2.268 2.491 68.418 2.795 ;
     RECT  64.476 2.795 68.418 3.001 ;
     RECT  69.156 2.767 73.89 3.001 ;
     RECT  64.476 3.001 73.89 3.307 ;
     RECT  2.268 2.795 63.702 3.451 ;
     RECT  2.232 3.451 63.702 3.875 ;
     RECT  2.268 3.875 63.702 4.225 ;
     RECT  64.476 3.307 74.394 4.225 ;
     RECT  2.268 4.225 74.394 4.253 ;
     RECT  65.844 4.253 74.394 4.261 ;
     RECT  65.844 4.261 74.79 4.495 ;
     RECT  65.844 4.495 75.69 4.765 ;
     RECT  79.308 4.621 79.326 4.765 ;
     RECT  65.844 4.765 75.762 4.801 ;
     RECT  76.752 4.651 76.77 4.801 ;
     RECT  78.015 2.413 78.297 4.801 ;
     RECT  65.844 4.801 75.906 4.891 ;
     RECT  76.68 4.801 76.77 4.891 ;
     RECT  77.652 4.801 78.297 4.963 ;
     RECT  79.308 4.765 79.542 4.963 ;
     RECT  65.844 4.891 76.77 5.027 ;
     RECT  68.76 5.027 76.77 5.071 ;
     RECT  77.652 4.963 79.542 5.071 ;
     RECT  2.268 4.253 65.106 5.161 ;
     RECT  65.844 5.027 68.022 5.161 ;
     RECT  2.268 5.161 68.022 5.341 ;
     RECT  68.76 5.071 76.806 5.341 ;
     RECT  77.652 5.071 79.83 5.341 ;
     RECT  81.108 5.431 81.126 5.611 ;
     RECT  81.072 5.611 81.126 5.881 ;
     RECT  2.232 5.341 68.022 6.029 ;
     RECT  2.268 6.029 68.022 6.151 ;
     RECT  68.76 5.341 79.83 6.151 ;
     RECT  81 5.881 81.126 6.151 ;
     RECT  80.964 6.151 81.126 6.691 ;
     RECT  80.964 6.691 81.162 6.781 ;
     RECT  80.64 6.781 81.162 6.817 ;
     RECT  2.268 6.151 79.83 7.357 ;
     RECT  2.052 7.357 79.83 7.469 ;
     RECT  80.64 6.817 81.198 7.949 ;
     RECT  80.64 7.949 80.946 8.045 ;
     RECT  2.232 7.469 79.722 8.779 ;
     RECT  2.196 8.779 79.722 8.815 ;
     RECT  81.9 8.827 81.918 9.101 ;
     RECT  80.856 8.045 80.946 9.239 ;
     RECT  2.196 8.815 79.794 9.259 ;
     RECT  80.856 9.239 80.91 9.259 ;
     RECT  2.196 9.259 80.91 9.509 ;
     RECT  81.972 9.643 81.99 9.779 ;
     RECT  2.196 9.509 80.37 10.859 ;
     RECT  2.196 10.859 79.722 11.821 ;
     RECT  81.504 11.641 81.522 12.523 ;
     RECT  2.196 11.821 79.794 12.557 ;
     RECT  80.964 12.523 81.522 12.715 ;
     RECT  80.964 12.715 81.99 13.037 ;
     RECT  2.268 12.557 79.794 13.229 ;
     RECT  80.964 13.037 81.522 13.579 ;
     RECT  2.268 13.229 79.722 13.595 ;
     RECT  2.268 13.595 79.686 13.711 ;
     RECT  80.928 13.579 81.522 13.867 ;
     RECT  80.928 13.867 81.774 13.997 ;
     RECT  80.928 13.997 81.522 14.341 ;
     RECT  2.196 13.711 79.686 14.827 ;
     RECT  80.892 14.341 81.522 14.827 ;
     RECT  2.196 14.827 79.722 14.945 ;
     RECT  2.304 14.945 79.722 15.215 ;
     RECT  80.892 14.827 81.99 15.251 ;
     RECT  80.892 15.251 80.91 15.287 ;
     RECT  81.792 15.251 81.99 15.629 ;
     RECT  80.712 15.787 80.874 15.899 ;
     RECT  2.34 15.215 79.722 15.979 ;
     RECT  80.856 15.899 80.874 16.075 ;
     RECT  81.936 15.629 81.99 16.367 ;
     RECT  80.856 16.075 80.946 16.411 ;
     RECT  81.936 16.367 81.954 16.411 ;
     RECT  2.304 15.979 79.722 16.459 ;
     RECT  80.856 16.411 81.954 16.589 ;
     RECT  2.304 16.459 80.082 16.891 ;
     RECT  2.268 16.891 80.082 16.939 ;
     RECT  80.856 16.589 80.946 16.939 ;
     RECT  81.9 16.589 81.954 17.069 ;
     RECT  81.936 17.069 81.954 17.227 ;
     RECT  2.268 16.939 80.946 17.693 ;
     RECT  81.936 17.227 81.99 17.899 ;
     RECT  2.34 17.693 80.946 18.221 ;
     RECT  50.256 18.221 80.946 18.283 ;
     RECT  81.792 17.899 81.99 18.283 ;
     RECT  2.34 18.221 49.374 18.475 ;
     RECT  50.256 18.283 81.99 18.959 ;
     RECT  2.268 18.475 49.374 19.003 ;
     RECT  50.256 18.959 81.918 19.003 ;
     RECT  2.268 19.003 81.918 19.133 ;
     RECT  2.268 19.133 81.306 19.409 ;
     RECT  2.304 19.409 81.306 20.299 ;
     RECT  2.268 20.299 81.306 20.489 ;
     RECT  69.912 20.489 81.306 20.993 ;
     RECT  69.912 20.993 80.082 21.119 ;
     RECT  2.268 20.489 69.174 21.211 ;
     RECT  69.912 21.119 79.722 21.211 ;
     RECT  2.268 21.211 79.722 22.073 ;
     RECT  31.14 22.073 79.722 22.219 ;
     RECT  81.216 20.993 81.306 22.469 ;
     RECT  31.14 22.219 79.794 22.739 ;
     RECT  2.268 22.073 30.402 22.795 ;
     RECT  31.14 22.739 79.722 22.795 ;
     RECT  2.268 22.795 79.722 24.077 ;
     RECT  2.376 24.077 79.722 24.475 ;
     RECT  2.376 24.475 79.794 24.509 ;
     RECT  81.216 22.469 81.234 24.629 ;
     RECT  2.376 24.509 79.722 25.591 ;
     RECT  2.376 25.591 79.794 25.861 ;
     RECT  81.468 25.051 81.486 26.093 ;
     RECT  81.828 26.443 81.918 26.621 ;
     RECT  2.34 25.861 79.794 26.669 ;
     RECT  81.828 26.621 81.846 26.717 ;
     RECT  80.928 26.155 80.946 26.789 ;
     RECT  2.34 26.669 79.686 26.797 ;
     RECT  2.304 26.797 79.686 26.861 ;
     RECT  80.964 27.019 80.982 27.203 ;
     RECT  2.34 26.861 79.686 27.499 ;
     RECT  81.9 27.403 81.918 27.917 ;
     RECT  80.64 27.787 80.658 27.979 ;
     RECT  80.64 27.979 80.946 28.171 ;
     RECT  2.34 27.499 79.794 28.751 ;
     RECT  80.64 28.171 81.486 28.843 ;
     RECT  2.34 28.751 79.614 29.021 ;
     RECT  2.34 29.021 51.297 29.335 ;
     RECT  2.304 29.335 51.297 29.399 ;
     RECT  52.02 29.021 79.614 29.605 ;
     RECT  80.352 28.843 81.486 29.605 ;
     RECT  21.06 29.399 51.297 29.911 ;
     RECT  52.02 29.605 81.486 29.911 ;
     RECT  21.06 29.911 81.486 30.299 ;
     RECT  2.304 29.399 20.322 30.451 ;
     RECT  21.06 30.299 79.794 30.451 ;
     RECT  80.64 30.299 81.486 31.019 ;
     RECT  80.64 31.019 81.234 31.649 ;
     RECT  81.216 31.649 81.234 32.639 ;
     RECT  2.304 30.451 79.794 32.873 ;
     RECT  2.415 32.873 79.794 33.305 ;
     RECT  2.415 33.305 9.234 33.539 ;
     RECT  4.14 33.539 9.234 33.845 ;
     RECT  6.336 33.845 9.234 34.051 ;
     RECT  10.08 33.305 79.794 34.051 ;
     RECT  4.14 33.845 5.526 34.771 ;
     RECT  6.336 34.051 79.794 34.771 ;
     RECT  2.415 33.539 3.294 35.323 ;
     RECT  4.14 34.771 79.794 35.323 ;
     RECT  2.415 35.323 79.794 35.735 ;
     RECT  4.104 35.735 79.794 35.879 ;
     RECT  32.904 35.879 79.794 35.969 ;
     RECT  34.272 35.969 79.794 36.347 ;
     RECT  4.104 35.879 32.13 36.619 ;
     RECT  32.904 35.969 33.534 36.619 ;
     RECT  2.415 35.735 3.294 36.625 ;
     RECT  4.104 36.619 33.534 36.625 ;
     RECT  2.415 36.625 33.534 36.751 ;
     RECT  34.272 36.347 36.27 36.751 ;
     RECT  37.008 36.347 79.794 37.121 ;
     RECT  2.415 36.751 36.27 37.193 ;
     RECT  34.092 37.193 36.27 37.435 ;
     RECT  37.008 37.121 39.042 37.435 ;
     RECT  39.888 37.121 79.794 37.471 ;
     RECT  80.64 36.481 80.658 37.471 ;
     RECT  2.415 37.193 33.246 37.757 ;
     RECT  39.888 37.471 80.658 37.903 ;
     RECT  4.14 37.757 33.246 38.011 ;
     RECT  34.092 37.435 39.042 38.011 ;
     RECT  4.14 38.011 39.042 38.165 ;
     RECT  39.888 37.903 80.982 38.173 ;
     RECT  34.092 38.165 39.042 38.209 ;
     RECT  39.888 38.173 81.054 38.209 ;
     RECT  4.14 38.165 33.354 38.911 ;
     RECT  34.092 38.209 81.054 38.911 ;
     RECT  2.415 37.757 3.294 38.983 ;
     RECT  4.14 38.911 81.054 38.983 ;
     RECT  2.415 38.983 81.054 39.011 ;
     RECT  2.415 39.011 32.346 39.209 ;
     RECT  2.415 39.209 32.166 39.245 ;
     RECT  2.415 39.245 32.13 39.515 ;
     RECT  33.192 39.011 81.054 39.631 ;
     RECT  33.192 39.631 81.45 39.793 ;
     RECT  33.192 39.793 81.486 39.917 ;
     RECT  33.192 39.917 81.45 40.027 ;
     RECT  4.104 39.515 32.13 40.205 ;
     RECT  33.048 40.027 81.45 40.205 ;
     RECT  33.048 40.205 81.27 40.301 ;
     RECT  4.536 40.205 32.13 40.333 ;
     RECT  33.048 40.301 79.722 40.459 ;
     RECT  4.536 40.333 32.202 40.865 ;
     RECT  5.112 40.865 32.202 41.107 ;
     RECT  33.012 40.459 79.722 41.107 ;
     RECT  5.112 41.107 79.722 41.251 ;
     RECT  80.64 40.301 81.27 41.515 ;
     RECT  80.64 41.515 81.486 41.707 ;
     RECT  5.112 41.251 79.794 41.899 ;
     RECT  80.64 41.707 81.918 41.899 ;
     RECT  5.112 41.899 81.918 41.981 ;
     RECT  5.112 41.981 81.27 42.061 ;
     RECT  4.896 42.061 81.27 42.089 ;
     RECT  32.868 42.089 81.27 42.727 ;
     RECT  32.868 42.727 81.306 43.169 ;
     RECT  4.896 42.089 32.058 43.231 ;
     RECT  32.868 43.169 79.794 43.231 ;
     RECT  4.896 43.231 79.794 43.609 ;
     RECT  4.752 43.609 79.794 43.799 ;
     RECT  4.86 43.799 79.794 44.477 ;
     RECT  4.86 44.477 79.722 44.789 ;
     RECT  30.672 44.789 79.722 45.149 ;
     RECT  4.86 44.789 29.826 45.535 ;
     RECT  4.86 45.535 29.898 45.661 ;
     RECT  30.672 45.149 79.65 45.661 ;
     RECT  4.86 45.661 79.65 46.075 ;
     RECT  4.86 46.075 79.794 46.111 ;
     RECT  4.428 46.111 79.794 46.741 ;
     RECT  80.64 43.169 81.306 47.083 ;
     RECT  82.044 46.381 82.062 47.083 ;
     RECT  4.32 46.741 79.794 47.191 ;
     RECT  4.284 47.191 79.794 47.213 ;
     RECT  2.415 39.515 3.294 47.461 ;
     RECT  2.415 47.461 3.546 47.731 ;
     RECT  4.284 47.213 33.858 47.731 ;
     RECT  2.415 47.731 33.858 48.001 ;
     RECT  34.632 47.213 79.794 48.001 ;
     RECT  2.415 48.001 79.794 49.147 ;
     RECT  80.64 47.083 82.062 49.147 ;
     RECT  2.415 49.147 82.062 49.325 ;
     RECT  80.64 49.325 82.062 49.424 ;
     RECT  80.64 49.424 81.486 50.189 ;
     RECT  2.415 49.325 79.794 50.701 ;
     RECT  80.64 50.189 81.342 50.701 ;
     RECT  2.415 50.701 81.342 51.101 ;
     RECT  2.415 51.101 54.774 51.245 ;
     RECT  18.615 51.245 54.774 51.269 ;
     RECT  55.548 51.101 81.342 51.286 ;
     RECT  55.548 51.286 82.062 51.359 ;
     RECT  55.584 51.359 82.062 51.395 ;
     RECT  18.615 51.269 54.522 52.157 ;
     RECT  55.764 51.395 82.062 52.267 ;
     RECT  2.415 51.245 17.838 52.285 ;
     RECT  2.415 52.285 17.874 52.411 ;
     RECT  18.615 52.157 54.414 52.411 ;
     RECT  2.415 52.411 54.414 52.987 ;
     RECT  55.296 52.267 82.062 52.987 ;
     RECT  2.415 52.987 82.062 55.255 ;
     RECT  2.34 55.255 82.062 55.364 ;
     RECT  2.34 55.364 81.99 55.373 ;
     RECT  2.34 55.373 81.954 59.213 ;
     RECT  2.34 59.213 81.522 60.583 ;
     RECT  2.34 60.583 81.954 60.907 ;
     RECT  2.34 60.907 81.99 61.529 ;
     RECT  2.415 61.529 81.99 62.429 ;
     RECT  2.415 62.429 81.918 62.957 ;
     RECT  2.415 62.957 81.522 63.821 ;
     RECT  27.36 63.821 81.522 64.201 ;
     RECT  2.415 63.821 26.514 64.699 ;
     RECT  27.36 64.201 81.594 64.699 ;
     RECT  2.415 64.699 81.594 64.895 ;
     RECT  2.415 64.895 27.45 65.821 ;
     RECT  28.188 64.895 81.594 65.821 ;
     RECT  2.415 65.821 81.594 66.209 ;
     RECT  2.415 66.209 80.694 66.461 ;
     RECT  80.676 66.461 80.694 66.893 ;
     RECT  2.415 66.461 79.938 67.277 ;
     RECT  2.415 67.277 79.794 67.289 ;
     RECT  81.432 66.209 81.594 67.711 ;
     RECT  80.928 67.711 81.594 67.819 ;
     RECT  2.415 67.289 79.722 68.009 ;
     RECT  80.928 67.819 81.81 68.011 ;
     RECT  80.928 68.011 81.954 68.135 ;
     RECT  80.928 68.135 81.918 68.333 ;
     RECT  2.415 68.009 11.25 68.791 ;
     RECT  11.988 68.009 79.722 68.791 ;
     RECT  80.928 68.333 81.882 69.067 ;
     RECT  80.892 69.067 81.882 69.307 ;
     RECT  2.415 68.791 79.758 69.331 ;
     RECT  80.892 69.307 81.918 69.331 ;
     RECT  80.892 69.331 81.99 69.449 ;
     RECT  80.928 69.449 81.99 69.719 ;
     RECT  2.415 69.331 79.794 69.863 ;
     RECT  81 69.719 81.99 69.869 ;
     RECT  66.06 69.863 79.794 70.109 ;
     RECT  66.06 70.109 79.722 70.295 ;
     RECT  81 69.869 81.918 70.501 ;
     RECT  2.415 69.863 65.178 70.609 ;
     RECT  66.06 70.295 71.226 70.609 ;
     RECT  80.964 70.501 81.918 70.879 ;
     RECT  72 70.295 79.722 70.951 ;
     RECT  2.415 70.609 71.226 71.275 ;
     RECT  72 70.951 79.794 71.275 ;
     RECT  80.964 70.879 81.99 71.311 ;
     RECT  80.928 71.311 81.99 71.411 ;
     RECT  80.928 71.411 81.918 71.563 ;
     RECT  2.415 71.275 79.794 71.681 ;
     RECT  80.712 71.563 81.918 71.789 ;
     RECT  3.6 71.681 79.794 71.987 ;
     RECT  4.644 71.987 79.794 72.077 ;
     RECT  4.644 72.077 79.578 72.149 ;
     RECT  80.928 71.789 81.918 72.185 ;
     RECT  80.964 72.185 81.918 72.301 ;
     RECT  80.964 72.301 81.99 72.365 ;
     RECT  3.6 71.987 3.618 72.491 ;
     RECT  15.912 72.149 79.578 72.841 ;
     RECT  15.912 72.841 79.65 72.893 ;
     RECT  80.964 72.365 81.81 72.907 ;
     RECT  80.712 72.907 81.81 73.243 ;
     RECT  80.712 73.243 81.918 73.309 ;
     RECT  80.712 73.309 81.99 73.409 ;
     RECT  80.928 73.409 81.99 73.517 ;
     RECT  4.644 72.149 15.138 73.531 ;
     RECT  15.912 72.893 79.578 73.531 ;
     RECT  4.644 73.531 79.578 73.771 ;
     RECT  4.14 73.771 79.578 73.921 ;
     RECT  80.928 73.517 81.918 73.949 ;
     RECT  80.928 73.949 81.846 74.045 ;
     RECT  4.14 73.921 79.722 74.075 ;
     RECT  4.176 74.075 79.722 74.083 ;
     RECT  4.176 74.083 79.758 74.107 ;
     RECT  4.176 74.107 79.794 74.309 ;
     RECT  4.176 74.309 79.758 74.381 ;
     RECT  4.176 74.381 79.722 74.579 ;
     RECT  80.928 74.045 81.666 74.779 ;
     RECT  80.928 74.779 81.918 74.821 ;
     RECT  4.356 74.579 79.722 74.849 ;
     RECT  80.928 74.821 81.99 74.849 ;
     RECT  4.824 74.849 79.722 75.005 ;
     RECT  68.976 75.005 79.722 75.119 ;
     RECT  69.012 75.119 79.722 75.307 ;
     RECT  4.824 75.005 68.238 75.703 ;
     RECT  4.716 75.703 68.238 75.775 ;
     RECT  4.572 75.775 68.238 75.811 ;
     RECT  80.964 74.849 81.99 75.917 ;
     RECT  4.572 75.811 68.274 76.045 ;
     RECT  69.012 75.307 79.794 76.045 ;
     RECT  4.572 76.045 79.794 76.073 ;
     RECT  4.716 76.073 79.794 76.363 ;
     RECT  81.756 75.917 81.99 76.469 ;
     RECT  4.716 76.363 79.902 76.493 ;
     RECT  4.716 76.493 79.866 76.541 ;
     RECT  81.756 76.469 81.846 76.685 ;
     RECT  4.788 76.541 79.866 76.925 ;
     RECT  80.964 75.917 80.982 77.161 ;
     RECT  4.824 76.925 79.866 77.501 ;
     RECT  80.964 77.161 81.486 77.515 ;
     RECT  80.712 77.515 81.486 77.933 ;
     RECT  80.712 77.933 80.982 77.999 ;
     RECT  80.928 77.999 80.982 78.029 ;
     RECT  4.824 77.501 79.794 78.241 ;
     RECT  4.608 78.241 79.794 78.475 ;
     RECT  4.464 78.475 79.794 78.509 ;
     RECT  4.608 78.509 79.794 78.665 ;
     RECT  81.9 78.187 81.99 78.809 ;
     RECT  80.964 78.029 80.982 78.859 ;
     RECT  4.716 78.665 79.794 78.899 ;
     RECT  4.716 78.899 79.722 78.935 ;
     RECT  80.928 78.859 80.982 79.051 ;
     RECT  81.9 78.809 81.918 79.051 ;
     RECT  80.928 79.051 81.918 79.169 ;
     RECT  4.788 78.935 79.722 79.205 ;
     RECT  4.824 79.205 79.722 79.475 ;
     RECT  4.824 79.475 75.654 79.517 ;
     RECT  80.964 79.169 81.918 79.517 ;
     RECT  70.164 79.517 75.654 79.565 ;
     RECT  70.164 79.565 74.574 79.619 ;
     RECT  76.428 79.475 79.722 79.619 ;
     RECT  76.5 79.619 79.722 79.636 ;
     RECT  2.415 71.681 2.697 79.667 ;
     RECT  71.82 79.619 74.574 79.667 ;
     RECT  4.824 79.517 69.39 79.709 ;
     RECT  70.164 79.619 70.47 79.709 ;
     RECT  71.82 79.667 72.738 79.709 ;
     RECT  73.548 79.667 74.574 79.709 ;
     RECT  75.348 79.565 75.654 79.709 ;
     RECT  5.148 79.709 5.454 79.745 ;
     RECT  6.48 79.709 66.258 79.745 ;
     RECT  66.996 79.709 67.554 79.745 ;
     RECT  68.544 79.709 69.21 79.745 ;
     RECT  71.82 79.709 72.705 79.745 ;
     RECT  73.62 79.709 74.43 79.745 ;
     RECT  76.5 79.636 79.974 79.745 ;
     RECT  13.14 79.745 27.378 79.757 ;
     RECT  67.215 79.745 67.554 79.757 ;
     RECT  74.412 79.745 74.43 79.757 ;
     RECT  75.492 79.709 75.51 79.757 ;
     RECT  76.68 79.745 76.698 79.757 ;
     RECT  6.48 79.745 6.498 79.781 ;
     RECT  28.224 79.745 66.258 79.781 ;
     RECT  68.544 79.745 68.562 79.781 ;
     RECT  71.82 79.745 71.838 79.781 ;
     RECT  7.815 79.745 11.502 79.805 ;
     RECT  14.508 79.757 27.378 79.805 ;
     RECT  31.716 79.781 33.606 79.805 ;
     RECT  34.38 79.781 48.114 79.805 ;
     RECT  48.888 79.781 66.258 79.805 ;
     RECT  77.868 79.745 78.246 79.805 ;
     RECT  79.956 79.745 79.974 79.805 ;
     RECT  28.224 79.781 30.33 79.817 ;
     RECT  9.936 79.805 10.17 79.853 ;
     RECT  14.832 79.805 27.378 79.853 ;
     RECT  28.224 79.817 29.505 79.853 ;
     RECT  31.716 79.805 32.454 79.853 ;
     RECT  34.38 79.805 36.666 79.853 ;
     RECT  37.62 79.805 38.43 79.853 ;
     RECT  39.708 79.805 42.858 79.853 ;
     RECT  43.884 79.805 47.826 79.853 ;
     RECT  48.888 79.805 49.878 79.853 ;
     RECT  50.76 79.805 51.462 79.853 ;
     RECT  60.66 79.805 62.154 79.853 ;
     RECT  77.868 79.805 78.105 79.853 ;
     RECT  13.14 79.757 13.305 79.889 ;
     RECT  14.832 79.853 19.386 79.889 ;
     RECT  28.512 79.853 29.505 79.889 ;
     RECT  31.716 79.853 32.31 79.889 ;
     RECT  34.74 79.853 36.666 79.889 ;
     RECT  20.34 79.853 23.202 79.901 ;
     RECT  54.72 79.805 58.914 79.901 ;
     RECT  2.415 79.667 2.505 79.937 ;
     RECT  7.815 79.805 9.162 79.937 ;
     RECT  13.215 79.889 13.305 79.937 ;
     RECT  24.015 79.853 27.378 79.937 ;
     RECT  29.415 79.889 29.505 79.937 ;
     RECT  54.72 79.901 57.222 79.937 ;
     RECT  67.215 79.757 67.305 79.937 ;
     RECT  72.615 79.745 72.705 79.937 ;
     RECT  78.015 79.853 78.105 79.937 ;
     RECT  39.744 79.853 42.858 79.949 ;
     RECT  16.884 79.889 19.17 79.979 ;
     RECT  40.104 79.949 42.858 80.045 ;
     RECT  80.964 79.517 81.522 80.045 ;
     RECT  21.096 79.901 23.202 80.051 ;
     RECT  24.516 79.937 27.378 80.051 ;
     RECT  34.776 79.889 36.666 80.093 ;
     RECT  40.104 80.045 40.194 80.093 ;
     RECT  61.74 79.853 62.154 80.093 ;
     RECT  18.756 79.979 19.17 80.141 ;
     RECT  40.176 80.093 40.194 80.141 ;
     RECT  43.884 79.853 47.25 80.189 ;
     RECT  50.76 79.853 51.354 80.189 ;
     RECT  81.504 80.045 81.522 80.237 ;
     RECT  20.34 79.901 20.358 80.285 ;
     RECT  56.556 79.937 57.222 80.285 ;
     RECT  8.496 79.937 9.162 80.381 ;
     RECT  16.884 79.979 17.874 80.381 ;
     RECT  41.04 80.045 42.858 80.381 ;
     RECT  46.188 80.189 47.25 80.381 ;
     RECT  53.712 79.805 53.946 80.381 ;
     RECT  56.556 80.285 57.186 80.381 ;
     RECT  57.96 79.901 58.914 80.381 ;
     RECT  60.66 79.853 60.678 80.381 ;
     RECT  61.74 80.093 62.046 80.381 ;
     RECT  48.96 79.853 48.978 80.909 ;
     RECT  57.96 80.381 58.662 80.957 ;
     RECT  19.152 80.141 19.17 81.499 ;
     RECT  8.568 80.381 9.162 81.533 ;
     RECT  14.832 79.889 16.038 81.533 ;
     RECT  24.516 80.051 25.146 81.533 ;
     RECT  35.352 80.093 36.666 81.533 ;
     RECT  41.04 80.381 41.058 81.533 ;
     RECT  43.884 80.189 45.054 81.533 ;
     RECT  15.48 81.533 16.038 81.581 ;
     RECT  45.036 81.533 45.054 81.581 ;
     RECT  37.62 79.853 38.25 81.629 ;
     RECT  19.152 81.499 19.53 81.677 ;
     RECT  21.78 80.051 23.202 81.691 ;
     RECT  37.692 81.629 38.25 81.725 ;
     RECT  35.568 81.533 36.666 81.739 ;
     RECT  40.932 81.691 40.95 81.739 ;
     RECT  59.688 81.691 59.706 81.739 ;
     RECT  35.568 81.739 36.882 81.773 ;
     RECT  35.964 81.773 36.882 81.787 ;
     RECT  40.86 81.739 40.95 81.787 ;
     RECT  59.688 81.739 59.778 81.787 ;
     RECT  64.872 81.643 64.89 81.787 ;
     RECT  21.744 81.691 23.202 81.821 ;
     RECT  35.964 81.787 36.954 81.821 ;
     RECT  52.524 79.805 52.542 81.835 ;
     RECT  58.212 80.957 58.23 81.835 ;
     RECT  15.984 81.581 16.038 81.869 ;
     RECT  31.716 79.889 32.022 81.869 ;
     RECT  40.716 81.787 40.95 81.869 ;
     RECT  26.28 80.051 27.378 81.883 ;
     RECT  31.716 81.869 31.734 81.917 ;
     RECT  36.432 81.821 36.954 81.917 ;
     RECT  40.716 81.869 40.878 81.917 ;
     RECT  59.544 81.787 59.778 81.917 ;
     RECT  63.432 81.739 63.45 81.917 ;
     RECT  64.728 81.787 64.89 81.917 ;
     RECT  8.568 81.533 8.586 81.965 ;
     RECT  10.152 79.853 10.17 81.965 ;
     RECT  11.484 79.805 11.502 81.965 ;
     RECT  15.984 81.869 16.002 81.965 ;
     RECT  17.136 80.381 17.874 81.965 ;
     RECT  21.78 81.821 23.202 81.965 ;
     RECT  26.28 81.883 27.414 81.965 ;
     RECT  30.312 79.817 30.33 81.965 ;
     RECT  36.432 81.917 36.882 81.965 ;
     RECT  37.944 81.725 38.25 81.965 ;
     RECT  40.716 81.917 40.734 81.965 ;
     RECT  46.188 80.381 46.782 81.965 ;
     RECT  50.904 80.189 51.354 81.965 ;
     RECT  52.524 81.835 52.65 81.965 ;
     RECT  54.72 79.937 55.782 81.965 ;
     RECT  56.556 80.381 56.574 81.965 ;
     RECT  58.212 81.835 58.698 81.965 ;
     RECT  59.544 81.917 59.562 81.965 ;
     RECT  64.728 81.917 64.746 81.965 ;
     RECT  66.24 79.805 66.258 81.965 ;
     RECT  19.152 81.677 19.17 82.013 ;
     RECT  22.968 81.965 23.202 82.013 ;
     RECT  27.216 81.965 27.414 82.013 ;
     RECT  36.432 81.965 36.666 82.013 ;
     RECT  43.92 81.533 43.938 82.013 ;
     RECT  21.78 81.965 21.798 82.061 ;
     RECT  27.216 82.013 27.234 82.061 ;
     RECT  36.432 82.013 36.45 82.061 ;
    LAYER M4 ;
     RECT  0.805 7.44 0.901 7.464 ;
     RECT  0.997 2.352 1.093 2.376 ;
     RECT  0.709 3.456 1.093 3.48 ;
     RECT  1.093 2.352 1.141 3.48 ;
     RECT  1.141 2.352 1.189 4.296 ;
     RECT  0.901 6.96 1.237 7.464 ;
     RECT  1.237 6.96 1.285 8.184 ;
     RECT  1.141 10.992 1.285 11.016 ;
     RECT  1.285 6.288 1.381 8.184 ;
     RECT  1.285 10.992 1.477 11.16 ;
     RECT  1.381 6.096 1.525 8.184 ;
     RECT  1.477 21.216 1.525 21.24 ;
     RECT  1.477 10.368 1.573 11.256 ;
     RECT  1.429 14.832 1.573 14.856 ;
     RECT  1.285 23.04 1.621 23.064 ;
     RECT  1.573 9.792 1.669 11.256 ;
     RECT  1.573 14.832 1.669 14.904 ;
     RECT  1.333 13.68 1.717 13.704 ;
     RECT  1.669 14.832 1.717 14.952 ;
     RECT  1.189 2.352 1.765 4.92 ;
     RECT  1.765 2.304 1.813 4.92 ;
     RECT  1.525 20.592 1.813 21.24 ;
     RECT  1.621 22.848 1.813 23.064 ;
     RECT  1.813 2.064 1.861 4.92 ;
     RECT  1.525 6.096 1.861 8.28 ;
     RECT  1.381 15.984 1.861 16.008 ;
     RECT  1.765 17.04 1.861 17.064 ;
     RECT  1.717 13.68 1.957 14.952 ;
     RECT  1.669 9.792 2.005 11.784 ;
     RECT  1.861 2.064 2.053 8.28 ;
     RECT  1.813 20.592 2.053 23.064 ;
     RECT  1.861 15.984 2.101 17.064 ;
     RECT  1.765 27.984 2.149 28.008 ;
     RECT  2.005 9.792 2.185 12.504 ;
     RECT  1.957 13.584 2.197 14.952 ;
     RECT  2.101 15.984 2.197 17.208 ;
     RECT  2.149 27.6 2.245 28.008 ;
     RECT  2.197 13.584 2.257 17.208 ;
     RECT  2.245 19.008 2.257 19.272 ;
     RECT  2.053 20.592 2.257 23.4 ;
     RECT  2.053 2.064 2.293 8.472 ;
     RECT  2.185 9.792 2.293 12.552 ;
     RECT  2.257 13.584 2.293 19.272 ;
     RECT  2.257 20.304 2.293 24.072 ;
     RECT  2.245 26.88 2.293 28.008 ;
     RECT  2.293 0.288 2.341 0.312 ;
     RECT  2.293 2.064 2.365 12.552 ;
     RECT  2.293 13.584 2.365 24.072 ;
     RECT  2.293 30.624 2.365 31.512 ;
     RECT  2.365 2.064 2.408 24.072 ;
     RECT  2.197 25.2 2.408 25.224 ;
     RECT  2.293 26.208 2.408 28.2 ;
     RECT  2.293 29.52 2.408 29.544 ;
     RECT  2.365 30.576 2.408 31.512 ;
     RECT  2.401 32.736 2.408 32.76 ;
     RECT  1.909 36.528 2.408 36.552 ;
     RECT  2.408 2.064 2.437 79.932 ;
     RECT  2.437 1.728 2.512 79.932 ;
     RECT  2.341 0.144 2.629 0.312 ;
     RECT  2.512 1.728 2.704 79.662 ;
     RECT  2.704 1.728 2.801 33.816 ;
     RECT  2.801 2.016 2.837 33.816 ;
     RECT  2.704 49.68 2.837 50.184 ;
     RECT  2.837 2.064 2.867 33.816 ;
     RECT  2.629 0.144 2.869 0.408 ;
     RECT  2.837 49.68 2.915 49.704 ;
     RECT  2.704 36.528 3.125 36.552 ;
     RECT  2.867 2.064 3.251 32.52 ;
     RECT  2.867 33.648 3.269 33.816 ;
     RECT  2.704 58.848 3.449 59.88 ;
     RECT  3.269 33.648 3.683 33.672 ;
     RECT  2.704 55.056 3.697 55.08 ;
     RECT  2.704 52.992 3.781 53.976 ;
     RECT  3.697 55.056 3.781 55.272 ;
     RECT  2.704 60.96 3.805 64.392 ;
     RECT  3.781 52.992 3.827 55.272 ;
     RECT  3.827 53.952 3.845 55.272 ;
     RECT  3.845 54.672 3.875 55.272 ;
     RECT  2.869 0.096 3.877 0.408 ;
     RECT  3.877 0.096 3.971 0.456 ;
     RECT  3.913 57.6 3.971 57.624 ;
     RECT  3.805 60.96 3.989 64.584 ;
     RECT  2.704 39.36 4.093 39.384 ;
     RECT  3.251 2.16 4.097 32.52 ;
     RECT  4.093 39.36 4.169 40.2 ;
     RECT  4.165 36.48 4.211 36.504 ;
     RECT  3.971 0.096 4.259 0.168 ;
     RECT  4.237 49.728 4.525 49.752 ;
     RECT  3.449 58.848 4.525 59.016 ;
     RECT  3.989 60.96 4.595 62.184 ;
     RECT  4.417 65.616 4.595 65.64 ;
     RECT  2.704 56.352 4.597 56.376 ;
     RECT  4.595 60.96 4.597 62.04 ;
     RECT  4.259 0.096 4.601 0.12 ;
     RECT  4.273 71.04 4.669 71.064 ;
     RECT  2.704 35.328 4.693 35.352 ;
     RECT  4.169 40.176 4.709 40.2 ;
     RECT  4.417 46.128 4.709 46.152 ;
     RECT  4.097 2.16 4.741 31.944 ;
     RECT  4.489 33.072 4.741 33.096 ;
     RECT  4.273 34.224 4.741 34.248 ;
     RECT  4.525 58.464 4.741 59.016 ;
     RECT  4.597 60.768 4.741 62.04 ;
     RECT  2.704 47.472 4.813 48.264 ;
     RECT  4.525 49.488 4.813 49.752 ;
     RECT  3.985 69.84 4.849 69.864 ;
     RECT  3.985 37.728 4.885 37.752 ;
     RECT  3.875 55.248 4.921 55.272 ;
     RECT  4.597 56.352 4.993 57.192 ;
     RECT  4.741 58.464 4.993 62.04 ;
     RECT  4.849 69.84 4.993 70.056 ;
     RECT  4.669 71.04 4.993 71.208 ;
     RECT  4.129 73.776 4.993 73.8 ;
     RECT  4.777 76.896 4.993 76.92 ;
     RECT  4.921 55.2 5.029 55.272 ;
     RECT  4.993 76.896 5.029 77.496 ;
     RECT  4.453 78.48 5.029 78.504 ;
     RECT  4.705 66.72 5.065 66.744 ;
     RECT  4.993 69.264 5.077 71.208 ;
     RECT  5.029 76.8 5.077 78.504 ;
     RECT  4.129 52.224 5.101 52.488 ;
     RECT  5.029 54.528 5.101 55.272 ;
     RECT  4.993 56.352 5.101 62.04 ;
     RECT  5.077 69.264 5.101 71.304 ;
     RECT  4.741 1.728 5.125 31.944 ;
     RECT  4.741 33.072 5.125 34.248 ;
     RECT  4.885 37.728 5.125 37.848 ;
     RECT  5.101 52.176 5.137 52.632 ;
     RECT  3.989 63.552 5.137 64.584 ;
     RECT  5.101 69.264 5.137 71.736 ;
     RECT  5.077 76.8 5.137 79.272 ;
     RECT  5.125 37.632 5.171 37.848 ;
     RECT  5.065 66.528 5.177 66.744 ;
     RECT  5.177 66.624 5.245 66.744 ;
     RECT  5.171 37.632 5.249 37.752 ;
     RECT  4.693 35.328 5.317 35.928 ;
     RECT  4.993 73.488 5.317 73.8 ;
     RECT  5.125 1.728 5.353 34.248 ;
     RECT  5.101 54.528 5.353 62.04 ;
     RECT  5.245 66.624 5.353 67.752 ;
     RECT  5.137 68.976 5.353 71.736 ;
     RECT  5.137 63.552 5.365 64.872 ;
     RECT  4.813 49.488 5.389 50.712 ;
     RECT  5.317 73.488 5.393 74.136 ;
     RECT  5.389 49.44 5.425 50.712 ;
     RECT  5.353 66.624 5.509 71.736 ;
     RECT  5.509 66.624 5.537 71.832 ;
     RECT  5.425 73.248 5.557 73.272 ;
     RECT  5.317 35.328 5.573 36.504 ;
     RECT  5.533 39.12 5.603 39.144 ;
     RECT  5.537 66.624 5.603 69.288 ;
     RECT  5.573 35.328 5.609 36.264 ;
     RECT  5.137 52.176 5.641 53.016 ;
     RECT  5.641 52.128 5.677 53.016 ;
     RECT  5.677 52.128 5.749 53.4 ;
     RECT  5.353 54.48 5.749 62.04 ;
     RECT  5.557 73.008 5.749 73.272 ;
     RECT  5.557 40.464 5.753 40.488 ;
     RECT  4.813 46.944 5.785 48.264 ;
     RECT  5.749 52.128 5.857 62.04 ;
     RECT  5.785 46.752 5.893 48.264 ;
     RECT  5.425 49.44 5.893 50.76 ;
     RECT  5.353 1.728 5.897 34.296 ;
     RECT  5.893 46.752 5.929 50.76 ;
     RECT  5.857 52.128 5.929 62.328 ;
     RECT  5.077 75.504 5.929 75.528 ;
     RECT  5.137 76.8 5.929 79.32 ;
     RECT  5.897 7.968 5.939 34.296 ;
     RECT  5.029 45.552 6.037 45.576 ;
     RECT  5.029 43.872 6.041 43.896 ;
     RECT  6.037 45.552 6.085 45.672 ;
     RECT  5.929 75.504 6.109 79.32 ;
     RECT  5.929 46.752 6.131 62.328 ;
     RECT  6.131 50.592 6.149 62.328 ;
     RECT  5.603 66.624 6.149 67.848 ;
     RECT  5.365 63.504 6.181 64.872 ;
     RECT  6.149 50.592 6.185 59.832 ;
     RECT  6.149 67.296 6.221 67.848 ;
     RECT  5.939 7.968 6.227 33.48 ;
     RECT  6.149 61.44 6.289 62.328 ;
     RECT  6.181 63.504 6.289 65.448 ;
     RECT  5.249 37.632 6.421 37.656 ;
     RECT  6.145 41.472 6.433 41.496 ;
     RECT  5.749 72.912 6.433 73.272 ;
     RECT  6.433 41.424 6.469 41.496 ;
     RECT  6.433 72.816 6.565 73.272 ;
     RECT  6.109 74.688 6.565 79.32 ;
     RECT  6.289 61.44 6.581 65.448 ;
     RECT  6.085 43.92 6.613 45.672 ;
     RECT  6.131 46.752 6.613 49.512 ;
     RECT  5.941 34.512 6.653 34.872 ;
     RECT  6.613 43.92 6.653 49.512 ;
     RECT  6.653 45.552 6.659 49.512 ;
     RECT  6.659 46.176 6.707 49.512 ;
     RECT  6.581 61.44 6.707 64.44 ;
     RECT  5.537 70.416 6.721 71.832 ;
     RECT  6.565 72.816 6.721 79.608 ;
     RECT  5.603 68.976 6.725 69 ;
     RECT  6.185 50.592 6.797 59.016 ;
     RECT  6.469 41.424 6.829 42.456 ;
     RECT  6.653 34.512 6.833 34.824 ;
     RECT  5.897 1.728 6.949 6.984 ;
     RECT  6.227 7.968 6.949 33.096 ;
     RECT  6.833 34.512 6.949 34.536 ;
     RECT  5.609 36.24 7.261 36.264 ;
     RECT  6.421 37.44 7.261 37.656 ;
     RECT  7.261 36.24 7.405 37.656 ;
     RECT  6.797 52.224 7.405 59.016 ;
     RECT  6.221 67.296 7.441 67.32 ;
     RECT  7.405 35.856 7.477 37.656 ;
     RECT  6.829 41.424 7.477 42.744 ;
     RECT  6.653 43.92 7.477 44.472 ;
     RECT  6.707 47.328 7.477 49.512 ;
     RECT  6.797 50.592 7.477 51.24 ;
     RECT  7.477 0.144 7.525 0.168 ;
     RECT  6.581 65.424 7.549 65.448 ;
     RECT  7.441 66.72 7.549 67.32 ;
     RECT  6.707 61.44 7.657 64.152 ;
     RECT  7.525 0.144 7.667 0.408 ;
     RECT  7.477 41.424 7.669 44.472 ;
     RECT  6.707 46.176 7.669 46.2 ;
     RECT  7.657 61.344 7.765 64.152 ;
     RECT  6.949 1.728 7.808 33.096 ;
     RECT  6.949 34.128 7.808 34.536 ;
     RECT  7.477 35.856 7.808 38.424 ;
     RECT  5.857 40.032 7.808 40.056 ;
     RECT  7.669 41.424 7.808 46.2 ;
     RECT  7.477 47.328 7.808 51.24 ;
     RECT  7.405 52.224 7.808 59.736 ;
     RECT  7.765 61.344 7.808 64.344 ;
     RECT  7.549 65.424 7.808 67.32 ;
     RECT  6.721 70.416 7.808 79.608 ;
     RECT  7.667 0.144 7.859 0.312 ;
     RECT  7.808 1.728 8.104 79.932 ;
     RECT  8.104 68.832 8.237 79.932 ;
     RECT  8.104 35.328 8.243 39.912 ;
     RECT  8.237 71.616 8.485 79.932 ;
     RECT  8.104 1.728 8.525 33.96 ;
     RECT  8.525 29.616 8.531 33.768 ;
     RECT  8.485 71.616 8.531 80.376 ;
     RECT  8.104 47.328 8.579 67.32 ;
     RECT  8.557 81.936 8.593 81.96 ;
     RECT  8.237 68.832 8.627 70.536 ;
     RECT  8.593 81.504 8.627 81.96 ;
     RECT  8.104 41.04 8.633 42.216 ;
     RECT  8.627 68.832 8.633 69.288 ;
     RECT  8.633 68.928 8.723 69.288 ;
     RECT  8.723 68.928 8.741 68.952 ;
     RECT  8.579 47.328 8.849 66.216 ;
     RECT  8.243 38.112 8.915 39.912 ;
     RECT  8.104 44.448 8.957 45.624 ;
     RECT  8.849 47.328 9.059 61.704 ;
     RECT  7.859 0.144 9.061 0.264 ;
     RECT  9.059 51.408 9.065 61.704 ;
     RECT  9.059 47.328 9.173 50.376 ;
     RECT  9.065 51.408 9.173 60.744 ;
     RECT  8.633 41.04 9.203 41.448 ;
     RECT  9.173 49.248 9.209 50.376 ;
     RECT  9.173 60.672 9.209 60.744 ;
     RECT  9.061 0.096 9.245 0.264 ;
     RECT  9.173 51.408 9.281 59.496 ;
     RECT  8.627 81.504 9.299 81.528 ;
     RECT  8.957 44.448 9.313 45.24 ;
     RECT  8.915 38.16 9.349 39.912 ;
     RECT  9.203 41.04 9.349 41.16 ;
     RECT  9.349 38.16 9.395 41.16 ;
     RECT  8.531 29.664 9.443 33.768 ;
     RECT  8.243 35.328 9.445 37.128 ;
     RECT  8.525 1.728 9.493 28.488 ;
     RECT  9.493 1.728 9.541 28.584 ;
     RECT  9.443 29.664 9.541 33.144 ;
     RECT  8.849 62.832 9.565 66.216 ;
     RECT  9.245 0.144 9.587 0.264 ;
     RECT  9.565 62.832 9.589 66.648 ;
     RECT  9.445 67.776 9.589 67.8 ;
     RECT  9.589 62.832 9.605 67.8 ;
     RECT  9.605 66.624 9.635 67.8 ;
     RECT  9.281 51.408 9.683 59.016 ;
     RECT  9.445 34.8 9.749 37.128 ;
     RECT  9.683 51.408 9.749 57.336 ;
     RECT  8.627 70.32 9.781 70.536 ;
     RECT  8.531 71.616 9.781 79.8 ;
     RECT  9.541 1.728 9.785 33.144 ;
     RECT  9.605 62.832 9.925 65.448 ;
     RECT  9.781 70.32 9.925 79.8 ;
     RECT  9.173 47.328 9.961 48.264 ;
     RECT  9.925 62.784 9.997 65.448 ;
     RECT  9.749 52.416 10.001 57.336 ;
     RECT  9.209 60.672 10.037 60.696 ;
     RECT  9.925 70.32 10.115 79.848 ;
     RECT  10.117 81.936 10.181 81.96 ;
     RECT  9.997 62.016 10.211 65.448 ;
     RECT  10.115 71.808 10.211 79.848 ;
     RECT  9.635 67.248 10.213 67.8 ;
     RECT  10.069 68.784 10.213 68.808 ;
     RECT  9.683 58.416 10.261 59.016 ;
     RECT  10.115 70.32 10.309 70.536 ;
     RECT  9.961 47.28 10.321 48.264 ;
     RECT  10.321 46.752 10.393 48.264 ;
     RECT  9.209 49.248 10.393 49.608 ;
     RECT  10.001 55.824 10.397 57.336 ;
     RECT  10.309 70.224 10.405 70.536 ;
     RECT  9.749 34.8 10.451 37.032 ;
     RECT  10.357 43.296 10.537 43.32 ;
     RECT  10.393 46.752 10.541 49.608 ;
     RECT  9.785 24.48 10.597 33.144 ;
     RECT  9.395 41.136 10.645 41.16 ;
     RECT  10.537 42.576 10.645 43.32 ;
     RECT  9.313 44.352 10.649 45.24 ;
     RECT  10.211 62.592 10.649 65.448 ;
     RECT  10.397 55.824 10.685 56.904 ;
     RECT  10.261 58.416 10.685 59.88 ;
     RECT  10.649 63.264 10.685 65.448 ;
     RECT  9.749 51.408 10.717 51.432 ;
     RECT  10.597 24.48 10.789 33.24 ;
     RECT  10.609 34.32 10.789 34.344 ;
     RECT  10.213 67.248 10.793 68.808 ;
     RECT  10.213 0.096 10.825 0.12 ;
     RECT  10.451 35.616 10.825 37.032 ;
     RECT  10.685 65.28 10.825 65.448 ;
     RECT  10.405 69.936 10.835 70.536 ;
     RECT  10.549 81.792 10.835 81.912 ;
     RECT  10.825 65.28 10.861 65.928 ;
     RECT  10.793 67.248 10.861 67.8 ;
     RECT  10.825 0.096 10.931 0.6 ;
     RECT  9.785 1.728 10.933 23.496 ;
     RECT  10.789 24.48 10.933 34.344 ;
     RECT  10.649 44.592 10.981 45.24 ;
     RECT  10.835 69.936 11.009 70.344 ;
     RECT  10.717 51.408 11.029 51.912 ;
     RECT  10.001 53.232 11.041 54.456 ;
     RECT  10.645 41.136 11.077 43.32 ;
     RECT  10.825 35.616 11.081 37.176 ;
     RECT  10.933 1.728 11.219 34.344 ;
     RECT  11.077 41.04 11.219 43.32 ;
     RECT  10.211 71.808 11.225 79.8 ;
     RECT  10.793 68.784 11.257 68.808 ;
     RECT  11.081 36 11.329 37.176 ;
     RECT  9.395 38.16 11.329 40.008 ;
     RECT  11.029 51.408 11.365 51.96 ;
     RECT  11.041 52.992 11.365 54.456 ;
     RECT  10.685 56.256 11.365 56.904 ;
     RECT  10.685 58.416 11.365 59.064 ;
     RECT  10.931 0.096 11.411 0.216 ;
     RECT  11.329 36 11.441 40.008 ;
     RECT  10.981 44.592 11.473 45.576 ;
     RECT  10.541 46.752 11.473 49.272 ;
     RECT  11.473 44.592 11.477 49.272 ;
     RECT  11.365 81.936 11.513 81.96 ;
     RECT  11.257 68.784 11.555 69.336 ;
     RECT  10.685 63.264 11.689 64.104 ;
     RECT  10.861 65.28 11.689 67.8 ;
     RECT  11.411 0.096 11.765 0.168 ;
     RECT  11.219 41.136 11.797 43.32 ;
     RECT  11.477 44.592 11.797 46.344 ;
     RECT  11.689 63.264 11.797 67.8 ;
     RECT  11.555 68.784 11.797 69.288 ;
     RECT  11.477 47.424 11.833 49.272 ;
     RECT  11.797 63.264 11.843 69.288 ;
     RECT  11.219 2.208 11.845 34.344 ;
     RECT  11.009 70.32 11.869 70.344 ;
     RECT  11.225 71.808 11.905 79.752 ;
     RECT  11.545 60.48 11.977 60.504 ;
     RECT  11.843 63.264 11.977 68.808 ;
     RECT  11.765 0.096 12.017 0.12 ;
     RECT  11.365 56.256 12.053 59.064 ;
     RECT  11.977 60.48 12.053 61.368 ;
     RECT  12.053 57.888 12.083 59.064 ;
     RECT  12.083 58.416 12.089 59.064 ;
     RECT  12.053 60.576 12.133 61.368 ;
     RECT  12.089 58.512 12.157 59.064 ;
     RECT  12.133 60.576 12.193 61.416 ;
     RECT  11.365 51.408 12.197 54.456 ;
     RECT  11.833 47.424 12.229 50.136 ;
     RECT  12.197 51.408 12.229 53.304 ;
     RECT  11.845 2.208 12.265 34.92 ;
     RECT  11.977 62.976 12.265 68.808 ;
     RECT  12.265 2.208 12.277 35.016 ;
     RECT  11.441 36 12.277 39.768 ;
     RECT  12.265 62.928 12.277 68.808 ;
     RECT  12.277 2.208 12.481 39.768 ;
     RECT  11.797 41.136 12.481 46.344 ;
     RECT  11.869 70.32 12.589 70.584 ;
     RECT  12.053 56.256 12.769 56.808 ;
     RECT  12.481 2.208 13.057 46.344 ;
     RECT  12.157 58.512 13.093 59.4 ;
     RECT  12.769 55.824 13.201 56.808 ;
     RECT  13.093 57.888 13.201 59.4 ;
     RECT  13.057 1.968 13.208 46.344 ;
     RECT  12.229 47.424 13.208 53.304 ;
     RECT  12.197 54.336 13.208 54.456 ;
     RECT  13.201 55.824 13.208 59.4 ;
     RECT  12.193 60.576 13.208 61.608 ;
     RECT  12.277 62.688 13.208 68.808 ;
     RECT  12.589 70.272 13.208 70.584 ;
     RECT  11.905 71.616 13.208 79.752 ;
     RECT  13.208 1.968 13.312 79.932 ;
     RECT  13.312 1.968 13.504 79.752 ;
     RECT  13.504 72.384 13.619 79.752 ;
     RECT  13.381 0.144 13.667 0.168 ;
     RECT  13.504 1.968 13.709 46.344 ;
     RECT  13.741 0.096 13.811 0.12 ;
     RECT  13.504 47.328 13.853 53.304 ;
     RECT  13.709 1.968 13.861 39.384 ;
     RECT  13.504 56.784 13.889 66.792 ;
     RECT  13.889 61.344 14.285 66.792 ;
     RECT  14.285 61.344 14.387 64.104 ;
     RECT  13.619 72.384 14.387 73.368 ;
     RECT  13.504 67.824 14.465 71.064 ;
     RECT  13.619 74.592 14.497 79.752 ;
     RECT  14.285 65.328 14.537 66.792 ;
     RECT  13.861 1.728 14.579 39.384 ;
     RECT  14.537 65.376 14.579 65.544 ;
     RECT  14.497 74.592 14.579 79.8 ;
     RECT  14.465 67.824 14.675 70.68 ;
     RECT  14.579 74.592 14.725 79.752 ;
     RECT  14.387 61.728 14.753 64.104 ;
     RECT  14.579 38.112 14.773 39.384 ;
     RECT  13.709 40.368 14.773 46.344 ;
     RECT  14.773 38.112 14.785 46.344 ;
     RECT  13.853 47.328 14.785 49.272 ;
     RECT  13.504 54.336 14.929 54.552 ;
     RECT  14.725 74.496 14.965 79.752 ;
     RECT  13.853 50.256 15.061 53.304 ;
     RECT  14.929 54.336 15.061 54.984 ;
     RECT  14.785 38.112 15.157 49.272 ;
     RECT  15.061 50.256 15.157 54.984 ;
     RECT  15.157 38.112 15.325 54.984 ;
     RECT  14.753 63.504 15.325 64.104 ;
     RECT  14.579 1.728 15.347 37.08 ;
     RECT  13.889 56.784 15.361 59.784 ;
     RECT  15.397 0.096 15.443 0.12 ;
     RECT  14.387 72.384 15.469 72.984 ;
     RECT  14.965 73.968 15.469 79.752 ;
     RECT  14.821 81.504 15.469 81.528 ;
     RECT  15.361 56.784 15.493 59.832 ;
     RECT  14.537 66.768 15.505 66.792 ;
     RECT  15.505 66.768 15.541 67.656 ;
     RECT  14.675 68.64 15.541 70.68 ;
     RECT  15.469 72.384 15.541 79.752 ;
     RECT  15.541 68.64 15.589 70.968 ;
     RECT  15.541 71.952 15.589 79.752 ;
     RECT  15.469 81.504 15.635 81.576 ;
     RECT  15.325 38.112 15.683 55.464 ;
     RECT  15.541 66.624 15.685 67.656 ;
     RECT  15.589 68.64 15.685 79.752 ;
     RECT  15.685 66.624 15.725 79.752 ;
     RECT  14.579 65.376 15.757 65.4 ;
     RECT  15.725 66.624 15.757 72.84 ;
     RECT  15.347 2.064 15.793 37.08 ;
     RECT  14.753 61.728 15.829 62.472 ;
     RECT  15.325 63.504 15.829 64.2 ;
     RECT  15.829 61.728 15.865 64.2 ;
     RECT  15.757 65.376 15.865 72.84 ;
     RECT  15.685 0.144 15.923 0.696 ;
     RECT  15.635 81.552 15.923 81.576 ;
     RECT  15.493 56.784 16.009 60.552 ;
     RECT  15.973 81.84 16.019 81.96 ;
     RECT  15.725 73.872 16.069 79.752 ;
     RECT  15.793 2.064 16.085 37.848 ;
     RECT  16.019 81.84 16.115 81.864 ;
     RECT  16.009 56.784 16.117 60.648 ;
     RECT  15.865 61.728 16.117 72.84 ;
     RECT  16.117 56.784 16.193 72.84 ;
     RECT  15.923 0.144 16.259 0.168 ;
     RECT  16.193 66.72 16.301 72.84 ;
     RECT  16.193 56.784 16.477 65.688 ;
     RECT  16.085 2.064 16.481 36.264 ;
     RECT  15.683 38.832 16.549 55.464 ;
     RECT  16.477 56.496 16.549 65.688 ;
     RECT  16.549 38.832 16.595 65.688 ;
     RECT  16.085 37.344 16.733 37.848 ;
     RECT  16.069 73.872 16.873 79.848 ;
     RECT  16.481 2.064 16.909 35.928 ;
     RECT  16.873 73.872 16.979 80.376 ;
     RECT  16.909 1.728 17.123 35.928 ;
     RECT  16.595 38.832 17.129 65.4 ;
     RECT  17.123 1.728 17.221 35.88 ;
     RECT  17.221 1.248 17.317 35.88 ;
     RECT  16.301 66.768 17.413 72.84 ;
     RECT  17.129 56.784 17.459 65.4 ;
     RECT  17.459 63.072 17.629 65.4 ;
     RECT  17.413 66.576 17.629 72.84 ;
     RECT  17.629 63.072 17.701 72.84 ;
     RECT  16.979 73.872 17.701 79.896 ;
     RECT  17.129 38.832 17.737 55.8 ;
     RECT  17.701 0.096 17.747 0.12 ;
     RECT  17.317 1.152 17.749 35.88 ;
     RECT  16.733 37.344 17.845 37.368 ;
     RECT  17.029 81.936 17.885 81.96 ;
     RECT  17.845 37.056 18.205 37.368 ;
     RECT  17.701 63.072 18.277 79.896 ;
     RECT  18.205 37.056 18.325 37.416 ;
     RECT  17.749 0.144 18.608 35.88 ;
     RECT  18.325 37.056 18.608 37.656 ;
     RECT  17.737 38.64 18.608 55.8 ;
     RECT  17.459 56.784 18.608 62.088 ;
     RECT  18.277 63.072 18.608 80.088 ;
     RECT  18.608 0.144 18.745 80.088 ;
     RECT  18.745 0.144 18.904 80.136 ;
     RECT  18.904 0.144 19.001 49.272 ;
     RECT  18.904 50.352 19.073 80.136 ;
     RECT  19.001 0.144 19.105 39.096 ;
     RECT  19.105 0.096 19.187 39.096 ;
     RECT  19.187 0.144 19.331 39.096 ;
     RECT  19.331 0.144 19.361 0.36 ;
     RECT  19.361 0.144 19.379 0.312 ;
     RECT  19.141 81.984 19.477 82.008 ;
     RECT  19.477 81.504 19.525 82.008 ;
     RECT  19.073 63.504 19.573 80.136 ;
     RECT  19.331 1.728 19.829 39.096 ;
     RECT  19.525 81.408 19.859 82.008 ;
     RECT  19.829 2.064 19.955 39.096 ;
     RECT  19.573 63.504 20.053 80.28 ;
     RECT  20.053 63.504 20.149 80.328 ;
     RECT  19.379 0.144 20.195 0.168 ;
     RECT  19.073 50.352 20.293 62.328 ;
     RECT  20.149 63.504 20.293 80.376 ;
     RECT  19.859 81.744 20.339 82.008 ;
     RECT  20.339 81.84 20.435 82.008 ;
     RECT  20.293 50.352 20.477 80.376 ;
     RECT  19.001 40.128 20.581 49.272 ;
     RECT  20.477 50.352 20.581 56.04 ;
     RECT  19.955 33.936 20.627 39.096 ;
     RECT  20.627 34.224 20.689 39.096 ;
     RECT  20.581 40.128 20.689 56.04 ;
     RECT  19.955 2.064 20.869 32.856 ;
     RECT  20.869 1.728 20.917 32.856 ;
     RECT  20.689 34.224 20.945 56.04 ;
     RECT  20.945 34.224 21.053 39.096 ;
     RECT  20.917 1.152 21.107 32.856 ;
     RECT  21.107 1.728 21.205 32.856 ;
     RECT  21.053 34.224 21.449 37.848 ;
     RECT  21.205 1.728 21.589 33 ;
     RECT  21.449 34.224 21.589 35.592 ;
     RECT  20.435 81.888 21.733 82.008 ;
     RECT  21.733 81.696 21.769 82.008 ;
     RECT  20.945 40.368 21.877 56.04 ;
     RECT  21.877 40.368 21.881 56.088 ;
     RECT  21.781 0.192 22.067 0.312 ;
     RECT  20.477 57.36 22.201 80.376 ;
     RECT  21.769 81.696 22.201 82.056 ;
     RECT  21.881 50.352 22.309 56.088 ;
     RECT  22.201 57.36 22.309 82.056 ;
     RECT  21.589 1.728 22.669 35.592 ;
     RECT  21.449 36.672 22.669 37.848 ;
     RECT  22.669 1.728 22.849 37.848 ;
     RECT  22.849 1.728 22.993 38.04 ;
     RECT  21.053 39.072 22.993 39.096 ;
     RECT  22.309 50.352 23.123 82.056 ;
     RECT  23.123 81.504 23.315 82.056 ;
     RECT  22.885 0.096 23.413 0.12 ;
     RECT  23.123 50.352 23.603 80.328 ;
     RECT  22.993 1.728 23.821 39.096 ;
     RECT  23.603 50.352 23.857 79.932 ;
     RECT  23.821 1.728 24.008 39.24 ;
     RECT  21.881 40.368 24.008 49.272 ;
     RECT  23.857 50.304 24.008 79.932 ;
     RECT  24.008 1.728 24.112 79.932 ;
     RECT  24.112 1.728 24.185 79.848 ;
     RECT  24.185 2.016 24.304 79.848 ;
     RECT  23.413 0.096 24.325 0.216 ;
     RECT  24.304 2.016 24.365 37.272 ;
     RECT  24.304 70.896 24.437 79.848 ;
     RECT  23.315 81.984 24.505 82.056 ;
     RECT  24.325 0.096 24.515 0.264 ;
     RECT  24.304 40.368 24.617 69.288 ;
     RECT  24.304 38.256 24.797 39.24 ;
     RECT  24.617 62.688 24.797 69.288 ;
     RECT  24.797 62.688 24.941 62.808 ;
     RECT  24.797 63.792 24.941 69.288 ;
     RECT  24.437 71.088 24.977 79.848 ;
     RECT  24.617 40.368 25.013 61.416 ;
     RECT  24.941 63.792 25.049 64.968 ;
     RECT  24.977 71.232 25.081 79.848 ;
     RECT  25.081 71.232 25.139 80.376 ;
     RECT  25.013 40.368 25.157 44.184 ;
     RECT  24.505 81.504 25.235 82.056 ;
     RECT  24.365 2.064 25.405 37.272 ;
     RECT  24.797 38.256 25.405 38.664 ;
     RECT  24.941 62.784 25.445 62.808 ;
     RECT  24.941 66.048 25.477 69.288 ;
     RECT  25.139 71.232 25.481 79.848 ;
     RECT  24.515 0.096 25.621 0.216 ;
     RECT  25.405 2.064 25.621 38.664 ;
     RECT  25.481 72.768 25.763 79.848 ;
     RECT  25.013 45.216 25.805 61.416 ;
     RECT  25.621 0.096 25.907 38.664 ;
     RECT  25.907 0.144 25.981 38.664 ;
     RECT  25.157 43.536 25.981 44.184 ;
     RECT  25.805 45.216 25.981 49.272 ;
     RECT  25.981 0.144 26.003 39.192 ;
     RECT  25.049 63.792 26.089 64.776 ;
     RECT  25.477 66.048 26.089 70.152 ;
     RECT  26.003 1.152 26.099 39.192 ;
     RECT  26.099 1.248 26.195 39.192 ;
     RECT  26.195 2.064 26.197 39.192 ;
     RECT  25.157 40.368 26.197 42.552 ;
     RECT  26.197 2.064 26.309 42.552 ;
     RECT  25.481 71.232 26.309 71.784 ;
     RECT  25.763 72.768 26.381 79.752 ;
     RECT  25.235 81.888 26.389 82.056 ;
     RECT  26.309 2.208 26.449 42.552 ;
     RECT  25.981 43.536 26.449 49.272 ;
     RECT  26.089 63.792 26.489 70.152 ;
     RECT  26.381 75.648 26.489 79.752 ;
     RECT  26.489 65.712 26.525 70.152 ;
     RECT  26.525 66.096 26.561 70.152 ;
     RECT  26.125 62.448 26.593 62.472 ;
     RECT  26.489 63.792 26.593 64.728 ;
     RECT  26.309 71.76 26.669 71.784 ;
     RECT  26.593 62.448 26.813 64.728 ;
     RECT  26.003 0.144 26.819 0.168 ;
     RECT  26.389 81.84 26.845 82.056 ;
     RECT  26.489 75.792 26.849 79.752 ;
     RECT  25.805 50.352 26.921 61.416 ;
     RECT  26.561 66.096 26.921 69.144 ;
     RECT  26.921 58.656 26.957 61.416 ;
     RECT  26.921 50.352 27.097 56.088 ;
     RECT  26.381 72.768 27.169 74.424 ;
     RECT  26.845 81.504 27.245 82.056 ;
     RECT  26.449 2.208 27.389 49.272 ;
     RECT  27.389 2.208 27.397 38.424 ;
     RECT  27.245 81.504 27.425 82.008 ;
     RECT  27.425 81.504 27.443 81.912 ;
     RECT  27.397 1.728 27.497 38.424 ;
     RECT  26.561 70.128 27.497 70.152 ;
     RECT  27.497 1.728 27.539 36.504 ;
     RECT  27.443 81.504 27.539 81.528 ;
     RECT  26.957 58.656 27.569 61.224 ;
     RECT  27.497 37.536 27.605 38.424 ;
     RECT  27.539 33.84 27.749 36.504 ;
     RECT  27.389 39.456 27.853 49.272 ;
     RECT  27.097 50.256 27.853 56.088 ;
     RECT  26.921 66.096 27.961 68.376 ;
     RECT  27.169 72.336 27.965 74.424 ;
     RECT  27.961 66.096 27.997 68.472 ;
     RECT  27.749 33.84 28.037 36.12 ;
     RECT  27.997 66.048 28.213 68.472 ;
     RECT  26.849 75.792 28.213 79.704 ;
     RECT  27.605 37.536 28.397 37.752 ;
     RECT  26.921 57.408 28.597 57.576 ;
     RECT  27.569 58.656 28.597 60.696 ;
     RECT  28.069 0.096 28.609 0.12 ;
     RECT  28.609 0.096 28.613 0.552 ;
     RECT  28.613 0.528 28.691 0.552 ;
     RECT  27.965 74.016 28.789 74.424 ;
     RECT  28.213 75.792 28.789 79.848 ;
     RECT  27.965 72.336 28.969 72.504 ;
     RECT  27.853 39.456 29.041 56.088 ;
     RECT  28.597 57.408 29.041 60.696 ;
     RECT  28.789 74.016 29.077 74.472 ;
     RECT  28.789 75.744 29.077 79.848 ;
     RECT  28.037 33.84 29.221 35.208 ;
     RECT  27.539 1.728 29.369 32.856 ;
     RECT  29.369 1.872 29.408 32.856 ;
     RECT  29.221 33.84 29.408 36.024 ;
     RECT  28.397 37.536 29.408 37.656 ;
     RECT  29.041 39.456 29.408 60.696 ;
     RECT  26.813 62.448 29.408 64.632 ;
     RECT  28.213 66.048 29.408 68.952 ;
     RECT  28.969 71.472 29.408 72.504 ;
     RECT  29.077 73.872 29.408 79.848 ;
     RECT  29.408 1.872 29.512 79.932 ;
     RECT  29.512 1.872 29.704 79.848 ;
     RECT  29.704 45.216 29.729 49.32 ;
     RECT  29.704 33.84 29.843 34.488 ;
     RECT  29.729 45.216 29.873 49.272 ;
     RECT  29.873 45.216 29.909 48.792 ;
     RECT  29.704 71.472 29.909 79.848 ;
     RECT  29.701 0.144 30.181 0.168 ;
     RECT  29.704 1.872 30.373 32.856 ;
     RECT  29.909 45.216 30.377 47.736 ;
     RECT  29.704 40.368 30.629 44.184 ;
     RECT  30.181 0.096 30.757 0.168 ;
     RECT  29.704 35.616 30.809 39.192 ;
     RECT  29.909 71.856 30.809 79.848 ;
     RECT  29.843 33.84 30.985 34.44 ;
     RECT  30.377 45.216 31.025 46.104 ;
     RECT  29.704 50.304 31.057 54.936 ;
     RECT  30.377 47.184 31.129 47.736 ;
     RECT  29.909 48.768 31.129 48.792 ;
     RECT  29.704 55.968 31.141 69.624 ;
     RECT  31.057 50.112 31.165 54.936 ;
     RECT  31.141 55.968 31.165 70.776 ;
     RECT  30.757 0.096 31.187 0.312 ;
     RECT  31.165 50.112 31.205 70.776 ;
     RECT  31.129 47.184 31.273 48.792 ;
     RECT  31.205 50.112 31.273 69.624 ;
     RECT  31.187 0.096 31.283 0.216 ;
     RECT  31.025 45.216 31.309 45.24 ;
     RECT  31.205 70.608 31.333 70.776 ;
     RECT  30.809 36.144 31.633 39.192 ;
     RECT  30.629 40.368 31.633 43.944 ;
     RECT  30.301 81.936 31.705 81.96 ;
     RECT  31.633 36.144 31.763 43.944 ;
     RECT  30.373 1.728 31.777 32.856 ;
     RECT  30.985 33.84 31.777 35.16 ;
     RECT  31.777 1.728 31.849 35.16 ;
     RECT  31.763 36.624 31.961 43.944 ;
     RECT  31.705 81.888 31.993 81.96 ;
     RECT  30.809 72.192 32.069 79.848 ;
     RECT  32.069 72.192 32.177 79.8 ;
     RECT  31.309 45.024 32.285 45.24 ;
     RECT  31.273 47.184 32.389 69.624 ;
     RECT  31.333 70.608 32.425 70.824 ;
     RECT  32.285 45.024 32.573 45.048 ;
     RECT  32.389 46.272 32.581 69.624 ;
     RECT  32.425 70.608 32.581 70.872 ;
     RECT  32.581 46.272 32.609 70.872 ;
     RECT  31.961 40.368 32.713 43.944 ;
     RECT  31.961 36.624 32.753 39.048 ;
     RECT  32.753 37.008 32.933 39.048 ;
     RECT  32.609 53.328 32.965 70.872 ;
     RECT  32.965 53.328 33.037 70.92 ;
     RECT  31.849 1.728 33.181 35.304 ;
     RECT  32.933 37.104 33.217 39.048 ;
     RECT  32.713 40.368 33.217 44.376 ;
     RECT  32.609 46.272 33.217 52.344 ;
     RECT  33.037 53.328 33.253 71.496 ;
     RECT  32.177 72.576 33.253 79.8 ;
     RECT  33.181 1.728 33.361 35.352 ;
     RECT  33.361 1.728 33.365 35.928 ;
     RECT  33.217 37.104 33.617 44.376 ;
     RECT  33.217 46.032 33.721 52.344 ;
     RECT  33.253 53.328 33.721 79.8 ;
     RECT  33.617 37.104 33.761 43.944 ;
     RECT  33.365 31.152 34.021 35.928 ;
     RECT  33.761 37.104 34.021 39.048 ;
     RECT  31.993 81.84 34.021 81.96 ;
     RECT  33.721 46.032 34.225 79.8 ;
     RECT  33.365 1.728 34.369 30.168 ;
     RECT  34.021 31.152 34.369 39.048 ;
     RECT  34.225 45.168 34.765 79.8 ;
     RECT  34.369 1.728 34.808 39.048 ;
     RECT  33.761 40.368 34.808 43.944 ;
     RECT  34.765 45.168 34.808 80.088 ;
     RECT  34.808 1.728 34.835 80.088 ;
     RECT  34.021 81.792 34.885 81.96 ;
     RECT  31.283 0.096 34.981 0.12 ;
     RECT  34.981 0.096 35.077 0.168 ;
     RECT  34.835 1.728 35.104 80.04 ;
     RECT  35.077 0.096 35.173 0.312 ;
     RECT  35.104 1.728 35.173 42.6 ;
     RECT  35.104 43.92 35.201 80.04 ;
     RECT  35.173 0.096 35.267 42.6 ;
     RECT  34.885 81.648 35.341 81.96 ;
     RECT  35.267 0.096 35.363 0.168 ;
     RECT  35.201 43.92 36.029 79.8 ;
     RECT  35.267 1.152 36.205 42.6 ;
     RECT  36.205 1.152 36.275 42.744 ;
     RECT  36.275 1.152 36.419 42.6 ;
     RECT  35.341 81.504 36.421 81.96 ;
     RECT  36.421 81.504 36.563 82.056 ;
     RECT  36.419 1.728 36.965 42.6 ;
     RECT  36.965 1.824 37.043 42.6 ;
     RECT  36.029 43.92 37.177 79.752 ;
     RECT  37.043 1.872 37.475 42.6 ;
     RECT  35.363 0.096 37.477 0.12 ;
     RECT  36.563 81.744 37.609 82.056 ;
     RECT  37.477 0.096 37.649 0.168 ;
     RECT  37.649 0.144 37.669 0.168 ;
     RECT  37.475 1.872 37.685 39.384 ;
     RECT  37.609 81.504 37.715 82.056 ;
     RECT  37.669 0.144 37.721 0.216 ;
     RECT  37.177 43.92 37.789 79.8 ;
     RECT  37.715 81.6 37.811 82.056 ;
     RECT  37.811 81.696 38.099 82.056 ;
     RECT  37.789 43.584 38.153 79.8 ;
     RECT  38.153 46.032 38.401 79.8 ;
     RECT  38.401 46.032 38.483 79.848 ;
     RECT  37.475 40.368 38.725 42.6 ;
     RECT  38.153 43.584 38.725 44.52 ;
     RECT  37.721 0.144 38.981 0.168 ;
     RECT  38.099 81.84 39.155 82.056 ;
     RECT  37.685 1.872 39.161 39.048 ;
     RECT  39.155 81.888 39.299 82.056 ;
     RECT  38.483 46.032 39.493 79.8 ;
     RECT  39.013 0.096 39.539 0.12 ;
     RECT  39.161 1.872 39.589 36.84 ;
     RECT  39.493 46.032 39.733 79.848 ;
     RECT  39.161 37.92 39.877 39.048 ;
     RECT  38.725 40.368 39.877 44.52 ;
     RECT  39.733 46.032 39.985 79.944 ;
     RECT  39.985 45.552 40.057 79.944 ;
     RECT  40.057 45.504 40.093 79.944 ;
     RECT  40.093 45.504 40.165 80.088 ;
     RECT  39.589 1.728 40.208 36.84 ;
     RECT  39.877 37.92 40.208 44.52 ;
     RECT  40.165 45.504 40.208 80.136 ;
     RECT  40.208 1.728 40.504 80.136 ;
     RECT  40.021 0.144 40.549 0.168 ;
     RECT  39.299 81.984 40.549 82.056 ;
     RECT  40.549 0.144 40.645 0.216 ;
     RECT  40.549 81.744 40.789 82.056 ;
     RECT  40.645 0.144 40.837 0.264 ;
     RECT  40.789 81.696 41.029 82.056 ;
     RECT  40.504 45.024 41.221 80.136 ;
     RECT  40.837 0.096 41.285 0.264 ;
     RECT  41.221 45.024 41.321 80.376 ;
     RECT  41.029 81.504 41.459 82.056 ;
     RECT  40.504 1.728 41.537 43.944 ;
     RECT  41.321 45.024 41.537 45.048 ;
     RECT  41.537 1.872 41.893 43.944 ;
     RECT  41.321 46.032 42.041 80.376 ;
     RECT  41.285 0.096 42.661 0.216 ;
     RECT  42.661 0.096 42.833 0.552 ;
     RECT  42.041 46.272 42.869 80.376 ;
     RECT  41.893 1.872 42.937 44.52 ;
     RECT  42.937 1.872 42.995 44.808 ;
     RECT  41.459 81.984 43.621 82.056 ;
     RECT  43.621 81.936 43.667 82.056 ;
     RECT  43.667 81.936 43.873 82.008 ;
     RECT  43.873 81.504 43.949 82.008 ;
     RECT  43.949 81.504 43.955 81.912 ;
     RECT  42.833 0.096 44.273 0.264 ;
     RECT  42.869 46.272 44.291 79.8 ;
     RECT  42.995 1.872 44.389 44.52 ;
     RECT  44.273 0.144 44.435 0.264 ;
     RECT  44.435 0.144 44.483 0.216 ;
     RECT  44.389 1.872 44.845 44.904 ;
     RECT  43.955 81.504 45.025 81.528 ;
     RECT  44.845 1.872 45.157 45.768 ;
     RECT  45.157 1.728 45.277 45.768 ;
     RECT  44.291 47.04 45.277 79.8 ;
     RECT  45.025 81.504 45.349 81.576 ;
     RECT  45.349 81.456 45.491 81.576 ;
     RECT  45.277 1.728 45.529 79.8 ;
     RECT  45.529 1.728 45.565 80.088 ;
     RECT  45.565 1.728 45.587 80.184 ;
     RECT  45.587 1.776 45.605 80.184 ;
     RECT  45.605 1.872 45.683 80.184 ;
     RECT  44.483 0.192 45.733 0.216 ;
     RECT  45.683 1.872 45.904 80.04 ;
     RECT  45.904 46.752 45.971 80.04 ;
     RECT  45.733 0.192 46.019 0.408 ;
     RECT  45.733 81.6 46.021 81.72 ;
     RECT  46.019 0.192 46.067 0.312 ;
     RECT  46.021 81.6 46.067 81.816 ;
     RECT  45.971 46.752 46.115 79.848 ;
     RECT  46.067 0.192 46.117 0.216 ;
     RECT  46.067 81.744 46.117 81.816 ;
     RECT  45.904 1.872 46.433 45.768 ;
     RECT  46.115 47.04 46.469 79.848 ;
     RECT  46.117 81.744 46.739 81.96 ;
     RECT  46.739 81.888 46.793 81.96 ;
     RECT  46.433 45.696 46.829 45.768 ;
     RECT  46.117 0.096 47.125 0.216 ;
     RECT  47.125 0.096 47.173 0.36 ;
     RECT  46.469 51.36 47.221 79.848 ;
     RECT  47.173 0.096 47.315 0.456 ;
     RECT  47.221 51.36 47.315 80.376 ;
     RECT  46.433 1.872 47.461 44.616 ;
     RECT  46.469 47.04 47.473 50.328 ;
     RECT  46.793 81.888 47.651 81.912 ;
     RECT  47.461 1.824 47.749 44.616 ;
     RECT  47.315 51.36 47.837 79.848 ;
     RECT  47.473 46.704 47.891 50.328 ;
     RECT  47.891 46.896 48.337 50.328 ;
     RECT  47.837 51.36 48.337 79.8 ;
     RECT  47.315 0.096 48.421 0.216 ;
     RECT  46.829 45.696 48.449 45.72 ;
     RECT  47.749 1.728 48.625 44.616 ;
     RECT  48.337 46.896 48.877 79.8 ;
     RECT  48.421 0.096 48.997 0.552 ;
     RECT  48.625 1.728 48.997 45.576 ;
     RECT  48.877 46.896 49.021 79.848 ;
     RECT  48.949 80.88 49.043 80.904 ;
     RECT  48.997 0.096 49.061 45.576 ;
     RECT  49.061 0.096 49.187 44.616 ;
     RECT  49.187 1.728 49.421 44.616 ;
     RECT  49.021 46.752 50.065 79.848 ;
     RECT  50.065 46.464 50.137 79.848 ;
     RECT  49.421 1.776 50.569 44.616 ;
     RECT  50.137 45.792 50.569 79.848 ;
     RECT  50.569 1.776 50.749 79.848 ;
     RECT  49.957 81.888 50.773 81.912 ;
     RECT  50.749 1.776 50.819 80.184 ;
     RECT  49.187 0.096 50.861 0.552 ;
     RECT  50.773 81.84 50.893 81.912 ;
     RECT  50.819 1.776 51.185 80.088 ;
     RECT  50.893 81.84 51.251 81.96 ;
     RECT  51.185 1.776 51.304 79.848 ;
     RECT  51.251 81.936 51.365 81.96 ;
     RECT  51.304 46.896 51.473 79.848 ;
     RECT  51.473 46.896 51.509 47.592 ;
     RECT  50.861 0.144 51.637 0.552 ;
     RECT  51.304 1.776 51.637 45.096 ;
     RECT  51.637 0.144 52.261 45.096 ;
     RECT  52.357 81.936 52.453 81.96 ;
     RECT  52.453 81.888 52.597 81.96 ;
     RECT  52.597 81.84 52.661 81.96 ;
     RECT  52.661 81.888 52.691 81.96 ;
     RECT  52.691 81.888 52.835 81.912 ;
     RECT  52.261 0.096 52.883 45.096 ;
     RECT  52.883 1.728 52.981 45.096 ;
     RECT  52.883 0.096 53.561 0.504 ;
     RECT  51.509 47.04 53.665 47.592 ;
     RECT  51.473 48.768 53.665 79.8 ;
     RECT  53.561 0.144 53.699 0.504 ;
     RECT  53.665 47.04 53.701 79.8 ;
     RECT  53.701 47.04 53.881 80.376 ;
     RECT  53.881 46.992 53.957 80.376 ;
     RECT  53.699 0.192 53.989 0.504 ;
     RECT  53.957 46.992 54.029 79.8 ;
     RECT  53.845 81.888 54.035 81.912 ;
     RECT  53.989 0.192 54.131 0.552 ;
     RECT  54.131 0.288 54.179 0.408 ;
     RECT  54.179 0.288 54.275 0.312 ;
     RECT  52.981 1.728 54.389 45.912 ;
     RECT  54.389 1.776 54.469 45.912 ;
     RECT  54.469 1.776 54.709 45.96 ;
     RECT  54.029 46.992 54.709 47.688 ;
     RECT  54.029 48.768 55.141 79.8 ;
     RECT  55.141 48.768 55.289 80.376 ;
     RECT  54.709 1.776 56.408 47.688 ;
     RECT  55.289 48.768 56.408 79.848 ;
     RECT  54.661 81.936 56.485 81.96 ;
     RECT  56.408 1.776 56.581 79.932 ;
     RECT  56.485 81.696 56.585 81.96 ;
     RECT  56.585 81.696 56.677 81.912 ;
     RECT  56.581 1.776 56.704 80.376 ;
     RECT  56.677 81.6 56.867 81.912 ;
     RECT  56.867 81.84 56.963 81.912 ;
     RECT  56.704 48.768 57.107 80.376 ;
     RECT  57.107 49.776 57.233 80.376 ;
     RECT  56.704 1.776 57.449 47.592 ;
     RECT  56.963 81.888 57.949 81.912 ;
     RECT  57.949 80.928 58.201 81.912 ;
     RECT  57.449 45.936 58.549 47.592 ;
     RECT  57.107 48.768 58.549 48.792 ;
     RECT  58.549 45.936 58.597 48.792 ;
     RECT  57.233 49.776 58.597 79.896 ;
     RECT  58.597 45.936 58.741 79.896 ;
     RECT  57.449 1.776 58.817 44.76 ;
     RECT  58.201 80.928 58.835 81.96 ;
     RECT  58.741 45.792 58.885 79.896 ;
     RECT  58.885 45.792 58.931 80.376 ;
     RECT  58.835 81.696 59.603 81.96 ;
     RECT  58.817 1.968 59.605 44.76 ;
     RECT  58.931 45.792 59.605 79.8 ;
     RECT  59.603 81.696 59.747 81.912 ;
     RECT  59.747 81.744 59.789 81.912 ;
     RECT  59.789 81.792 59.795 81.912 ;
     RECT  59.795 81.888 60.131 81.912 ;
     RECT  59.605 1.968 60.613 79.8 ;
     RECT  60.613 1.968 60.689 80.376 ;
     RECT  60.689 1.968 61.669 79.848 ;
     RECT  61.669 1.968 62.057 80.376 ;
     RECT  61.621 81.888 62.099 81.912 ;
     RECT  62.057 1.968 62.165 80.088 ;
     RECT  62.165 1.968 62.741 79.8 ;
     RECT  62.741 2.016 62.849 79.8 ;
     RECT  62.849 2.016 63.173 70.104 ;
     RECT  63.397 81.888 63.421 81.912 ;
     RECT  63.421 81.744 63.461 81.912 ;
     RECT  62.849 71.28 63.827 79.8 ;
     RECT  63.173 2.016 63.857 70.056 ;
     RECT  63.857 2.016 63.929 62.712 ;
     RECT  63.857 63.792 64.001 70.056 ;
     RECT  64.001 67.104 64.397 70.056 ;
     RECT  63.461 81.744 64.501 81.864 ;
     RECT  64.501 81.744 64.717 81.912 ;
     RECT  64.717 81.744 64.861 81.96 ;
     RECT  63.929 2.016 64.865 3.864 ;
     RECT  64.861 81.648 64.931 81.96 ;
     RECT  64.865 2.112 64.933 3.864 ;
     RECT  63.929 5.184 64.933 62.712 ;
     RECT  63.827 71.328 64.973 79.8 ;
     RECT  64.933 5.136 64.979 62.712 ;
     RECT  64.001 63.792 65.009 65.736 ;
     RECT  64.979 5.184 65.297 62.712 ;
     RECT  64.397 67.248 65.329 70.056 ;
     RECT  64.973 71.952 65.405 79.8 ;
     RECT  65.297 48.384 65.581 62.712 ;
     RECT  65.009 63.936 65.617 65.736 ;
     RECT  65.329 67.248 65.617 70.872 ;
     RECT  64.933 2.112 65.941 3.96 ;
     RECT  65.297 5.184 65.941 47.4 ;
     RECT  65.405 72.24 65.981 79.8 ;
     RECT  65.581 48.384 65.989 62.76 ;
     RECT  64.931 81.936 66.269 81.96 ;
     RECT  65.989 48.384 66.277 62.808 ;
     RECT  65.617 63.936 66.277 70.872 ;
     RECT  65.941 2.112 66.373 47.4 ;
     RECT  66.277 48.384 66.373 70.872 ;
     RECT  66.373 2.112 66.661 70.872 ;
     RECT  66.661 2.112 66.953 71.064 ;
     RECT  66.953 2.148 67.093 71.064 ;
     RECT  65.981 72.24 67.093 79.752 ;
     RECT  67.093 2.148 67.208 79.752 ;
     RECT  67.208 2.148 67.312 79.932 ;
     RECT  67.312 2.16 67.565 79.752 ;
     RECT  67.565 2.16 67.715 79.608 ;
     RECT  67.715 2.16 67.811 76.536 ;
     RECT  67.811 6.288 67.997 76.536 ;
     RECT  67.811 2.16 68.771 5.256 ;
     RECT  67.997 6.288 68.917 76.392 ;
     RECT  68.917 6.24 69.013 76.392 ;
     RECT  67.715 77.52 69.013 79.608 ;
     RECT  68.771 2.16 69.077 3.432 ;
     RECT  68.771 4.464 69.325 5.256 ;
     RECT  69.013 6.24 69.325 79.608 ;
     RECT  69.077 2.64 69.757 3.432 ;
     RECT  69.325 4.464 69.757 79.608 ;
     RECT  69.757 2.64 70.153 79.608 ;
     RECT  70.153 2.592 70.549 79.608 ;
     RECT  70.549 2.256 71.267 79.608 ;
     RECT  71.267 2.784 72.469 79.608 ;
     RECT  72.469 2.784 72.608 79.656 ;
     RECT  72.608 2.148 72.712 79.932 ;
     RECT  72.712 2.418 72.904 79.704 ;
     RECT  72.904 3.408 73.325 9.144 ;
     RECT  72.904 10.128 74.081 79.704 ;
     RECT  73.325 4.32 74.401 9.144 ;
     RECT  74.081 10.128 74.401 17.688 ;
     RECT  74.081 18.672 74.401 79.704 ;
     RECT  74.401 4.32 74.801 17.688 ;
     RECT  74.801 4.512 75.121 17.688 ;
     RECT  74.401 18.672 75.121 79.752 ;
     RECT  75.121 4.512 75.521 79.752 ;
     RECT  75.521 4.512 75.701 79.704 ;
     RECT  75.701 4.656 76.645 79.704 ;
     RECT  76.645 4.656 76.693 80.136 ;
     RECT  76.693 4.656 76.781 80.328 ;
     RECT  76.781 5.04 78.008 80.328 ;
     RECT  78.008 2.148 78.112 80.328 ;
     RECT  78.112 2.418 78.304 80.328 ;
     RECT  78.304 5.04 78.421 80.328 ;
     RECT  78.421 5.04 78.709 80.424 ;
     RECT  78.709 5.04 79.013 80.52 ;
     RECT  79.013 5.04 79.265 10.296 ;
     RECT  79.013 11.424 79.337 80.52 ;
     RECT  79.337 11.472 79.445 80.52 ;
     RECT  79.265 5.04 79.477 5.592 ;
     RECT  79.477 4.8 79.553 5.592 ;
     RECT  79.265 7.152 79.553 10.296 ;
     RECT  79.553 5.568 79.589 5.592 ;
     RECT  79.445 11.952 79.667 80.52 ;
     RECT  79.667 11.952 79.715 20.76 ;
     RECT  79.667 21.744 79.715 80.52 ;
     RECT  79.715 11.952 79.733 20.664 ;
     RECT  79.715 22.224 79.733 34.296 ;
     RECT  79.715 35.568 79.733 80.52 ;
     RECT  79.733 35.568 79.763 44.712 ;
     RECT  79.733 45.792 79.769 80.52 ;
     RECT  79.733 24.096 79.805 31.944 ;
     RECT  79.733 33.168 79.805 34.248 ;
     RECT  79.769 45.792 79.805 57.144 ;
     RECT  79.733 12.048 79.811 20.664 ;
     RECT  79.805 30.24 79.811 31.944 ;
     RECT  79.805 33.84 79.811 34.248 ;
     RECT  79.805 45.792 79.811 53.304 ;
     RECT  79.805 24.096 80.099 29.064 ;
     RECT  79.811 46.08 80.099 53.304 ;
     RECT  79.733 22.224 80.195 22.248 ;
     RECT  80.099 24.48 80.195 29.064 ;
     RECT  79.763 35.616 80.195 44.712 ;
     RECT  79.811 12.72 80.243 19.992 ;
     RECT  79.811 30.24 80.243 31.176 ;
     RECT  80.099 46.512 80.243 53.304 ;
     RECT  80.243 12.72 80.291 19.56 ;
     RECT  80.195 25.056 80.291 29.064 ;
     RECT  80.195 35.616 80.291 43.464 ;
     RECT  80.291 12.72 80.339 19.416 ;
     RECT  80.291 25.344 80.339 29.064 ;
     RECT  80.243 46.512 80.339 52.248 ;
     RECT  80.339 25.632 80.387 29.064 ;
     RECT  80.243 30.24 80.387 31.08 ;
     RECT  79.811 33.84 80.387 33.864 ;
     RECT  79.805 54.48 80.387 57.144 ;
     RECT  80.387 54.48 80.483 57 ;
     RECT  80.243 53.28 80.579 53.304 ;
     RECT  80.291 35.808 80.627 43.464 ;
     RECT  80.627 38.544 80.771 43.464 ;
     RECT  80.627 35.808 80.819 37.56 ;
     RECT  80.819 36.048 80.867 37.56 ;
     RECT  80.195 44.688 80.867 44.712 ;
     RECT  80.339 46.512 80.867 51.864 ;
     RECT  80.867 36.048 80.915 36.072 ;
     RECT  80.771 39.12 80.915 43.464 ;
     RECT  80.867 46.848 80.915 51.864 ;
     RECT  79.553 7.152 80.953 9.864 ;
     RECT  80.867 37.536 80.963 37.56 ;
     RECT  80.915 47.28 80.963 51.864 ;
     RECT  79.769 58.128 81.251 80.52 ;
     RECT  80.963 48.096 81.347 51.864 ;
     RECT  80.483 54.672 81.443 57 ;
     RECT  80.387 26.16 81.457 29.064 ;
     RECT  81.443 54.672 81.457 56.808 ;
     RECT  80.915 39.12 81.491 42.84 ;
     RECT  81.457 54.576 81.491 56.808 ;
     RECT  80.339 12.72 81.929 19.128 ;
     RECT  81.491 54.576 81.961 56.04 ;
     RECT  81.347 48.096 81.965 51.336 ;
     RECT  81.929 12.72 82.001 19.08 ;
     RECT  81.965 48.24 82.001 51.336 ;
     RECT  80.953 6.864 82.044 9.864 ;
     RECT  82.001 13.008 82.044 19.08 ;
     RECT  81.457 26.064 82.044 29.064 ;
     RECT  81.491 39.12 82.044 42.12 ;
     RECT  82.001 48.336 82.044 51.336 ;
     RECT  81.961 54.48 82.044 56.04 ;
     RECT  81.251 58.32 82.044 80.52 ;
    LAYER M5 ;
     RECT  0.72 0.016 54.408 1.765 ;
     RECT  0.72 1.765 55.272 2.101 ;
     RECT  0.72 2.101 55.896 2.137 ;
     RECT  0.72 2.137 56.52 2.151 ;
     RECT  61.8 2.137 61.92 2.151 ;
     RECT  67.2 2.137 67.32 2.151 ;
     RECT  72.6 2.137 72.72 2.151 ;
     RECT  78 2.137 78.12 2.151 ;
     RECT  61.8 2.151 62.112 2.197 ;
     RECT  0.72 2.151 56.712 2.245 ;
     RECT  58.032 2.149 58.056 2.245 ;
     RECT  59.424 2.197 59.448 2.245 ;
     RECT  61.584 2.197 62.112 2.245 ;
     RECT  64.896 2.101 64.92 2.245 ;
     RECT  67.2 2.151 67.512 2.245 ;
     RECT  70.56 2.245 71.256 2.581 ;
     RECT  68.832 2.197 68.856 2.629 ;
     RECT  70.176 2.581 71.256 2.629 ;
     RECT  0.72 2.245 59.448 2.677 ;
     RECT  67.2 2.245 67.752 2.677 ;
     RECT  0.72 2.677 59.832 2.725 ;
     RECT  61.584 2.245 62.664 2.725 ;
     RECT  66.096 2.677 66.12 2.725 ;
     RECT  67.2 2.677 67.8 2.725 ;
     RECT  68.832 2.629 71.256 2.773 ;
     RECT  72.6 2.151 72.912 2.773 ;
     RECT  0.72 2.725 62.664 2.867 ;
     RECT  0.72 2.867 60.264 3.491 ;
     RECT  64.896 2.245 64.968 3.541 ;
     RECT  66.096 2.725 67.8 3.541 ;
     RECT  64.896 3.541 67.8 3.733 ;
     RECT  64.656 3.733 67.8 3.829 ;
     RECT  68.832 2.773 72.912 3.829 ;
     RECT  61.584 2.867 62.664 3.925 ;
     RECT  61.296 3.925 63.144 4.261 ;
     RECT  0.816 3.491 60.264 4.595 ;
     RECT  60.24 4.595 60.264 4.643 ;
     RECT  64.512 3.829 72.912 4.645 ;
     RECT  75.216 4.501 75.672 4.837 ;
     RECT  78 2.151 78.312 5.029 ;
     RECT  79.488 4.789 79.512 5.029 ;
     RECT  64.512 4.645 73.416 5.077 ;
     RECT  74.64 4.837 75.672 5.077 ;
     RECT  64.512 5.077 75.816 5.125 ;
     RECT  64.512 5.125 76.056 5.267 ;
     RECT  61.296 4.261 63.24 5.365 ;
     RECT  77.904 5.029 79.512 5.365 ;
     RECT  69.408 5.267 76.056 5.653 ;
     RECT  77.136 5.365 79.512 5.653 ;
     RECT  64.512 5.267 67.8 5.747 ;
     RECT  0.816 4.595 59.208 5.893 ;
     RECT  60.336 5.365 63.24 6.037 ;
     RECT  69.408 5.653 79.512 6.229 ;
     RECT  64.896 5.747 67.8 6.805 ;
     RECT  0.816 5.893 59.256 7.093 ;
     RECT  60.336 6.037 63.816 7.093 ;
     RECT  0.816 7.093 63.816 7.237 ;
     RECT  64.848 6.805 67.8 7.237 ;
     RECT  68.928 6.229 79.512 7.381 ;
     RECT  0.816 7.237 67.8 7.475 ;
     RECT  68.832 7.381 79.512 7.475 ;
     RECT  1.152 7.475 67.8 7.861 ;
     RECT  68.832 7.475 79.368 7.861 ;
     RECT  1.152 7.861 79.368 8.243 ;
     RECT  64.848 8.243 79.368 8.869 ;
     RECT  1.152 8.243 63.816 9.253 ;
     RECT  64.848 8.869 79.8 9.253 ;
     RECT  1.152 9.253 79.8 11.027 ;
     RECT  1.296 11.027 79.8 12.083 ;
     RECT  1.296 12.083 79.752 13.045 ;
     RECT  1.296 13.045 79.8 14.099 ;
     RECT  81.888 13.957 81.912 14.147 ;
     RECT  1.296 14.099 79.752 14.675 ;
     RECT  81.888 15.589 81.912 15.779 ;
     RECT  1.296 14.675 79.656 16.165 ;
     RECT  1.296 16.165 80.328 17.317 ;
     RECT  1.296 17.317 80.376 18.851 ;
     RECT  1.296 18.851 80.328 19.427 ;
     RECT  1.296 19.427 80.28 19.571 ;
     RECT  1.296 19.571 80.232 20.003 ;
     RECT  1.296 20.003 80.184 22.259 ;
     RECT  1.296 22.259 80.088 23.075 ;
     RECT  1.776 23.075 80.088 24.469 ;
     RECT  1.776 24.469 80.184 25.045 ;
     RECT  1.776 25.045 80.28 25.333 ;
     RECT  1.776 25.333 80.328 25.621 ;
     RECT  1.776 25.621 80.376 26.291 ;
     RECT  1.776 26.291 80.328 26.387 ;
     RECT  1.776 26.387 80.28 27.589 ;
     RECT  1.776 27.589 80.376 28.019 ;
     RECT  1.92 28.019 80.376 28.691 ;
     RECT  28.8 28.691 80.376 30.851 ;
     RECT  33.168 30.851 80.376 30.995 ;
     RECT  34.704 30.995 80.376 31.091 ;
     RECT  34.704 31.091 80.232 31.187 ;
     RECT  28.8 30.851 31.848 31.379 ;
     RECT  29.04 31.379 31.176 31.427 ;
     RECT  29.232 31.427 31.176 31.475 ;
     RECT  34.704 31.187 79.8 31.955 ;
     RECT  1.92 28.691 27.672 32.531 ;
     RECT  33.168 30.995 33.672 32.579 ;
     RECT  34.704 31.955 79.752 33.107 ;
     RECT  33.216 32.579 33.672 33.829 ;
     RECT  34.704 33.107 37.704 33.829 ;
     RECT  38.928 33.107 79.752 33.829 ;
     RECT  1.92 32.531 6.792 34.117 ;
     RECT  7.8 32.531 27.672 34.117 ;
     RECT  29.4 31.475 31.176 34.259 ;
     RECT  1.92 34.117 27.672 34.547 ;
     RECT  33.216 33.829 37.704 34.693 ;
     RECT  7.8 34.547 27.672 34.835 ;
     RECT  31.152 34.259 31.176 34.835 ;
     RECT  1.92 34.547 6.792 35.363 ;
     RECT  33.216 34.693 37.8 35.363 ;
     RECT  38.928 33.829 80.376 35.363 ;
     RECT  29.4 34.259 30.024 35.605 ;
     RECT  38.928 35.363 46.008 35.747 ;
     RECT  38.928 35.747 38.952 35.797 ;
     RECT  46.992 35.363 80.376 35.797 ;
     RECT  4.176 35.363 6.792 35.845 ;
     RECT  7.8 34.835 9.384 35.845 ;
     RECT  29.4 35.605 30.264 35.845 ;
     RECT  33.6 35.363 37.8 35.939 ;
     RECT  10.368 34.835 27.672 36.037 ;
     RECT  46.992 35.797 80.808 36.037 ;
     RECT  34.032 35.939 36.792 36.275 ;
     RECT  37.776 35.939 37.8 36.371 ;
     RECT  29.4 35.845 30.312 36.421 ;
     RECT  31.728 36.133 31.752 36.421 ;
     RECT  4.176 35.845 9.384 36.515 ;
     RECT  38.784 35.797 38.952 36.517 ;
     RECT  1.92 35.363 2.712 36.563 ;
     RECT  40.2 35.747 46.008 36.659 ;
     RECT  34.032 36.275 36.696 36.851 ;
     RECT  41.571 36.659 46.008 36.997 ;
     RECT  46.992 36.037 80.904 36.997 ;
     RECT  38.736 36.517 38.952 37.043 ;
     RECT  29.4 36.421 31.752 37.139 ;
     RECT  38.784 37.043 38.952 37.139 ;
     RECT  41.571 36.997 80.904 37.525 ;
     RECT  38.928 37.139 38.952 37.573 ;
     RECT  10.368 36.037 27.768 37.667 ;
     RECT  5.136 36.515 9.384 37.859 ;
     RECT  34.368 36.851 36.696 38.005 ;
     RECT  34.368 38.005 37.464 38.149 ;
     RECT  29.4 37.139 30.936 38.195 ;
     RECT  5.808 37.859 9.384 39.109 ;
     RECT  5.568 39.109 9.384 39.253 ;
     RECT  10.368 37.667 11.4 39.253 ;
     RECT  34.368 38.149 37.56 39.395 ;
     RECT  34.368 39.395 37.464 39.491 ;
     RECT  40.2 36.659 40.512 39.493 ;
     RECT  41.571 37.525 80.952 39.539 ;
     RECT  38.928 37.573 39 39.541 ;
     RECT  39.984 39.493 40.512 39.541 ;
     RECT  5.568 39.253 11.4 40.019 ;
     RECT  5.568 40.019 9.384 40.499 ;
     RECT  34.368 39.491 36.696 40.499 ;
     RECT  34.8 40.499 36.696 40.597 ;
     RECT  41.571 39.539 80.904 40.789 ;
     RECT  34.8 40.597 36.84 40.933 ;
     RECT  41.571 40.789 80.952 41.075 ;
     RECT  48.24 41.075 80.952 41.123 ;
     RECT  41.571 41.075 47.016 41.125 ;
     RECT  11.04 40.019 11.4 41.269 ;
     RECT  48.336 41.123 80.952 41.315 ;
     RECT  5.808 40.499 9.192 41.459 ;
     RECT  34.8 40.933 37.608 41.749 ;
     RECT  38.928 39.541 40.512 41.797 ;
     RECT  41.568 41.125 47.016 41.797 ;
     RECT  48.432 41.315 80.952 41.797 ;
     RECT  10.656 41.269 11.4 41.987 ;
     RECT  34.8 41.749 37.848 41.989 ;
     RECT  34.704 41.989 37.848 42.227 ;
     RECT  12.864 37.667 27.768 42.469 ;
     RECT  38.928 41.797 47.016 42.709 ;
     RECT  48.432 41.797 81.48 42.709 ;
     RECT  38.928 42.709 81.48 42.803 ;
     RECT  50.784 42.803 81.48 42.851 ;
     RECT  12.864 42.469 28.104 43.091 ;
     RECT  34.704 42.227 35.112 43.235 ;
     RECT  50.784 42.851 80.904 43.619 ;
     RECT  38.928 42.803 49.752 43.811 ;
     RECT  11.04 41.987 11.4 43.813 ;
     RECT  52.416 43.619 80.904 43.955 ;
     RECT  36.24 42.227 37.848 44.003 ;
     RECT  48.24 43.811 49.752 44.147 ;
     RECT  12.96 43.091 28.104 44.197 ;
     RECT  48.336 44.147 49.752 44.245 ;
     RECT  50.784 43.619 51.312 44.245 ;
     RECT  12.96 44.197 28.392 44.341 ;
     RECT  29.4 38.195 30.6 44.341 ;
     RECT  11.04 43.813 11.976 44.389 ;
     RECT  12.96 44.341 30.6 44.389 ;
     RECT  11.04 44.389 30.6 45.541 ;
     RECT  38.928 43.811 47.016 46.693 ;
     RECT  48.336 44.245 51.312 46.693 ;
     RECT  10.992 45.541 30.6 46.787 ;
     RECT  5.808 41.459 8.424 46.933 ;
     RECT  38.928 46.693 51.312 47.029 ;
     RECT  34.8 43.235 35.112 47.173 ;
     RECT  36.24 44.003 37.608 47.173 ;
     RECT  52.512 43.955 80.904 47.269 ;
     RECT  38.784 47.029 51.312 47.315 ;
     RECT  11.04 46.787 30.6 47.411 ;
     RECT  4.848 46.933 8.424 47.557 ;
     RECT  38.784 47.315 49.752 47.603 ;
     RECT  4.848 47.557 8.568 47.653 ;
     RECT  51 47.315 51.312 47.893 ;
     RECT  48.336 47.603 49.752 47.939 ;
     RECT  2.4 36.563 2.712 48.229 ;
     RECT  11.04 47.411 29.832 48.515 ;
     RECT  32.544 46.789 32.568 48.515 ;
     RECT  52.512 47.269 80.952 48.661 ;
     RECT  4.848 47.653 9.048 48.803 ;
     RECT  34.8 47.173 37.608 48.899 ;
     RECT  38.784 47.603 47.016 49.091 ;
     RECT  38.784 49.091 46.2 49.235 ;
     RECT  51 47.893 51.432 49.235 ;
     RECT  52.512 48.661 81.192 49.283 ;
     RECT  7.8 48.803 9.048 49.285 ;
     RECT  48.336 47.939 48.36 49.619 ;
     RECT  2.4 48.229 2.904 49.715 ;
     RECT  4.848 48.803 6.744 49.765 ;
     RECT  7.8 49.285 9.096 49.765 ;
     RECT  49.728 47.939 49.752 49.765 ;
     RECT  49.728 49.765 49.896 49.811 ;
     RECT  49.872 49.811 49.896 50.101 ;
     RECT  49.872 50.101 49.992 50.147 ;
     RECT  49.968 50.147 49.992 50.291 ;
     RECT  51 49.235 51.312 50.293 ;
     RECT  52.512 49.283 58.392 50.293 ;
     RECT  4.848 49.765 9.096 50.339 ;
     RECT  51 50.293 58.392 50.627 ;
     RECT  6.24 50.339 9.096 51.203 ;
     RECT  11.04 48.515 29.712 51.491 ;
     RECT  11.04 51.491 28.152 51.587 ;
     RECT  34.8 48.899 35.112 51.637 ;
     RECT  59.376 49.283 81.192 51.829 ;
     RECT  6.24 51.203 6.744 51.923 ;
     RECT  11.04 51.587 27.768 51.971 ;
     RECT  48.528 50.821 48.552 51.973 ;
     RECT  34.512 51.637 35.112 52.213 ;
     RECT  36.24 48.899 37.608 52.213 ;
     RECT  48.048 51.973 48.552 52.309 ;
     RECT  34.512 52.213 37.608 52.355 ;
     RECT  6.672 51.923 6.744 52.405 ;
     RECT  7.8 51.203 9.096 52.405 ;
     RECT  36.096 52.355 37.608 52.405 ;
     RECT  47.28 52.309 48.552 52.405 ;
     RECT  55.344 50.627 58.392 52.405 ;
     RECT  59.376 51.829 81.336 52.405 ;
     RECT  4.848 50.339 5.016 52.499 ;
     RECT  34.512 52.355 35.112 52.741 ;
     RECT  36.096 52.405 37.752 52.787 ;
     RECT  4.992 52.499 5.016 52.837 ;
     RECT  11.232 51.971 27.768 53.027 ;
     RECT  6.672 52.405 9.096 53.221 ;
     RECT  55.344 52.405 81.336 53.221 ;
     RECT  11.232 53.027 11.256 53.269 ;
     RECT  51 50.627 54.168 53.269 ;
     RECT  55.296 53.221 81.336 53.269 ;
     RECT  4.992 52.837 5.208 53.365 ;
     RECT  6.672 53.221 9.864 53.365 ;
     RECT  34.416 52.741 35.112 53.365 ;
     RECT  34.176 53.365 35.112 53.461 ;
     RECT  36.096 52.787 37.608 53.461 ;
     RECT  29.4 51.491 29.712 53.557 ;
     RECT  47.28 52.405 48.984 53.557 ;
     RECT  47.28 53.557 49.656 53.843 ;
     RECT  34.176 53.461 37.608 53.893 ;
     RECT  38.928 49.235 46.2 53.893 ;
     RECT  47.28 53.843 49.128 53.893 ;
     RECT  34.176 53.893 49.128 54.373 ;
     RECT  3.792 52.981 3.816 54.611 ;
     RECT  12.288 53.027 27.528 54.611 ;
     RECT  34.128 54.373 49.128 54.613 ;
     RECT  33.696 54.613 49.128 54.661 ;
     RECT  51 53.269 81.336 54.757 ;
     RECT  50.88 54.757 81.48 54.901 ;
     RECT  50.688 54.901 81.48 55.091 ;
     RECT  4.992 53.365 9.864 55.139 ;
     RECT  33.312 54.661 49.128 55.525 ;
     RECT  33.312 55.525 49.608 55.811 ;
     RECT  50.736 55.091 81.48 55.861 ;
     RECT  28.8 53.557 29.712 55.907 ;
     RECT  50.736 55.861 81.912 56.051 ;
     RECT  4.992 55.139 9.384 56.293 ;
     RECT  3.84 54.661 3.864 56.341 ;
     RECT  49.392 55.811 49.608 56.341 ;
     RECT  50.736 56.051 81.48 56.341 ;
     RECT  11.088 53.269 11.256 56.389 ;
     RECT  12.288 54.611 26.664 56.389 ;
     RECT  4.992 56.293 9.912 56.869 ;
     RECT  11.088 56.389 26.664 56.869 ;
     RECT  4.992 56.869 26.664 56.915 ;
     RECT  33.312 55.811 48.264 56.965 ;
     RECT  33.264 56.965 48.264 57.109 ;
     RECT  49.392 56.341 81.48 57.109 ;
     RECT  4.992 56.915 6.696 57.155 ;
     RECT  3.84 56.341 3.96 57.635 ;
     RECT  33.264 57.109 81.48 57.971 ;
     RECT  5.424 57.155 6.696 58.117 ;
     RECT  7.68 56.915 26.664 58.117 ;
     RECT  29.4 55.907 29.712 58.117 ;
     RECT  5.424 58.117 26.664 58.163 ;
     RECT  32.256 50.341 32.28 58.213 ;
     RECT  33.264 57.971 47.928 58.213 ;
     RECT  5.424 58.163 26.472 58.549 ;
     RECT  5.328 58.549 26.472 58.643 ;
     RECT  25.824 58.643 26.472 58.787 ;
     RECT  48.912 57.971 81.48 58.931 ;
     RECT  3.84 57.635 3.864 58.981 ;
     RECT  5.328 58.643 24.84 58.981 ;
     RECT  3.84 58.981 24.84 59.027 ;
     RECT  32.256 58.213 47.928 59.075 ;
     RECT  48.912 58.931 81.432 59.075 ;
     RECT  28.608 58.117 29.712 59.461 ;
     RECT  28.608 59.461 30.312 59.605 ;
     RECT  4.752 59.027 24.84 59.891 ;
     RECT  28.608 59.605 30.648 59.939 ;
     RECT  25.824 58.787 25.848 60.275 ;
     RECT  29.4 59.939 30.648 60.275 ;
     RECT  48.96 59.075 81.432 60.371 ;
     RECT  32.256 59.075 47.832 60.373 ;
     RECT  31.872 60.373 47.832 60.901 ;
     RECT  4.752 59.891 9.96 60.949 ;
     RECT  30.816 60.901 47.832 61.427 ;
     RECT  30.816 61.427 30.84 61.571 ;
     RECT  11.088 59.891 24.84 61.619 ;
     RECT  31.872 61.427 47.832 61.669 ;
     RECT  48.96 60.371 81.288 61.669 ;
     RECT  4.56 60.949 9.96 62.005 ;
     RECT  11.088 61.619 16.2 62.005 ;
     RECT  2.4 49.715 2.712 62.149 ;
     RECT  31.872 61.669 81.288 62.581 ;
     RECT  31.392 62.581 81.288 62.771 ;
     RECT  2.4 62.149 3.432 63.011 ;
     RECT  17.424 61.619 24.84 63.011 ;
     RECT  32.256 62.771 81.288 63.731 ;
     RECT  32.256 63.731 81.24 63.923 ;
     RECT  29.4 60.275 29.712 64.069 ;
     RECT  4.56 62.005 16.2 64.309 ;
     RECT  4.56 64.309 16.584 64.451 ;
     RECT  32.256 63.923 80.808 64.451 ;
     RECT  29.4 64.069 30.6 64.837 ;
     RECT  65.808 64.451 80.808 65.363 ;
     RECT  65.808 65.363 79.992 65.459 ;
     RECT  4.56 64.451 5.448 65.651 ;
     RECT  7.536 64.451 16.584 65.699 ;
     RECT  32.256 64.451 64.68 65.747 ;
     RECT  29.4 64.837 31.032 66.037 ;
     RECT  27.36 66.133 27.384 66.325 ;
     RECT  28.464 66.037 31.032 66.325 ;
     RECT  27.36 66.325 31.032 66.563 ;
     RECT  29.28 66.563 31.032 67.139 ;
     RECT  65.808 65.459 79.8 67.283 ;
     RECT  7.536 65.699 16.2 67.331 ;
     RECT  32.256 65.747 64.392 67.379 ;
     RECT  27.36 66.563 27.768 67.811 ;
     RECT  29.28 67.139 30.6 67.811 ;
     RECT  29.28 67.811 29.712 68.147 ;
     RECT  5.328 65.651 5.448 68.485 ;
     RECT  17.712 63.011 24.84 68.965 ;
     RECT  30.96 68.965 30.984 69.013 ;
     RECT  17.712 68.965 25.128 69.299 ;
     RECT  30.96 69.013 31.08 69.301 ;
     RECT  32.256 67.379 64.152 69.301 ;
     RECT  30.96 69.301 64.152 69.347 ;
     RECT  31.056 69.347 64.152 69.395 ;
     RECT  5.328 68.485 5.592 69.493 ;
     RECT  65.808 67.283 79.608 69.493 ;
     RECT  65.808 69.493 79.8 70.643 ;
     RECT  31.152 69.395 64.152 70.787 ;
     RECT  31.344 70.787 64.152 70.835 ;
     RECT  5.088 69.493 5.592 71.315 ;
     RECT  65.808 70.643 79.752 71.699 ;
     RECT  7.584 67.331 16.2 71.797 ;
     RECT  65.808 71.699 79.176 71.843 ;
     RECT  32.256 70.835 64.152 72.037 ;
     RECT  32.256 72.037 64.248 72.181 ;
     RECT  27.744 67.811 27.768 72.515 ;
     RECT  31.872 72.181 64.248 72.709 ;
     RECT  65.808 71.843 79.128 72.709 ;
     RECT  81.888 72.565 81.912 72.755 ;
     RECT  31.872 72.709 79.128 72.805 ;
     RECT  5.328 71.315 5.592 72.901 ;
     RECT  6.816 71.797 16.2 72.901 ;
     RECT  6.768 72.901 16.2 72.995 ;
     RECT  29.4 68.147 29.712 72.997 ;
     RECT  29.4 72.997 30.552 73.235 ;
     RECT  31.872 72.805 79.8 73.331 ;
     RECT  5.328 72.901 5.784 73.477 ;
     RECT  32.256 73.331 79.8 73.571 ;
     RECT  5.088 73.477 5.784 73.765 ;
     RECT  6.768 72.995 14.376 73.765 ;
     RECT  32.256 73.571 64.824 73.907 ;
     RECT  5.088 73.765 14.376 73.957 ;
     RECT  15.552 72.995 16.2 73.957 ;
     RECT  17.712 69.299 24.648 74.053 ;
     RECT  30.768 73.669 30.792 74.147 ;
     RECT  65.904 73.571 79.8 74.147 ;
     RECT  17.712 74.053 24.984 74.149 ;
     RECT  5.088 73.957 16.2 74.293 ;
     RECT  17.52 74.149 24.984 74.293 ;
     RECT  29.4 73.235 29.712 74.437 ;
     RECT  32.736 73.907 64.824 74.581 ;
     RECT  65.904 74.147 79.752 74.581 ;
     RECT  32.736 74.581 79.752 75.061 ;
     RECT  5.088 74.293 24.984 75.157 ;
     RECT  26.256 75.013 26.28 75.157 ;
     RECT  32.4 75.061 79.752 75.205 ;
     RECT  5.088 75.157 26.28 75.539 ;
     RECT  28.8 74.437 29.712 75.779 ;
     RECT  29.088 75.779 29.712 75.971 ;
     RECT  32.4 75.205 79.8 76.403 ;
     RECT  32.4 76.403 79.752 76.451 ;
     RECT  81.888 76.405 81.912 76.595 ;
     RECT  5.76 75.539 26.28 76.789 ;
     RECT  5.04 76.789 26.28 76.837 ;
     RECT  5.04 76.837 26.424 76.885 ;
     RECT  37.872 76.451 79.752 76.979 ;
     RECT  5.04 76.885 26.76 76.981 ;
     RECT  31.104 76.069 31.128 77.027 ;
     RECT  29.4 75.971 29.712 77.077 ;
     RECT  32.4 76.451 36.744 77.413 ;
     RECT  37.872 76.979 78.648 77.413 ;
     RECT  31.2 77.413 36.744 77.701 ;
     RECT  37.776 77.413 78.648 77.701 ;
     RECT  5.04 76.981 27.24 77.845 ;
     RECT  5.04 77.845 27.336 77.987 ;
     RECT  31.2 77.701 78.648 78.037 ;
     RECT  79.728 76.979 79.752 78.037 ;
     RECT  5.088 77.987 27.336 78.469 ;
     RECT  29.4 77.077 30.216 78.517 ;
     RECT  31.2 78.037 79.8 78.851 ;
     RECT  75.552 78.851 79.8 78.995 ;
     RECT  75.552 78.995 79.704 79.091 ;
     RECT  75.744 79.091 79.704 79.187 ;
     RECT  5.088 78.469 27.912 79.283 ;
     RECT  29.136 78.517 30.216 79.283 ;
     RECT  31.2 78.851 74.088 79.283 ;
     RECT  5.664 79.283 13.512 79.331 ;
     RECT  14.544 79.283 27.912 79.331 ;
     RECT  32.208 79.283 74.088 79.331 ;
     RECT  6.576 79.331 13.512 79.427 ;
     RECT  32.208 79.331 71.256 79.427 ;
     RECT  72.384 79.331 74.04 79.427 ;
     RECT  75.744 79.187 79.608 79.427 ;
     RECT  32.208 79.427 70.872 79.475 ;
     RECT  76.656 79.427 79.608 79.475 ;
     RECT  7.8 79.427 13.512 79.523 ;
     RECT  32.352 79.475 67.944 79.523 ;
     RECT  69.312 79.475 70.056 79.523 ;
     RECT  76.656 79.475 76.872 79.523 ;
     RECT  29.136 79.283 29.712 79.525 ;
     RECT  32.352 79.523 67.608 79.571 ;
     RECT  69.312 79.523 69.336 79.571 ;
     RECT  72.384 79.427 73.512 79.571 ;
     RECT  77.904 79.475 78.744 79.571 ;
     RECT  6.576 79.427 6.6 79.619 ;
     RECT  31.2 79.283 31.224 79.619 ;
     RECT  72.48 79.571 73.512 79.667 ;
     RECT  29.04 79.525 29.712 79.715 ;
     RECT  72.6 79.667 73.512 79.715 ;
     RECT  7.8 79.523 11.64 79.763 ;
     RECT  32.352 79.571 67.512 79.763 ;
     RECT  29.136 79.715 29.712 79.811 ;
     RECT  32.352 79.763 65.928 79.811 ;
     RECT  2.4 63.011 2.712 79.929 ;
     RECT  13.2 79.523 13.512 79.929 ;
     RECT  29.4 79.811 29.712 79.929 ;
     RECT  67.2 79.763 67.512 79.929 ;
     RECT  72.6 79.715 72.912 79.929 ;
     RECT  2.4 79.929 2.52 79.943 ;
     RECT  7.8 79.763 11.304 79.943 ;
     RECT  13.2 79.929 13.32 79.943 ;
     RECT  14.544 79.331 27.336 79.943 ;
     RECT  29.4 79.929 29.52 79.943 ;
     RECT  67.2 79.929 67.32 79.943 ;
     RECT  72.6 79.929 72.72 79.943 ;
     RECT  78 79.571 78.744 79.943 ;
     RECT  14.544 79.943 18.312 80.099 ;
     RECT  76.656 79.523 76.728 80.147 ;
     RECT  76.704 80.147 76.728 80.339 ;
     RECT  78.432 79.943 78.744 80.435 ;
     RECT  78.72 80.435 78.744 80.531 ;
     RECT  19.488 79.943 27.336 81.493 ;
     RECT  19.488 81.493 27.528 81.539 ;
     RECT  8.4 79.943 11.304 81.925 ;
     RECT  14.544 80.099 17.448 81.925 ;
     RECT  8.4 81.925 11.4 82.064 ;
     RECT  14.544 81.925 17.544 82.064 ;
     RECT  19.536 81.539 27.528 82.064 ;
     RECT  33.744 79.811 65.928 82.064 ;
     RECT  43.632 82.064 43.656 82.067 ;
  END
END ot_pqc_t_ret
END LIBRARY
